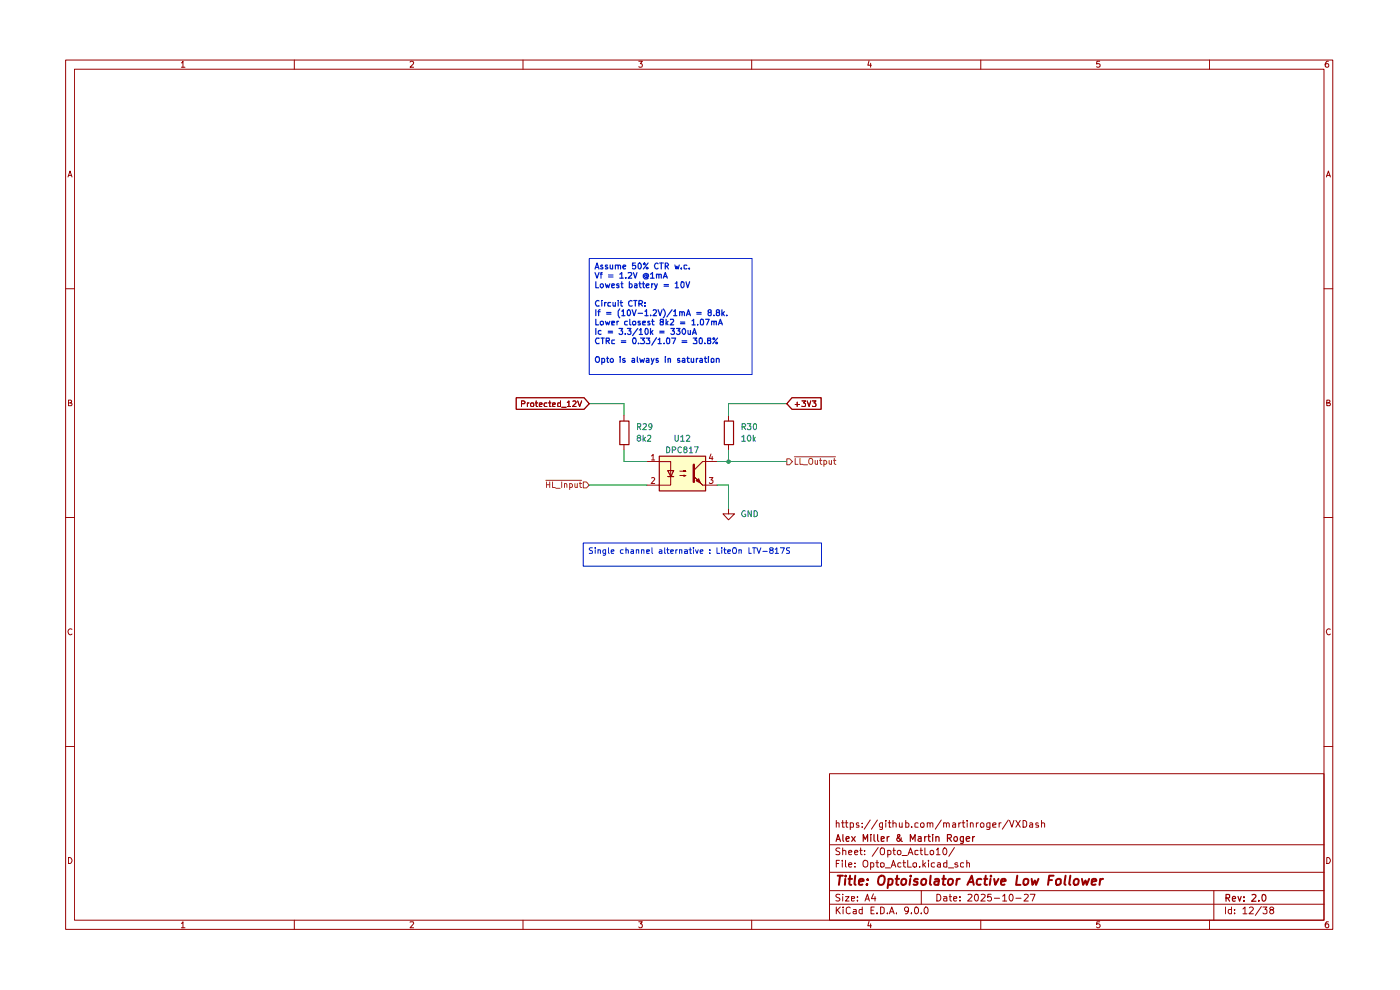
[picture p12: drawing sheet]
<svg xmlns="http://www.w3.org/2000/svg" width="297mm" height="210mm" viewBox="0 0 297 210" stroke-linecap="round" stroke-linejoin="round" font-family="sans-serif">
<g fill="none" stroke="#980000" stroke-width=".21">
<path d="M13.9 12.7h268.8v184.4h-268.8zM15.8 14.7h265.1v180.5h-265.1zM38.5 13.3h.1l.2-.3v1.3M38.5 14.3h.7M62.4 12.7v2M87 13.2l.5-.2 .3 .2-.1 .4-.7 .7h.8M111 12.7v2M135.5 13h.8l-.5 .5 .4 .1v.6h-.7M159.5 12.7v2M184.4 12.9l-.3 .9h.8M184.7 13.4v.9M208.1 12.7v2"/>
<path d="M233.3 13h-.6l-.1 .6h.7v.6h-.7M256.6 12.7v2M281.8 13a.71 .71 0 0 0-.7 .5 .71 .71 0 0 0 .3 .8l.4-.1v-.6l-.4-.1-.3 .3M14.4 37.5l.5-1.2 .4 1.2M14.5 37.2h.7M281.4 37.5l.4-1.2 .4 1.2M281.5 37.2h.6M13.9 61.3h1.9M280.9 61.3h1.8M14.5 85.5h.4l.3-.3-.2-.3h-.5v1.2h.6l.2-.5-.4-.1M281.5 85.5h.4l.2-.3-.1-.3h-.5v1.2h.6l.1-.5-.3-.1M13.9 109.8h1.9"/>
<path d="M280.9 109.8h1.8M15.3 133.5a.59 .59 0 0 0-.9 .5 .59 .59 0 0 0 .8 .6l.1-.1M282.2 133.5a.59 .59 0 0 0-.8 .5 .59 .59 0 0 0 .7 .6l.1-.1M13.9 158.4h1.9M280.9 158.4h1.8M176 164.1h104.9v31.1h-104.9zM176 179.2h104.9M177.4 174.7l.2-.2 .4 .1v.9M177.4 174v1.5M178.2 180l-.6-.1-.3 .2 .1 .4 .8 .4-.1 .3h-.8M178.5 174.5h.6M178.8 174v1.5h.3"/>
<path d="M178.8 179.9v1.4M179.4 174.5h.5M179.5 174v1.3l.1 .2h.3M180.4 174.6l.4-.1 .3 .2v.7l-.7 .1M180.4 174.5v1.5M182.2 174.6l-.4-.1-.2 .2 .2 .3h.4v.5h-.6M182.6 179.9v1.2l.3 .2M182.9 175.4v.1M182.9 174.6v.1M184.6 173.9l-1.3 2M186.1 173.9l-1.2 2M186.3 179.8l-1.3 1.8"/>
<path d="M186.9 180l.4-.1 .3 .1 .1 .8-.1 .3-.3 .2-.5-.2-.1-.7zM187.2 174.5v1.2a.36 .36 0 0 1-.6 .2M187.2 174.6l-.4-.1-.2 .3v.6l.6 .1M187.9 174v.2M187.9 174.5v1M188.4 174.5h.6M188.7 174v1.5h.3M189.4 174.7l.3-.2 .4 .2v.8M189.4 174v1.5M189.6 179.9v1.2l.3 .2M190.8 174.5l.1 1 .5-.1M191.4 174.5v1"/>
<path d="M192.1 174v1.5l.6-.1 .1-.6a.45 .45 0 0 0-.7-.2M193.4 175.4v.1M194.8 174.6l-.5-.1-.2 .2v.7l.7 .1M195.3 174.8a.45 .45 0 0 1 .7-.2v.9l-.6-.1zM195.4 179.9v1.2l.3 .2M196.2 179.9v1.4h.7M196.7 174.7l.2-.2 .4 .2v.8M196.7 174.5v1M197.3 174.7l.2-.2 .4 .1v.9M199.7 173.9l-1.3 2M200.2 180l.2-.1a.75 .75 0 0 1 .5 .7 .75 .75 0 0 1-.5 .7l-.4-.5zM200.2 174.7l.2-.2 .4 .2v.8"/>
<path d="M200.2 174.5v1M200.8 174.7l.2-.2 .4 .2v.8M202.1 174.6l.4-.1 .2 .2v.8h-.6v-.4l.6-.2M202.5 179.8l-1.2 1.8M203.4 174.5v1M203.8 174.5l-.4 .3M204.1 174.5h.6M204.3 174v1.3l.1 .2h.3M205.2 174v.2M205.2 174.5v1M205.9 174.7l.1-.2 .5 .2v.8M205.9 174.5v1"/>
<path d="M207.1 174.5v1M207.6 174.5l-.5 .3M208.2 174.5h.3l.2 .3-.1 .7h-.5l-.1-.3v-.4zM210 174.5v1.2l-.2 .3-.5-.1M210 174.6l-.4-.1-.3 .2v.7l.7 .1M210.6 175l.7-.1v-.3l-.4-.1-.3 .2 .1 .8h.6M212 174.5v1M212.4 174.5l-.4 .3M213.9 173.9l-1.3 2M214.2 174l.5 1.5 .4-1.5M215.5 174l.9 1.5M216.4 174l-.9 1.5"/>
<path d="M217 174h.4l.4 .4v.7l-.3 .4h-.5zM218.5 174.6l.4-.1 .2 .2v.8h-.6l-.1-.4 .7-.2M220.3 174.6h-.6v.4h.6v.2v.3h-.6M220.9 174.7l.3-.2 .4 .2v.8M220.9 174v1.5M14.5 181.9a.65 .65 0 0 1 .8 .6 .65 .65 0 0 1-.8 .7zM38.5 195.9l.3-.4v1.3M38.5 196.8h.7M62.4 195.2v1.9M87 195.6l.7-.1 .1 .3-.8 1h.8M111 195.2v1.9M135.5 195.5h.8l-.5 .5 .5 .2-.1 .5-.5 .1-.2-.2"/>
<path d="M159.5 195.2v1.9M176 191.8h104.9M176 188.9h104.9M176 185h104.9M177.4 192.4v1.4M177.4 183.2h.5M177.6 193l.7 .8M178.1 182.5h-.7v1.4M178.2 189.8h-.8l-.1 .3 .8 .4 .1 .4-.3 .2-.6-.1M178.3 192.4l-.9 .8M178.7 182.5v.2M178.7 183v.9"/>
<path d="M178.8 189.7v.1M178.8 180.5l.4-.1 .2 .1v.8M178.8 190.2v.9M178.9 192.4v.2M178.9 192.9v.9M179.4 190.2h.7l-.7 .9h.7M179.4 182.5v1.3l.1 .1M180 183.4l.7-.1-.2-.3-.5 .2v.6l.3 .1 .3-.1M180 180.8l.7-.1-.2-.3-.5 .1v.6l.3 .2 .3-.1M180.4 192.6l-.4-.2-.5 .3 .1 1 .4 .1 .4-.1M180.6 190.6l.7-.1-.1-.3h-.6v.8h.6M181.1 192.9h.5v.9"/>
<path d="M181.3 180.8l.7-.1-.2-.3h-.3l-.2 .1v.6l.2 .2 .4-.1M181.4 183.8v.1M181.4 183.1v.1M181.6 193.2l-.5 .1-.1 .2 .1 .3h.5M181.9 191v.1M181.9 190.2v.2M182.4 180.4h.5M182.9 192.9h-.5l-.2 .7a.45 .45 0 0 0 .7 .2M182.9 192.4v1.4M183.2 182.7l.5-.2a.75 .75 0 0 1 .4 .8 .75 .75 0 0 1-.7 .6l-.1-.1a.99 .99 0 0 1-.1-1.1zM183.4 181.2v.1M183.4 180.5h.1"/>
<path d="M183.5 191.1l.5-1.4 .4 1.4M183.7 190.7h.7M184.4 195.4l-.3 1h.8M184.7 183.1l.4-.1 .3 .3-.1 .5h-.6M184.7 183v1.4M184.7 196v.8M184.8 193.1h.5M185.3 189.6l-.4 1h.9M185.5 192.4h-.7v1.4h.7M185.6 190.2v.9M185.8 183h.6M186 193.7v.1"/>
<path d="M186 182.5v1.3l.4 .1M186.8 192.4h.4l.4 .3v.8l-.4 .3h-.4zM186.8 183.1h.7v.7h-.7zM187.8 184.1h1.1M188.3 193.7v.1M188.3 180.5l.4-.1 .3 .2-.1 .6h-.6M188.3 180.4v1.4M188.7 193.8l.5-1.4 .5 1.4M188.8 193.4h.7M189.1 183.9l.4-1.4 .5 1.4M189.2 183.5h.7M189.4 180.4h.5"/>
<path d="M190.2 193.7v.1M190.5 180.5h.5v.7h-.5zM191.1 183.1l-.4-.1-.2 .3v.5h.6M191.4 181.5h1.1M191.6 183h.5M191.7 182.5v1.3l.4 .1M192.6 182.5v1.4h.7M192.7 181.3l.5-1.4 .5 1.4M192.7 193l-.2 .3h-.4l-.2-.3v-.3l.2-.3h.4l.2 .3v.8l-.2 .3h-.4M192.8 180.9h.7M193.3 193.7v.1M193.8 183.1h.6v.7h-.6z"/>
<path d="M194.1 192.6l.2-.2a.75 .75 0 0 1 .6 .7 .75 .75 0 0 1-.6 .7l-.2-.1-.1-.4zM194.8 180.5h-.7v.7h.7M195.1 183.8v.1M195.2 180.4h.5M195.4 193.7v.1M195.4 188.9v2.9M195.8 182.5v1.4M196 183.4l.4 .5M196.4 192.4h.1a.8 .8 0 0 1 .4 .8 .8 .8 0 0 1-.5 .6 .89 .89 0 0 1 0-1.4zM196.4 183l-.6 .5M197 182.5v.2M197 183v.9"/>
<path d="M197.4 180.5h.6v.7h-.6zM198.2 183.1l-.3-.1-.3 .3v.5h.6M198.7 180.3l.3-.4v1.4M198.7 181.3h.7M198.7 189.7a.73 .73 0 0 1 .9 .7 .73 .73 0 0 1-.9 .7zM198.9 183.1l.4-.1 .2 .2v.7M199.5 183.3l-.6 .1-.1 .2 .2 .3 .5-.1M200.2 190.2h.6l.1 .9M200.9 190.5l-.7 .1v.4h.7M200.9 183.1h-.7v.7h.7M200.9 182.5v1.4M201.2 184.1h1.1"/>
<path d="M201.4 190.2h.5M201.5 189.7v1.3l.4 .1M202.3 190.6l.7-.1-.1-.3h-.5l-.1 .2v.6l.2 .1 .4-.1M203.2 183.1l-.4-.1-.2 .3v.1l.6 .1v.3l-.2 .1-.4-.1M203.7 191v.1M203.7 190.2v.2M204.4 183.1l-.4-.1-.3 .3 .1 .5h.6M205.1 183.1l.4-.1 .2 .2v.7M205.1 182.5v1.4M205.4 189.8l.5-.1 .3 .4-.9 1h.9M206.9 189.8h.5a1.01 1.01 0 0 1-.2 1.3 .87 .87 0 0 1-.3-1.3zM208.1 195.2v1.9"/>
<path d="M208.1 189.8h.8l.1 .3-.9 1h.9M210.3 189.7h-.7l-.1 .7 .6-.2 .2 .3v.4l-.2 .2-.6-.1M210.9 190.5h1.1M212.7 190.1l.4-.4v1.4M212.7 191.1h.9M214.2 189.8l.2-.1a.76 .76 0 0 1 .5 .7 .76 .76 0 0 1-.5 .7 1.01 1.01 0 0 1-.2-1.3zM215.5 190.5h1.1M217.3 189.8h.8v.3l-.9 1h.9M218.6 189.7h1l-.6 1.4M233.3 195.5h-.6l-.1 .6 .2-.1h.3l.3 .2v.3l-.3 .3h-.3l-.2-.2M256.6 195.2v1.9M257.5 188.9v6.3"/>
<path d="M260 192.4v1.4M261.2 192.9h-.5l-.1 .3v.4l.2 .2h.4M261.2 192.4v1.4M261.9 193.7v.1M261.9 192.9v.2M263.7 192.8l.4-.4v1.4M263.7 193.8h.8M265 192.6l.6-.2 .3 .4-.9 1h.9M267.6 192.3l-1.3 1.9M267.9 192.4h.9l-.5 .5 .5 .2v.6l-.3 .1h-.4l-.2-.1M269.6 193l-.2-.3 .2-.3 .6 .3-.1 .2-.2 .1a.47 .47 0 0 0-.5 .6l.2 .2a.45 .45 0 0 0 .5-.1 .45 .45 0 0 0 0-.5l-.2-.2M281.5 181.9a.65 .65 0 0 1 .7 .6 .65 .65 0 0 1-.7 .7z"/>
<path d="M281.8 195.5h-.4l-.3 .5v.5l.3 .3 .4-.1v-.7h-.4l-.3 .2"/>
</g>
<g fill="none" stroke="#980000" stroke-width=".25">
<path d="M177.4 178.5l.4-1.5 .5 1.5M177.5 178h.6M178.8 177v1.2l.2 .3M179.5 178l.7-.2-.2-.3h-.4l-.1 .7 .2 .3 .4-.1M180.7 177.5l.7 1M181.4 177.5l-.7 1M183.1 178.5v-1.5l.5 1 .5-1v1.5M184.7 177v.1M184.7 177.5v1M185.4 177v1.2l.3 .3M186.2 177v1.2l.2 .3M186.9 178l.7-.2-.1-.3h-.6v.9h.6"/>
<path d="M188.2 177.5v1M188.6 177.5l-.4 .3M191.2 177.7v.3l-.5 .5a.43 .43 0 0 1-.4-.2 .43 .43 0 0 1 0-.5l.6-.5-.1-.3h-.3a.55 .55 0 0 0 .2 .8l.7 .7M193.1 178.5v-1.5l.5 1 .5-1v1.5M194.8 177.5h.6v1M195.4 177.8l-.4 .1-.3 .2 .3 .4 .4-.1M196.2 177.5v1M196.5 177.5h-.2l-.1 .3M196.8 177.5h.6M197 177v1.2l.4 .3M197.9 177v.1M197.9 177.5v1"/>
<path d="M198.5 177.6l.1-.1a.36 .36 0 0 1 .6 .2v.8M198.5 177.5v1M201 177.8l.7-.1 .1-.2v-.4l-.8-.1v1.5M201.3 177.8l.5 .7M204.4 177.5v1.1l-.2 .3h-.4M204.4 177.5h-.4l-.3 .3 .1 .6h.6M205 178l.7-.2-.1-.3h-.4l-.2 .2 .1 .7h.5M206.3 177.5v1M206.8 177.5l-.5 .3M260.1 190.5l.7-.1 .1-.6-.8-.1v1.5M260.4 190.5l.5 .7M261.4 190.7l.7-.1-.1-.4h-.5l-.1 .7 .2 .3 .4-.1"/>
<path d="M262.6 190.2l.4 1 .3-1M263.9 191v.2M263.9 190.2v.2M265.6 189.8l.6-.1 .2 .5-.9 1h.9M267 191v.2M267.8 189.8l.2-.1a.75 .75 0 0 1 .6 .8 .75 .75 0 0 1-.6 .7l-.2-.2-.1-.4z"/>
<circle cx="202.7" cy="178" r=".48"/>
</g>
<g fill="none" stroke="#980000" stroke-width=".42">
<path d="M177.7 185.8h1.1M178.2 185.8l-.2 1.9M179.3 186.4l-.1 1.3M179.4 185.8v.1M180 186.4h.8M180.3 185.8l-.1 1.6 .4 .3M181.4 185.8l-.1 1.6 .2 .3M182.2 187l1-.1-.1-.4a.6 .6 0 0 0-.8 .2v.9h.7M184 187.5l-.1 .2-.1-.1 .2-.1-.1 .2M184.1 186.5v.2M186.5 186a.7 .7 0 0 1 1.1 0 1.36 1.36 0 0 1-.6 1.7l-.5-.1a1.33 1.33 0 0 1 0-1.6zM188.5 186.5a.6 .6 0 0 1 .9 .3l-.3 .8h-.7"/>
<path d="M188.5 186.4l-.2 2M190 186.4h.7M190.3 185.8l-.1 1.6 .4 .3M191.3 186.6l.4-.2 .5 .2-.1 .9-.3 .2-.5-.2zM193.1 186.4l-.2 1.3M193.2 185.8v.1M194.7 186.5l-.5-.1-.3 .4 .2 .2 .5 .1v.5h-.8M195.6 186.6l.3-.2 .4 .1 .2 .3-.1 .6a.55 .55 0 0 1-.5 .3 .55 .55 0 0 1-.5-.3zM197.4 185.8l-.1 1.6 .2 .3M198.4 186.5h.7l-.1 1.2M199.2 186.9h-.7l-.3 .3 .1 .4h.7M199.9 186.4h.8"/>
<path d="M200.2 185.8l-.1 1.8 .4 .1M201.2 186.6l.6-.2 .4 .4-.1 .6-.4 .3-.5-.1-.1-.2zM203 186.4l-.1 1.3M203.6 186.4h-.2l-.5 .4M205.2 187.7l1-1.9 .4 1.9M205.5 187.1h.9M208.2 186.5l-.5-.1-.4 .4v.7l.2 .2 .5-.1M208.8 186.4h.7M209.1 185.8l-.2 1.6 .1 .2 .4 .1M210.1 186.4l-.1 1.3M210.2 185.8v.1M210.9 186.4l.3 1.3 .6-1.3"/>
<path d="M212.3 187l1.1-.1-.1-.4a.6 .6 0 0 0-.9 .2v.9h.7M215.8 185.8l-.2 1.9h.9M217.2 186.6l.3-.2 .5 .1 .2 .3-.1 .6a.65 .65 0 0 1-.9 .2zM218.9 186.4l.1 1.3 .5-.9 .3 .9 .5-1.3M222.5 186.7h.7M223.5 185.8h-.9l-.3 1.9M224 186.8a.63 .63 0 0 1 1-.2v.8a.63 .63 0 0 1-1 .1zM226.1 185.8l-.3 1.6 .3 .3M227.1 185.8l-.3 1.6 .3 .3M227.8 186.8l.5-.4 .4 .1 .1 .3v.6a.55 .55 0 0 1-.5 .3 .55 .55 0 0 1-.6-.3zM229.5 186.4l.3 1.3 .5-.9 .2 .9 .5-1.3M231.6 187l1-.1-.1-.4a.6 .6 0 0 0-.9 .2v.9h.8"/>
<path d="M233.4 186.4l-.1 1.3M234 186.4l-.4 .1-.2 .3"/>
</g>
<path d="M139.8 96.7h9.8v7.4h-9.8z" fill="#fffec7"/>
<g fill="none" stroke="#980000" stroke-width=".21">
<path d="M132.4 88.1v1.2M132.4 94.3v1.2M139.8 97.9h2.5v3.2M144.2 99.9h1.3l-.4 .1v-.2l.4 .1M149.1 97.9l-1.9 1.9M154.6 88.1v1.2M154.6 94.3v1.2M168 84.4h6.2v2.4h-6.2l-1.1-1.2zM168.7 85.8h.9M169.1 85.3v.9M170.1 85h.8l-.4 .5 .4 .2v.4l-.2 .1-.6-.1M171.2 85l.5 1.2 .3-1.2"/>
<path d="M172.3 85h.8l-.4 .5 .4 .2-.1 .5-.7-.1M142.3 101v1.9h-2.5M144.2 100.9h1.3l-.4 .1v-.2l.4 .1M154.6 107.8v1.2h1.2l-1.2 1.3-1.2-1.3h1.2M154.6 107.8h.1"/>
</g>
<path d="M131.5 89.3h1.9v5h-1.9zM139.9 96.8h9.8v7.3h-9.8zM141.6 99.8h1.3l-.6 1.3zM153.7 89.3h1.9v5h-1.9zM141.6 101.1h1.3" fill="none" stroke="#980000" stroke-width=".25"/>
<path d="M147.2 98.6v3.6" fill="none" stroke="#980000" stroke-width=".51"/>
<path d="M147.7 102l.5-.4 .4 .9z" fill="#980000"/>
<path d="M149.1 97.9h.5M147.7 102l.5-.4 .4 .9z" fill="none" stroke="#980000" stroke-width=".21"/>
<path d="M147.2 101l1.9 1.9z" fill="#980000"/>
<g fill="none" stroke="#980000" stroke-width=".21">
<path d="M109.5 84.4h14.4l1.1 1.2-1.1 1.2h-14.4zM110.6 85.6h.6l.2-.1-.1-.4-.7-.1v1.2M111.9 85.5v.7M112.2 85.5h-.2l-.1 .1M112.6 85.6l.1-.1h.5v.7h-.5l-.1-.1zM113.6 85.5h.5M113.7 85v1.1l.1 .1h.3M114.4 85.9l.6-.2-.1-.2h-.4l-.1 .1 .1 .6h.4M116 85.5h-.4l-.2 .1v.5l.2 .1h.4M116.4 85.5h.5M116.6 85v1.2h.3M117.2 85.9l.6-.2-.1-.2h-.4l-.1 .1 .1 .6h.4"/>
<path d="M118.9 85v1.2h-.5l-.1-.7h.6M119.2 86.4h.9M120.3 85.4l.4-.4v1.2M120.3 86.2h.7M121.5 85.1l.5-.1 .2 .4-.8 .8h.8M122.5 85l.5 1.2 .4-1.2M137.3 97.9h2.5M149.6 97.9h2.5M137.3 102.9h2.5M147.2 101l1.9 1.9h3"/>
</g>
<path d="M138.2 96.7l.4-.3v1.2M138.2 97.6h.7M150.8 96.3l-.3 .9h.8M151.1 96.8v.8M138.2 101.4l.4-.1 .3 .3-.8 1h.8M150.5 101.3h.8l-.5 .5 .5 .2v.3l-.3 .3h-.3l-.2-.2" fill="none" stroke="#bd0000" stroke-width=".21"/>
<path d="M123.7 102.2h.7l.6 .7-.6 .6h-.7z" fill="#fff"/>
<g fill="none" stroke="#805e00" stroke-width=".21">
<path d="M115.8 101.9h7.6M115.9 102.2v1.2M115.9 102.8h.7M116.6 102.2v1.2M117.2 102.2v1.2h.6M117.9 103.6h.9M119.2 102.2v1.2M119.8 102.7l.1-.1 .3 .1 .1 .7M119.8 102.6v.8M120.9 102.7l.3-.1 .2 .2v.5h-.5M120.9 102.6v1.2M122 102.6v.6l.1 .2 .4-.1"/>
<path d="M122.5 102.6v.8M122.9 102.6h.5M123.1 102.2v1l.3 .2M123.7 102.2h.7l.6 .7-.6 .6h-.7z"/>
</g>
<path d="M166.9 97.3h.6l.6 .6-.6 .7h-.6z" fill="#fff"/>
<g fill="none" stroke="#805e00" stroke-width=".21">
<path d="M166.9 97.3h.6l.6 .6-.6 .7h-.6zM168.5 96.9h8.7M168.7 97.2v1.3h.6M169.7 97.2v1.3h.6M170.4 98.6h.9M171.7 97.4l.5-.2a.86 .86 0 0 1 0 1.3 .46 .46 0 0 1-.6-.4zM172.9 97.7v.6l.2 .2 .3-.1M173.4 97.7v.8M173.9 97.7h.5M174 97.2v1.1l.4 .2M174.8 97.7h.3l.3 .2-.1 .5h-.5M174.8 97.7v1.2"/>
<path d="M175.9 97.7v.6l.2 .2 .3-.1M176.4 97.7v.8M176.8 97.7h.5M177 97.2v1.1l.3 .2"/>
</g>
<path d="M125 85.6h7.4v2.5M132.4 95.5v2.4h4.9M152.1 97.9h14.8M154.6 95.5v2.4M166.9 85.6h-12.3v2.5M125 102.9h12.3M152.1 102.9h2.5v4.9" fill="none" stroke="#00a200" stroke-width=".21"/>
<g fill="none" stroke="#001dcd" stroke-width=".25">
<path d="M126.2 57.1l.5-1.3 .4 1.3M126.2 57.8l.5 1.2 .4-1.2M126.3 56.7h.6M126.4 59.8v1.2h.6M127.3 58.2h.5M127.8 57.8h-.3v1.2M127.8 56.3l-.2-.1-.2 .3 .5 .4-.1 .2-.4-.1M128.9 56.3h-.5v.3h.4l.1 .3-.1 .2-.4-.1M129.1 58.3h.9M129.1 58.8h.9M129.4 56.2v.7l.2 .2 .4-.2M130 56.2v.9"/>
<path d="M130.6 56.3l.4-.1 .1 .2v.7M130.6 56.2v.9M131.1 56.4l.2-.2 .4 .2v.7M131.5 58.2l.4-.4v1.2M131.5 59h.7M131.9 59.8v1.2h.3M132.2 56.6l.6-.1-.2-.3-.4 .2v.5l.1 .2 .4-.1M132.8 58.9v.1M133.3 57.9l.6-.1 .1 .2-.1 .3-.6 .7h.7M133.5 59.8v1.2M134.4 57.8l.4 1.2 .3-1.2M134.8 55.8h-.6v.6l.6-.1v.7l-.4 .1-.2-.2"/>
<path d="M135.6 55.8a.68 .68 0 0 1 .5 .6 .68 .68 0 0 1-.5 .7l-.2-.3v-.8zM135.7 59.8v1l.4 .2M136.5 56l.2-.2 .2 .2-.1 .1h-.2zM136.5 59.8v1.2h.2M137.2 56.7h.2l.1 .2-.3 .2-.1-.2zM137.2 58.4l-.3-.1-.2 .3 .3 .3 .2-.1M137.2 58.3v.5h.2l.2-.1-.1-.5a.66 .66 0 0 0-1 .1v.5l.3 .4 .7-.2M137.5 55.8l-1 1.3M138 58.2l.4-.4v1.2M138 59h.8M139.3 58.3l.1-.1h.4v.8M139.3 58.2v.8"/>
<path d="M139.6 56l-.2-.2a.65 .65 0 0 0-.6 .6 .65 .65 0 0 0 .6 .7l.2-.2M139.8 58.3l.1-.1h.4v.8M139.9 55.8h.8M140.3 55.8v1.3M140.7 59l.4-1.2 .5 1.2M140.9 58.7h.6M141.1 56.5h.5l.2-.3-.2-.4h-.5v1.3M141.4 56.5l.4 .6M143.2 56.2l.2 .9 .2-.6 .2 .6 .3-.9M144.5 56.9v.2M144.5 59.9l.4-.1 .2 .2v.8l-.2 .2-.4-.1zM145.5 59.8l.4 1.2 .4-1.2"/>
<path d="M145.7 56.3h-.6v.6l.2 .2 .4-.1M146.2 56.9v.2M126.4 67.7v1.2h.6M126.4 65.7v1.3M126.4 69.7v1.2M126.8 66.1h.5M127.1 63.8a.61 .61 0 0 0-.8 .3 .61 .61 0 0 0 .3 .8l.5-.1M127.1 71.8l-.5-.1-.3 .5 .3 .7 .5-.1M127.3 65.7l-.3 .2v1.1M127.3 68.3l.2-.1h.3l.2 .1v.4l-.2 .2h-.3l-.2-.2zM127.4 60.3l.4-.1 .2 .2v.4l-.2 .2-.5-.2zM127.5 70.2l-.3-.1-.3 .3v.3l.3 .2h.3"/>
<path d="M127.5 71.7h.7M127.7 63.7v.1M127.7 76.1l.4-.1 .2 .2v.6h-.6M127.7 64.2v.7M127.7 76v1.3M127.8 71.7v1.2M128.3 64.2v.7M128.4 60.2l.3 .8 .2-.6 .2 .6 .3-.8M128.4 68.2l.3 .7 .2-.6 .2 .6 .3-.7M128.6 64.2h-.3v.2M128.6 72.3h.6v-.6h-.6v1.2M128.7 66.3h.9"/>
<path d="M128.7 66.6h.9M128.7 76h.4M128.9 75.7v1.1l.2 .1M128.9 72.3l.4 .6M129 70.3h1M129 70.6h1M129.4 76.3l.5-.3 .2 .3-.1 .5h-.5zM129.5 64.2h-.5l-.1 .2 .1 .5h.5M129.8 60.6l.6-.2-.2-.2-.4 .1v.7h.5M129.8 68.5l.6-.1-.1-.2h-.5v.7h.5M130 64.2l.1 .7 .5-.1M130.4 72.1l-.6 .1v.6l.6 .1"/>
<path d="M130.6 64.2v.7M130.9 68.2v.7M131.1 63.7v.1M131.1 64.2v.7M131.2 68.2h-.2l-.1 .1M131.3 60.3l-.3-.1-.2 .2 .2 .2h.3v.4h-.5M131.3 69.7h.8l-.4 .5 .4 .1v.5l-.2 .1h-.4l-.2-.1M131.5 65.5l-.4 .5v.9l.4 .5M131.6 75.7v.1M131.6 64.2h.5M131.6 76v.9M131.7 63.7v1.1l.1 .1h.3"/>
<path d="M131.7 60.2h.5M131.8 72.3h1M131.8 72.6h1M131.9 66l.3-.3v1.3M131.9 67h.7M132.6 76.1l-.3-.1-.2 .3 .1 .1h.3l.2 .3-.2 .2-.4-.1M132.7 70.8v.1M133.1 68.2h-.4l-.2 .1v.4l.2 .2h.4M133.1 69.7h.8l-.5 .5 .5 .1v.5l-.3 .1h-.3l-.2-.1M133.3 65.7a.68 .68 0 0 1 .5 .6 .68 .68 0 0 1-.5 .7l-.2-.3v-.8zM133.5 60.3l.4-.1 .2 .2-.1 .6h-.5M133.6 67.7v1l.3 .2"/>
<path d="M134.1 63.8l-.2-.1a.67 .67 0 0 0-.6 .6 .67 .67 0 0 0 .3 .6l.5-.1M134.1 65.7l.4 1.3 .5-1.3M134.1 76.1h.5v.8M134.2 68.3l.2-.1h.4v.7h-.4l-.2-.2zM134.4 71.7l.4 .1a.87 .87 0 0 1 0 1.1l-.4-.1a.94 .94 0 0 1 0-1.1zM134.4 63.7h.7M134.6 60.3h.5v.7M134.6 76.4h-.5l-.1 .2 .2 .3 .4-.1M134.8 63.7v1.2M135.1 60.4l-.5 .2v.4h.5M135.2 75.7v1l.2 .2M135.3 69.7l-1.1 1.5"/>
<path d="M135.4 66.5h.9M135.5 72.8v.1M135.5 64.4h.6l.2-.2-.1-.4-.7-.1v1.2M135.5 60.2h.6M135.6 70l.4-.3v1.2M135.6 70.9h.7M135.7 76l.3 .9 .2-.6 .3 .6 .2-.9M135.8 68.2h-.4v.3h.3l.2 .2-.1 .2h-.4M135.9 71.7h.8l-.4 .4 .4 .3-.1 .4h-.7M135.9 64.4l.4 .5M136.3 68.5l.6-.1v-.2h-.5l-.1 .1 .1 .6h.5M136.3 60.2h.4"/>
<path d="M136.8 64.8v.1M136.8 64.2v.1M136.8 66l.4-.3v1.3M136.8 67h.7M137.1 60.6l.6-.2v-.1l-.5-.1-.1 .2 .1 .6h.5M137.1 69.7l.4 .2v.8l-.3 .2a.75 .75 0 0 1-.1-1.2zM137.1 71.7h.7l-.3 .4 .3 .2v.5h-.7M137.2 76.1h.5v.8M137.7 76.4h-.5l-.1 .2 .1 .3 .5-.1M137.8 68.2h-.3l-.1 .1 .4 .3v.3h-.4M138 66.9v.1M138 69.7v1.2"/>
<path d="M138.2 70.4l.3 .5M138.2 76l.2 .9M138.3 60.2v.8M138.3 68.2h.5M138.4 67.7v1l.1 .2h.3M138.5 70.1l-.5 .5M138.6 60.2l-.3 .1v.1M138.6 65.9l.4-.2 .3 .3-.8 1h.8M138.8 76l-.5 1.2-.1 .1M138.8 60.2l.4 .8M139.3 71.6l-1 1.6M139.4 60.2l-.2 .8-.2 .4h-.2"/>
<path d="M139.6 65.7l.4 1.3 .5-1.3M139.6 72l.3-.3v1.2M139.6 76.1h-.4v.3h.3l.2 .3-.2 .2-.3-.1M139.6 72.9h.7M139.9 70.3h1M139.9 70.6h1M140.3 68.2l-.3-.2 .1-.3h.5l.1 .5h-.4l-.3 .3 .1 .4 .6-.1v-.5l-.2-.1M140.7 65.5a1.26 1.26 0 0 1 0 1.9M140.9 72.8v.1M140.9 60.4h.9M140.9 60.7h.9M141.1 75.7v.1"/>
<path d="M141.1 76v.9M141.3 67.7v1.2M141.4 68.5l.3 .4M141.5 71.8l.4-.1 .2 .2v.7l-.2 .3-.4-.1zM141.7 76.2l.2-.2 .3 .1v.8M141.7 68.2l-.4 .4M141.7 76v.9M142.2 67.8l.6-.1 .1 .4-.8 .8h.8M142.3 69.7h.8l-.4 .5h.3v.7h-.5l-.2-.1M142.5 71.7h.8l-.5 1.2M142.6 65.7l-1.1 1.5M142.9 66l.4-.3v1.3"/>
<path d="M142.9 67h.7M143.3 60.1l.3-.3v1.2M143.3 61h.6M143.5 69.7h.8l-.5 .5h.4v.7h-.5l-.2-.1M144.2 66.3l.2-.2 .3 .2v.7M144.2 76.1h-.4v.3h.3l.2 .3-.2 .2-.3-.1M144.2 66.1v.9M144.4 68.3h.9M144.4 68.7h.9M144.7 66.3l.2-.2 .3 .2v.7M144.7 72.3h1M144.7 72.6h1"/>
<path d="M144.8 76.1h.5v.8M145 69.7a.68 .68 0 0 1 .5 .6 .68 .68 0 0 1-.5 .6 .75 .75 0 0 1 0-1.2zM145.3 76.4h-.5l-.1 .2 .2 .3 .4-.1M145.6 67l.4-1.3 .5 1.3M145.7 66.6h.6M145.7 76h.5M145.9 75.7v1l.3 .2M146 70.1v.7l.1 .1 .4-.1M146.5 70.1v.8M146.6 76v.8h.5M146.8 68.1l.3-.4v1.2M146.8 68.9h.7"/>
<path d="M146.9 70.9l.4-1.2 .4 1.2M147.1 71.7h.7l-.4 .4 .4 .2v.5h-.7M147.1 70.6h.5M147.1 76v.9M147.7 76v.9M147.8 66.3h1M147.8 66.6h1M148 68.8v.1M148.1 76l-.4 .3M148.5 71.7l.4 .1 .1 .7-.2 .4h-.3l-.2-.3v-.7zM148.5 76.1l.3-.1 .2 .2v.7M148.7 67.8h.5l.1 .7-.2 .4h-.3l-.2-.2z"/>
<path d="M149 76.4h-.5l-.1 .2 .2 .3 .4-.1M149.4 76h.5M149.5 72.8v.1M149.6 75.7v1l.3 .2M149.7 67.7h.7l-.5 1.2M150.3 72.2l-.2-.1v-.3l.6-.1v.4l-.6 .2 .1 .6 .5-.1a.36 .36 0 0 0-.2-.6M150.3 75.7v.1M150.3 76v.9M150.4 66.3l-.2-.4 .1-.1 .4-.1 .2 .4-.2 .2h-.4l-.1 .2v.2l.2 .3 .5-.1v-.5l-.2-.1M150.9 76.2l.1-.2 .5 .2v.6h-.6zM151 68.2h.5v.7M151 68.2v.7"/>
<path d="M151.3 71.7h.2l.1 .2-.1 .1-.3-.1zM151.5 66.9v.1M151.5 68.3v-.1h.5v.7M151.8 72.7l.2-.1 .2 .1-.1 .2h-.2zM152 76.2l.2-.2 .4 .2v.7M152 76v.9M152.2 66.3l-.2-.2 .1-.3a.34 .34 0 0 1 .4 0 .34 .34 0 0 1 .1 .4l-.6 .2 .1 .5a.36 .36 0 0 0 .5-.2v-.4h-.2M152.2 71.7l-1 1.2M152.4 68.9l.4-1.2 .4 1.2M152.6 68.6h.6M153.2 65.7v1.3M153.3 66.5l.4 .5"/>
<path d="M153.7 66.1l-.5 .5M154.2 66.9v.1"/>
<circle cx="126.7" cy="76.2" r=".57"/>
</g>
<g fill="none" stroke="#001dcd" stroke-width=".21">
<path d="M125 54.8h34.5v24.7h-34.5zM123.7 115.2h50.6v4.9h-50.6zM125.7 116.2h-.5l-.2 .2 .3 .4 .4 .2v.3l-.7 .1M126.3 116.2v.1M126.3 116.6v.8M126.9 116.7l.4-.1 .1 .8M126.9 116.6v.8M128.5 117.4l-.5-.1-.1-.5 .2-.2h.4v1l-.3 .2-.2-.1M129.1 116.2v1l.1 .2M129.7 117l.6-.1-.1-.3h-.5v.2v.6h.5M132.2 116.6h-.4l-.2 .2 .1 .5 .5 .1M132.8 116.7l.4-.1 .1 .8"/>
<path d="M132.8 116.2v1.2M133.9 116.6h.4l.1 .2v.6h-.5v-.4l.5-.1M135 116.7l.5-.1v.8M135 116.6v.8M136.1 116.7l.5-.1v.8M136.1 116.6v.8M137.2 117l.6-.1-.1-.3h-.5v.8h.5M138.3 116.2v1l.2 .2M139.9 116.6h.4l.1 .2v.6h-.5v-.4l.5-.1M141 116.2v1.2h.2M141.4 116.6h.5M141.6 116.2v1l.1 .2h.2"/>
<path d="M142.3 117l.6-.1-.1-.3h-.4l-.1 .2 .1 .6h.4M143.4 116.6v.8M143.7 116.6l-.3 .2M144.1 116.7l.5-.1v.8M144.1 116.6v.8M145.2 116.6h.5l.1 .2v.6h-.6v-.4l.6-.1M146.2 116.6h.5M146.4 116.2v1.2h.3M147.1 116.2v.1M147.1 116.6v.8M147.5 116.6l.4 .8 .2-.8M148.5 117l.6-.1v-.3h-.5l-.1 .2 .1 .6h.5"/>
<path d="M150.6 117.3v.1M150.6 116.6v.2M152.1 116.2v1.2h.6M153.1 116.2v.1M153.1 116.6v.8M153.5 116.6h.5M153.7 116.2v1l.1 .2h.2M154.4 117l.6-.1-.1-.3h-.4l-.1 .2 .1 .6h.4M155.6 116.2h.5l.1 .2v.6l-.1 .4h-.5l-.1-.2-.1-.6zM156.8 116.7l.5-.1v.8M156.8 116.6v.8M158.9 116.2v1.2h.5"/>
<path d="M159.6 116.2h.8M160 116.2v1.2M160.6 116.2l.4 1.2 .4-1.2M161.8 117h1M163.5 116.7l-.2-.2 .1-.3h.5l.1 .2v.2a.48 .48 0 0 0-.6 .2 .48 .48 0 0 0 0 .6l.6-.1v-.3l-.2-.3M164.5 116.5l.3-.3v1.2M164.5 117.4h.6M165.6 116.2h.8l-.5 1.2M167.5 116.2h-.6a.47 .47 0 0 0 .1 .5 .47 .47 0 0 0 .4 .2v.5h-.6"/>
</g>
<g fill="none" stroke="#980000" stroke-width=".21">
<path d="M109.5 84.4h14.4l1.1 1.2-1.1 1.2h-14.4zM110.6 85.6h.6l.2-.1-.1-.4-.7-.1v1.2M111.9 85.5v.7M112.2 85.5h-.2l-.1 .1M112.6 85.6l.1-.1h.5v.7h-.5l-.1-.1zM113.6 85.5h.5M113.7 85v1.1l.1 .1h.3M114.4 85.9l.6-.2-.1-.2h-.4l-.1 .1 .1 .6h.4M116 85.5h-.4l-.2 .1v.5l.2 .1h.4M116.4 85.5h.5M116.6 85v1.2h.3M117.2 85.9l.6-.2-.1-.2h-.4l-.1 .1 .1 .6h.4"/>
<path d="M118.9 85v1.2h-.5l-.1-.7h.6M119.2 86.4h.9M120.3 85.4l.4-.4v1.2M120.3 86.2h.7M121.5 85.1l.5-.1 .2 .4-.8 .8h.8M122.5 85l.5 1.2 .4-1.2M168 84.4h6.2v2.4h-6.2l-1.1-1.2zM168.7 85.8h.9M169.1 85.3v.9M170.1 85h.8l-.4 .5 .4 .2v.4l-.2 .1-.6-.1M171.2 85l.5 1.2 .3-1.2M172.3 85h.8l-.4 .5 .4 .2-.1 .5-.7-.1"/>
</g>
<circle cx="154.6" cy="97.9" r=".47" fill="#00a200"/>
<g fill="none" stroke="#007170" stroke-width=".21">
<path d="M135.2 90.5h.6l.1-.1v-.4l-.7-.1v1.2M135.4 92.8l-.2-.2 .2-.3h.3l.2 .4-.7 .4v.2l.2 .3h.3l.2-.3v-.2l-.2-.3M135.6 90.5l.3 .6M136.4 90h.7v.4l-.7 .7h.7M136.4 92.3v1.3M136.5 93.1l.4 .5M136.9 92.7l-.5 .6M137.4 92.5l.1-.2h.4l.1 .2v.3l-.7 .8h.7M138.3 90.4a.35 .35 0 0 1-.3 .2 .35 .35 0 0 1-.4-.2v-.3a.35 .35 0 0 1 .4-.2 .35 .35 0 0 1 .3 .2v.4a.58 .58 0 0 1-.6 .6M141.4 94.8a.64 .64 0 0 1 .7 .6 .64 .64 0 0 1-.7 .6zM142.6 95.5h.5l.3-.5-.3-.2h-.5v1.2M143.2 92.3v1l.3 .3 .4-.3v-1"/>
<path d="M144.4 92.7l.4-.4v1.3M144.4 93.6h.8M144.6 94.9l-.3-.1a.65 .65 0 0 0-.5 .6 .65 .65 0 0 0 .5 .6l.3-.1M145.2 95.3l-.1-.1v-.3l.1-.1 .5 .1v.4h-.5l-.1 .2v.4l.1 .1h.5v-.2v-.3l-.2-.2M145.6 92.5l.1-.2h.4l.2 .3-.7 1h.7M146.3 95.1l.3-.3v1.2M146.3 96h.6M147.4 94.8h.7l-.5 1.2M157.3 92.7l.5-.4v1.3M157.3 93.6h.8M157.4 90.5h.5l.3-.2-.1-.3-.7-.1v1.2M157.8 90.5l.4 .6"/>
<path d="M158.5 89.9h.8l-.3 .5 .3 .1v.5l-.2 .1h-.4l-.2-.1M158.7 92.4a.61 .61 0 0 1 .7 .5 .61 .61 0 0 1-.4 .7 .71 .71 0 0 1-.3-1.2zM159.8 92.3v1.3M159.9 90l.3-.1 .3 .2v.8l-.3 .2-.3-.1zM159.9 93.1l.3 .5M160.2 92.7l-.4 .6M158.1 108.4a.59 .59 0 0 0-.8 .6 .59 .59 0 0 0 .9 .5v-.4h-.3M159.4 108.3v1.3l-.7-1.3v1.3M160 108.3a.52 .52 0 0 1 .6 .4v.6l-.6 .3z"/>
</g>
</svg>
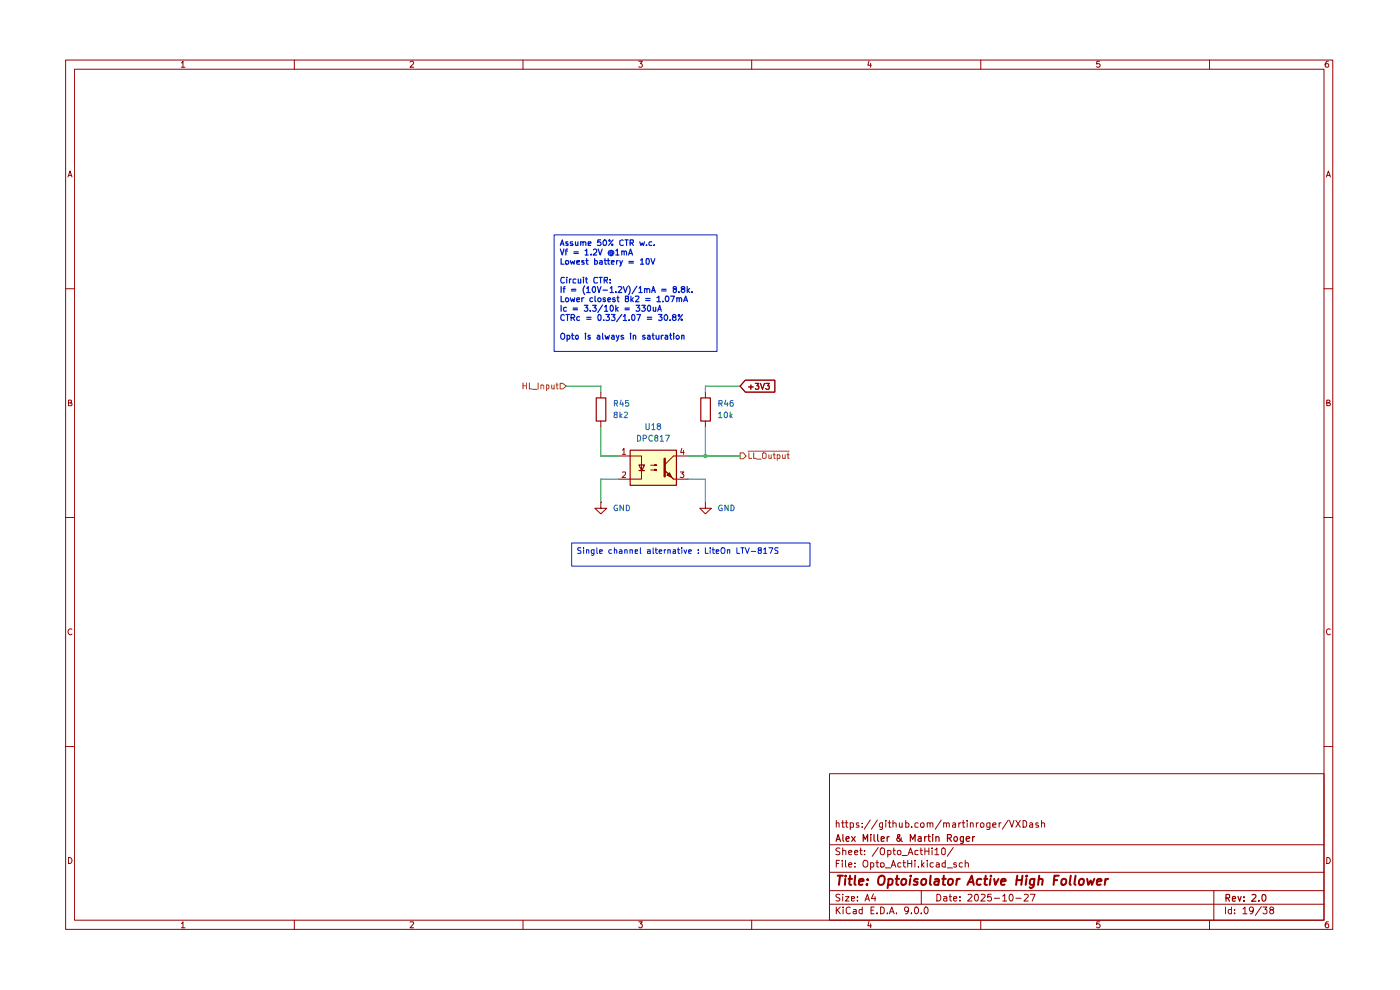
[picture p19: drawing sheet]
<svg xmlns="http://www.w3.org/2000/svg" width="297mm" height="210mm" viewBox="0 0 297 210" stroke-linecap="round" stroke-linejoin="round" font-family="sans-serif">
<g fill="none" stroke="#980000" stroke-width=".21">
<path d="M13.9 12.7h268.8v184.4h-268.8zM15.8 14.7h265.1v180.5h-265.1zM38.5 13.3h.1l.2-.3v1.3M38.5 14.3h.7M62.4 12.7v2M87 13.2l.5-.2 .3 .2-.1 .4-.7 .7h.8M111 12.7v2M135.5 13h.8l-.5 .5 .4 .1v.6h-.7M159.5 12.7v2M184.4 12.9l-.3 .9h.8M184.7 13.4v.9M208.1 12.7v2"/>
<path d="M233.3 13h-.6l-.1 .6h.7v.6h-.7M256.6 12.7v2M281.8 13a.71 .71 0 0 0-.7 .5 .71 .71 0 0 0 .3 .8l.4-.1v-.6l-.4-.1-.3 .3M14.4 37.5l.5-1.2 .4 1.2M14.5 37.2h.7M281.4 37.5l.4-1.2 .4 1.2M281.5 37.2h.6M13.9 61.3h1.9M280.9 61.3h1.8M14.5 85.5h.4l.3-.3-.2-.3h-.5v1.2h.6l.2-.5-.4-.1M281.5 85.5h.4l.2-.3-.1-.3h-.5v1.2h.6l.1-.5-.3-.1M13.9 109.8h1.9"/>
<path d="M280.9 109.8h1.8M15.3 133.5a.59 .59 0 0 0-.9 .5 .59 .59 0 0 0 .8 .6l.1-.1M282.2 133.5a.59 .59 0 0 0-.8 .5 .59 .59 0 0 0 .7 .6l.1-.1M13.9 158.4h1.9M280.9 158.4h1.8M176 164.1h104.9v31.1h-104.9zM176 179.2h104.9M177.4 174.7l.2-.2 .4 .1v.9M177.4 174v1.5M178.2 180l-.6-.1-.3 .2 .1 .4 .8 .4-.1 .3h-.8M178.5 174.5h.6M178.8 174v1.5h.3"/>
<path d="M178.8 179.9v1.4M179.4 174.5h.5M179.5 174v1.3l.1 .2h.3M180.4 174.6l.4-.1 .3 .2v.7l-.7 .1M180.4 174.5v1.5M182.2 174.6l-.4-.1-.2 .2 .2 .3h.4v.5h-.6M182.6 179.9v1.2l.3 .2M182.9 175.4v.1M182.9 174.6v.1M184.6 173.9l-1.3 2M186.1 173.9l-1.2 2M186.3 179.8l-1.3 1.8"/>
<path d="M186.9 180l.4-.1 .3 .1 .1 .8-.1 .3-.3 .2-.5-.2-.1-.7zM187.2 174.5v1.2a.36 .36 0 0 1-.6 .2M187.2 174.6l-.4-.1-.2 .3v.6l.6 .1M187.9 174v.2M187.9 174.5v1M188.4 174.5h.6M188.7 174v1.5h.3M189.4 174.7l.3-.2 .4 .2v.8M189.4 174v1.5M189.6 179.9v1.2l.3 .2M190.8 174.5l.1 1 .5-.1M191.4 174.5v1"/>
<path d="M192.1 174v1.5l.6-.1 .1-.6a.45 .45 0 0 0-.7-.2M193.4 175.4v.1M194.8 174.6l-.5-.1-.2 .2v.7l.7 .1M195.3 174.8a.45 .45 0 0 1 .7-.2v.9l-.6-.1zM195.4 179.9v1.2l.3 .2M196.2 179.9v1.4M196.7 174.7l.2-.2 .4 .2v.8M196.7 174.5v1M197.1 179.9v1.4M197.3 174.7l.2-.2 .4 .1v.9M197.7 179.9v.1M199.7 173.9l-1.3 2"/>
<path d="M200.2 174.7l.2-.2 .4 .2v.8M200.2 174.5v1M200.8 174.7l.2-.2 .4 .2v.8M202.1 174.6l.4-.1 .2 .2v.8h-.6v-.4l.6-.2M202.2 179.8l-1.2 1.8M203.4 174.5v1M203.8 174.5l-.4 .3M204.1 174.5h.6M204.3 174v1.3l.1 .2h.3M205.2 174v.2M205.2 174.5v1M205.9 174.7l.1-.2 .5 .2v.8"/>
<path d="M205.9 174.5v1M207.1 174.5v1M207.6 174.5l-.5 .3M208.2 174.5h.3l.2 .3-.1 .7h-.5l-.1-.3v-.4zM210 174.5v1.2l-.2 .3-.5-.1M210 174.6l-.4-.1-.3 .2v.7l.7 .1M210.6 175l.7-.1v-.3l-.4-.1-.3 .2 .1 .8h.6M212 174.5v1M212.4 174.5l-.4 .3M213.9 173.9l-1.3 2M214.2 174l.5 1.5 .4-1.5M215.5 174l.9 1.5"/>
<path d="M216.4 174l-.9 1.5M217 174h.4l.4 .4v.7l-.3 .4h-.5zM218.5 174.6l.4-.1 .2 .2v.8h-.6l-.1-.4 .7-.2M220.3 174.6h-.6v.4h.6v.2v.3h-.6M220.9 174.7l.3-.2 .4 .2v.8M220.9 174v1.5M14.5 181.9a.65 .65 0 0 1 .8 .6 .65 .65 0 0 1-.8 .7zM38.5 195.9l.3-.4v1.3M38.5 196.8h.7M62.4 195.2v1.9M87 195.6l.7-.1 .1 .3-.8 1h.8M111 195.2v1.9"/>
<path d="M135.5 195.5h.8l-.5 .5 .5 .2-.1 .5-.5 .1-.2-.2M159.5 195.2v1.9M176 191.8h104.9M176 188.9h104.9M176 185h104.9M177.4 192.4v1.4M177.4 183.2h.5M177.6 193l.7 .8M178.1 182.5h-.7v1.4M178.2 189.8h-.8l-.1 .3 .8 .4 .1 .4-.3 .2-.6-.1M178.3 192.4l-.9 .8M178.7 182.5v.2"/>
<path d="M178.7 183v.9M178.8 189.7v.1M178.8 180.5l.4-.1 .2 .1v.8M178.8 190.2v.9M178.9 192.4v.2M178.9 192.9v.9M179.4 190.2h.7l-.7 .9h.7M179.4 182.5v1.3l.1 .1M180 183.4l.7-.1-.2-.3-.5 .2v.6l.3 .1 .3-.1M180 180.8l.7-.1-.2-.3-.5 .1v.6l.3 .2 .3-.1M180.4 192.6l-.4-.2-.5 .3 .1 1 .4 .1 .4-.1M180.6 190.6l.7-.1-.1-.3h-.6v.8h.6"/>
<path d="M181.1 192.9h.5v.9M181.3 180.8l.7-.1-.2-.3h-.3l-.2 .1v.6l.2 .2 .4-.1M181.4 183.8v.1M181.4 183.1v.1M181.6 193.2l-.5 .1-.1 .2 .1 .3h.5M181.9 191v.1M181.9 190.2v.2M182.4 180.4h.5M182.9 192.9h-.5l-.2 .7a.45 .45 0 0 0 .7 .2M182.9 192.4v1.4M183.2 182.7l.5-.2a.75 .75 0 0 1 .4 .8 .75 .75 0 0 1-.7 .6l-.1-.1a.99 .99 0 0 1-.1-1.1zM183.4 181.2v.1"/>
<path d="M183.4 180.5h.1M183.5 191.1l.5-1.4 .4 1.4M183.7 190.7h.7M184.4 195.4l-.3 1h.8M184.7 183.1l.4-.1 .3 .3-.1 .5h-.6M184.7 183v1.4M184.7 196v.8M184.8 193.1h.5M185.3 189.6l-.4 1h.9M185.5 192.4h-.7v1.4h.7M185.6 190.2v.9M185.8 183h.6"/>
<path d="M186 193.7v.1M186 182.5v1.3l.4 .1M186.8 192.4h.4l.4 .3v.8l-.4 .3h-.4zM186.8 183.1h.7v.7h-.7zM187.8 184.1h1.1M188.3 193.7v.1M188.3 180.5l.4-.1 .3 .2-.1 .6h-.6M188.3 180.4v1.4M188.7 193.8l.5-1.4 .5 1.4M188.8 193.4h.7M189.1 183.9l.4-1.4 .5 1.4M189.2 183.5h.7"/>
<path d="M189.4 180.4h.5M190.2 193.7v.1M190.5 180.5h.5v.7h-.5zM191.1 183.1l-.4-.1-.2 .3v.5h.6M191.4 181.5h1.1M191.6 183h.5M191.7 182.5v1.3l.4 .1M192.6 183.2h.8M192.6 182.5v1.4M192.7 181.3l.5-1.4 .5 1.4M192.7 193l-.2 .3h-.4l-.2-.3v-.3l.2-.3h.4l.2 .3v.8l-.2 .3h-.4M192.8 180.9h.7"/>
<path d="M193.3 193.7v.1M193.4 182.5v1.4M194.1 192.6l.2-.2a.75 .75 0 0 1 .6 .7 .75 .75 0 0 1-.6 .7l-.2-.1-.1-.4zM194.1 182.5v.2M194.1 183v.9M194.8 180.5h-.7v.7h.7M194.9 183.8v.1M195.2 180.4h.5M195.4 193.7v.1M195.4 188.9v2.9M195.5 182.5v1.4M195.6 183.4l.4 .5"/>
<path d="M196 183l-.5 .5M196.2 180.5h.9M196.4 192.4h.1a.8 .8 0 0 1 .4 .8 .8 .8 0 0 1-.5 .6 .89 .89 0 0 1 0-1.4zM196.7 182.5v.2M196.7 183v.9M197.7 180.4v.9M198 183.1l-.4-.1-.3 .3 .1 .5h.6M198.3 180.3l.4-.4v1.4M198.3 181.3h.9M198.7 183.1l.3-.1 .3 .2v.7M198.7 189.7a.73 .73 0 0 1 .9 .7 .73 .73 0 0 1-.9 .7zM199.3 183.3l-.6 .1-.1 .2 .1 .3 .6-.1"/>
<path d="M199.8 180.1l.3-.2 .4 .2-.1 1.1h-.5zM200.2 190.2h.6l.1 .9M200.5 183.1l-.3-.1-.3 .3v.5h.6M200.5 182.5v1.4M200.9 190.5l-.7 .1v.4h.7M201 184.1h1.1M201.4 190.2h.5M201.5 189.7v1.3l.4 .1M202.3 190.6l.7-.1-.1-.3h-.5l-.1 .2v.6l.2 .1 .4-.1M202.9 183.1l-.4-.1-.2 .2 .1 .2 .5 .1v.3h-.6M203.7 191v.1M203.7 190.2v.2"/>
<path d="M204.2 183.1l-.5-.1-.2 .3 .1 .5h.6M204.8 183.1l.4-.1 .2 .2v.7M204.8 182.5v1.4M205.4 189.8l.5-.1 .3 .4-.9 1h.9M206.9 189.8h.5a1.01 1.01 0 0 1-.2 1.3 .87 .87 0 0 1-.3-1.3zM208.1 195.2v1.9M208.1 189.8h.8l.1 .3-.9 1h.9M210.3 189.7h-.7l-.1 .7 .6-.2 .2 .3v.4l-.2 .2-.6-.1M210.9 190.5h1.1M212.7 190.1l.4-.4v1.4M212.7 191.1h.9M214.2 189.8l.2-.1a.76 .76 0 0 1 .5 .7 .76 .76 0 0 1-.5 .7 1.01 1.01 0 0 1-.2-1.3z"/>
<path d="M215.5 190.5h1.1M217.3 189.8h.8v.3l-.9 1h.9M218.6 189.7h1l-.6 1.4M233.3 195.5h-.6l-.1 .6 .2-.1h.3l.3 .2v.3l-.3 .3h-.3l-.2-.2M256.6 195.2v1.9M257.5 188.9v6.3M260 192.4v1.4M261.2 192.9h-.5l-.1 .3v.4l.2 .2h.4M261.2 192.4v1.4M261.9 193.7v.1M261.9 192.9v.2M263.7 192.8l.4-.4v1.4"/>
<path d="M263.7 193.8h.8M265.9 193l-.3 .3h-.3l-.3-.3v-.3l.3-.3h.3l.3 .3-.1 .8-.2 .3h-.4M267.6 192.3l-1.3 1.9M267.9 192.4h.9l-.5 .5 .5 .2v.6l-.3 .1h-.4l-.2-.1M269.6 193l-.2-.3 .2-.3 .6 .3-.1 .2-.2 .1a.47 .47 0 0 0-.5 .6l.2 .2a.45 .45 0 0 0 .5-.1 .45 .45 0 0 0 0-.5l-.2-.2M281.5 181.9a.65 .65 0 0 1 .7 .6 .65 .65 0 0 1-.7 .7zM281.8 195.5h-.4l-.3 .5v.5l.3 .3 .4-.1v-.7h-.4l-.3 .2"/>
</g>
<g fill="none" stroke="#980000" stroke-width=".25">
<path d="M177.4 178.5l.4-1.5 .5 1.5M177.5 178h.6M178.8 177v1.2l.2 .3M179.5 178l.7-.2-.2-.3h-.4l-.1 .7 .2 .3 .4-.1M180.7 177.5l.7 1M181.4 177.5l-.7 1M183.1 178.5v-1.5l.5 1 .5-1v1.5M184.7 177v.1M184.7 177.5v1M185.4 177v1.2l.3 .3M186.2 177v1.2l.2 .3M186.9 178l.7-.2-.1-.3h-.6v.9h.6"/>
<path d="M188.2 177.5v1M188.6 177.5l-.4 .3M191.2 177.7v.3l-.5 .5a.43 .43 0 0 1-.4-.2 .43 .43 0 0 1 0-.5l.6-.5-.1-.3h-.3a.55 .55 0 0 0 .2 .8l.7 .7M193.1 178.5v-1.5l.5 1 .5-1v1.5M194.8 177.5h.6v1M195.4 177.8l-.4 .1-.3 .2 .3 .4 .4-.1M196.2 177.5v1M196.5 177.5h-.2l-.1 .3M196.8 177.5h.6M197 177v1.2l.4 .3M197.9 177v.1M197.9 177.5v1"/>
<path d="M198.5 177.6l.1-.1a.36 .36 0 0 1 .6 .2v.8M198.5 177.5v1M201 177.8l.7-.1 .1-.2v-.4l-.8-.1v1.5M201.3 177.8l.5 .7M204.4 177.5v1.1l-.2 .3h-.4M204.4 177.5h-.4l-.3 .3 .1 .6h.6M205 178l.7-.2-.1-.3h-.4l-.2 .2 .1 .7h.5M206.3 177.5v1M206.8 177.5l-.5 .3M260.1 190.5l.7-.1 .1-.6-.8-.1v1.5M260.4 190.5l.5 .7M261.4 190.7l.7-.1-.1-.4h-.5l-.1 .7 .2 .3 .4-.1"/>
<path d="M262.6 190.2l.4 1 .3-1M263.9 191v.2M263.9 190.2v.2M265.6 189.8l.6-.1 .2 .5-.9 1h.9M267 191v.2M267.8 189.8l.2-.1a.75 .75 0 0 1 .6 .8 .75 .75 0 0 1-.6 .7l-.2-.2-.1-.4z"/>
<circle cx="202.7" cy="178" r=".48"/>
</g>
<g fill="none" stroke="#980000" stroke-width=".42">
<path d="M177.7 185.8h1.1M178.2 185.8l-.2 1.9M179.3 186.4l-.1 1.3M179.4 185.8v.1M180 186.4h.8M180.3 185.8l-.1 1.6 .4 .3M181.4 185.8l-.1 1.6 .2 .3M182.2 187l1-.1-.1-.4a.6 .6 0 0 0-.8 .2v.9h.7M184 187.5l-.1 .2-.1-.1 .2-.1-.1 .2M184.1 186.5v.2M186.5 186a.7 .7 0 0 1 1.1 0 1.36 1.36 0 0 1-.6 1.7l-.5-.1a1.33 1.33 0 0 1 0-1.6zM188.5 186.5a.6 .6 0 0 1 .9 .3l-.3 .8h-.7"/>
<path d="M188.5 186.4l-.2 2M190 186.4h.7M190.3 185.8l-.1 1.6 .4 .3M191.3 186.6l.4-.2 .5 .2-.1 .9-.3 .2-.5-.2zM193.1 186.4l-.2 1.3M193.2 185.8v.1M194.7 186.5l-.5-.1-.3 .4 .2 .2 .5 .1v.5h-.8M195.6 186.6l.3-.2 .4 .1 .2 .3-.1 .6a.55 .55 0 0 1-.5 .3 .55 .55 0 0 1-.5-.3zM197.4 185.8l-.1 1.6 .2 .3M198.4 186.5h.7l-.1 1.2M199.2 186.9h-.7l-.3 .3 .1 .4h.7M199.9 186.4h.8"/>
<path d="M200.2 185.8l-.1 1.8 .4 .1M201.2 186.6l.6-.2 .4 .4-.1 .6-.4 .3-.5-.1-.1-.2zM203 186.4l-.1 1.3M203.6 186.4h-.2l-.5 .4M205.2 187.7l1-1.9 .4 1.9M205.5 187.1h.9M208.2 186.5l-.5-.1-.4 .4v.7l.2 .2 .5-.1M208.8 186.4h.7M209.1 185.8l-.2 1.6 .1 .2 .4 .1M210.1 186.4l-.1 1.3M210.2 185.8v.1M210.9 186.4l.3 1.3 .6-1.3"/>
<path d="M212.3 187l1.1-.1-.1-.4a.6 .6 0 0 0-.9 .2v.9h.7M215.6 186.7h1.1M215.8 185.8l-.2 1.9M216.9 185.8l-.2 1.9M217.8 186.4l-.2 1.3M217.8 185.8h-.1h.2h-.1v.1M219.5 186.4l-.3 1.7a.45 .45 0 0 1-.8 .1M219.5 186.5l-.6-.1-.3 .2-.1 .9a.64 .64 0 0 0 .9 .1M220.4 186.6l.1-.1a.48 .48 0 0 1 .7 .2l-.1 1M220.5 185.8l-.3 1.9M223.6 186.7h.7M224.6 185.8h-.9l-.2 1.9"/>
<path d="M225.3 186.6l.2-.2 .6 .1 .1 .3-.1 .6a.65 .65 0 0 1-.9 .2zM227.2 185.8l-.3 1.6 .3 .3M228.2 185.8l-.3 1.6 .3 .3M228.9 186.8a.65 .65 0 0 1 1-.3v.9l-.4 .3-.6-.2zM230.6 186.4l.3 1.3 .5-.9 .2 .9 .6-1.3M232.7 187l1-.1-.1-.4a.6 .6 0 0 0-.9 .2v.9h.8M234.5 186.4l-.1 1.3M235.1 186.4l-.4 .1-.2 .3"/>
</g>
<path d="M133.6 95.5h9.9v7.4h-9.9z" fill="#fffec7"/>
<path d="M157 96h.7l.6 .7-.6 .6h-.7z" fill="#fff"/>
<g fill="none" stroke="#805e00" stroke-width=".21">
<path d="M157 96h.7l.6 .7-.6 .6h-.7zM158.7 95.7h8.7M158.9 96v1.2h.6M159.9 96v1.2h.6M160.6 97.4h.9M161.8 96.2l.2-.2 .5 .2v.9l-.2 .1h-.4l-.1-.1zM163.1 96.5v.7l.5-.1M163.6 96.5v.7M164 96.5h.5M164.2 96v1.1l.3 .1M164.9 97.2h.5v-.7h-.5v1.2M166 96.5l.1 .7 .5-.1"/>
<path d="M166.6 96.5v.7M166.9 96.5h.5M167.2 96v1.2h.2"/>
</g>
<path d="M127.5 106.5v1.3h1.2l-1.2 1.2-1.3-1.2h1.3M127.5 106.5h.1M149.6 106.5v1.3h1.3l-1.3 1.2-1.1-1.2h1.1M149.6 106.5h.1" fill="none" stroke="#980000" stroke-width=".21"/>
<path d="M118.8 81.3h.6l.7 .6-.7 .6h-.6z" fill="#fff"/>
<g fill="none" stroke="#805e00" stroke-width=".21">
<path d="M111 81.2v1.3M111 81.8h.7M111.7 81.2v1.3M112.3 81.2v1.3h.5M113 82.6h.9M114.2 81.2v1.3M114.8 81.7h.4l.2 .1v.7M114.8 81.7v.8M115.9 81.7h.6v.6l-.2 .2-.4-.1M115.9 81.7v1.1M117 81.7v.7l.4 .1 .2-.2M117.6 81.7v.8"/>
<path d="M118 81.7h.4M118.1 81.2v1.1l.3 .2M118.8 81.3h.6l.7 .6-.7 .6h-.6z"/>
</g>
<g fill="none" stroke="#980000" stroke-width=".21">
<path d="M133.6 96.7h2.5v3.2M136.1 99.8v1.8h-2.5M138 98.7h1.3M138 99.7h1.3l-.4 .1v-.3l.4 .2M142.9 96.7l-1.9 1.9M149.6 83.2v1.2M149.6 89.3v1.2M158.1 80.6h6.3v2.6h-6.3l-1.1-1.3zM158.8 82.1h1M159.3 81.7v.9M160.2 81.3h.8l-.4 .5h.3l.1 .2-.1 .5-.5 .1-.2-.2M161.3 81.3l.5 1.3 .4-1.3"/>
<path d="M162.4 81.3h.8l-.3 .5 .3 .1v.5l-.2 .2-.6-.2"/>
</g>
<path d="M133.7 95.5h9.8v7.4h-9.8zM135.5 98.6h1.2l-.6 1.2zM135.5 99.8h1.2M148.7 84.4h2v4.9h-2z" fill="none" stroke="#980000" stroke-width=".25"/>
<path d="M141 97.3v3.7" fill="none" stroke="#980000" stroke-width=".51"/>
<path d="M141.5 100.8l.5-.5 .5 1z" fill="#980000"/>
<path d="M142.9 96.7h.6M141.5 100.8l.5-.5 .5 1z" fill="none" stroke="#980000" stroke-width=".21"/>
<path d="M141 99.8l1.9 1.8z" fill="#980000"/>
<path d="M127.5 83.2v1.2M127.5 89.3v1.2M131.2 96.7h2.4M141 99.8l1.9 1.8h3M143.5 96.7h2.4M158.1 80.6h6.3v2.6h-6.3l-1.1-1.3zM158.8 82.1h1M159.3 81.7v.9M160.2 81.3h.8l-.4 .5h.3l.1 .2-.1 .5-.5 .1-.2-.2M161.3 81.3l.5 1.3 .4-1.3M162.4 81.3h.8l-.3 .5 .3 .1v.5l-.2 .2-.6-.2M131.2 101.6h2.4" fill="none" stroke="#980000" stroke-width=".21"/>
<path d="M132 95.5l.4-.4v1.3M132 96.4h.7M144.6 95.1l-.2 .9h.8M145 95.5v.9M132 100.2l.6-.1 .1 .5-.8 .7h.8M144.3 100.1h.8l-.5 .4 .5 .3-.1 .4h-.7" fill="none" stroke="#bd0000" stroke-width=".21"/>
<path d="M126.5 84.4h2v4.9h-2z" fill="none" stroke="#980000" stroke-width=".25"/>
<path d="M120.1 81.9h7.4v1.3M127.5 90.5v6.2h3.7M145.9 96.7h11.1M149.6 90.5v6.2M157 81.9h-7.4v1.3M131.2 101.6h-3.7v4.9M145.9 101.6h3.7v4.9" fill="none" stroke="#00a200" stroke-width=".21"/>
<g fill="none" stroke="#001dcd" stroke-width=".21">
<path d="M117.6 49.8h34.5v24.7h-34.5zM121.3 115.2h50.5v4.9h-50.5zM123.2 116.2h-.6l-.1 .2 .1 .3 .6 .3v.3l-.7 .1M123.8 116.2v.1M123.8 116.6v.8M124.4 116.7l.4-.1 .1 .8M124.4 116.6v.8M126 117.4h-.5v-.8h.5v1l-.2 .2-.3-.1M126.6 116.2v1l.2 .2M127.2 117l.6-.1-.1-.3h-.5v.8h.5M129.7 116.6h-.4l-.1 .2v.5l.5 .1M130.3 116.7l.5-.1v.8"/>
<path d="M130.3 116.2v1.2M131.4 116.6h.5v.2v.6h-.5v-.4l.5-.1M132.5 116.7l.5-.1v.8M132.5 116.6v.8M133.6 116.7l.5-.1v.8M133.6 116.6v.8M134.7 117l.5-.1v-.3h-.5v.8h.5M135.8 116.2v1.2h.2M137.4 116.6h.5l.1 .2v.6h-.6v-.4l.6-.1M138.6 116.2v1.2h.1M139 116.6h.5M139.1 116.2v1l.1 .2h.3"/>
<path d="M139.8 117l.6-.1-.1-.3h-.4l-.1 .2 .1 .6h.4M140.9 116.6v.8M141.3 116.6h-.3l-.1 .2M141.7 116.7l.5-.1v.8M141.7 116.6v.8M142.8 116.6h.5v.8h-.5v-.4l.5-.1M143.7 116.6h.5M143.9 116.2v1l.1 .2h.2M144.6 116.2v.1M144.6 116.6v.8M145.1 116.6l.3 .8 .3-.8M146.1 117l.6-.1-.1-.3h-.4l-.1 .2 .1 .6h.4"/>
<path d="M148.1 117.3v.1M148.1 116.6v.2M149.6 116.2v1.2h.6M150.7 116.2v.1M150.7 116.6v.8M151.1 116.6h.5M151.3 116.2v1v.2h.3M151.9 117l.6-.1-.1-.3h-.5v.8h.5M153.1 116.2h.5l.1 .2 .1 .6-.2 .4h-.5l-.1-.2-.1-.6zM154.3 116.7l.5-.1v.8M154.3 116.6v.8M156.3 116.2v1.2h.6"/>
<path d="M157.2 116.2h.7M157.5 116.2v1.2M158.1 116.2l.4 1.2 .5-1.2M159.4 117h.9M161.1 116.7l-.3-.2 .1-.3h.5l.1 .4-.4 .1a.42 .42 0 0 0-.2 .7l.6-.1v-.5l-.2-.1M162 116.5l.3-.3v1.2M162 117.4h.7M163.1 116.2h.9l-.6 1.2M165.1 116.2l-.7 .1v.3l.7 .4-.1 .4h-.6"/>
</g>
<g fill="none" stroke="#001dcd" stroke-width=".25">
<path d="M118.9 52.1l.4-1.2 .3 1.2M118.9 52.8l.4 1.3 .3-1.3M119 51.7h.5M119 54.9v1.1h.6M119.7 58.9l-.1-.1a.66 .66 0 0 0-.6 .5 .66 .66 0 0 0 .2 .7l.5-.1M119.9 53.2h.5M120.1 55.3h.4l.1 .2v.4l-.1 .1h-.4zM120.2 58.8v.1M120.2 59.2v.8M120.4 52.8l-.3 .2v1.1M120.5 51.3h-.4v.3l.4 .1v.4h-.4M120.8 59.2v.8"/>
<path d="M121 55.3l.2 .7 .3-.5 .2 .5 .2-.7M121.2 59.2l-.4 .2M121.5 51.3h-.4l-.1 .2 .2 .2h.3v.4h-.5M121.7 53.4h1M121.7 53.8h1M122.1 51.3l.1 .8 .4-.1M122.2 59.3l-.5-.1-.1 .1v.6l.6 .1M122.3 55.6l.6-.1v-.2h-.5l-.1 .2 .1 .5h.5M122.6 51.3v.8M122.7 59.2v.8l.5-.1M123.2 51.4l.5-.1v.8M123.2 51.3v.8"/>
<path d="M123.2 59.2v.8M123.7 51.5l.1-.2h.4l.1 .8M123.8 58.8v.1M123.8 59.2v.8M123.9 55.3h-.5v.3h.4l.1 .3v.1h-.5M124.1 53.2h.2l.2-.4v1.3M124.1 54.1h.7M124.2 59.2h.4M124.3 55.3h.5M124.4 58.8v1.1l.2 .1M124.5 54.9v1v.1h.3M124.8 51.7l.6-.1-.1-.3h-.5v.8h.5"/>
<path d="M125.4 53.9v.2M125.9 53l.2-.2 .4 .1 .1 .5-.8 .7h.8M126.1 54.9v1.1h.5l.1-.1v-.4l-.1-.2h-.5M126.7 58.9l-.6-.1-.1 .3v.7l.1 .2 .6-.1M126.9 52.8l.4 1.3 .5-1.3M127.1 58.8h.7M127.2 55.3h.5l.1 .2v.5h-.6v-.4l.6-.1M127.4 50.9h-.6l-.1 .6 .2-.2h.3l.3 .3v.3l-.2 .2-.6-.1M127.4 58.8v1.2M128.1 51h.3a.67 .67 0 0 1 0 1.1l-.3-.1a.78 .78 0 0 1 0-1zM128.2 59.4h.6l.1-.5-.7-.1v1.2M128.2 55.3h.5"/>
<path d="M128.3 54.9v1l.1 .1h.3M128.4 59.4l.5 .6M128.9 55.3h.5M129 54.9v1l.1 .1h.3M129.1 51l.2-.1 .1 .2-.1 .1zM129.4 59.9v.1M129.4 59.3v.1M129.7 51.9l.2-.2 .1 .2v.2zM129.7 55.6l.6-.1-.1-.2h-.4l-.1 .2 .1 .5h.4M129.9 53.5l-.5-.1v.2v.3l.5-.1M129.9 53.4v.4h.2a.58 .58 0 0 0-.7-.7 .58 .58 0 0 0-.2 1 .61 .61 0 0 0 .8 0M130 50.9l-.9 1.2"/>
<path d="M130.6 53.2l.4-.4v1.3M130.6 54.1h.7M130.8 55.3v.7M131.1 55.3l-.3 .2M131.5 55.3l.2 .7M131.9 53.4l.2-.2 .3 .2v.7M131.9 53.2v.9M132.1 55.3l-.4 1.1-.2 .1M132.2 51l-.3-.1-.4 .2v.7l.2 .3 .5-.1M132.4 53.4l.2-.2 .3 .2v.7M132.6 50.9h.7M132.9 50.9v1.2"/>
<path d="M133.3 54.1l.5-1.3 .4 1.3M133.4 53.8h.6M133.4 55.5h1M133.4 55.8h1M133.7 51.6h.5l.2-.2v-.4l-.7-.1v1.2M134 51.6l.4 .5M135.7 51.3l.3 .8 .2-.5 .3 .5 .2-.8M135.9 55.2l.3-.3v1.1M135.9 56h.7M137.2 52v.1M137.2 54.9h.5v.7l-.1 .4h-.4l-.1-.1zM138.1 54.9l.4 1.1 .4-1.1"/>
<path d="M138.3 51.3h-.5l-.1 .3v.3l.1 .2h.5M138.8 52v.1M119 62.8v1.2h.6M119 70.9l.3-.2 .4 .2 .1 .6-.3 .5-.5-.2zM119 60.8v1.3M119 64.8v1.2M119.5 61.2h.4M119.7 66.9l-.2-.2a.65 .65 0 0 0-.6 .6 .65 .65 0 0 0 .6 .7l.2-.1M119.9 60.8l-.3 .1v1.2M120.1 63.2h.3l.2 .2v.5h-.5zM120.1 66.7h.7M120.1 65.3l-.3-.1-.3 .2 .1 .5h.5"/>
<path d="M120.3 71.2l.3-.1 .3 .3-.1 .5h-.5M120.3 71.1v1.3M120.4 66.7v1.3M121 63.2l.2 .8 .3-.6 .2 .6 .2-.8M121.2 67.4l.6-.1 .1-.3-.2-.3h-.5v1.3M121.2 61.4h1M121.2 61.7h1M121.2 71.1h.5M121.4 70.7v1.1l.3 .2M121.5 67.4l.4 .6M121.6 65.4h.9M121.6 65.7h.9"/>
<path d="M122.2 71.2l.3-.1 .2 .2v.5l-.2 .2-.4-.3zM122.3 63.6l.6-.1v-.3h-.4l-.2 .1v.5l.2 .2 .4-.1M122.9 67.2l-.3-.1-.3 .3 .1 .5h.5M123.4 63.2v.8M123.9 63.2l-.5 .2M123.9 64.8h.8l-.4 .5h.3l.1 .1-.1 .5-.5 .1-.2-.1M124 60.6a1.44 1.44 0 0 0 0 1.9M124.2 70.7v.2M124.2 71.1v.9M124.5 61.1h.1l.2-.3v1.3M124.5 62.1h.7M124.5 67.3h.9"/>
<path d="M124.5 67.7h.9M125.2 65.9v.1M125.2 71.2l-.3-.1-.2 .2 .2 .2 .3 .1v.3h-.5M125.7 63.2h-.5l-.1 .5a.36 .36 0 0 0 .6 .2M125.7 64.8h.8l-.4 .5 .4 .1v.4l-.3 .2h-.3l-.2-.1M125.8 60.9l.3-.1 .2 .2v.8l-.2 .3a.71 .71 0 0 1-.3-1.2zM126.2 62.8v1l.2 .2M126.7 60.8l.4 1.3 .4-1.3M126.7 71.2l.4-.1 .1 .2v.7M126.9 63.2h.3l.3 .2-.1 .5h-.5zM127.1 66.7l.4 .3v.7l-.4 .3a.9 .9 0 0 1 0-1.3zM127.2 71.5h-.4l-.1 .1 .1 .4 .4-.1"/>
<path d="M127.8 70.7v1.2l.2 .1M127.8 64.7l-1 1.6M127.9 61.5h1M128.1 67.9v.1M128.3 65.1l.3-.3v1.2M128.3 66h.6M128.3 71.1l.3 .9 .3-.6 .1 .6 .3-.9M128.4 63.2h-.3l-.2 .1 .1 .3 .4 .1v.2h-.5M128.5 66.7h.8l-.4 .5 .4 .3-.1 .4h-.7M128.9 63.6l.6-.1-.1-.3-.5 .1v.5l.2 .2 .3-.1M129.4 61.1l.4-.3v1.3M129.4 62.1h.7"/>
<path d="M129.5 64.8h.1a.6 .6 0 0 1 .6 .5 .6 .6 0 0 1-.2 .6l-.3 .1-.3-.2zM129.7 66.7h.8l-.5 .5 .5 .3-.1 .4h-.7M129.8 71.2l.3-.1 .2 .2v.7M130.3 71.5h-.4l-.2 .1 .2 .4 .4-.1M130.5 63.2h-.3l-.2 .2v.2h.4l.2 .2-.2 .2-.4-.1M130.6 61.9v.2M130.6 64.8v1.2M130.7 65.5l.4 .5M130.7 71.1l.4 .9M130.9 63.2h.4M131.1 62.8v1l.2 .2M131.1 60.9l.6-.1 .2 .2-.8 1.1h.8"/>
<path d="M131.1 65.2l-.5 .4M131.3 71.1l-.3 1.1-.3 .2M131.9 66.7l-1.1 1.5M132.2 60.8l.5 1.3 .4-1.3M132.2 67.1l.4-.4v1.3M132.2 71.2l-.3-.1-.2 .3 .6 .4-.2 .2-.4-.1M132.2 68h.7M132.6 65.4h.9M132.6 65.7h.9M132.8 63.3l-.1-.4 .6-.1v.4l-.6 .2v.5l.4 .1a.35 .35 0 0 0 .3-.3 .35 .35 0 0 0-.3-.4M133.3 60.6a1.44 1.44 0 0 1 0 1.9M133.4 67.9v.1"/>
<path d="M133.8 70.7v.2M133.8 71.1v.9M133.9 62.8v1.2M134 63.6l.4 .4M134.3 66.7a.71 .71 0 0 1 .4 .6 .71 .71 0 0 1-.3 .7l-.4-.3v-.7zM134.4 71.3l.1-.2 .4 .2v.7M134.4 63.2l-.5 .5M134.4 71.1v.9M134.8 62.9l.6-.1 .1 .2v.3l-.7 .7h.7M135 64.8h.7l-.4 .5 .4 .1v.4l-.2 .2h-.4l-.1-.1M135.1 66.7h.8l-.5 1.3M135.1 60.7l-1 1.6"/>
<path d="M135.5 61.1l.4-.3v1.3M135.5 62.1h.7M136.1 64.8h.8l-.4 .5 .4 .1v.4l-.3 .2h-.3l-.2-.1M136.7 61.3h.5v.8M136.7 61.2v.9M136.8 71.2l-.3-.1-.2 .3 .4 .1 .2 .3-.2 .2-.4-.1M137 63.3h.9M137 63.7h.9M137.2 61.4l.3-.2 .3 .2v.7M137.3 67.3h1M137.3 67.7h1M137.4 71.2l.3-.1 .2 .2v.7"/>
<path d="M137.5 64.8h.2l.3 .2v.8l-.3 .2a.71 .71 0 0 1-.2-1.2zM137.9 71.5h-.4l-.2 .1 .2 .4 .4-.1M138.3 62.1l.3-1.3 .4 1.3M138.3 61.6h.6M138.3 71.1h.5M138.5 70.7v1.1l.3 .2M138.6 65.2v.7l.3 .1 .2-.1M139.1 65.2v.8M139.2 71.1v.7l.2 .2 .4-.2M139.4 63.2l.4-.4v1.2M139.4 64h.7M139.5 66l.4-1.2 .4 1.2"/>
<path d="M139.6 65.6h.6M139.7 66.7h.8l-.5 .5 .5 .3-.1 .4h-.7M139.8 71.1v.9M140.3 71.1v.9M140.4 61.4h.9M140.4 61.7h.9M140.6 63.9v.1M140.7 71.1l-.4 .3M141.1 71.2l.4-.1 .1 .2v.7M141.2 66.7a.68 .68 0 0 1 .5 .6 .68 .68 0 0 1-.5 .7l-.2-.3a.77 .77 0 0 1 .2-1zM141.3 62.8h.2a.62 .62 0 0 1 .4 .6 .62 .62 0 0 1-.4 .6 .84 .84 0 0 1-.2-1.2zM141.6 71.5h-.4l-.2 .1 .2 .4 .4-.1"/>
<path d="M142.1 71.1h.4M142.1 67.9v.1M142.2 62.8h.9l-.5 1.2M142.2 70.7v1.2l.3 .1M142.9 67.3l-.2-.3 .2-.3h.3l.2 .4-.7 .4v.4l.2 .1h.3l.2-.3v-.2l-.2-.2M142.9 70.7v.2M142.9 71.1v.9M143 61.3l-.2-.1v-.3h.6v.4h-.4l-.2 .2v.4l.2 .2 .4-.1 .1-.2v-.3l-.2-.2M143.4 71.4l.4-.3 .3 .3v.3l-.4 .3-.3-.3zM143.6 63.3l.2-.1 .3 .1v.7M143.6 63.2v.8M144 61.9v.2"/>
<path d="M144 66.7l.2 .1v.3h-.2l-.2-.2zM144.1 63.3l.2-.1 .3 .1v.7M144.4 67.8l.2-.2 .2 .2-.2 .2zM144.6 71.3l.2-.2 .3 .1v.8M144.6 71.1v.9M144.8 61.3l-.3-.2 .1-.2h.6l.1 .2-.2 .2h-.3l-.3 .2v.3l.3 .3h.2l.3-.3v-.3l-.3-.2M144.8 66.7l-1 1.3M145 64l.5-1.2 .4 1.2M145.1 63.7h.6M145.8 60.8v1.3M145.9 61.5l.4 .6M146.3 61.2l-.5 .4"/>
<path d="M146.8 61.9v.2"/>
</g>
<circle cx="149.6" cy="96.7" r=".47" fill="#00a200"/>
<g fill="none" stroke="#007170" stroke-width=".21">
<path d="M130.3 85.5h.6v-.5h-.6v1.1M130.5 87.9l-.2-.2v-.2h.6v.3l-.4 .1-.2 .3 .1 .4 .5-.1v-.4l-.1-.2M130.6 85.5l.4 .6M131.5 87.4v1.2M131.6 88.2l.3 .4M131.8 84.9l-.3 .8h.8M131.9 87.8l-.4 .5M132.1 85.4v.7M132.5 87.5l.4-.1 .2 .4-.7 .8h.7M133.3 85h-.6v.5l.2-.1 .4 .1v.6h-.6M135.2 92.3a.64 .64 0 0 1 .7 .7 .64 .64 0 0 1-.7 .6zM136.4 93h.5l.3-.4-.3-.3h-.5v1.3"/>
<path d="M137 89.9v1l.3 .2 .4-.1v-1.1M138.3 90.2l.3-.3v1.2M138.3 91.1h.7M138.4 92.5l-.2-.2a.64 .64 0 0 0-.6 .7 .64 .64 0 0 0 .6 .6l.2-.2M139.1 92.8h-.1a.31 .31 0 0 1 .1-.4 .31 .31 0 0 1 .4 .1v.3h-.4l-.2 .3 .1 .4 .1 .1 .5-.3-.1-.4-.2-.1M139.7 90.4l-.3-.3 .1-.1h.6l.1 .1-.2 .3h-.3l-.3 .2v.3l.3 .2h.2l.3-.2v-.3l-.3-.2M140.1 92.7l.3-.4v1.3M140.1 93.6h.7M141.2 92.3h.8l-.6 1.3M152.4 87.8l.4-.4v1.2M152.4 88.6h.8M152.5 85.5h.6l.1-.5h-.7v1.1"/>
<path d="M152.8 85.5l.4 .6M153.8 87.5l.2-.1 .3 .3v.7l-.2 .2-.3-.1a.78 .78 0 0 1 0-1zM154 84.9l-.3 .8h.8M154.3 85.4v.7M154.9 87.4v1.2M155 88.2l.3 .4M155.3 87.8l-.4 .5M155.5 85h-.4l-.2 .2v.9h.6v-.6l-.4-.1-.2 .2M130.9 107.2a.59 .59 0 0 0-.7 .4 .59 .59 0 0 0 .3 .7l.5-.1v-.4h-.2M132.3 107.1v1.2l-.8-1.2v1.2M132.9 107.1a.66 .66 0 0 1 .6 .5 .66 .66 0 0 1-.2 .7h-.4zM153.2 107.2a.61 .61 0 0 0-.8 .3 .61 .61 0 0 0 .3 .8h.5v-.5h-.3"/>
<path d="M154.5 107.1v1.2l-.7-1.2v1.2M155.1 107.1a.66 .66 0 0 1 .6 .5 .66 .66 0 0 1-.2 .7h-.4z"/>
</g>
</svg>
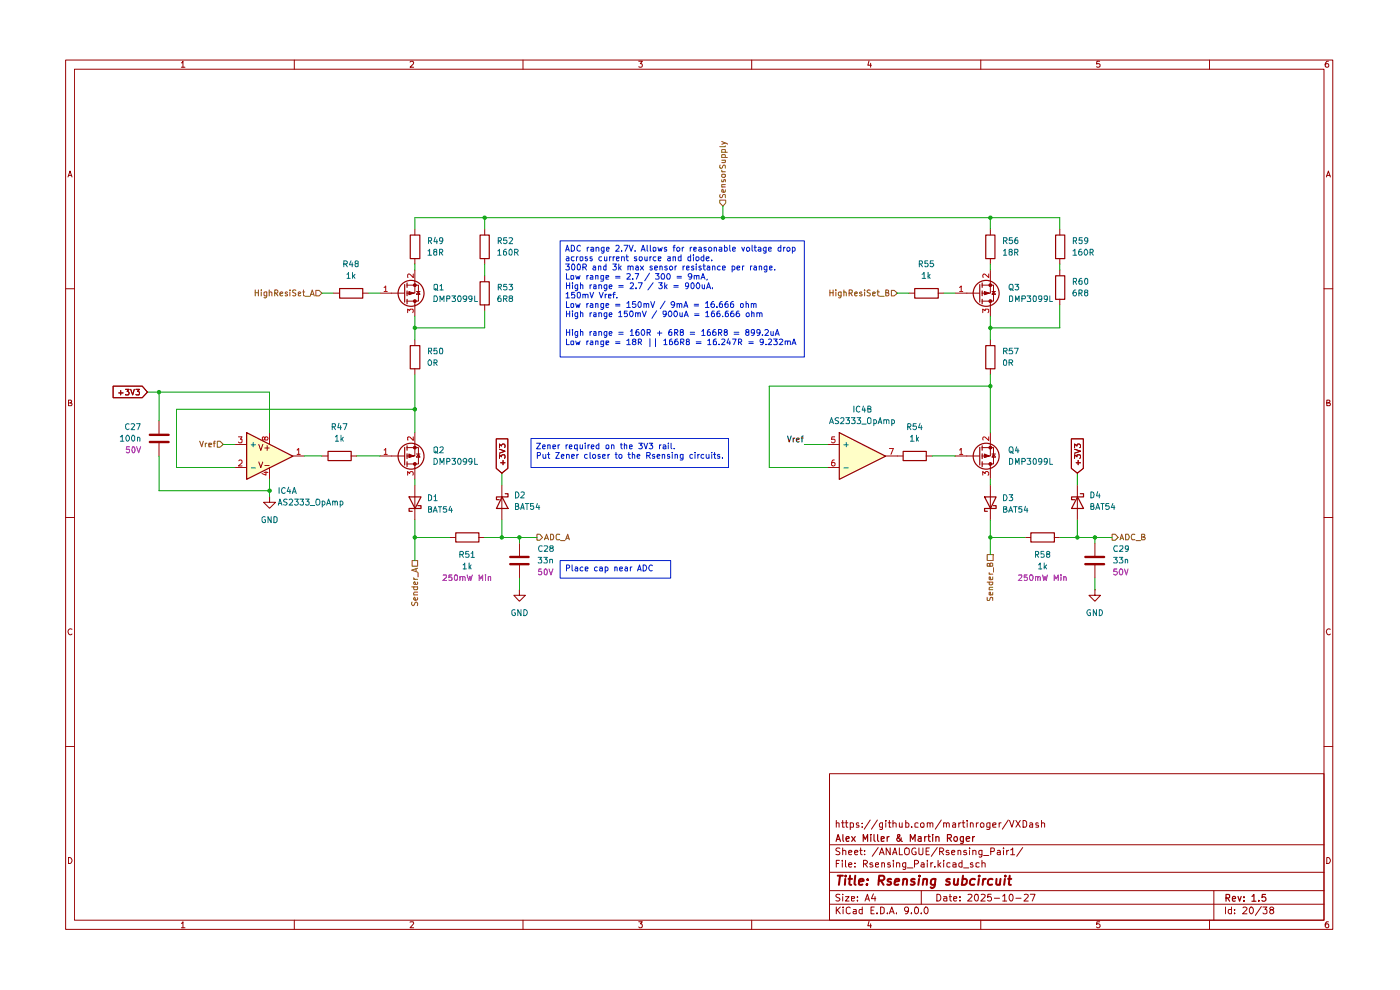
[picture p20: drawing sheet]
<svg xmlns="http://www.w3.org/2000/svg" width="297mm" height="210mm" viewBox="0 0 297 210" stroke-linecap="round" stroke-linejoin="round" font-family="sans-serif">
<g fill="none" stroke="#980000" stroke-width=".21">
<path d="M13.9 12.7h268.8v184.4h-268.8zM15.8 14.7h265.1v180.5h-265.1zM38.5 13.3h.1l.2-.3v1.3M38.5 14.3h.7M62.4 12.7v2M87 13.2l.5-.2 .3 .2-.1 .4-.7 .7h.8M111 12.7v2M135.5 13h.8l-.5 .5 .4 .1v.6h-.7M159.5 12.7v2M184.4 12.9l-.3 .9h.8M184.7 13.4v.9M208.1 12.7v2"/>
<path d="M233.3 13h-.6l-.1 .6h.7v.6h-.7M256.6 12.7v2M281.8 13a.71 .71 0 0 0-.7 .5 .71 .71 0 0 0 .3 .8l.4-.1v-.6l-.4-.1-.3 .3M14.4 37.5l.5-1.2 .4 1.2M14.5 37.2h.7M281.4 37.5l.4-1.2 .4 1.2M281.5 37.2h.6M13.9 61.3h1.9M280.9 61.3h1.8M14.5 85.5h.4l.3-.3-.2-.3h-.5v1.2h.6l.2-.5-.4-.1M281.5 85.5h.4l.2-.3-.1-.3h-.5v1.2h.6l.1-.5-.3-.1M13.9 109.8h1.9"/>
<path d="M280.9 109.8h1.8M15.3 133.5a.59 .59 0 0 0-.9 .5 .59 .59 0 0 0 .8 .6l.1-.1M282.2 133.5a.59 .59 0 0 0-.8 .5 .59 .59 0 0 0 .7 .6l.1-.1M13.9 158.4h1.9M280.9 158.4h1.8M176 164.1h104.9v31.1h-104.9zM176 179.2h104.9M177.4 174.7l.2-.2 .4 .1v.9M177.4 174v1.5M178.2 180l-.6-.1-.3 .2 .1 .4 .8 .4-.1 .3h-.8M178.5 174.5h.6M178.8 174v1.5h.3"/>
<path d="M178.8 179.9v1.4M179.4 174.5h.5M179.5 174v1.3l.1 .2h.3M180.4 174.6l.4-.1 .3 .2v.7l-.7 .1M180.4 174.5v1.5M182.2 174.6l-.4-.1-.2 .2 .2 .3h.4v.5h-.6M182.6 179.9v1.2l.3 .2M182.9 175.4v.1M182.9 174.6v.1M184.6 173.9l-1.3 2M186.1 173.9l-1.2 2M186.3 179.8l-1.3 1.8"/>
<path d="M187.2 174.5v1.2a.36 .36 0 0 1-.6 .2M187.2 174.6l-.4-.1-.2 .3v.6l.6 .1M187.9 174v.2M187.9 174.5v1M188.4 174.5h.6M188.7 174v1.5h.3M188.8 179.9v1.4l-.8-1.4v1.4M189.4 174.7l.3-.2 .4 .2v.8M189.4 174v1.5M190.8 179.9v1.4h.7M190.8 174.5l.1 1 .5-.1M191.4 174.5v1"/>
<path d="M192.1 174v1.5l.6-.1 .1-.6a.45 .45 0 0 0-.7-.2M193.4 175.4v.1M194.3 180a.67 .67 0 0 0-.9 .6 .67 .67 0 0 0 .9 .6v-.5h-.2M194.8 174.6l-.5-.1-.2 .2v.7l.7 .1M194.9 179.9v1.2l.3 .2h.3l.3-.2v-1.2M195.3 174.8a.45 .45 0 0 1 .7-.2v.9l-.6-.1zM196.7 174.7l.2-.2 .4 .2v.8M196.7 174.5v1M197.1 179.9h-.6v1.4h.6M197.3 174.7l.2-.2 .4 .1v.9M198.8 179.8l-1.2 1.8M199.7 173.9l-1.3 2"/>
<path d="M200.2 174.7l.2-.2 .4 .2v.8M200.2 174.5v1M200.8 174.7l.2-.2 .4 .2v.8M202.1 174.6l.4-.1 .2 .2v.8h-.6v-.4l.6-.2M203.4 174.5v1M203.8 174.5l-.4 .3M204.1 174.5h.6M204.3 174v1.3l.1 .2h.3M205.2 174v.2M205.2 174.5v1M205.7 179.9v.1M205.9 174.7l.1-.2 .5 .2v.8"/>
<path d="M205.9 174.5v1M207.1 174.5v1M207.6 174.5l-.5 .3M208.2 174.5h.3l.2 .3-.1 .7h-.5l-.1-.3v-.4zM210 174.5v1.2l-.2 .3-.5-.1M210 174.6l-.4-.1-.3 .2v.7l.7 .1M210.6 175l.7-.1v-.3l-.4-.1-.3 .2 .1 .8h.6M212 174.5v1M212.4 174.5l-.4 .3M212.9 179.9v.1M213.9 173.9l-1.3 2M214.2 174l.5 1.5 .4-1.5"/>
<path d="M215.5 174l.9 1.5M216.4 174l-.9 1.5M217 179.8l-1.3 1.8M217 174h.4l.4 .4v.7l-.3 .4h-.5zM218.5 174.6l.4-.1 .2 .2v.8h-.6l-.1-.4 .7-.2M220.3 174.6h-.6v.4h.6v.2v.3h-.6M220.9 174.7l.3-.2 .4 .2v.8M220.9 174v1.5M14.5 181.9a.65 .65 0 0 1 .8 .6 .65 .65 0 0 1-.8 .7zM38.5 195.9l.3-.4v1.3M38.5 196.8h.7M62.4 195.2v1.9"/>
<path d="M87 195.6l.7-.1 .1 .3-.8 1h.8M111 195.2v1.9M135.5 195.5h.8l-.5 .5 .5 .2-.1 .5-.5 .1-.2-.2M159.5 195.2v1.9M176 191.8h104.9M176 188.9h104.9M176 185h104.9M177.4 192.4v1.4M177.4 183.2h.5M177.6 193l.7 .8M178.1 182.5h-.7v1.4M178.2 189.8h-.8l-.1 .3 .8 .4 .1 .4-.3 .2-.6-.1"/>
<path d="M178.3 192.4l-.9 .8M178.7 182.5v.2M178.7 183v.9M178.8 189.7v.1M178.8 180.5l.4-.1 .2 .1v.8M178.8 190.2v.9M178.9 192.4v.2M178.9 192.9v.9M179.4 190.2h.7l-.7 .9h.7M179.4 182.5v1.3l.1 .1M180 183.4l.7-.1-.2-.3-.5 .2v.6l.3 .1 .3-.1M180 180.8l.7-.1-.2-.3-.5 .1v.6l.3 .2 .3-.1"/>
<path d="M180.4 192.6l-.4-.2-.5 .3 .1 1 .4 .1 .4-.1M180.6 190.6l.7-.1-.1-.3h-.6v.8h.6M181.1 192.9h.5v.9M181.3 180.8l.7-.1-.2-.3h-.3l-.2 .1v.6l.2 .2 .4-.1M181.4 183.8v.1M181.4 183.1v.1M181.6 193.2l-.5 .1-.1 .2 .1 .3h.5M181.9 191v.1M181.9 190.2v.2M182.4 180.4h.5M182.9 192.9h-.5l-.2 .7a.45 .45 0 0 0 .7 .2M182.9 192.4v1.4"/>
<path d="M183.2 183.3l.6-.1 .2-.5-.3-.2h-.5v1.4M183.4 181.2v.1M183.4 180.5h.1M183.5 191.1l.5-1.4 .4 1.4M183.5 183.3l.5 .6M183.7 190.7h.7M184.4 195.4l-.3 1h.8M184.7 196v.8M184.8 193.1h.5M185.1 183.1l-.3-.1-.3 .3 .1 .1 .5 .1 .1 .3-.3 .1-.4-.1M185.3 189.6l-.4 1h.9M185.5 192.4h-.7v1.4h.7"/>
<path d="M185.6 190.2v.9M185.7 183.4l.7-.1v-.2l-.4-.1-.3 .2 .1 .6h.6M186 193.7v.1M186.6 181.3l.5-1.4 .5 1.4M186.7 180.9h.7M186.8 192.4h.4l.4 .3v.8l-.4 .3h-.4zM187.1 183.1l.4-.1 .2 .2v.7M187.1 183v.9M188.3 193.7v.1M188.7 193.8l.5-1.4 .5 1.4M188.8 183.1h-.5v.3l.5 .1 .1 .3-.2 .1-.4-.1M188.8 193.4h.7"/>
<path d="M189.4 181.3l.5-1.4 .4 1.4M189.4 180.9h.8M189.5 182.5v.2M189.5 183v.9M190.2 193.7v.1M190.2 183.1l.4-.1 .3 .2v.7M190.2 183v.9M192 180l.5-.1a.75 .75 0 0 1 .4 .8 .75 .75 0 0 1-.7 .6l-.1-.1a.99 .99 0 0 1-.1-1.2zM192.1 183v1.3l-.2 .1h-.3M192.1 183.1l-.4-.1-.2 .3 .1 .5h.5M192.5 184.1h1.2M192.7 193l-.2 .3h-.4l-.2-.3v-.3l.2-.3h.4l.2 .3v.8l-.2 .3h-.4"/>
<path d="M193.3 193.7v.1M194 183.3l.7-.1 .2-.5-.4-.2h-.5v1.4M194.1 192.6l.2-.2a.75 .75 0 0 1 .6 .7 .75 .75 0 0 1-.6 .7l-.2-.1-.1-.4zM195.4 193.7v.1M195.4 183.1l.5-.1 .1 .2v.7M195.4 188.9v2.9M196 183.3l-.6 .1v.2l.2 .3 .4-.1M196.4 192.4h.1a.8 .8 0 0 1 .4 .8 .8 .8 0 0 1-.5 .6 .89 .89 0 0 1 0-1.4zM196.5 180.5h.5M196.7 182.5v.2M196.7 183v.9M197.5 183v.9"/>
<path d="M197.9 183l-.4 .1v.2M198.3 183.8v.1M198.7 189.7a.73 .73 0 0 1 .9 .7 .73 .73 0 0 1-.9 .7zM199 182.5v1.4M199.2 183.4l.4 .5M199.3 180.6l.7-.1 .2-.4-.3-.2h-.6v1.4M199.6 183l-.6 .5M199.7 180.6l.5 .7M200.2 190.2h.6l.1 .9M200.2 182.5v.2M200.2 183v.9M200.9 190.5l-.7 .1v.4h.7"/>
<path d="M201.3 180.5l-.3-.1-.3 .2 .1 .2 .5 .1 .1 .2-.3 .2-.4-.1M201.4 190.2h.5M201.5 189.7v1.3l.4 .1M201.5 183.1l-.4-.1-.2 .3 .1 .5h.5M201.9 180.8l.7-.1-.2-.3-.5 .1v.6l.2 .2 .4-.1M202.1 183.1l.5-.1 .2 .2v.7M202.3 190.6l.7-.1-.1-.3h-.5l-.1 .2v.6l.2 .1 .4-.1M202.8 183.3l-.7 .1v.4h.7M203.2 180.5l.5-.1 .1 .1v.8M203.2 180.4v.9M203.7 191v.1M203.7 190.2v.2"/>
<path d="M204.1 183.1l-.4-.1-.3 .3 .1 .5h.6M204.1 182.5v1.4M204.4 184.1h1.1M205 180.5l-.3-.1-.3 .2 .1 .2 .5 .1 .1 .2-.3 .2-.4-.1M205.4 189.8l.5-.1 .3 .4-.9 1h.9M205.7 180.4v.9M206.4 183.1l-.4-.1-.1 .3v.1h.4l.2 .4-.2 .1-.4-.1M206.4 180.5l.4-.1 .2 .1v.8M206.4 180.4v.9M206.9 189.8h.5a1.01 1.01 0 0 1-.2 1.3 .87 .87 0 0 1-.3-1.3zM207.7 183.1h-.7v.7h.7M208.1 195.2v1.9"/>
<path d="M208.1 189.8h.8l.1 .3-.9 1h.9M208.3 183.1l.4-.1 .3 .2v.7M208.3 180.4v1.2l-.2 .2-.4-.1M208.3 180.5l-.4-.1-.3 .2 .1 .6h.6M208.3 182.5v1.4M208.7 181.5h1.1M210.2 180.6l.7-.1v-.5l-.2-.1h-.5v1.4M210.3 189.7h-.7l-.1 .7 .6-.2 .2 .3v.4l-.2 .2-.6-.1M210.9 190.5h1.1M211.6 180.5l.4-.1 .2 .1v.8M212.2 180.7l-.6 .1-.1 .2 .2 .3 .5-.1M212.7 190.1l.4-.4v1.4"/>
<path d="M212.7 191.1h.9M212.9 180.4v.9M213.6 180.4v.9M214 180.4l-.4 .2M214.2 189.8l.2-.1a.76 .76 0 0 1 .5 .7 .76 .76 0 0 1-.5 .7 1.01 1.01 0 0 1-.2-1.3zM214.4 180.3l.4-.4v1.4M214.4 181.3h.9M215.5 190.5h1.1M217.3 189.8h.8v.3l-.9 1h.9M218.6 189.7h1l-.6 1.4M233.3 195.5h-.6l-.1 .6 .2-.1h.3l.3 .2v.3l-.3 .3h-.3l-.2-.2M256.6 195.2v1.9"/>
<path d="M257.5 188.9v6.3M260 192.4v1.4M261.2 192.9h-.5l-.1 .3v.4l.2 .2h.4M261.2 192.4v1.4M261.9 193.7v.1M261.9 192.9v.2M263.7 192.6l.2-.2h.3l.3 .4-.9 1h.9M265.1 192.7l.5-.3a.8 .8 0 0 1 .3 .8 .8 .8 0 0 1-.5 .6 .93 .93 0 0 1-.3-1.1zM267.6 192.3l-1.3 1.9M267.9 192.4h.9l-.5 .5 .5 .2v.6l-.3 .1h-.4l-.2-.1M269.6 193l-.2-.3 .2-.3 .6 .3-.1 .2-.2 .1a.47 .47 0 0 0-.5 .6l.2 .2a.45 .45 0 0 0 .5-.1 .45 .45 0 0 0 0-.5l-.2-.2M281.5 181.9a.65 .65 0 0 1 .7 .6 .65 .65 0 0 1-.7 .7z"/>
<path d="M281.8 195.5h-.4l-.3 .5v.5l.3 .3 .4-.1v-.7h-.4l-.3 .2"/>
</g>
<g fill="none" stroke="#980000" stroke-width=".25">
<path d="M177.4 178.5l.4-1.5 .5 1.5M177.5 178h.6M178.8 177v1.2l.2 .3M179.5 178l.7-.2-.2-.3h-.4l-.1 .7 .2 .3 .4-.1M180.7 177.5l.7 1M181.4 177.5l-.7 1M183.1 178.5v-1.5l.5 1 .5-1v1.5M184.7 177v.1M184.7 177.5v1M185.4 177v1.2l.3 .3M186.2 177v1.2l.2 .3M186.9 178l.7-.2-.1-.3h-.6v.9h.6"/>
<path d="M188.2 177.5v1M188.6 177.5l-.4 .3M191.2 177.7v.3l-.5 .5a.43 .43 0 0 1-.4-.2 .43 .43 0 0 1 0-.5l.6-.5-.1-.3h-.3a.55 .55 0 0 0 .2 .8l.7 .7M193.1 178.5v-1.5l.5 1 .5-1v1.5M194.8 177.5h.6v1M195.4 177.8l-.4 .1-.3 .2 .3 .4 .4-.1M196.2 177.5v1M196.5 177.5h-.2l-.1 .3M196.8 177.5h.6M197 177v1.2l.4 .3M197.9 177v.1M197.9 177.5v1"/>
<path d="M198.5 177.6l.1-.1a.36 .36 0 0 1 .6 .2v.8M198.5 177.5v1M201 177.8l.7-.1 .1-.2v-.4l-.8-.1v1.5M201.3 177.8l.5 .7M204.4 177.5v1.1l-.2 .3h-.4M204.4 177.5h-.4l-.3 .3 .1 .6h.6M205 178l.7-.2-.1-.3h-.4l-.2 .2 .1 .7h.5M206.3 177.5v1M206.8 177.5l-.5 .3M260.1 190.5l.7-.1 .1-.6-.8-.1v1.5M260.4 190.5l.5 .7M261.4 190.7l.7-.1-.1-.4h-.5l-.1 .7 .2 .3 .4-.1"/>
<path d="M262.6 190.2l.4 1 .3-1M263.9 191v.2M263.9 190.2v.2M265.6 190.2l.4-.5v1.5M265.6 191.2h.8M267 191v.2M268.5 189.7h-.7l-.1 .7 .2-.2 .5 .1 .2 .6-.4 .3h-.3l-.2-.2"/>
<circle cx="202.7" cy="178" r=".48"/>
</g>
<g fill="none" stroke="#980000" stroke-width=".42">
<path d="M177.7 185.8h1.1M178.2 185.8l-.2 1.9M179.3 186.4l-.1 1.3M179.4 185.8v.1M180 186.4h.8M180.3 185.8l-.1 1.6 .4 .3M181.4 185.8l-.1 1.6 .2 .3M182.2 187l1-.1-.1-.4a.6 .6 0 0 0-.8 .2v.9h.7M184 187.5l-.1 .2-.1-.1 .2-.1-.1 .2M184.1 186.5v.2M186.4 186.8l1-.1 .2-.3-.1-.5-.2-.1h-.8l-.2 1.9M186.9 186.8l.5 .9"/>
<path d="M189.1 186.5a.48 .48 0 0 0-.8 .3l.1 .1 .6 .2 .1 .3a.6 .6 0 0 1-.9 .2M189.8 187l.9-.1v-.4h-.7l-.3 .9 .3 .3 .6-.1M191.6 186.6l.3-.2 .5 .1v1.2M191.7 186.4l-.2 1.3M194.1 186.5a.48 .48 0 0 0-.8 .3l.2 .2 .5 .1 .1 .3a.6 .6 0 0 1-.9 .2M195 186.4l-.2 1.3M195.1 185.8v.1M195.9 186.6l.3-.2 .5 .1-.1 1.2M195.9 186.4l-.2 1.3M198.5 186.4l-.3 1.7-.3 .3-.5-.2M198.5 186.5a.65 .65 0 0 0-1 .3v.7a.64 .64 0 0 0 .9 .1M201.5 186.5a.48 .48 0 0 0-.8 .3l.3 .2 .4 .1 .1 .3a.6 .6 0 0 1-.8 .2"/>
<path d="M202.4 186.4v1.2l.5 .1 .3-.2M203.3 186.4l-.2 1.3M204.2 186.5l.6-.1 .3 .2v.8a.72 .72 0 0 1-1.1 .2M204.3 185.8l-.3 1.9M206.8 186.5a.72 .72 0 0 0-1 .3v.7l.3 .2 .6-.1M207.7 186.4l-.2 1.3M207.8 185.8h-.2h.3h-.1l-.1 .1M208.6 186.4l-.2 1.3M209.1 186.4l-.6 .4M210.6 186.5a.65 .65 0 0 0-1 .3v.7a.64 .64 0 0 0 .9 .1M211.4 186.4v1.2l.4 .1 .4-.2M212.3 186.4l-.2 1.3"/>
<path d="M213.2 186.4l-.2 1.3M213.3 185.8v.1M213.9 186.4h.6M214.2 185.8l-.2 1.8 .5 .1"/>
</g>
<g fill="#fffec7">
<path d="M52.3 91.7l9.8 5-9.8 4.9z"/>
<path d="M178 91.7l9.8 5-9.8 4.9z"/>
</g>
<path d="M87.4 118.9h1.2v1.2h-1.2z" fill="#fff"/>
<g fill="none" stroke="#805e00" stroke-width=".21">
<path d="M87.4 118.9h1.2v1.2h-1.2zM87.3 124.5h1.3M87.4 127.7l-.1 .5 .3 .3 .2-.1 .2-.5 .3-.2 .3 .3-.1 .5M87.8 122.5l.2 .4M87.8 126.2h.8M87.8 122.9h.8M87.8 124.5v.6h.6l.2-.3-.1-.3M88.3 120.6v.6M88.5 126.8l.1 .3-.2 .2h-.5l-.1-.4 .2-.2 .2 .6M88.5 123.5l.1 .3-.2 .2h-.5l-.1-.4 .2-.2 .2 .6M88.6 125.6h-.7l-.1 .3v.3M88.6 120.5l-1.3 .4 1.3 .5"/>
<path d="M88.7 121.4v1"/>
</g>
<path d="M96.7 113h4.9v2h-4.9z" fill="none" stroke="#980000" stroke-width=".25"/>
<path d="M95.4 114h1.2M101.6 114h1.2M110.2 125.1v1.2h1.3l-1.3 1.2-1.2-1.2h1.2M110.2 125.1h.1" fill="none" stroke="#980000" stroke-width=".21"/>
<path d="M46.1 93.6h.6l.7 .7-.7 .6h-.6z" fill="#fff"/>
<path d="M42.4 93.6l.4 1.2 .3-1.2M43.6 94v.8M43.9 94l-.3 .2M44.3 94.4l.6-.1-.1-.3h-.5v.8h.5M45.2 94h.5M45.7 93.6h-.3v1.2M46.1 93.6h.6l.7 .7-.7 .6h-.6z" fill="none" stroke="#805e00" stroke-width=".21"/>
<g fill="none" stroke="#980000" stroke-width=".21">
<path d="M24 81.9h6.2l1.1 1.3-1.1 1.2h-6.2zM25.2 83.3h.9M25.6 82.8v1M26.6 82.6h.8l-.4 .4 .4 .3-.1 .4h-.7M27.7 82.6l.4 1.2 .4-1.2M28.8 82.6h.8l-.4 .4 .4 .3-.1 .5-.7-.1M33.7 89.3v2.7M33.7 94v2.7M83.1 96.7h2.7M86.3 94.9h2.5v3.5h-2.5M57.2 105.4v1.1h1.3l-1.3 1.3-1.3-1.3h1.3M57.2 105.4h.1"/>
<path d="M88 102.9v7.4"/>
</g>
<path d="M31.8 93.8h4M31.8 92.2h4" fill="none" stroke="#980000" stroke-width=".51"/>
<g fill="none" stroke="#980000" stroke-width=".25">
<path d="M85.8 94.9v3.7M86.4 94.6v.9M86.4 96.3v1M86.4 98v1M86.8 105.4h2.5l-1.3 2.5zM88.6 107.3h.7v.6h-2.5v.6h.7"/>
<circle cx="87.2" cy="96.8" r="2.75"/>
</g>
<path d="M86.8 96.3l1 .5-1 .3z" fill="#980000"/>
<path d="M86.7 96.3l1.1 .4-1.1 .4zM88 98.4v.8" fill="none" stroke="#980000" stroke-width=".21"/>
<path d="M87.8 98.2h.4v.4h-.4z" fill="#980000"/>
<path d="M87.8 98.2h.4v.4h-.4z" fill="none" stroke="#980000" stroke-width=".21"/>
<path d="M87.8 94.7h.4v.5h-.4z" fill="#980000"/>
<g fill="none" stroke="#980000" stroke-width=".21">
<path d="M49.8 94.3h2.5M49.8 99.2h2.5M54.9 94.3l.4 1.2 .4-1.2M54.9 98l.4 1.2 .4-1.2M56.2 95h.9M56.2 98.8h.9M56.7 94.5v1M57.2 91.7v2.6M57.2 99.2v2.4M62.1 96.7h2.5M68.3 96.7h1.2M74.5 96.7h1.1"/>
<path d="M80.6 96.7h2.5M87.8 94.7h.4v.5h-.4zM88 91.7v5h-1.7M88 99.2v2.4M88.3 96.3h.8M88.8 96.3l.3 .7h-.8z"/>
</g>
<path d="M50.6 92.7h.7l-.3 .5 .3 .1v.5l-.1 .1h-.4l-.2-.1M50.7 97.7l.1-.1h.4l.1 .1v.5l-.7 .6h.7M56.2 92.9a.35 .35 0 0 1 .5-.2 .35 .35 0 0 1 .1 .6h-.5l-.2-.6h-.4v.6h.3l.2-.2M63 95.5l.4-.4v1.3M63 96.4h.7M81.5 95.5l.3-.4v1.3M81.5 96.4h.7M87.7 92.7v.7l-.9-.7h-.3l.1 .6M56 100.2h.8M56.4 100v.8l-.8-.3M86.5 100.8v-.8l.4 .5 .1-.4h.6v.7" fill="none" stroke="#bd0000" stroke-width=".21"/>
<path d="M52.3 91.8l9.8 5-9.8 4.9zM69.6 95.8h4.9v1.9h-4.9z" fill="none" stroke="#980000" stroke-width=".25"/>
<path d="M53.3 94.4h.9M53.3 99.3h.9M53.7 93.8v1" fill="none" stroke="#007170" stroke-width=".21"/>
<path d="M113.9 113.3h.6l.6 .7-.6 .6h-.6z" fill="#fff"/>
<path d="M113.9 113.3h.6l.6 .7-.6 .6h-.6zM115.5 114.5l.4-1.2 .5 1.2M115.6 114.2h.6M116.8 113.3a.66 .66 0 0 1 .6 .5 .66 .66 0 0 1-.2 .7h-.4zM118.7 113.4l-.6-.1-.1 .3v.7l.1 .2 .6-.1M118.9 114.7h.9M120 114.5l.4-1.2 .4 1.2M120.1 114.2h.6" fill="none" stroke="#805e00" stroke-width=".21"/>
<path d="M108.2 119.7h3.9M108.2 118.1h3.9" fill="none" stroke="#980000" stroke-width=".51"/>
<path d="M110.2 115.2v2.7M110.2 119.8v2.8" fill="none" stroke="#980000" stroke-width=".21"/>
<path d="M152.7 42.5h1.3v.5l-.6 .7-.7-.7z" fill="#fff"/>
<g fill="none" stroke="#805e00" stroke-width=".21">
<path d="M152.8 35v.7h.3l.4-.7 .4 .2v.5M153.1 38.1v.5h.4v-.5h.2h.2v.5M153.1 37h.8v.5l-.2 .1h-.4l-.2-.1zM153.1 36.1l.2 .3M153.1 30l1.1 .4 .1 .2M153.1 39.7h.8M153.1 36.4h.8M153.1 34h.8M153.8 34l.1 .4-.8 .1M153.9 39.2h-.8l.1 .5M153.9 33.4l-.1-.6-.7 .1v.5h1.2M153.9 32.3l-.1-.6-.7 .1v.5h1.2"/>
<path d="M153.9 30.9v.2h-1.2M153.9 30.3l-.8 .3M152.7 42.5h1.3v.5l-.6 .7-.7-.7zM152.8 41.3l-.1 .4 .2 .2h.3l.3-.6h.3l.1 .6M153.9 40.3v.4l-.2 .1-.6-.1v-.4l.3-.1 .1 .6"/>
</g>
<g fill="none" stroke="#980000" stroke-width=".21">
<path d="M105.3 93.1h2.4v6.3l-1.2 1-1.2-1zM106 97.2v-.7l.4 .4 .1-.4h.6v.7M106 95.3l1.1 .4-1.1 .4M106 94.9v-.7l.4 .4 .2-.4 .5 .1v.6M106.2 98.2h.9M106.7 97.7v.9M227.3 93.1h2.5v6.3l-1.2 1-1.3-1zM228 97.2v-.7l.5 .4 .1-.4h.5l.1 .2v.4l-.1 .1M228 95.3l1.2 .4-1.2 .4M228 94.9v-.7l.5 .4 .1-.4h.4l.2 .2v.4l-.1 .1M228.3 98.2h.9M228.7 97.7v.9"/>
<path d="M106.5 102.9v7.4M232.3 115.2v2.7M232.3 119.8v2.8M232.3 125.1v1.2h1.2l-1.2 1.2-1.3-1.2h1.3M232.3 125.1h.1"/>
</g>
<path d="M106.5 105.4l1.3 2.5h-2.5zM107.2 104.7h.6v.7h-2.5v.6h.6" fill="none" stroke="#980000" stroke-width=".25"/>
<path d="M230.2 119.7h4M230.2 118.1h4" fill="none" stroke="#980000" stroke-width=".51"/>
<path d="M209.4 117.6h1.3v1.3h-1.3z" fill="#fff"/>
<path d="M209.4 117.6h1.3v1.3h-1.3zM210 119.7l.2-.3 .4 .1v.6h-1.2v-.5l.4-.1 .2 .2v.4M209.4 126.7v.6h.5a.47 .47 0 0 1 .2-.5 .47 .47 0 0 1 .5 0v.6M209.4 123.5h1.2v.4l-.6 .2-.2-.2v-.4M209.8 121.4v.3l.2 .1M209.8 125.1h.8M209.8 121.8h.8M210.6 125.7v.5h-.8v-.5l.3-.1 .1 .6M210.6 124.6l-.8 .1 .1 .4M210.6 122.4v.5l-.2 .1-.6-.1v-.5h.3l.1 .6M210.8 120.4v1" fill="none" stroke="#805e00" stroke-width=".21"/>
<path d="M218.7 113h5v2h-5z" fill="none" stroke="#980000" stroke-width=".25"/>
<path d="M217.5 114h1.1M223.6 114h1.2" fill="none" stroke="#980000" stroke-width=".21"/>
<path d="M235.9 113.3h.7l.6 .7-.6 .6h-.7z" fill="#fff"/>
<path d="M235.9 113.3h.7l.6 .7-.6 .6h-.7zM237.6 114.5l.4-1.2 .4 1.2M237.7 114.2h.6M238.8 113.3h.5l.2 .3 .1 .4-.3 .5h-.5zM240.7 113.4v-.1a.66 .66 0 0 0-.7 .5 .66 .66 0 0 0 .2 .7l.5-.1M241 114.7h.9M242.2 113.9l.6-.1v-.5h-.6v1.2l.7-.1v-.3l-.3-.2" fill="none" stroke="#805e00" stroke-width=".21"/>
<g fill="none" stroke="#980000" stroke-width=".25">
<path d="M207.9 94.9v3.7M208.4 94.6v.9M208.4 96.3v1M208.4 98v1M228.6 105.4l1.3 2.5h-2.6zM229.2 104.7h.7v.7h-2.6v.6h.7"/>
<circle cx="209.2" cy="96.8" r="2.75"/>
</g>
<path d="M205.1 96.7h2.7M208.3 94.9h2.5v3.5h-2.5M228.6 102.9v7.4" fill="none" stroke="#980000" stroke-width=".21"/>
<path d="M208.9 96.3l1 .5-1 .3z" fill="#980000"/>
<path d="M208.8 96.3l1 .4-1 .4zM210.1 98.4v.8" fill="none" stroke="#980000" stroke-width=".21"/>
<path d="M209.9 98.2h.4v.4h-.4z" fill="#980000"/>
<path d="M209.9 98.2h.4v.4h-.4z" fill="none" stroke="#980000" stroke-width=".21"/>
<path d="M209.9 94.7h.4v.5h-.4z" fill="#980000"/>
<g fill="none" stroke="#980000" stroke-width=".21">
<path d="M192.8 62.2h1.2M199 62.2h1.2M205.1 62.2h2.7M208.3 60.5h2.5v3.4h-2.5M210.1 72.1v1.2M210.1 78.2v1.3M202.6 96.7h2.5M209.9 94.7h.4v.5h-.4zM210.1 91.7v5h-1.8M210.1 99.2v2.4M210.4 96.3h.8M210.8 96.3l.4 .7h-.8z"/>
<path d="M210.1 102.9v7.4"/>
</g>
<path d="M203.6 95.5l.3-.4v1.3M203.6 96.4h.7M209.8 92.7v.7l-1-.7-.3 .2 .1 .4M208.5 100.8v-.8l.5 .5 .2-.5h.3l.3 .3v.3l-.2 .2" fill="none" stroke="#bd0000" stroke-width=".21"/>
<g fill="none" stroke="#980000" stroke-width=".25">
<path d="M194.1 61.2h4.9v2h-4.9zM207.9 60.4v3.7M208.4 60v1M208.4 61.7v1M208.4 63.5v.9M209.1 73.3h2v4.9h-2zM208.9 105.4h2.4l-1.2 2.5zM210.7 107.3h.6v.6h-2.4v.6h.6"/>
<circle cx="209.2" cy="62.2" r="2.75"/>
</g>
<path d="M208.9 61.9l1 .3-1 .4z" fill="#980000"/>
<path d="M208.8 61.8l1 .4-1 .3zM210.1 63.9v.7" fill="none" stroke="#980000" stroke-width=".21"/>
<path d="M209.9 63.7h.4v.4h-.4z" fill="#980000"/>
<path d="M209.9 63.7h.4v.4h-.4z" fill="none" stroke="#980000" stroke-width=".21"/>
<path d="M209.9 60.3h.4v.4h-.4z" fill="#980000"/>
<path d="M210.1 57.3v4.9h-1.8M210.1 48.6v1.2M210.1 54.8v1.2M224.8 48.6v1.2M224.8 54.8v1.2M224.8 57.3v1.2M202.6 62.2h2.5M209.9 60.3h.4v.4h-.4zM210.1 64.6v2.5M210.4 61.8h.8M210.8 61.8l.4 .6h-.8zM224.8 63.5v1.1" fill="none" stroke="#980000" stroke-width=".21"/>
<path d="M209.8 58.1v.8l-1-.8-.3 .3 .1 .5M203.6 61l.3-.3v1.1M203.6 61.8h.7M208.5 66.3v-.7l.5 .3 .1-.3h.5l.2 .1-.2 .6" fill="none" stroke="#bd0000" stroke-width=".21"/>
<path d="M209.1 49.9h2v5h-2zM223.9 49.9h2v5h-2zM223.9 58.5h2v5h-2z" fill="none" stroke="#980000" stroke-width=".25"/>
<path d="M167.1 92.5l.3 1.3 .4-1.3M168.3 92.9v.9M168.6 92.9l-.3 .3M168.9 93.3l.6-.1v-.2l-.3-.1-.3 .2v.5l.3 .2 .3-.1M170 92.9h.4M170.4 92.5l-.3 .1v1.2" fill="none" stroke="#0c0c0c" stroke-width=".21"/>
<path d="M189.1 61.6h.6l.7 .6-.7 .6h-.6z" fill="#fff"/>
<g fill="none" stroke="#805e00" stroke-width=".21">
<path d="M176.1 61.5v1.3M176.1 62.1h.6M176.7 61.5v1.3M177.3 61.5v.1M177.3 61.9v.9M178.4 61.9v1l-.2 .3-.3-.1M178.4 62l-.3-.1-.3 .3 .1 .5h.5M179 62l.4-.1 .1 .2v.7M179 61.5v1.3M180.1 62.2h.5l.2-.2v-.4l-.7-.1v1.3M180.5 62.2l.3 .6M181.3 62.4l.6-.2-.2-.3-.4 .2v.5l.2 .2 .3-.1"/>
<path d="M182.8 62l-.2-.1-.3 .3 .4 .2 .2 .2-.2 .2-.4-.1M183.4 61.5v.1M183.4 61.9v.9M184.6 61.6h-.6a.57 .57 0 0 0 .6 .7v.3l-.2 .2-.5-.1M185.1 62.4l.6-.2-.2-.3-.4 .2v.5l.2 .2 .3-.1M186 61.9h.6M186.2 61.5v1.1l.4 .2M186.6 62.9h1M187.9 62.1l.6-.1v-.4l-.6-.1v1.3h.4l.3-.4-.3-.3M189.1 61.6h.6l.7 .6-.7 .6h-.6z"/>
</g>
<path d="M87 49.9h2.1v5h-2.1zM101.8 49.9h2v5h-2zM101.8 59.8h2v4.9h-2zM87 73.3h2.1v4.9h-2.1zM178 91.8l9.9 5-9.9 4.9zM191.6 95.8h4.9v1.9h-4.9z" fill="none" stroke="#980000" stroke-width=".25"/>
<path d="M88 48.6v1.2M88 54.8v1.2M102.8 48.6v1.2M102.8 54.8v1.2M102.8 58.5v1.2M88 72.1v1.2M88 78.2v1.3M102.8 64.6v1.3M175.6 94.3h2.4M175.6 99.2h2.4M187.8 96.7h3.8M196.5 96.7h1.2" fill="none" stroke="#980000" stroke-width=".21"/>
<path d="M177 97.6a.72 .72 0 0 0-.6 .5 .72 .72 0 0 0 .3 .7h.4a.42 .42 0 0 0-.1-.6 .42 .42 0 0 0-.5 0l-.1 .1M177.1 92.7h-.6l-.1 .6 .6-.1 .2 .1v.4l-.3 .2h-.3l-.2-.1M188.7 95.1h.8l-.5 1.3" fill="none" stroke="#bd0000" stroke-width=".21"/>
<path d="M179 94.4h1M179 99.3h1M179.5 93.8v1" fill="none" stroke="#007170" stroke-width=".21"/>
<path d="M67 61.6h.7l.6 .6-.6 .6h-.7z" fill="#fff"/>
<g fill="none" stroke="#805e00" stroke-width=".21">
<path d="M54.1 61.5v1.3M54.1 62.1h.7M54.8 61.5v1.3M55.4 61.5v.1M55.4 61.9v.9M56.6 61.9v1l-.3 .3-.3-.1M56.6 62h-.6v.6l.2 .2 .4-.1M57.1 62l.4-.1 .2 .2v.7M57.1 61.5v1.3M58.3 62.2l.6-.1v-.5l-.6-.1v1.3M58.5 62.2l.5 .6M59.4 62.4l.6-.2v-.2l-.4-.1-.2 .2v.5l.2 .2 .4-.1"/>
<path d="M61 62l-.3-.1-.2 .2 .2 .3h.3v.3h-.5M61.5 61.5v.1M61.5 61.9v.9M62.8 61.6h-.7v.4l.6 .2 .1 .2-.3 .4-.4-.1M63.3 62.4l.5-.2v-.2h-.5v.7h.5M64.2 61.9h.4M64.4 61.5v1.2l.2 .1M64.8 62.9h.9M65.8 62.8l.4-1.3 .5 1.3M65.9 62.4h.6M67 61.6h.7l.6 .6-.6 .6h-.7z"/>
</g>
<g fill="none" stroke="#980000" stroke-width=".25">
<path d="M72 61.2h5v2h-5zM85.8 60.4v3.7M86.4 60v1M86.4 61.7v1M86.4 63.5v.9"/>
<circle cx="87.2" cy="62.2" r="2.75"/>
</g>
<path d="M70.7 62.2h1.3M76.9 62.2h1.3M83.1 62.2h2.7M86.3 60.5h2.5v3.4h-2.5" fill="none" stroke="#980000" stroke-width=".21"/>
<path d="M86.8 61.9l1 .3-1 .4z" fill="#980000"/>
<path d="M86.7 61.8l1.1 .4-1.1 .3zM88 63.9v.7" fill="none" stroke="#980000" stroke-width=".21"/>
<path d="M87.8 63.7h.4v.4h-.4z" fill="#980000"/>
<path d="M87.8 63.7h.4v.4h-.4z" fill="none" stroke="#980000" stroke-width=".21"/>
<path d="M87.8 60.3h.4v.4h-.4z" fill="#980000"/>
<g fill="none" stroke="#980000" stroke-width=".21">
<path d="M88 57.3v4.9h-1.7M80.6 62.2h2.5M87.8 60.3h.4v.4h-.4zM88 64.6v2.5M88.3 61.8h.8M88.8 61.8l.3 .6h-.8zM24 81.9h6.2l1.1 1.3-1.1 1.2h-6.2zM25.2 83.3h.9M25.6 82.8v1M26.6 82.6h.8l-.4 .4 .4 .3-.1 .4h-.7M27.7 82.6l.4 1.2 .4-1.2M28.8 82.6h.8l-.4 .4 .4 .3-.1 .5-.7-.1"/>
<path d="M105.3 93.1h2.4v6.3l-1.2 1-1.2-1zM106 97.2v-.7l.4 .4 .1-.4h.6v.7M106 95.3l1.1 .4-1.1 .4M106 94.9v-.7l.4 .4 .2-.4 .5 .1v.6M106.2 98.2h.9M106.7 97.7v.9M227.3 93.1h2.5v6.3l-1.2 1-1.3-1zM228 97.2v-.7l.5 .4 .1-.4h.5l.1 .2v.4l-.1 .1M228 95.3l1.2 .4-1.2 .4M228 94.9v-.7l.5 .4 .1-.4h.4l.2 .2v.4l-.1 .1M228.3 98.2h.9M228.7 97.7v.9"/>
</g>
<path d="M87.7 58.1v.8l-.9-.8-.3 .2 .1 .6M81.5 61l.3-.3v1.1M81.5 61.8h.7M86.5 66.3v-.7l.4 .3 .1-.3h.6v.7" fill="none" stroke="#bd0000" stroke-width=".21"/>
<g fill="none" stroke="#00a200" stroke-width=".21">
<path d="M88 48.6v-2.4h136.8v2.4M88 56v1.3M102.8 46.2v2.4M102.8 56v2.5M153.4 43.7v2.5M210.1 46.2v2.4M210.1 56v1.3M224.8 56v1.3M68.3 62.2h2.4M78.2 62.2h2.4M88 67.1v5M88 79.5v12.2"/>
<path d="M102.8 65.9v3.6h-14.8M190.4 62.2h2.4M200.2 62.2h2.4M210.1 67.1v5M210.1 79.5v12.2M224.8 64.6v4.9h-14.7M31.3 83.2h25.9v8.5M33.7 83.2v6.1M33.7 96.7v7.4h23.5M47.4 94.3h2.4M64.6 96.7h3.7M75.6 96.7h5"/>
<path d="M88 86.8h-50.5v12.4h12.3M170.6 94.3h5M197.7 96.7h4.9M210.1 81.9h-46.9v17.3h12.4M57.2 101.6v3.8M88 101.6v1.3M88 110.3v8.6M88 114h7.4M102.8 114h11.1M106.5 100.4v2.5M106.5 110.3v3.7M110.2 114v1.2"/>
<path d="M210.1 114h7.4M210.1 101.6v1.3M210.1 110.3v7.3M224.8 114h11.1M228.6 100.4v2.5M228.6 110.3v3.7M232.3 114v1.2M110.2 122.6v2.5M232.3 122.6v2.5"/>
</g>
<g fill="none" stroke="#001dcd" stroke-width=".21">
<path d="M118.8 51.1h51.8v24.6h-51.8zM120 53.3l.3-1.3 .5 1.3M120 56h.8l-.5 .5 .5 .1v.6h-.8M120.1 53h.6M120.2 54.5h.4l.1 .8M120.2 58v1.2h.6M120.2 60v1.3M120.7 54.7l-.6 .3 .2 .3 .4-.1M120.9 60v1.3M121.1 58.5h.6l-.1 .7-.5-.1zM121.2 52h.3l.4 .4v.6l-.4 .3h-.3zM121.4 60v.1"/>
<path d="M121.5 56a.75 .75 0 0 1 .2 1.3l-.4-.3v-.7zM121.8 54.5h-.5l-.1 .2 .1 .5h.5M122.1 58.5l.3 .7 .2-.6 .2 .6 .3-.7M122.3 54.5v.8M122.6 54.5l-.3 .2M122.7 56a.71 .71 0 0 1 .5 .6 .71 .71 0 0 1-.4 .7l-.3-.3v-.7zM123.1 54.6h.6l-.1 .6-.4 .1-.1-.1zM123.1 52.2v-.1a.61 .61 0 0 0-.7 .3 .61 .61 0 0 0 .1 .7l.3 .2 .3-.1M123.1 60v1.3M123.7 56.7l.6-.1 .1-.3-.2-.3h-.5v1.3M124 56.7l.4 .6M124.5 58.5v.7"/>
<path d="M124.6 54.5h-.4v.3l.4 .1 .1 .2-.2 .2-.3-.1M124.6 52.4v.9M124.8 58.5h-.2l-.1 .1M124.9 52.4l-.3 .3M125.3 58.5h.4l.1 .1v.6h-.5l-.1-.2 .6-.3M125.3 52.5l.4-.1 .2 .2v.7M125.6 54.5h-.4v.3l.4 .1 .1 .2-.2 .2-.3-.1M125.9 56.5l.3-.1 .2 .2v.7M125.9 52.8l-.6 .1v.3h.6M126.4 56.8h-.5l-.1 .1 .1 .4 .5-.1M126.4 58.5h.5v.7M126.4 58.5v.7"/>
<path d="M126.4 52.6l.3-.2 .3 .2v.7M126.4 52.4v.9M127 56.6l.1-.2 .4 .1v.8M127 56.4v.9M127.6 54.5h-.4l-.2 .2v.4l.3 .2 .3-.1M128.1 59.2l-.6-.1v-.6h.6v.9l-.2 .2h-.4M128.1 52.4v1.1l-.2 .2-.3-.1M128.1 52.5l-.3-.1-.3 .3 .1 .5h.5M128.2 54.5v.7l.4 .1 .1-.1M128.6 56.5l-.4-.1-.1 .2v.6h.5M128.6 58.9l.6-.2-.1-.2h-.5v.7h.5M128.6 56v1.3"/>
<path d="M128.6 52.9l.6-.1-.1-.4-.5 .2v.5l.2 .2 .4-.1M128.7 54.5v.8M129.3 54.5v.8M129.7 54.5h-.3l-.1 .2M130 56h.8l-.5 .5 .5 .3-.1 .4h-.7M130.1 54.5v.8M130.4 54.5h-.2l-.1 .2M130.6 58.6h.9M130.6 59h.9M130.7 52.2l.4-.2 .3 .4-.8 .9h.8M130.8 54.9l.6-.2-.1-.2h-.5v.1v.6h.5M131.3 56v1.3"/>
<path d="M131.4 56.8l.4 .5M131.8 56.4l-.5 .5M131.9 53.2v.1M131.9 54.6l.5-.1 .1 .8M131.9 54.5v.8M132.4 52h.8l-.6 1.3M132.8 54.5h.5M133 54.1v1l.3 .2M133 58.1l.5-.1 .2 .3-.7 .9h.7M133.2 56.6l.2-.2 .3 .1v.8M133.2 56.4v.9M133.5 52l.4 1.3 .4-1.3"/>
<path d="M133.7 56.6l.3-.2 .3 .2v.7M134.2 59.1v.1M134.7 53.2v.1M134.7 58h.8l-.5 1.2M134.9 56.5l.3-.1 .2 .2v.7M135.1 54.5h-.4l-.1 .1 .1 .3h.4v.3h-.5M135.4 56.8h-.4l-.2 .1 .2 .4 .4-.1M135.4 60h.9l-.6 1.3M135.7 54.5h.4l.2 .2v.4l-.3 .2-.4-.2zM135.8 56.4l.7 .9M136 53.3l.4-1.3 .5 1.3M136.2 53h.6"/>
<path d="M136.5 56.4l-.7 .9M136.8 54.5l.1 .7 .2 .1 .2-.1M137.3 52v1.1l.2 .2M137.3 54.5v.8M137.8 57.9l-1 1.7M137.9 54.5v.8M138 52v1.2l.1 .1M138.2 54.5h-.2l-.1 .2M138.4 56.5l-.4-.1-.1 .2 .1 .2 .4 .1v.3h-.5M138.6 52.6l.1-.2 .4 .1v.7h-.5zM138.6 60l-1.1 1.5M138.9 56.8h.6l-.2-.4-.4 .1v.7h.5"/>
<path d="M139.1 58h.7l-.4 .5 .4 .2v.3l-.1 .2-.6-.1M139.1 54.5h-.4l-.1 .2v.4l.2 .2 .3-.1M139.6 52.4l.2 .9 .3-.6 .1 .6 .3-.9M139.7 54.9l.5-.2v-.2h-.5v.7h.5M139.7 60h.8l-.4 .5 .4 .2-.1 .5-.5 .1-.2-.2M140 56.6l.2-.2 .3 .2v.7M140 56.4v.9M140.4 58.1l.3-.1a.84 .84 0 0 1 .1 1.2l-.4-.1a.78 .78 0 0 1 0-1zM141 60v1.3M141.4 52.5l-.3-.1-.2 .2 .1 .3 .4 .1v.2h-.5M141.5 56.5l-.2-.1-.3 .3 .4 .1 .2 .3-.2 .2-.4-.1M141.6 58.1l.3-.1a.84 .84 0 0 1 .1 1.2l-.4-.1a.78 .78 0 0 1 0-1z"/>
<path d="M141.7 54.5h.5v.8M142 56.7l.4-.3 .3 .3-.1 .5h-.5zM142.2 54.7l-.6 .3 .2 .3 .4-.1M142.8 54.6l.5-.1v.8M142.8 52.4h.4M142.8 54.5v.8M143.2 52l-.2 .1v1.2M143.2 56.4v.9M143.5 52.7l.5-.3 .2 .3-.1 .5h-.5zM143.5 56.4l-.3 .3M143.6 58.6h1M143.6 59h1"/>
<path d="M144.5 54.5l-.6 .1v.6l.2 .1 .4-.1M144.5 54.1v1.2M144.7 52.4v.9M144.9 56.4v.9M145.1 52.4l-.4 .3M145.2 56.4l-.3 .3M145.7 56.8h.5v-.3h-.5v.7h.5M146.4 52.4v.9M146.5 54.5h-.5l-.1 .2 .1 .5h.5M146.5 54.1v1.2M146.8 52.4l-.4 .3M146.8 58.5l-.3 .3h-.2l-.3-.3 .1-.4 .4-.1 .3 .3-.2 .8-.4 .1"/>
<path d="M147.1 54.1h.1M147.1 54.5v.8M147.2 52.9l.5-.1v-.3h-.5v.7h.5M147.2 56.5l-.4-.1-.1 .2 .1 .2 .4 .1v.3h-.5M147.3 58.5h.4l.1 .7M147.3 58.5v.7M147.7 54.5h.4l.2 .2v.4l-.3 .2-.4-.2zM147.7 56v.2M147.7 56.4v.9M147.8 58.6l.1-.1h.4v.7M148 60a.68 .68 0 0 1 .5 .6 .68 .68 0 0 1-.5 .7 .75 .75 0 0 1 0-1.3zM148.3 52.5l.3-.1 .2 .2v.7"/>
<path d="M148.7 56.5h-.4v.3h.3l.2 .3-.2 .2-.3-.1M148.7 59.2l.4-1.2 .5 1.2M148.8 52.8l-.5 .1-.1 .1 .2 .3 .4-.1M148.9 58.9h.6M149.1 56.4h.5M149.3 54.5h-.4l-.2 .2v.4l.3 .2 .3-.1M149.3 56v1.1l.3 .2M149.3 54.1v1.2M149.8 52.5l-.3-.1-.2 .2 .1 .3 .4 .1v.2h-.5M149.8 54.9l.6-.2v-.2h-.5l-.1 .6a.36 .36 0 0 0 .6 .1M150.1 56.5l.3-.1 .2 .2v.7M150.1 59.2l-.2 .2"/>
<path d="M150.4 52.5l.3-.1 .3 .3-.1 .5h-.5zM150.6 56.8h-.4l-.2 .1 .2 .4 .4-.1M151 55.2v.1M151.2 56.6l.1-.2 .4 .2v.7M151.2 56.4v.9M151.5 52.6l.2-.2 .3 .2v.7M151.5 52.4v.9M152.6 52.5h.5v.8M152.8 56.5l-.4-.1-.2 .3 .1 .5h.5M153.1 52.8l-.5 .1-.1 .1 .2 .3 .4-.1M153.3 56.8h.6l-.2-.4-.4 .1v.7h.5M153.7 52.5h.5l.1 .5a.36 .36 0 0 1-.6 .2"/>
<path d="M153.7 52v1.3M154.8 52v1.1l.2 .2M155.3 56.5l.4-.1 .2 .3-.1 .5h-.5M155.3 56.4v1.3M155.4 52.9l.6-.1v-.3l-.4-.1-.2 .2v.5l.2 .2 .4-.1M156.3 56.8h.6v-.3l-.4-.1-.2 .2v.5l.2 .2 .4-.1M157.3 52.4l.4 .9 .2-.9M157.5 56.4v.9M157.9 56.4l-.4 .3M158.4 52.5l.4-.1 .2 .3v.5h-.6zM159.2 56.4v.9M159.5 52v1.1l.2 .2"/>
<path d="M159.5 56.4l-.3 .3M160 56.5l.3-.1 .2 .2v.7M160 52.4h.5M160.1 52v1.1l.4 .2M160.5 56.8h-.4l-.2 .1 .2 .4 .4-.1M160.9 52.5l.3-.1 .2 .2v.7M161.1 56.6l.1-.2 .4 .2v.7M161.1 56.4v.9M161.4 52.8l-.5 .1-.1 .1 .2 .3 .4-.1M162.5 52.4v1.2h-.5M162.5 52.5l-.3-.1-.3 .3 .1 .5h.5M162.7 56.4v1.1l-.2 .2-.3-.1"/>
<path d="M162.7 56.5l-.4-.1-.2 .3 .1 .5h.5M163 52.9l.6-.1v-.3l-.3-.1-.3 .2 .1 .6h.5M163.3 56.8h.5v-.3h-.5v.7h.5M164.4 57.2v.1M165.6 52.5l-.3-.1-.2 .3v.5h.5M165.6 52v1.3M166.2 52.4v.9M166.6 52.4l-.4 .3M166.9 52.7l.4-.3 .3 .3-.1 .5h-.5zM168.1 52.5l.3-.1 .3 .3-.1 .5h-.5M168.1 52.4v1.3M120.1 62.4l.3-.4v1.2"/>
<path d="M120.1 63.2h.7M120.2 64v1.2h.6M120.2 71.9v1.2h.6M120.2 66v1.2M120.2 69.9v1.3M120.2 60.6h.7M120.2 66.6h.7M120.2 70.5h.7M120.9 66v1.2M120.9 69.9v1.3M121.1 64.5h.6v.6l-.2 .1-.4-.1zM121.1 72.4h.6l-.1 .7-.5-.1z"/>
<path d="M121.4 66v.1M121.4 69.9v.2M121.4 60.4v.9M121.4 66.3v.9M121.4 70.3v.9M121.9 62h-.6v.5a.45 .45 0 0 1 .6 .1 .45 .45 0 0 1 0 .6l-.6-.1M122.1 64.4l.3 .8 .2-.6 .2 .6 .3-.8M122.1 72.3l.3 .8 .2-.5 .2 .5 .3-.8M122.5 62.2l.1-.2 .5 .1v.7l-.1 .4h-.4l-.1-.3zM122.5 60.4v1l-.2 .3-.3-.1M122.5 60.5l-.3-.1-.2 .3v.5h.5M122.5 66.3v1l-.2 .3-.3-.1"/>
<path d="M122.5 66.4l-.3-.1-.2 .3v.5h.5M122.5 70.3v1l-.2 .3-.3-.1M122.5 70.4l-.3-.1-.2 .3v.5h.5M123.1 60.6l.2-.2 .4 .1v.8M123.1 66.5l.2-.2 .4 .1v.8M123.1 70.5l.2-.2 .4 .1v.8M123.1 66v1.2M123.1 69.9v1.3M123.7 62.5l.5-.1v.8M123.7 62.4v.8M124.2 62.6v-.2h.5l.1 .8M124.5 64.4v.8"/>
<path d="M124.5 72.3v.8M124.8 64.4l-.3 .2M124.8 72.3h-.2l-.1 .3M125.2 62l.3 1.2 .4-1.2M125.2 60.4v.9M125.2 66.3v.9M125.2 70.3v.9M125.3 64.5l.3-.1 .2 .2v.6M125.3 72.3h.4l.1 .2v.6h-.5l-.1-.3 .6-.2M125.5 60.4l-.3 .3M125.5 66.3l-.3 .3M125.5 70.3l-.3 .3"/>
<path d="M125.8 64.6l-.6 .3 .1 .3 .5-.1M125.9 60.5h.5v.8M125.9 66.4h.5v.8M125.9 70.4h.5v.8M126.4 64.5h.5v.7M126.4 72.4l.5-.1v.8M126.4 64.4v.8M126.4 72.3v.8M126.4 60.7l-.5 .1v.4h.5M126.4 66.7l-.5 .1v.3h.5M126.4 70.6l-.5 .1v.4h.5M127 60.6l.2-.2 .4 .2v.7"/>
<path d="M127 66.5l.2-.2 .3 .1 .1 .8M127 70.5l.2-.2 .4 .2v.7M127 60.4v.9M127 66.3v.9M127 70.3v.9M127.1 62l.4 1.2 .5-1.2M128.1 64.4v1l-.3 .3-.3-.1M128.1 64.5h-.6v.6l.1 .1 .5-.1M128.1 73.1l-.6-.1v-.7h.6v1.1l-.2 .1h-.4M128.4 62.4v.8M128.6 64.8l.6-.2-.2-.2-.4 .1v.6h.5M128.6 72.8l.6-.2-.1-.3h-.5v.8h.5"/>
<path d="M128.7 60.4v1l-.2 .3-.3-.1M128.7 60.5l-.3-.1-.3 .3 .1 .5h.5M128.7 62.4h-.2l-.1 .2M128.7 66.3v1l-.2 .3-.3-.1M128.7 66.4h-.5l-.1 .5a.36 .36 0 0 0 .6 .2M128.7 70.3v1l-.2 .3-.3-.1M128.7 70.4h-.5l-.1 .5a.36 .36 0 0 0 .6 .2M129.1 62.8l.6-.1-.1-.3h-.4l-.1 .2 .1 .6h.4M129.2 60.8l.6-.1-.1-.3-.5 .2v.5l.2 .2 .3-.1M129.2 66.8l.6-.1-.1-.4-.4 .1-.1 .6 .2 .2 .3-.1M129.2 70.7l.6-.1-.1-.3-.5 .2v.5l.2 .2 .3-.1M130 62.4h.5"/>
<path d="M130.5 62h-.2l-.1 .2v1M130.6 64.6h.9M130.6 64.9h.9M130.6 72.5h.9M130.6 72.8h.9M130.8 63.1v.1M131.3 66.3l.3-.3v1.2M131.3 60.6h.9M131.3 60.9h.9M131.3 67.2h.6M131.3 70.5h.9M131.3 70.9h.9"/>
<path d="M133 64.3l.4-.3v1.2M133 72.3l.4-.4v1.2M133 65.2h.7M133 73.1h.7M133 66h-.5v.6l.4-.2 .2 .3-.1 .4h-.5M133.7 60.1l.4-.1 .3 .3-.8 1h.8M133.7 66l.4 .1a.66 .66 0 0 1-.2 1.1 .84 .84 0 0 1-.2-1.2zM133.7 70.3l.4-.4v1.3M133.7 71.2h.7M134.4 72.4l-.3-.2 .1-.2h.6v.3l-.4 .1-.3 .3 .2 .4h.4l.2-.2v-.2l-.2-.3M134.8 64h-.6l-.1 .6 .6-.1 .2 .1v.4l-.2 .2h-.4l-.2-.1M134.8 66.5l.2-.2 .2 .1 .1 .8"/>
<path d="M134.8 66.3v.9M134.9 61.1v.2M135.3 66.6l.2-.3 .3 .1v.8M135.4 72.6l.6-.1v-.5l-.6-.1v1.2M135.5 64h.3l.2 .2v.8l-.2 .2a.71 .71 0 0 1-.3-1.2zM135.5 69.9l-.4 .1-.2 .2v.9h.6v-.6l-.4-.1-.2 .2M135.7 72.6l.4 .5M136.3 66l.4 1.2 .4-1.2M136.4 69.9a.68 .68 0 0 1 .4 .6 .68 .68 0 0 1-.4 .7l-.3-.3a.77 .77 0 0 1 .3-1zM136.6 64.5l.3-.1 .2 .2v.6M136.6 64.4v.8M137.1 64.6l.2-.2 .3 .1v.7"/>
<path d="M137.3 70.6l.7-.1v-.4l-.2-.2h-.5v1.3M137.6 70.6l.4 .6M137.9 71.8v1.7M138 64l.5 1.2 .4-1.2M139.1 71.8v1.7M139.3 65.9l-1 1.6M139.5 70.6h.9M139.9 70.2v1M140.8 72.3l.4-.4v1.2M140.8 73.1h.7M141.1 63.9l-1 1.6M141.2 60.7l.3 .6"/>
<path d="M141.3 66.5v.2l-.5 .1-.1-.2v-.5l.6-.1v.2l-.1 .9-.4 .1M141.5 60.4l-.5 .5M141.9 66.2l.1-.2 .4 .1a.66 .66 0 0 1-.3 1.1l-.1-.1a.67 .67 0 0 1-.1-.9zM142.4 69.9a.72 .72 0 0 0-.5 .5 .72 .72 0 0 0 .2 .8l.4-.1v-.6l-.4-.1-.2 .2M142.5 71.9l-.5 .3v.8l.5 .1 .2-.2v-.3l-.3-.3h-.2l-.2 .3M143 60.6h.9M143 60.9h.9M143.1 64.5l-.2 .2-.5-.1v-.4l.2-.2h.3a.72 .72 0 0 1 .2 .7 .72 .72 0 0 1-.6 .5M143.1 66l.4 .1a.66 .66 0 0 1-.2 1.1 .84 .84 0 0 1-.2-1.2zM143.1 70.6l.6-.1v-.5l-.6-.1v1.3M143.4 70.6l.4 .6M143.6 64.5l.4-.1 .1 .2v.6"/>
<path d="M143.6 64.4v.8M143.7 71.9l-.4 .1a.94 .94 0 0 0 0 1.1h.4l.2-.2v-.3l-.3-.3h-.2l-.3 .3M144.1 64.6l.2-.2 .3 .1v.7M144.2 66.3v.7l.2 .2 .3-.1M144.4 72.6h.5l.2-.2v-.4l-.7-.1v1.2M144.5 70.5l-.2-.4 .2-.2 .4 .1v.4l-.6 .2v.5l.2 .1h.2l.3-.3-.1-.4h-.2M144.6 72.6l.5 .5M144.7 66.3v.9M145.1 65.2l.4-1.2 .4 1.2M145.2 67.2l.4-1.2 .4 1.2M145.2 64.9h.6M145.2 66.8h.6"/>
<path d="M145.8 72.4l-.2-.2a.35 .35 0 0 1 .3-.3 .35 .35 0 0 1 .4 .3l-.1 .1a.51 .51 0 0 0-.5 .3 .51 .51 0 0 0 0 .5h.5l.1-.4-.3-.3M146.1 60.6l-.1 .1h-.6l.1-.6 .3-.1 .2 .1a.85 .85 0 0 1-.3 1.2h-.2M146.4 70.5h1M146.4 70.9h1M146.6 60.2l.2-.2a.68 .68 0 0 1 .5 .6 .68 .68 0 0 1-.5 .7l-.2-.3zM147.3 64.6h.9M147.3 64.9h.9M147.4 66.6h.9M147.4 66.9h.9M147.7 72.5h1M147.7 72.8h1M148.9 70.3l.3-.4v1.3"/>
<path d="M148.9 71.2h.7M149 60.4v.7l.1 .2 .4-.2M149.5 60.4v.9M149.6 64.3l.5-.3v1.2M149.6 65.2h.8M149.7 66.3l.4-.3v1.2M149.7 67.2h.7M149.9 61.3l.4-1.3 .4 1.3M150.1 60.9h.5M150.2 72.3l.3-.4v1.2M150.2 73.1h.6M150.6 69.9l-.4 .1-.1 .2v.9a.42 .42 0 0 0 .5-.1 .42 .42 0 0 0 .1-.5l-.5-.1-.1 .2"/>
<path d="M151.2 61.1v.2M151.4 64l-.4 .1-.2 .9 .3 .2h.2l.3-.2v-.4l-.2-.1h-.4l-.2 .1M151.5 66l-.4 .1-.2 .8a.42 .42 0 0 0 .7 .2l-.1-.6-.3-.1-.3 .3M151.8 69.9a.72 .72 0 0 0-.6 .5 .72 .72 0 0 0 .2 .8l.4-.1a.42 .42 0 0 0 0-.6 .42 .42 0 0 0-.5 0l-.1 .1M151.9 71.9l-.6 .3v.8l.6 .1v-.7l-.3-.1-.3 .3M152.1 65.1v.1M152.4 70.6l.7-.1v-.4l-.7-.2v1.3M152.5 73v.1M152.7 66h-.3l-.3 .2 .1 .9a.36 .36 0 0 0 .6-.2l-.1-.4-.2-.1-.4 .3M152.7 70.6l.4 .6M153.1 72l.4-.1 .3 .4-.8 .8h.8M153.2 64h-.3a.93 .93 0 0 0-.2 1.1l.4 .1 .2-.1v-.5l-.6-.1-.1 .1"/>
<path d="M153.3 67.1v.1M153.9 70.5l-.2-.1a.31 .31 0 0 1 .1-.4 .31 .31 0 0 1 .4 .1v.3l-.5 .1-.1 .4a.35 .35 0 0 0 .4 .3 .35 .35 0 0 0 .3-.3l-.1-.4h-.2M154.4 64h-.3a.93 .93 0 0 0-.2 1.1l.3 .1 .3-.1v-.5l-.6-.1-.1 .1M154.5 66h-.5l-.1 .2v.9h.6v-.6l-.5-.1-.1 .3M154.6 71.8l-.4 1h.8M154.8 72.3v.8M155.4 71.9h.8l-.5 1.2M155.6 64h-.3l-.3 .3v.8l.2 .1 .4-.1v-.6h-.5l-.1 .1M155.6 66a.55 .55 0 0 0-.6 .5l.1 .6 .4 .1 .2-.3v-.2l-.2-.3h-.3l-.2 .3M155.7 70.5h1.1M155.7 70.9h1.1M156.7 72.6l.6-.1v-.5l-.6-.1v1.2"/>
<path d="M156.8 66l-.5 .1-.1 .8 .2 .3 .4-.1 .1-.4-.2-.3h-.3l-.2 .3M156.9 72.6l.4 .5M157.1 64.5h.6v.6l-.2 .1-.4-.1zM158.3 64.5l.3-.1 .2 .2v.6M158.3 66.6l.2-.3 .4 .1v.7h-.5zM158.3 64v1.2M158.4 70.5l-.1-.1a.34 .34 0 0 1 .1-.5 .34 .34 0 0 1 .5 .2l-.1 .3-.5 .1-.1 .4a.42 .42 0 0 0 .7 .2v-.5l-.3-.1M158.9 72.5h.9M158.9 72.8h.9M159.4 64.5l.3-.1 .2 .2v.6M159.4 64.4v.8M159.5 66.5l.1-.2 .4 .1v.8"/>
<path d="M159.5 66v1.2M159.9 64.6l.2-.2 .3 .1v.7M160.1 70.5l-.1 .1h-.5l-.1-.5 .4-.2 .3 .2-.2 1-.4 .1M160.6 66.5l.1-.2 .4 .1 .1 .8M160.6 66.3v.9M161.2 66.6l.1-.3 .3 .1 .1 .8M161.2 70.5v.1h-.6v-.5l.4-.2 .2 .2-.1 1-.5 .1M161.8 71.1v.1M161.9 72.4l-.1 .2a.36 .36 0 0 1-.6-.2v-.2a.42 .42 0 0 1 .7-.2v.8l-.2 .3h-.4M162.3 70.1l.5-.2 .2 .2-.1 .4-.6 .7h.7M162.5 73v.1M163 72l.4-.1 .3 .4-.8 .8h.8"/>
<path d="M163.5 70.3v.7l.2 .2 .3-.1M164 70.3v.9M164.1 71.9h.8l-.4 .4 .4 .3-.1 .5-.7-.1M164.5 71.2l.4-1.3 .4 1.3M164.5 70.8h.6M165.3 72l.5-.1 .3 .3-.8 .9h.8M166.6 72.4l.5-.1v.8M166.6 72.3v.8M167.1 72.5l.1-.2h.4l.1 .8M168 73.1l.4-1.2 .5 1.2M168.2 72.8h.6M112.6 93h42v6.2h-42z"/>
<path d="M113.8 94h.9l-.9 1.2h.9M114 96.6h.6v-.6h-.6v1.2M115.1 94.8l.6-.1-.2-.3h-.3l-.1 .6 .2 .2 .3-.1M115.2 96.4l.1 .7 .3 .1 .2-.1M115.8 96.4v.8M116.1 96.4h.5M116.2 94.5l.2-.1h.3v.8M116.2 94.4v.8M116.4 96v1.1l.2 .1M117.3 94.8l.6-.2a.36 .36 0 0 0-.6-.2v.7h.5M117.9 96h.8l-.8 1.2h.8M118.4 94.4v.8"/>
<path d="M118.7 94.4l-.3 .2M119.1 96.8l.6-.2-.2-.2-.4 .2v.4l.1 .2 .4-.1M120.1 94.4v.8M120.2 96.5l.3-.1 .3 .2v.6M120.2 96.4v.8M120.4 94.4l-.3 .2M120.8 94.8l.6-.1-.2-.3h-.3l-.1 .6 .1 .2 .4-.1M121.3 96.8l.6-.2-.2-.2-.4 .1v.6h.5M122.4 96.4v.8M122.5 94.4h-.5l-.1 .1v.6h.6M122.5 94.4v1.2M122.7 96.4l-.3 .2"/>
<path d="M123.1 94.4v.7h.5M123.6 94.4v.8M124.2 94v.1M124.2 94.4v.8M124.6 96.5l-.4-.1-.2 .2v.4l.2 .2 .4-.1M124.8 94.4v.8M125.1 94.4l-.3 .2M125.2 96v1.1l.1 .1M125.4 94.8l.6-.1-.1-.3h-.4l-.1 .6 .2 .2 .3-.1M125.8 96.5h.5v.6l-.4 .1-.2-.2zM127 94.4h-.3l-.3 .2 .1 .5h.5M127 94v1.2"/>
<path d="M127.3 96.5h-.4v.2l.4 .1v.3h-.4M127.8 96.8l.6-.2v-.1h-.5l-.1 .5a.36 .36 0 0 0 .6 .1M128.6 94.5l.4-.1 .2 .1v.6h-.6zM129 96.4v.8M129.3 96.4l-.3 .1v.1M129.7 94.5l.2-.1h.3l.1 .8M129.7 94.4v.8M130.5 96.4h.4M130.7 96v1.1l.2 .1M131.4 96.5h.5v.6l-.4 .1-.2-.2zM131.6 94.4h.4M131.8 94v1l.2 .2"/>
<path d="M132.5 94.5l.1-.1h.4v.8M132.5 94v1.2M133.2 96.4h.5M133.4 96v1l.3 .2M133.6 94.8l.5-.1-.1-.3h-.4v.7h.5M134.1 96.5l.4-.1 .2 .2v.6M134.1 96v1.2M135.2 96.8l.6-.2-.2-.2-.4 .2v.4l.1 .2 .4-.1M135.5 94h.8l-.5 .4 .5 .3-.1 .4h-.7M136.6 94l.4 1.2 .4-1.2M137.2 96.6h.5l.3-.2-.1-.4h-.7v1.2M137.5 96.6l.5 .6"/>
<path d="M137.7 94h.8l-.5 .4 .4 .1v.6h-.7M138.9 96.5l-.3-.1-.2 .2 .2 .2h.3v.3h-.5M139.4 96.8l.6-.2-.2-.2-.4 .2v.4l.2 .2 .3-.1M139.9 94.4v.8M140.2 94.4l-.3 .2M140.5 96.5h.5v.7M140.5 96.4v.8M140.7 94.4a.36 .36 0 0 1 .6 .2v.6M141.3 94.7l-.6 .1v.3h.6M141.8 94v.1M141.8 94.4v.8M142 96.5h-.4v.2l.4 .1 .1 .2-.2 .2-.3-.1"/>
<path d="M142.4 94v1l.1 .2M142.6 96h.1M142.6 96.4v.8M143 95.1v.1M143.2 96.5h.5v.7M143.2 96.4v.8M144.9 96.4v1l-.2 .2h-.4M144.9 96.5h-.6v.6l.2 .1 .4-.1M146.9 96.5a.36 .36 0 0 0-.6 .1l.1 .5h.5M147.4 96h.1M147.4 96.4v.8M148 96.4v.8"/>
<path d="M148.4 96.4l-.4 .2M149.3 96.5l-.3-.1-.3 .2v.4l.3 .2 .3-.1M149.8 96.4l.1 .7 .3 .1 .2-.1M150.4 96.4v.8M151 96h.1M151 96.4v.8M151.3 96.4h.5M151.6 96v1.1l.2 .1M152.7 96.5l-.3-.1-.2 .2 .2 .2h.3v.3h-.5M153.3 97.1v.1M118.8 118.9h23.5v3.7h-23.5zM121.4 119.8v1.1l.1 .2"/>
<path d="M136.4 119.8a.65 .65 0 0 1 .8 .7 .65 .65 0 0 1-.8 .6zM120.2 120.5l.6-.1v-.5l-.6-.1v1.3M122 120.3h.4l.1 .1v.7M122.5 120.6h-.4l-.1 .2 .1 .3 .4-.1M123.7 120.3h-.4l-.2 .2v.5h.6M124.2 120.7l.6-.1-.2-.3h-.4v.7h.5M126.7 120.3h-.3l-.3 .2 .1 .5h.5M127.2 120.3h.4l.2 .1v.7M127.8 120.6l-.6 .1v.3h.6M128.4 120.3h.3l.3 .2-.1 .5h-.5M128.4 120.3v1.2M130.4 120.4l.2-.1 .3 .1v.7"/>
<path d="M130.4 120.3v.8M131.4 120.7l.6-.1v-.3h-.4l-.2 .1v.5l.2 .2 .4-.1M132.6 120.3h.4l.1 .1v.7M133.1 120.6h-.4l-.2 .2 .2 .3 .4-.1M133.7 120.3v.8M134.1 120.3l-.4 .2M135.2 121.1l.5-1.3 .3 1.3M135.3 120.8h.6M138.4 120l-.3-.2a.61 .61 0 0 0-.5 .8 .61 .61 0 0 0 .8 .4"/>
</g>
<g fill="#00a200">
<circle cx="57.2" cy="104.1" r=".47"/>
<circle cx="88" cy="114" r=".47"/>
<circle cx="33.7" cy="83.2" r=".47"/>
<circle cx="110.2" cy="114" r=".47"/>
<circle cx="102.8" cy="46.2" r=".47"/>
<circle cx="153.4" cy="46.2" r=".47"/>
<circle cx="106.5" cy="114" r=".47"/>
<circle cx="228.6" cy="114" r=".47"/>
<circle cx="210.1" cy="114" r=".47"/>
<circle cx="232.3" cy="114" r=".47"/>
<circle cx="210.1" cy="81.9" r=".47"/>
<circle cx="210.1" cy="46.2" r=".47"/>
<circle cx="210.1" cy="69.5" r=".47"/>
<circle cx="88" cy="69.5" r=".47"/>
<circle cx="88" cy="86.8" r=".47"/>
</g>
<g fill="none" stroke="#970091" stroke-width=".21">
<path d="M27.5 94.8h-.6l-.1 .6 .6-.1 .1 .6-.3 .1-.4-.1M28.2 94.8a.68 .68 0 0 1 .5 .6 .68 .68 0 0 1-.5 .6l-.2-.5 .1-.6zM29 94.8l.4 1.2 .4-1.2M94 122h.6l.1 .5-.8 .6h.8M95.9 122h-.6l-.1 .5 .2-.1h.3l.2 .1v.6h-.7M96.5 122h.4a.86 .86 0 0 1-.1 1.1h-.3zM97.6 122.5l.1-.2 .4 .1 .1 .7M97.6 122.3v.8M98.2 122.5l.1-.2 .3 .1 .1 .7M99.1 122l.3 1.1 .3-.8 .2 .8 .3-1.1M101.6 123.1v-1.1l.4 .8 .4-.8v1.1M103 122h.1"/>
<path d="M103 122.3v.8M103.6 122.5l.2-.2 .3 .1v.7M103.6 122.3v.8M114.8 120.7h-.5v.6l.5-.1v.7l-.4 .1-.1-.2M115.5 120.8l.4-.1a.78 .78 0 0 1-.2 1.3l-.3-.3zM116.5 120.7l.4 1.3 .4-1.3M216.1 122h.6l.1 .3-.8 .8h.8M217.9 122h-.6v.5l.4-.1 .3 .2-.1 .5h-.6M218.6 122h.4a.66 .66 0 0 1-.3 1.1 .84 .84 0 0 1-.1-1.1zM219.7 122.5l.1-.2 .3 .1 .1 .7M219.7 122.3v.8M220.2 122.5l.1-.2 .4 .1v.7"/>
<path d="M221.2 122l.2 1.1 .3-.8 .2 .8 .3-1.1M223.6 123.1v-1.1l.5 .8 .4-.8v1.1M225.1 122h.1M225.1 122.3v.8M225.7 122.5l.1-.2 .3 .1 .1 .7M225.7 122.3v.8M236.9 120.7h-.6v.6l.5-.1 .2 .2v.3l-.2 .3h-.4l-.1-.2M237.6 120.8a.61 .61 0 0 1 .7 .4 .61 .61 0 0 1-.3 .7 .6 .6 0 0 1-.6-.4 .6 .6 0 0 1 .2-.7zM238.5 120.7l.5 1.3 .3-1.3"/>
</g>
<g fill="none" stroke="#007170" stroke-width=".21">
<path d="M72.9 56l.7-.1 .1-.3-.3-.3h-.5v1.3M73.3 56l.4 .6M73.6 58.2l.4-.4v1.2M73.6 59h.7M74.5 55.3l-.4 .9h.8M74.7 55.7v.9M74.8 57.8v1.2M75 58.5l.3 .5M75.3 58.2l-.5 .5M75.6 55.9l-.2-.1a.34 .34 0 0 1 .1-.4 .34 .34 0 0 1 .5 .1l-.1 .3-.5 .1-.1 .2v.2l.3 .3 .4-.2v-.4l-.3-.1M90.8 53.2h.2l.1-.3v1.2M90.8 54.1h.8"/>
<path d="M90.9 51.1l.6-.1 .1-.5-.7-.1v1.3M91.1 51.1l.5 .6M92.2 53.4l-.2-.2 .1-.2 .4-.1 .2 .4-.5 .1-.2 .2v.3l.2 .2 .5-.1v-.5l-.2-.1M92.3 50.3l-.2 1h.7M92.7 50.8v.9M93.3 53.5h.5v-.5l-.5-.1v1.2M93.5 53.5l.4 .6M93.9 50.9l-.2 .3-.4-.1v-.6h.5l.1 .6a.58 .58 0 0 1-.6 .6M105.6 53.2l.4-.3v1.2M105.6 54.1h.7M105.7 51.1l.6-.1v-.5l-.6-.1v1.3M106 51.1l.4 .6"/>
<path d="M107.4 52.9h-.3l-.3 .3 .1 .9a.43 .43 0 0 0 .5-.2 .43 .43 0 0 0 0-.5h-.5l-.1 .2M107.5 50.4h-.6l-.1 .6 .6-.1 .2 .2v.3l-.3 .3-.5-.2M108 53.1l.2-.2a.68 .68 0 0 1 .5 .6 .68 .68 0 0 1-.5 .6l-.2-.2zM108 50.5l.5-.1 .2 .3-.7 1h.7M109.2 53.5h.5l.2-.4-.2-.2h-.5v1.2M109.5 53.5l.4 .6M195 56l.6-.1v-.5l-.6-.1v1.3M195.3 56l.4 .6M195.6 58.2l.4-.4v1.2M195.6 59h.8M196.8 55.3h-.6v.6h.6v.6l-.4 .1-.2-.2M196.9 57.8v1.2"/>
<path d="M197 58.5l.3 .5M197.3 58.2l-.4 .5M198 55.3h-.6l-.1 .6h.7l.1 .4-.3 .3-.5-.2M212.9 53.2l.3-.3v1.2M212.9 51.1h.5l.3-.3-.1-.3-.7-.1v1.3M212.9 54.1h.7M213.2 51.1l.5 .6M214.2 53.4l-.1-.1 .1-.4 .5 .1v.4h-.5l-.1 .1v.5l.1 .1h.3l.3-.2v-.3l-.3-.2M214.8 50.4h-.6l-.1 .6 .6-.1 .1 .2v.3l-.2 .3h-.4l-.1-.2M215.3 53.5h.5l.1-.1v-.4l-.1-.1h-.5v1.2M215.6 53.5l.3 .6M215.9 50.4l-.5 .1a.92 .92 0 0 0 .1 1.2l.4-.2v-.5l-.5-.1-.1 .2"/>
<path d="M227.6 53.2l.4-.3v1.2M227.6 54.1h.8M227.7 51.1h.5l.2-.2v-.4l-.7-.1v1.3M227.7 59.7h.5l.2-.1v-.5l-.7-.1v1.3M228 51.1l.4 .6M228 59.7l.4 .6M229.4 52.9l-.4 .1-.2 .9 .3 .2h.2l.3-.2-.2-.5h-.4l-.2 .2M229.5 59l-.4 .1-.2 1 .2 .2 .5-.2-.1-.5h-.5l-.1 .1M229.6 50.4h-.6l-.1 .6 .6-.1 .1 .6-.2 .2h-.3l-.2-.2M230.2 53l.1-.1a.68 .68 0 0 1 .5 .6 .68 .68 0 0 1-.5 .6 .81 .81 0 0 1-.1-1.1zM230.2 59.1l.3-.1 .3 .3v.8l-.3 .2-.3-.2zM230.8 50.9l-.1 .2a.36 .36 0 0 1-.6-.2v-.2a.42 .42 0 0 1 .7-.2v.8l-.4 .4h-.2"/>
<path d="M231.3 53.5h.6v-.5l-.6-.1v1.2M231.5 53.5l.4 .6M90.9 74.5h.6l.1-.5-.7-.1v1.2M91 76.4h.3a.67 .67 0 0 1 0 1.1l-.3-.1a.78 .78 0 0 1 0-1zM91.1 74.5l.5 .6M92.1 76.9h.6v-.5l-.6-.1v1.2M92.1 62.8h.5l.1 .2 .1 .5-.2 .5h-.5zM92.1 60.5l.1-.2h.5l.1 .2v.8l-.2 .2-.5-.2zM92.3 61.3l.6 .3M92.3 76.9l.4 .6M92.7 73.9h-.6v.6l.4-.2 .2 .2v.6l-.6-.1M93.3 74l.1-.1 .4 .1 .1 .6-.1 .5h-.4l-.1-.2z"/>
<path d="M93.3 64v-1.2l.5 .8 .4-.8v1.2M93.3 60.7l.4-.4v1.2M93.3 61.5h.7M94.8 63.4h.6v-.6h-.6v1.2M95.9 62.8h.7l-.4 .4 .4 .3v.4h-.7M97.2 62.8l.5 .1a.87 .87 0 0 1 0 1.1l-.5-.1a.94 .94 0 0 1 0-1.1zM99 63.3l-.2 .2h-.3l-.2-.2v-.4l.1-.1h.4a.91 .91 0 0 1 0 1.2h-.4M100.1 63.3l-.2 .2h-.2l-.3-.2v-.4l.2-.1 .5 .1v.8l-.2 .3h-.3M100.7 62.8v1.2h.6M105.7 60.9l.6-.1v-.5h-.6v1.2M106 60.9l.4 .6M106.2 62.8l-.4 .1-.2 .8 .1 .3 .6-.1-.1-.6-.3-.1-.3 .3"/>
<path d="M106.8 63.4h.6l.2-.5-.2-.1h-.6v1.2M107.1 63.4l.5 .6M107.5 60.3h-.6l-.1 .5a.45 .45 0 0 1 .6 0 .45 .45 0 0 1 .1 .6h-.7M108 60.3h.7l-.4 .4 .4 .3v.4h-.7M108.2 63.3l-.2-.3 .2-.2h.4l.1 .1v.3a.48 .48 0 0 0-.6 .2 .48 .48 0 0 0 .1 .6l.5-.1v-.4l-.2-.2M212.9 74.5h.6l.2-.5-.2-.1h-.6v1.2M213 76.4l.3-.1a.86 .86 0 0 1 .1 1.2h-.3l-.2-.2zM213.2 74.5l.5 .6M214.1 76.9h.6l.1-.2v-.3l-.7-.1v1.2M214.2 62.8h.5l.1 .2v.7l-.1 .3h-.5zM214.2 60.3h.6a.86 .86 0 0 1-.1 1.2 .46 .46 0 0 1-.6-.4zM214.3 61.3h.3l.4 .3"/>
<path d="M214.4 76.9l.4 .6M214.8 73.9h-.6l-.1 .6 .1-.2h.4l.2 .2v.4l-.1 .2-.6-.1M215.2 73.9h.8l-.5 1.2M215.3 60.3h.8l-.4 .4 .3 .1v.6h-.7M215.4 64v-1.2l.4 .8 .4-.8v1.2M216.8 63.4h.6l.1-.5-.1-.1h-.6v1.2M217.9 62.8h.7l-.3 .4 .3 .2v.5h-.7M219.2 62.9l.5-.1 .1 .1v.8l-.1 .3-.5-.1zM221 63.3l-.2 .2h-.4l-.1-.6 .6-.1 .1 .1-.2 1-.4 .1M222.2 63.3l-.1 .2h-.4l-.2-.1v-.5l.6-.1 .1 .1-.2 1-.4 .1M222.7 62.8v1.2h.6M228.2 61.5a.55 .55 0 0 0-.6 .5v.5l.3 .3h.2l.3-.3v-.3l-.2-.2h-.4l-.2 .2"/>
<path d="M228.9 62.2h.5l.2-.2v-.4l-.7-.1v1.3M229.1 62.2l.5 .6M230.3 62h-.1l-.1-.2a.42 .42 0 0 1 .7-.2l-.1 .4h-.4l-.2 .3v.2l.2 .3 .5-.2v-.4l-.3-.2M25.5 92.7l.4-.4v1.3M25.5 93.6h.8M26.9 92.4l.1-.1a.68 .68 0 0 1 .5 .7 .68 .68 0 0 1-.5 .6 .81 .81 0 0 1-.1-1.2zM27.4 90l-.3-.1a.6 .6 0 0 0-.5 .6 .6 .6 0 0 0 .7 .6l.1-.1M27.8 90l.5-.1 .3 .2-.8 1h.8M28.1 92.4l.2-.1 .3 .3v.7l-.3 .3a.71 .71 0 0 1-.2-1.2zM29 89.9h.8l-.6 1.2M29.2 92.8l.3-.1 .2 .2v.7M29.2 92.7v.9"/>
<path d="M70.5 90.5h.5l.2-.1v-.4l-.7-.1v1.2M70.8 90.5l.4 .6M71.2 92.7l.3-.4v1.3M71.2 93.6h.6M71.9 89.8l-.2 .9h.7M72.3 90.3v.8M72.3 92.3v1.3M72.5 93.1l.4 .5M72.8 89.9h.8l-.5 1.2M72.9 92.7l-.6 .6M92.1 97.2a.65 .65 0 0 1 .7 .7 .65 .65 0 0 1-.7 .6zM92.1 94.9l.2-.1 .5 .1v1l-.2 .1-.5-.1z"/>
<path d="M92.3 95.7l.6 .4M93.3 98.5v-1.3l.5 1 .4-1v1.3M93.3 94.9l.2-.1h.3l.2 .1v.4l-.7 .7h.7M94.8 97.9l.6-.1v-.5l-.6-.1v1.3M95.9 97.2h.7l-.4 .5 .4 .1v.6h-.7M97.2 97.3a.6 .6 0 0 1 .7 .5 .6 .6 0 0 1-.5 .7l-.3-.5zM99 97.8l-.2 .2h-.4l-.1-.2v-.3l.2-.3h.3a.92 .92 0 0 1 0 1.2l-.4 .1M100.1 97.8l-.1 .2h-.4l-.2-.2v-.3l.3-.3 .4 .2v.8l-.2 .2-.3 .1M100.7 97.2v1.3h.6M176 89.9l.4-1.3 .4 1.3M176.1 89.5h.6M177.9 88.7l-.5-.1-.2 .3 .1 .3 .5 .2v.4h-.6"/>
<path d="M178.3 88.8l.2-.2h.4l.1 .2v.4l-.7 .7h.7M179.4 88.6h.8l-.4 .5 .4 .1v.6h-.8M180.6 88.6h.8l-.4 .5 .4 .1v.6h-.8M181.1 86.1v1.3M181.8 88.6h.8l-.4 .5 .4 .3-.1 .4h-.7M182.4 86.3l-.2-.2a.65 .65 0 0 0-.6 .7 .65 .65 0 0 0 .6 .6l.2-.1M182.8 90h1M183.2 86.1l-.3 .9h.8M183.4 86.6v.8M184 88.9l.3-.3h.2l.3 .3v.8l-.3 .2-.5-.2zM184.1 86.7h.5l.2-.3-.3-.3h-.4v1.3h.5l.2-.1v-.4l-.3-.2M185.4 89.1l.3-.1 .3 .3-.1 .5h-.5"/>
<path d="M185.4 89v1.3M186.3 89.9l.4-1.3 .4 1.3M186.4 89.5h.6M187.5 89.2l.2-.2 .4 .2v.7M187.5 89v.9M188.1 89.2l.2-.2 .3 .2v.7M189.2 89.1l.3-.1 .3 .3-.1 .5h-.5M189.2 89v1.3M192.6 90.5h.6v-.5l-.6-.1v1.2M192.8 90.5l.4 .6M193.2 92.7h.1l.2-.4v1.3M193.2 93.6h.7"/>
<path d="M194.3 89.9h-.5l-.1 .6 .6-.1 .1 .1v.4l-.2 .2-.5-.1M194.4 92.3v1.3M194.5 93.1l.4 .5M194.9 92.7l-.5 .6M195.2 89.8l-.3 .9h.7M195.4 90.3v.8M214.2 97.2a.52 .52 0 0 1 .6 .4v.6a.52 .52 0 0 1-.6 .3zM214.2 94.9l.5-.1a.86 .86 0 0 1 0 1.2 .46 .46 0 0 1-.6-.4zM214.3 95.7l.7 .4M215.4 98.5v-1.3l.4 1 .4-1v1.3M215.7 94.8l-.3 .8h.8M215.9 95.2v.8"/>
<path d="M216.8 97.9l.7-.1v-.3l-.2-.3h-.5v1.3M217.9 97.2h.7l-.3 .5 .3 .1v.6h-.7M219.4 97.2l.4 .3v.7l-.4 .3a.9 .9 0 0 1 0-1.3zM221 97.8l-.1 .2h-.5l-.1-.6 .5-.2 .2 .3-.2 .9-.4 .1M222.2 97.8l-.1 .2h-.5l-.1-.6 .4-.2 .3 .3-.2 .9-.4 .1M222.7 97.2v1.3h.6M56.3 109.7a.45 .45 0 0 0-.7 .1l.1 .8a.37 .37 0 0 0 .3 .3 .37 .37 0 0 0 .3-.2v-.4h-.2M57.5 109.6v1.3l-.7-1.3v1.3M58.1 109.6h.4l.3 .2v.7l-.3 .4h-.4zM59 107.1l.4-1.2 .4 1.2M59.1 106.8h.6M59.2 103.4v1.3"/>
<path d="M60.5 103.6l-.3-.2a.65 .65 0 0 0-.5 .6 .65 .65 0 0 0 .5 .7l.3-.2M60.9 106l-.5-.1-.2 .2 .1 .4 .6 .3-.2 .3h-.5M61.3 103.3l-.4 1h.8M61.3 106l.2-.1h.3l.3 .2-.1 .4-.7 .6h.8M61.5 103.8v.9M62 104.7l.4-1.3 .5 1.3M62.1 104.3h.6M62.5 105.9h.8l-.4 .5 .3 .1 .1 .4-.3 .2h-.3l-.2-.1M63.6 105.9h.8l-.4 .5 .4 .1v.5l-.2 .1h-.4l-.2-.1M64.8 105.9h.8l-.5 .5 .5 .1v.5l-.3 .1h-.3l-.2-.1M65.8 107.2h1M67.3 105.9a.46 .46 0 0 1 .6 .4v.4a.46 .46 0 0 1-.6 .4 .86 .86 0 0 1 0-1.2z"/>
<path d="M68.4 106.4l.3-.1 .3 .2v.4l-.3 .2h-.3M68.4 106.3v1.3M69.3 107.1l.4-1.2 .4 1.2M69.4 106.8h.6M70.6 106.5l.1-.2 .4 .2v.6M70.6 106.3v.8M71.1 106.5l.1-.2 .4 .2v.6M72.2 106.4l.3-.1 .3 .2v.4l-.3 .2h-.3M72.2 106.3v1.3M90.9 108h.5l.2-.4-.2-.1h-.5v1.2l.7-.1v-.4l-.3-.2M90.9 104.9l.6 .2 .1 .2v.6l-.5 .3h-.2zM91.9 108.7l.4-1.2 .4 1.2"/>
<path d="M92.1 105.4l.3-.5v1.3M92.1 108.3h.6M92.1 106.2h.6M93 107.5h.7M93.3 107.5v1.2M94.7 107.5h-.6l-.1 .5h.7v.6h-.7M95.5 107.4l-.3 .8h.8M95.8 107.8v.9M97.6 117.6h.7v-.4l-.2-.2h-.5v1.2M97.9 117.6l.4 .6M98.3 119.8l.3-.4v1.3M99.4 117h-.6v.6h.6v.5h-.6"/>
<path d="M99.5 119.4v1.3M99.9 117.4l.4-.4v1.2M99.9 119.8l-.4 .5M99.9 118.2h.7M109.3 107.4l.6-.1v-.4l-.6-.1v1.3h.5l.3-.5-.3-.2M109.3 104.3a.65 .65 0 0 1 .8 .7 .65 .65 0 0 1-.8 .6zM110.4 108.1l.5-1.3 .3 1.3M110.5 104.4h.7v.5l-.8 .7h.8M110.5 107.7h.6M111.5 106.8h.7M111.8 106.8v1.3M113.2 106.8h-.6v.6l.6-.1a.45 .45 0 0 1-.1 .6 .45 .45 0 0 1-.5 .1v-.1"/>
<path d="M114 106.8l-.3 .8h.8M114.2 118.2h.7l-.4 .5 .4 .2-.1 .5-.6-.1M114.3 107.2v.9M115 115.9l-.1-.1a.66 .66 0 0 0-.6 .4 .66 .66 0 0 0 .2 .8l.5-.1M115.4 118.2h.7l-.4 .5 .4 .2-.1 .5-.6-.1M115.4 115.9l.6-.1 .2 .2-.8 1h.8M116.6 118.7h.5l.1 .7M116.6 118.7v.7M116.9 116.3l-.3-.3 .2-.2h.4l.2 .2-.1 .2a.48 .48 0 0 0-.5 .2 .48 .48 0 0 0 0 .6h.4l.2-.2v-.3l-.3-.2M212.9 108h.6v-.5h-.6v1.2h.5l.3-.5-.4-.2M212.9 104.9a.65 .65 0 0 1 .8 .7 .65 .65 0 0 1-.8 .6zM214 108.7l.4-1.2 .4 1.2"/>
<path d="M214.1 104.9h.7l-.4 .5 .4 .1v.6h-.7M214.1 108.3h.6M215 107.5h.8M215.4 107.5v1.2M216.8 107.5h-.6l-.1 .5h.7v.6h-.7M217.5 107.4l-.2 .8h.8M217.9 107.8v.9M219.7 117.6h.6v-.5l-.6-.1v1.2M219.9 117.6l.4 .6M220.3 119.8l.4-.4v1.3M221.4 117h-.6v.6l.5-.1 .2 .2-.1 .4h-.6M221.5 119.4v1.3"/>
<path d="M222 119.8l-.5 .5M222.2 117.6l-.2-.5 .2-.1h.4v.5l-.6 .1v.5l.2 .1h.3l.2-.2-.1-.4h-.1M231.4 107.4l.6-.1v-.3l-.1-.2h-.5v1.3l.6-.1 .1-.4-.2-.2M231.4 104.3a.64 .64 0 0 1 .7 .7 .64 .64 0 0 1-.7 .6zM232.4 108.1l.5-1.3 .4 1.3M232.6 107.7h.6M232.9 104.3l-.3 .9h.8M233.2 104.8v.8M233.5 106.8h.7M233.9 106.8v1.3M235.2 106.8h-.6v.6l.6-.1 .1 .5-.2 .3h-.4l-.1-.2M236.1 106.8l-.4 .8h.8"/>
<path d="M236.3 118.2h.7l-.4 .5 .4 .2v.3l-.2 .2-.5-.1M236.3 107.2v.9M237 115.9l-.5-.1-.2 .5 .2 .7 .5-.1M237.4 118.2h.8l-.4 .5 .4 .2v.3l-.2 .2-.6-.1M237.5 115.9l.6-.1 .1 .5-.8 .7h.8M238.7 118.7h.4l.1 .7M238.7 118.7v.7M239.4 116.3l-.1 .2a.43 .43 0 0 1-.5-.2 .43 .43 0 0 1 0-.5h.5l.1 .2-.2 .9-.4 .1M98.3 120.7h.6M99.6 120.2l.3 .5M109.3 129.4a.46 .46 0 0 0-.7 .2v.7l.1 .2 .4 .1 .2-.2v-.4h-.2M110.5 129.3v1.3l-.7-1.3v1.3"/>
<path d="M111.1 129.3a.65 .65 0 0 1 .8 .7 .65 .65 0 0 1-.8 .6zM220.3 120.7h.7M221.7 120.2l.3 .5M231.3 129.4a.58 .58 0 0 0-.7 .6 .58 .58 0 0 0 .7 .5v-.5h-.2M232.6 129.3v1.3l-.7-1.3v1.3M233.2 129.3a.64 .64 0 0 1 .7 .7 .64 .64 0 0 1-.7 .6z"/>
</g>
</svg>
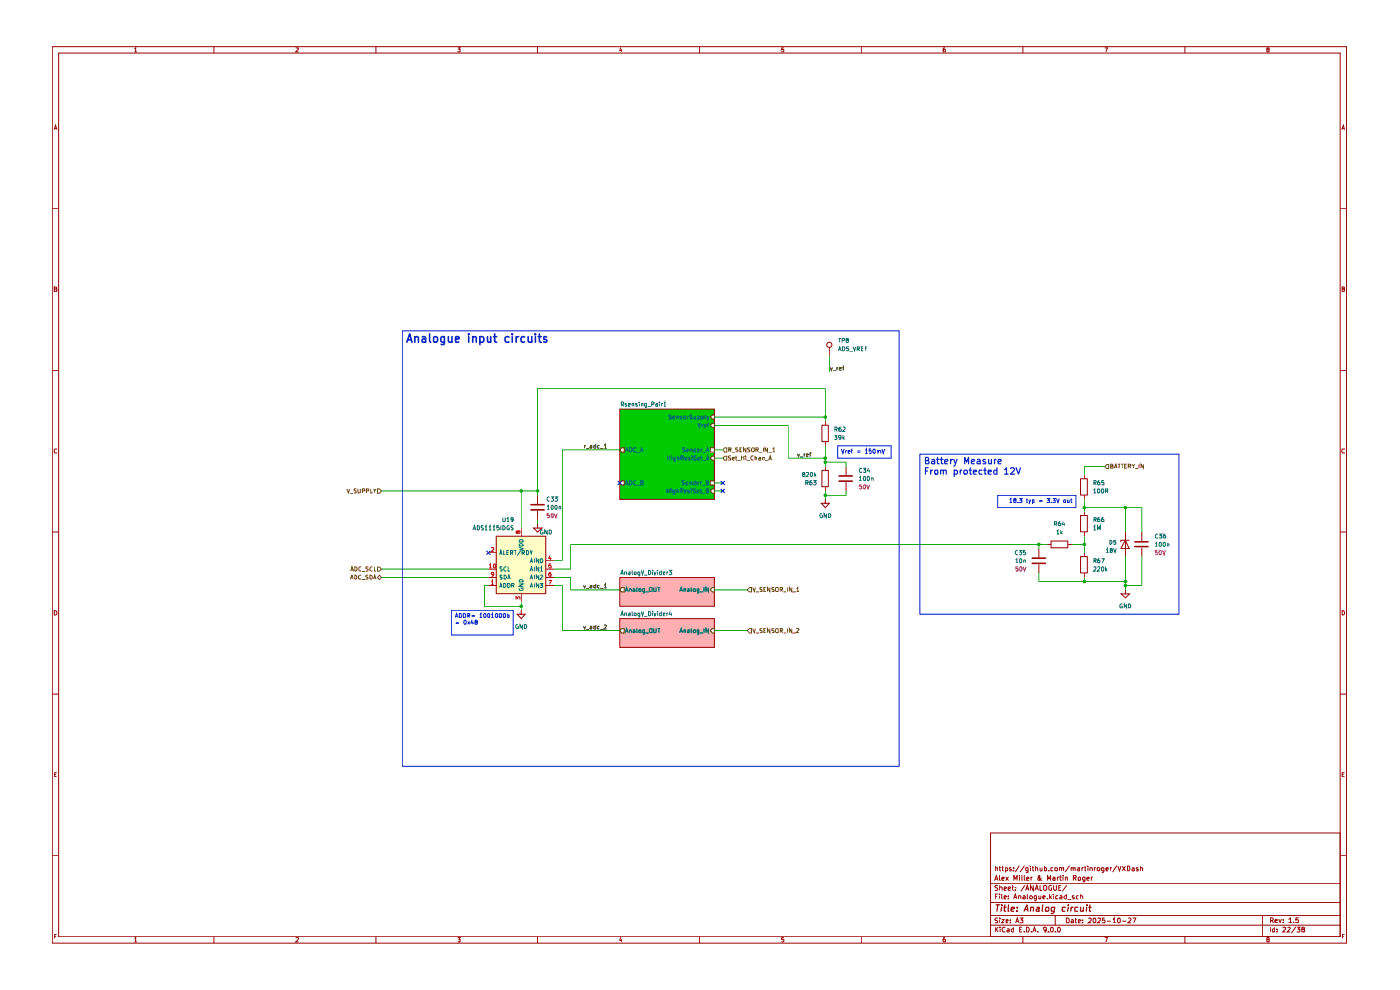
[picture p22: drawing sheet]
<svg xmlns="http://www.w3.org/2000/svg" width="297mm" height="210mm" viewBox="0 0 297 210" stroke-linecap="round" stroke-linejoin="round" font-family="sans-serif">
<g fill="none" stroke="#980000" stroke-width=".21">
<path d="M11.1 9.9h274.6v190.2h-274.6zM12.4 11.3h271.9v187.4h-271.9zM28.5 10.4l.3-.2v.8M28.5 11h.5M45.4 9.9v1.4M62.8 10.2h.4l.1 .2-.6 .6h.6M79.8 9.9v1.4M97.1 10.2h.5l-.2 .3 .2 .1v.3h-.5M114 9.9v1.4M131.7 10.1l-.2 .6h.5M131.9 10.4v.6M148.4 9.9v1.4"/>
<path d="M166.3 10.2h-.4l-.1 .4 .4-.1 .1 .4h-.5M182.7 9.9v1.4M200.5 10.2h-.3l-.1 .6v.2l.5-.1-.1-.4h-.4v.2M217 9.9v1.4M234.4 10.2h.5l-.3 .8M251.4 9.9v1.4M268.9 10.5l-.2-.2 .1-.1h.3l.1 .2-.5 .3 .1 .3 .4-.1v-.3l-.1-.1M11.5 27.5l.3-.9 .3 .9M11.6 27.3h.4M284.6 27.5l.4-.9 .2 .9M284.7 27.3h.5M11.1 44.3h1.3"/>
<path d="M284.3 44.3h1.4M11.1 78.6h1.3M11.5 61.3h.4l.1-.3-.5-.1v.9h.5l.1-.3-.3-.2M284.3 78.6h1.4M284.7 61.3h.5v-.3l-.1-.1h-.4v.9h.5v-.4l-.1-.1M12.1 95.3l-.4-.1-.2 .2v.5l.2 .2 .4-.1M285.2 95.3l-.4-.1-.2 .4 .2 .5 .4-.1M11.1 112.9h1.3M284.3 112.9h1.4M11.5 129.5a.48 .48 0 0 1 .6 .5 .48 .48 0 0 1-.6 .5zM284.7 129.5l.5 .3v.4l-.3 .3h-.2zM11.1 147.2h1.3"/>
<path d="M284.3 147.2h1.4M11.6 164.3h.3M12 163.9h-.4v.9h.4M210.1 176.7h74.2v22h-74.2zM284.7 164.3h.4M285.2 163.9h-.5v.9h.5M11.1 181.5h1.3M11.6 198.6h.3M12 198.2h-.4v.8M28.5 199.1l.3-.2v.9M28.5 199.8h.5M45.4 198.7v1.4"/>
<path d="M62.8 199l.4-.1 .1 .2-.6 .7h.6M79.8 198.7v1.4M97.1 198.9h.5l-.2 .3 .2 .1v.4h-.5M114 198.7v1.4M131.7 198.8l-.2 .7h.5M131.9 199.2v.6M148.4 198.7v1.4M166.3 198.9h-.4l-.1 .4h.5v.4h-.5M182.7 198.7v1.4M200.5 198.9h-.3a.72 .72 0 0 0 0 .9l.4-.1v-.4l-.4-.1-.1 .2M210.1 196.3h74.2M210.1 194.2h74.2"/>
<path d="M210.1 191.4h74.2M210.1 187.4h74.2M211 186.7l.4-1 .3 1M211.1 186.5h.5M211.2 184.1h.4v.6M211.2 183.7v1M211.2 196.7v1M211.2 190.2h.3M211.3 197.1l.4 .6M211.7 194.8l-.4-.1-.2 .3 .1 .2 .5 .2v.3h-.6M211.7 189.6h-.5v1.1M211.7 187.9h-.5a.44 .44 0 0 0 0 .4 .44 .44 0 0 0 .5 .2l-.2 .4-.4-.1"/>
<path d="M211.7 196.7l-.5 .6M211.9 184.1h.4M212 189.6v.1M212 190v.7M212 185.7v.9l.2 .1M212.1 194.7v.1M212.1 188.3l.2-.2 .3 .2v.6M212.1 183.7v1h.2M212.1 187.8v1.1M212.1 195.1v.6M212.2 196.7v.1M212.2 197v.7"/>
<path d="M212.5 195.1h.5l-.5 .6h.5M212.5 189.6v1l.2 .1M212.5 184.1h.4M212.6 186.4l.5-.1-.2-.3-.3 .1v.6h.4M212.7 183.7v1h.2M213 190.3l.5-.1-.1-.2-.4 .1v.6h.4M213 188.5l.5-.1-.1-.3-.4 .1v.6h.4M213.3 196.8a.51 .51 0 0 0-.7 .2 .51 .51 0 0 0 .2 .7l.5-.1M213.3 184.7h.2l.3-.1v-.4l-.2-.1h-.3v1M213.4 186l.5 .7M213.4 195.4l.5-.1-.1-.2-.4 .1v.5h.5M213.7 197.1h.4v.6h-.4l-.1-.3 .5-.1"/>
<path d="M213.9 188.5l.5-.1v-.2l-.4-.1-.1 .2v.4l.1 .2 .4-.1M213.9 186l-.5 .7M213.9 190.6v.1M213.9 190.1v.1M214.4 195.7h.1M214.4 195.2h.1M214.5 184.1h-.3l-.1 .1 .4 .2v.3h-.4M214.7 188.1h.3M214.8 187.8v.9l.2 .2M215 196.7v1h-.3l-.2-.2v-.3l.3-.2 .2 .1M215 190.7l.4-1.1 .3 1.1M215 184.7h.1"/>
<path d="M215 184.1v.1M215.1 186.7v-1l.3 .8 .4-.8v1M215.1 190.4h.5M215.4 188.7v.2M215.4 188.2v.1M215.5 195.7l.3-1 .3 1M215.6 195.5h.5M216.1 190.2l.3-.2 .2 .2v.5M216.1 190v.7M216.2 183.6l-.8 1.4M216.3 185.7v.1M216.3 186v.7"/>
<path d="M216.3 197.2h.4M216.4 194.7h.6l-.3 .5h.3v.5h-.6M216.8 185.7l.1 1M216.8 196.7h-.5v1h.5M217 190.1l.3-.1 .2 .2v.5h-.5v-.4l.5-.1M217 198.7v1.4M217.2 197.6v.1M217.3 185.7v.9l.2 .1M217.3 183.6l-.9 1.4M217.4 187.8l-.8 1.3M217.6 188.9l.3-1.1 .4 1.1M217.7 188.5h.5"/>
<path d="M217.8 196.7a.59 .59 0 0 1 .5 .3 .59 .59 0 0 1-.1 .7h-.4zM217.8 186.4l.5-.1-.2-.3-.3 .1v.6h.4M217.9 189.6v1l.2 .1M218.1 184.7h-.3l-.2-.1 .1-.5h.4v.9h-.4M218.5 190.1l.3-.1 .2 .2-.1 .5h-.4zM218.6 183.7v.1M218.6 184.1v.6M218.7 186v.7M218.8 197.6v.1M218.9 184.1h.5M219 186l-.3 .2M219.1 197.7l.4-1 .3 1"/>
<path d="M219.1 183.7v1h.3M219.2 187.8v1.1l-.6-1.1v1.1M219.2 197.4h.5M219.5 188.9l.5-1.1 .3 1.1M219.7 184.1h.3l.1 .6M219.7 188.5h.4M219.7 183.7v1M219.9 190v.8l-.2 .3-.2-.1M219.9 190.1l-.4-.1-.1 .2 .1 .5h.4M220.1 197.6v.1M220.4 190v.7l.4-.1M220.6 187.8v1.1h.5"/>
<path d="M220.6 184.1v.6h.5M220.8 190v.7M220.8 186.2l-.2 .5-.4-.1v-.3l.4-.3-.1-.3-.2 .3 .4 .6 .3 .1M221.1 184.1v.6M221.2 190.3l.5-.1-.1-.2-.4 .2v.4l.5 .1M221.4 188l.4-.2 .3 .3v.4l-.3 .4-.4-.2zM221.6 184.1h.4v.6h-.4M221.6 183.7v1M222 197.1l-.2 .3-.4-.2v-.4l.4-.1a.83 .83 0 0 1 0 1h-.3M222.2 190.6v.1M222.2 186.7v-1l.3 .8 .4-.8v1M222.4 197.6v.1"/>
<path d="M222.5 184.7h.1M222.7 189.6v1.1M222.8 190.3l.3 .4M222.9 196.8l.3-.1 .2 .1v.7l-.1 .2-.4-.1zM223.1 187.9l-.3-.1-.3 .2v.6l.3 .3 .3-.1v-.4h-.2M223.1 190l-.4 .4M223.4 186.1h.4v.6h-.4l-.1-.2 .5-.2M223.4 184.1h-.5v.6h.5M223.5 189.6v.1M223.5 187.8v.8l.3 .3 .3-.2v-.9M223.5 190v.7M223.9 197.6v.1"/>
<path d="M223.9 184.1h.3l.2 .1-.1 .5h-.3l-.2-.1zM223.9 194.2v2.1M224.3 186v.7M224.4 196.8l.2-.1a.52 .52 0 0 1 .4 .6 .52 .52 0 0 1-.6 .4zM224.4 190.1l-.3-.1-.2 .2 .1 .5h.4M224.6 186l-.3 .2M224.6 188.3h.4M224.8 184.1h.3l.1 .6M224.8 184.1v.6M224.8 186h.4M224.9 190.1h.4v.6h-.4v-.4l.4-.1M224.9 185.7v.9l.3 .1"/>
<path d="M225.1 187.8h-.5v1.1h.5M225.2 184.2l.1-.1h.3v.6M225.5 185.7v.1M225.5 186v.7M226 186.1h.4v.6M226 186v.7M226.2 194.7l.6 .3v.6l-.2 .1h-.4zM226.2 189.6v1.1h-.3l-.2-.5 .3-.2 .2 .1M226.3 187.8l-.9 1.3M226.5 190.8h.7M226.9 183.6l-.9 1.4M227.2 195.2l.4-.1 .1 .1v.5h-.5v-.3l.5-.1"/>
<path d="M227.2 184.1h.4l.1 .6M227.2 184.1v.6M227.7 184.2v-.1h.4v.6M227.7 186.2h.5l.1-.4-.6-.1v1M227.8 190.1l-.2-.1-.1 .3h.2l.2 .3-.4 .1M228 186.2l.3 .5M228.1 195.1h.3M228.2 194.7v1h.2M228.6 184.1h.4v.6M228.7 186.2l.2-.2 .3 .1v.5l-.4 .1zM228.8 195.4l.5-.1-.2-.2-.3 .1v.5h.4M228.8 190.1l-.3-.1-.2 .2v.4l.5 .1"/>
<path d="M229 184.3h-.3l-.2 .2 .2 .2h.3M229.3 190.2l.1-.2 .3 .2v.5M229.3 189.6v1.1M229.5 184.1v.6M229.7 195.7h.1M229.7 195.2h.1M229.9 184.1h-.3l-.1 .1M230 184.1h.4M230.2 186v.9l-.1 .2h-.4M230.2 186.1l-.4-.1-.1 .2v.5h.5M230.2 183.7v1h.2M230.6 186.4l.5-.1-.2-.3-.3 .2v.4l.1 .1h.3"/>
<path d="M230.8 183.7v.1M230.8 184.1v.6M230.9 194.8h.6v.4l-.6 .5h.6M231.2 184.1h.4l.1 .6M231.2 184.1v.6M231.5 186v.7M231.8 186l-.3 .2M232 194.8l.2-.1a.53 .53 0 0 1 .3 .6 .53 .53 0 0 1-.4 .4l-.2-.1zM232.2 184.1v.6M232.5 184.1h-.3v.1M232.8 194.8h.6v.4l-.6 .5h.6M232.8 184.1h.4l.1 .1v.5h-.3l-.3-.1z"/>
<path d="M234.2 184.7h-.3l-.2-.1 .1-.5h.4v.8l-.2 .2-.2-.1M234.4 198.9h.5l-.3 .9M234.4 194.7h-.5l-.1 .5h.5l.1 .1v.4h-.6M234.6 184.4l.5-.1-.1-.2h-.3l-.1 .1v.4l.2 .1h.2M234.9 195.4h.7M235.5 184.1v.6M235.9 184.1h-.3l-.1 .1M236.1 195.1l.3-.4v1M236.1 195.7h.6M236.9 183.6l-.9 1.4M237.1 194.8l.3-.1 .3 .3v.6l-.2 .1h-.4zM237.1 183.7l.4 1 .3-1"/>
<path d="M238.1 195.4h.8M238.1 183.7l.7 1M238.8 183.7l-.7 1M239.2 183.7h.3l.2 .3v.5l-.4 .2h-.1zM239.3 194.8a.33 .33 0 0 1 .5 0 .33 .33 0 0 1 .1 .4l-.6 .5h.6M240.2 184.1h.3l.1 .6M240.3 194.7h.7l-.5 1M240.6 184.3h-.3l-.2 .2 .2 .2h.3M241.5 184.1h-.4l-.1 .1 .5 .2v.3h-.5M242 184.1h.3l.1 .6M242 183.7v1M251.4 198.7v1.4"/>
<path d="M267.8 194.2v4.5M268.9 199.3l-.2-.2 .1-.2h.3l.1 .3-.4 .1-.1 .2 .2 .3 .3-.1v-.3l-.1-.1M269.5 196.7v1M269.5 195.3l.5-.1v-.4l-.5-.1v1M269.8 195.3l.3 .4M270.4 196.7v1h-.4l-.1-.5 .3-.2 .2 .1M270.5 195.4l.5-.1v-.2l-.4-.1-.1 .2v.5h.5M270.9 197.6v.1M270.9 197.1v.1M271.3 195l.3 .7 .2-.7M272.1 196.8h.6v.3l-.6 .6h.6M272.2 195.6v.1"/>
<path d="M272.2 195.1v.1M273.1 196.8l.4-.1 .2 .2-.7 .8h.7M273.4 195l.4-.3v1M273.4 195.7h.6M274.4 195.6v.1M274.9 196.6l-.9 1.3M275.2 196.7h.6l-.4 .4 .4 .1v.4h-.6M275.5 194.7h-.6v.5l.5-.1 .1 .5h-.6M276.3 197.1l-.1-.1v-.2l.3-.1 .3 .1-.1 .3-.5 .1 .1 .5h.4l.1-.3-.3-.3M284.3 181.5h1.4M284.8 198.6h.3M285.2 198.2h-.4v.8"/>
</g>
<g fill="none" stroke="#980000" stroke-width=".25">
<path d="M211.3 191.9h.8M211.7 191.9l-.2 1.4M212.5 191.9v.2M212.5 192.4l-.2 .9M212.9 192.4h.5M213.2 191.9l-.2 1.2 .1 .2h.3M213.9 191.9v1.4h.1M214.5 192.9l.7-.2-.1-.3h-.5l-.1 .7v.2h.5M215.7 193.2v.1M215.8 192.4v.2M217.2 193.3l.6-1.4 .3 1.4M217.4 192.9h.6"/>
<path d="M218.7 192.5l.5-.1v.9M218.7 192.4l-.1 .9M220 192.4h.5l-.1 .9M220.5 192.7l-.5 .1-.2 .2 .1 .3h.6M221.2 191.9l-.1 1.2 .1 .2M222 192.4l.5 .1v.5l-.2 .3h-.5l-.1-.3zM223.7 192.4h-.5l-.2 .3v.5l.6 .1M223.8 192.4l-.2 1.1-.3 .3-.3-.1M226.1 192.4l-.7 .1v.8h.5M226.6 191.9v.2M226.6 192.4l-.1 .9M227.2 192.4v.9"/>
<path d="M227.7 192.4h-.3l-.2 .3M228.7 192.4h-.5l-.2 .3v.5l.6 .1M229.3 192.4v.9l.5-.1M229.9 192.4l-.1 .9M230.5 192.4v.9M230.6 191.9l-.1 .2M231 192.4h.5M231.2 191.9l-.1 1.4h.3"/>
</g>
<path d="M131.9 95h.5v.9h-.5l-.4-.5z" fill="#fff"/>
<path d="M131.5 95.4l.4-.4h.5v.9h-.5z" fill="none" stroke="#805e00" stroke-width=".21"/>
<path d="M132.7 95.8l.2-.8 .4 .8M132.8 95.6h.4M133.5 95h.4l.1 .2v.5l-.1 .1h-.4zM134.9 95.1l-.4-.1-.1 .2v.5l.1 .1h.4M135 95.9h.7M135.8 95.8l.3-.8 .3 .8M135.9 95.6h.4" fill="none" stroke="#007170" stroke-width=".21"/>
<path d="M131.9 102h.5v.9h-.5l-.4-.5z" fill="#fff"/>
<path d="M131.5 102.4l.4-.4h.5v.9h-.5z" fill="none" stroke="#805e00" stroke-width=".21"/>
<path d="M132.7 102.9l.2-1 .4 1M132.8 102.6h.4M133.5 101.9h.3l.2 .3v.4l-.2 .3h-.3zM134.9 102l-.3-.1-.2 .3v.4l.2 .3 .3-.1M135 102.9h.7M136 102.4h.3l.1-.4-.4-.1v1h.3l.2-.4-.3-.1" fill="none" stroke="#007170" stroke-width=".21"/>
<path d="M151.1 96.8h.4v.8h-.4l-.4-.4z" fill="#fff"/>
<path d="M150.7 97.2l.4-.4h.4v.8h-.4z" fill="none" stroke="#805e00" stroke-width=".21"/>
<g fill="none" stroke="#007170" stroke-width=".21">
<path d="M141.6 96.7v.9M141.6 97.1h.5M142.1 96.7v.9M142.5 96.7v.1M142.5 97v.6M143.3 97.5l-.3 .1-.2-.2 .1-.4h.4v.8l-.4 .1M143.7 97.1l.3-.1v.6M143.7 96.7v.9M144.4 97.2l.5-.1v-.3l-.5-.1v.9M144.7 97.2l.2 .4M145.3 97.3l.4-.1v-.2l-.4 .1v.3l.2 .2 .2-.1M146.4 97h-.4v.3l.4 .1-.1 .2-.3-.1"/>
<path d="M146.8 96.7v.1M146.8 97v.6M147.7 96.8l-.4-.1-.2 .2 .1 .2 .5 .2v.2h-.6M148 97.3l.4-.1-.1-.2-.3 .1 .1 .5 .2-.1M148.7 97h.3M148.8 96.7v.7l.2 .2M149.1 97.7h.7M149.9 97.6l.2-.9 .3 .9M149.9 97.4h.4"/>
</g>
<path d="M150.7 104.1l.4-.4h.4v.9h-.4z" fill="#fff"/>
<path d="M151.1 103.7h.4v.9h-.4l-.4-.5z" fill="none" stroke="#805e00" stroke-width=".21"/>
<g fill="none" stroke="#007170" stroke-width=".21">
<path d="M141.5 103.7v.9M141.5 104.1h.4M141.9 103.7v.9M142.3 103.7v.1M142.3 104v.6M143.2 104v.7l-.2 .2-.3-.1M143.2 104h-.5v.5l.5 .1M143.6 104h.2l.1 .1v.5M143.6 103.7v.9M144.4 104.1h.4v-.4h-.4v.9M144.5 104.1l.4 .5M145.2 104.3l.4-.1-.1-.2h-.3v.6h.3"/>
<path d="M146.2 104h-.2l-.1 .1 .4 .4-.4 .1M146.6 103.7v.1M146.6 104v.6M147.6 103.7l-.5 .1v.2l.5 .3-.1 .3h-.4M147.9 104.3l.3-.1v-.2h-.3v.6h.3M148.5 104h.3M148.7 103.7v.9h.1M148.9 104.6h.7M149.9 104.1l.4-.1-.1-.3h-.3v.9l.4-.1v-.3l-.2-.1"/>
</g>
<path d="M151.1 89.8h.4v.9h-.4l-.4-.5z" fill="#fff"/>
<path d="M151.1 89.8h.4v.9h-.4l-.4-.5z" fill="none" stroke="#805e00" stroke-width=".21"/>
<path d="M148.1 89.7l.2 .9 .3-.9M148.9 90.1v.5M149.2 90.1l-.3 .1M149.4 90.3l.5-.1-.1-.1h-.4v.5h.4M150.1 90.1h.3M150.4 89.7l-.2 .1v.8" fill="none" stroke="#007170" stroke-width=".21"/>
<path d="M151.1 88h.4v.9h-.4l-.4-.4z" fill="#fff"/>
<path d="M151.1 88h.4v.9h-.4l-.4-.4z" fill="none" stroke="#805e00" stroke-width=".21"/>
<g fill="none" stroke="#007170" stroke-width=".21">
<path d="M142.4 88l-.5 .1 .1 .3 .4 .2v.2h-.5M142.7 88.6l.5-.1v-.2l-.5 .1v.3l.2 .2 .3-.1M143.6 88.4h.3v.5M143.6 88.3v.6M144.6 88.3h-.2l-.1 .2 .4 .2-.2 .2-.2-.1M145 88.4l.4-.1 .1 .5h-.5zM145.9 88.3v.6M146 88.3h-.1v.2M146.8 88l-.5 .1 .1 .3 .4 .2v.2h-.5M147.2 88.3v.5h.4M147.6 88.3v.6M148 88.8l.2 .1 .2-.2-.1-.4h-.3v.8"/>
<path d="M148.8 88.8h.4l-.1-.5h-.3v.8M149.6 88l.1 .9M149.9 88.3l.3 .6M150.4 88.3l-.2 .6-.3 .2"/>
</g>
<path d="M150.7 95h.8v.9h-.8z" fill="#fff"/>
<path d="M150.7 95h.8v.9h-.8z" fill="none" stroke="#805e00" stroke-width=".21"/>
<path d="M145.3 95h-.4l-.1 .2 .1 .2 .4 .1v.3h-.5M145.6 95.6l.4-.1-.1-.3-.3 .2v.4h.4M146.4 95.3l.2-.1 .2 .2v.4M146.4 95.2v.6M147.6 95v.8h-.4l-.1-.4 .2-.2 .3 .1M148 95.6l.3-.1-.1-.3-.2 .1v.5h.3M148.8 95.2v.6M149 95.2l-.2 .2M149.1 95.9h.7M149.9 95.8l.2-.8 .3 .8M149.9 95.6h.4" fill="none" stroke="#007170" stroke-width=".21"/>
<path d="M150.7 102h.8v.9h-.8z" fill="#fff"/>
<path d="M150.7 102h.8v.9h-.8z" fill="none" stroke="#805e00" stroke-width=".21"/>
<path d="M145.2 102h-.5v.3l.5 .3-.2 .3-.3-.1M145.5 102.5l.4-.1v-.1h-.4v.5h.4M146.3 102.4l.3-.1v.6M146.3 102.3v.6M147.5 102.3l-.4 .1v.4h.4M147.5 101.9v1M147.8 102.5l.4-.1v-.1l-.4 .1v.3l.2 .2 .2-.1M148.6 102.3v.6M148.8 102.3l-.2 .1M148.9 102.9h.7M149.9 102.4h.3l.1-.3-.2-.2h-.2v1h.3l.1-.5h-.2" fill="none" stroke="#007170" stroke-width=".21"/>
<path d="M131.5 86.8h20v19.1h-20z" fill="#00cb00"/>
<path d="M131.9 124.6h.5v1h-.5l-.4-.5z" fill="#fff"/>
<path d="M131.9 124.6h.5v1h-.5l-.4-.5z" fill="none" stroke="#805e00" stroke-width=".21"/>
<g fill="none" stroke="#007170" stroke-width=".21">
<path d="M132.7 125.5l.2-.9 .4 .9M132.8 125.2h.4M133.5 125l.3-.1 .1 .1v.5M133.5 124.9v.6M134.4 125l.1-.1 .2 .1v.5h-.3v-.4h.3M135.1 124.6l.1 .9M135.5 125h.5l-.1 .5-.4-.1zM136.7 124.9v.7l-.1 .2-.2-.1M136.7 125l-.2-.1-.2 .1 .1 .5h.3M136.9 125.6h.7M137.8 124.7h.5v.8l-.5-.1zM138.7 124.6l.1 .9 .4-.1v-.8"/>
<path d="M139.5 124.6h.5M139.8 124.6v.9"/>
</g>
<path d="M151.1 124.6h.4v1h-.4l-.4-.5z" fill="#fff"/>
<path d="M151.1 124.6h.4v1h-.4l-.4-.5z" fill="none" stroke="#805e00" stroke-width=".21"/>
<path d="M144.2 125.5l.3-.9 .3 .9M144.3 125.2h.4M145.1 125h.4v.5M145.1 124.9v.6M145.9 125h.3v.5h-.3l.1-.4h.2M146.6 124.6v.8l.2 .1M147.1 125l.3-.1 .2 .1-.1 .5h-.4zM148.2 124.9v.8h-.3M148.2 125h-.3v.4l.3 .1M148.5 125.6h.7M149.3 124.6v.9M150.3 124.6v.9l-.5-.9v.9" fill="none" stroke="#007170" stroke-width=".21"/>
<path d="M131.5 122.5h20v6.1h-20z" fill="#ffafb1"/>
<path d="M131.9 133.3h.5v1h-.5l-.4-.5z" fill="#fff"/>
<path d="M131.9 133.3h.5v1h-.5l-.4-.5z" fill="none" stroke="#805e00" stroke-width=".21"/>
<g fill="none" stroke="#007170" stroke-width=".21">
<path d="M132.7 134.2l.2-.9 .4 .9M132.8 133.9h.4M133.5 133.7l.3-.1 .1 .2v.4M133.5 133.6v.6M134.4 133.7l.1-.1 .2 .2v.4h-.3v-.3h.3M135.1 133.3l.1 .9M135.5 133.7h.5l-.1 .5-.4-.1zM136.7 133.6v.8l-.1 .1-.2-.1M136.7 133.7l-.2-.1-.2 .2 .1 .4h.3M136.9 134.3h.7M137.8 133.4h.5v.8l-.5-.1zM138.7 133.3l.1 .9 .4-.1v-.8"/>
<path d="M139.5 133.3h.5M139.8 133.3v.9"/>
</g>
<path d="M150.7 133.8l.4-.5h.4v1h-.4z" fill="#fff"/>
<path d="M151.1 133.3h.4v1h-.4l-.4-.5z" fill="none" stroke="#805e00" stroke-width=".21"/>
<path d="M144.2 134.2l.3-.9 .3 .9M144.3 133.9h.4M145.1 133.7h.4v.5M145.1 133.6v.6M145.9 133.7h.3v.5h-.3l.1-.3h.2M146.6 133.3v.8l.2 .1M147.1 133.8l.3-.2 .2 .2-.1 .4h-.4zM148.2 133.6v.8h-.3M148.2 133.7h-.3v.4l.3 .1M148.5 134.3h.7M149.3 133.3v.9M150.3 133.3v.9l-.5-.9v.9" fill="none" stroke="#007170" stroke-width=".21"/>
<path d="M131.5 131.2h20v6.1h-20z" fill="#ffafb1"/>
<path d="M105.3 113.8h10.5v12.2h-10.5z" fill="#fffec7"/>
<path d="M131.9 95h.5v.9h-.5l-.4-.5z" fill="#fff"/>
<path d="M131.5 95.4l.4-.4h.5v.9h-.5z" fill="none" stroke="#805e00" stroke-width=".21"/>
<path d="M132.7 95.8l.2-.8 .4 .8M132.8 95.6h.4M133.5 95h.4l.1 .2v.5l-.1 .1h-.4zM134.9 95.1l-.4-.1-.1 .2v.5l.1 .1h.4M135 95.9h.7M135.8 95.8l.3-.8 .3 .8M135.9 95.6h.4" fill="none" stroke="#007170" stroke-width=".21"/>
<path d="M131.9 102h.5v.9h-.5l-.4-.5z" fill="#fff"/>
<path d="M131.5 102.4l.4-.4h.5v.9h-.5z" fill="none" stroke="#805e00" stroke-width=".21"/>
<path d="M132.7 102.9l.2-1 .4 1M132.8 102.6h.4M133.5 101.9h.3l.2 .3v.4l-.2 .3h-.3zM134.9 102l-.3-.1-.2 .3v.4l.2 .3 .3-.1M135 102.9h.7M136 102.4h.3l.1-.4-.4-.1v1h.3l.2-.4-.3-.1" fill="none" stroke="#007170" stroke-width=".21"/>
<path d="M151.1 96.8h.4v.8h-.4l-.4-.4z" fill="#fff"/>
<path d="M150.7 97.2l.4-.4h.4v.8h-.4z" fill="none" stroke="#805e00" stroke-width=".21"/>
<g fill="none" stroke="#007170" stroke-width=".21">
<path d="M141.6 96.7v.9M141.6 97.1h.5M142.1 96.7v.9M142.5 96.7v.1M142.5 97v.6M143.3 97.5l-.3 .1-.2-.2 .1-.4h.4v.8l-.4 .1M143.7 97.1l.3-.1v.6M143.7 96.7v.9M144.4 97.2l.5-.1v-.3l-.5-.1v.9M144.7 97.2l.2 .4M145.3 97.3l.4-.1v-.2l-.4 .1v.3l.2 .2 .2-.1M146.4 97h-.4v.3l.4 .1-.1 .2-.3-.1"/>
<path d="M146.8 96.7v.1M146.8 97v.6M147.7 96.8l-.4-.1-.2 .2 .1 .2 .5 .2v.2h-.6M148 97.3l.4-.1-.1-.2-.3 .1 .1 .5 .2-.1M148.7 97h.3M148.8 96.7v.7l.2 .2M149.1 97.7h.7M149.9 97.6l.2-.9 .3 .9M149.9 97.4h.4"/>
</g>
<path d="M150.7 104.1l.4-.4h.4v.9h-.4z" fill="#fff"/>
<path d="M151.1 103.7h.4v.9h-.4l-.4-.5z" fill="none" stroke="#805e00" stroke-width=".21"/>
<g fill="none" stroke="#007170" stroke-width=".21">
<path d="M141.5 103.7v.9M141.5 104.1h.4M141.9 103.7v.9M142.3 103.7v.1M142.3 104v.6M143.2 104v.7l-.2 .2-.3-.1M143.2 104h-.5v.5l.5 .1M143.6 104h.2l.1 .1v.5M143.6 103.7v.9M144.4 104.1h.4v-.4h-.4v.9M144.5 104.1l.4 .5M145.2 104.3l.4-.1-.1-.2h-.3v.6h.3"/>
<path d="M146.2 104h-.2l-.1 .1 .4 .4-.4 .1M146.6 103.7v.1M146.6 104v.6M147.6 103.7l-.5 .1v.2l.5 .3-.1 .3h-.4M147.9 104.3l.3-.1v-.2h-.3v.6h.3M148.5 104h.3M148.7 103.7v.9h.1M148.9 104.6h.7M149.9 104.1l.4-.1-.1-.3h-.3v.9l.4-.1v-.3l-.2-.1"/>
</g>
<path d="M151.1 89.8h.4v.9h-.4l-.4-.5z" fill="#fff"/>
<path d="M151.1 89.8h.4v.9h-.4l-.4-.5z" fill="none" stroke="#805e00" stroke-width=".21"/>
<path d="M148.1 89.7l.2 .9 .3-.9M148.9 90.1v.5M149.2 90.1l-.3 .1M149.4 90.3l.5-.1-.1-.1h-.4v.5h.4M150.1 90.1h.3M150.4 89.7l-.2 .1v.8" fill="none" stroke="#007170" stroke-width=".21"/>
<path d="M151.1 88h.4v.9h-.4l-.4-.4z" fill="#fff"/>
<path d="M151.1 88h.4v.9h-.4l-.4-.4z" fill="none" stroke="#805e00" stroke-width=".21"/>
<g fill="none" stroke="#007170" stroke-width=".21">
<path d="M142.4 88l-.5 .1 .1 .3 .4 .2v.2h-.5M142.7 88.6l.5-.1v-.2l-.5 .1v.3l.2 .2 .3-.1M143.6 88.4h.3v.5M143.6 88.3v.6M144.6 88.3h-.2l-.1 .2 .4 .2-.2 .2-.2-.1M145 88.4l.4-.1 .1 .5h-.5zM145.9 88.3v.6M146 88.3h-.1v.2M146.8 88l-.5 .1 .1 .3 .4 .2v.2h-.5M147.2 88.3v.5h.4M147.6 88.3v.6M148 88.8l.2 .1 .2-.2-.1-.4h-.3v.8"/>
<path d="M148.8 88.8h.4l-.1-.5h-.3v.8M149.6 88l.1 .9M149.9 88.3l.3 .6M150.4 88.3l-.2 .6-.3 .2"/>
</g>
<path d="M150.7 95h.8v.9h-.8z" fill="#fff"/>
<path d="M150.7 95h.8v.9h-.8z" fill="none" stroke="#805e00" stroke-width=".21"/>
<path d="M145.3 95h-.4l-.1 .2 .1 .2 .4 .1v.3h-.5M145.6 95.6l.4-.1-.1-.3-.3 .2v.4h.4M146.4 95.3l.2-.1 .2 .2v.4M146.4 95.2v.6M147.6 95v.8h-.4l-.1-.4 .2-.2 .3 .1M148 95.6l.3-.1-.1-.3-.2 .1v.5h.3M148.8 95.2v.6M149 95.2l-.2 .2M149.1 95.9h.7M149.9 95.8l.2-.8 .3 .8M149.9 95.6h.4" fill="none" stroke="#007170" stroke-width=".21"/>
<path d="M150.7 102h.8v.9h-.8z" fill="#fff"/>
<path d="M150.7 102h.8v.9h-.8z" fill="none" stroke="#805e00" stroke-width=".21"/>
<path d="M145.2 102h-.5v.3l.5 .3-.2 .3-.3-.1M145.5 102.5l.4-.1v-.1h-.4v.5h.4M146.3 102.4l.3-.1v.6M146.3 102.3v.6M147.5 102.3l-.4 .1v.4h.4M147.5 101.9v1M147.8 102.5l.4-.1v-.1l-.4 .1v.3l.2 .2 .2-.1M148.6 102.3v.6M148.8 102.3l-.2 .1M148.9 102.9h.7M149.9 102.4h.3l.1-.3-.2-.2h-.2v1h.3l.1-.5h-.2" fill="none" stroke="#007170" stroke-width=".21"/>
<path d="M131.5 86.8h20v19.1h-20z" fill="none" stroke="#980000" stroke-width=".21"/>
<path d="M131.9 124.6h.5v1h-.5l-.4-.5z" fill="#fff"/>
<path d="M131.9 124.6h.5v1h-.5l-.4-.5z" fill="none" stroke="#805e00" stroke-width=".21"/>
<g fill="none" stroke="#007170" stroke-width=".21">
<path d="M132.7 125.5l.2-.9 .4 .9M132.8 125.2h.4M133.5 125l.3-.1 .1 .1v.5M133.5 124.9v.6M134.4 125l.1-.1 .2 .1v.5h-.3v-.4h.3M135.1 124.6l.1 .9M135.5 125h.5l-.1 .5-.4-.1zM136.7 124.9v.7l-.1 .2-.2-.1M136.7 125l-.2-.1-.2 .1 .1 .5h.3M136.9 125.6h.7M137.8 124.7h.5v.8l-.5-.1zM138.7 124.6l.1 .9 .4-.1v-.8"/>
<path d="M139.5 124.6h.5M139.8 124.6v.9"/>
</g>
<path d="M151.1 124.6h.4v1h-.4l-.4-.5z" fill="#fff"/>
<path d="M151.1 124.6h.4v1h-.4l-.4-.5z" fill="none" stroke="#805e00" stroke-width=".21"/>
<path d="M144.2 125.5l.3-.9 .3 .9M144.3 125.2h.4M145.1 125h.4v.5M145.1 124.9v.6M145.9 125h.3v.5h-.3l.1-.4h.2M146.6 124.6v.8l.2 .1M147.1 125l.3-.1 .2 .1-.1 .5h-.4zM148.2 124.9v.8h-.3M148.2 125h-.3v.4l.3 .1M148.5 125.6h.7M149.3 124.6v.9M150.3 124.6v.9l-.5-.9v.9" fill="none" stroke="#007170" stroke-width=".21"/>
<path d="M131.5 122.5h20v6.1h-20z" fill="none" stroke="#980000" stroke-width=".21"/>
<path d="M131.9 133.3h.5v1h-.5l-.4-.5z" fill="#fff"/>
<path d="M131.9 133.3h.5v1h-.5l-.4-.5z" fill="none" stroke="#805e00" stroke-width=".21"/>
<g fill="none" stroke="#007170" stroke-width=".21">
<path d="M132.7 134.2l.2-.9 .4 .9M132.8 133.9h.4M133.5 133.7l.3-.1 .1 .2v.4M133.5 133.6v.6M134.4 133.7l.1-.1 .2 .2v.4h-.3v-.3h.3M135.1 133.3l.1 .9M135.5 133.7h.5l-.1 .5-.4-.1zM136.7 133.6v.8l-.1 .1-.2-.1M136.7 133.7l-.2-.1-.2 .2 .1 .4h.3M136.9 134.3h.7M137.8 133.4h.5v.8l-.5-.1zM138.7 133.3l.1 .9 .4-.1v-.8"/>
<path d="M139.5 133.3h.5M139.8 133.3v.9"/>
</g>
<path d="M150.7 133.8l.4-.5h.4v1h-.4z" fill="#fff"/>
<path d="M151.1 133.3h.4v1h-.4l-.4-.5z" fill="none" stroke="#805e00" stroke-width=".21"/>
<path d="M144.2 134.2l.3-.9 .3 .9M144.3 133.9h.4M145.1 133.7h.4v.5M145.1 133.6v.6M145.9 133.7h.3v.5h-.3l.1-.3h.2M146.6 133.3v.8l.2 .1M147.1 133.8l.3-.2 .2 .2-.1 .4h-.4zM148.2 133.6v.8h-.3M148.2 133.7h-.3v.4l.3 .1M148.5 134.3h.7M149.3 133.3v.9M150.3 133.3v.9l-.5-.9v.9" fill="none" stroke="#007170" stroke-width=".21"/>
<path d="M174.4 90.2h1.3v3.5h-1.3zM175.1 89.3v.9M175.1 93.7v.9M179.5 99v1.8M179.5 102.3v1.8M242.2 112.9v1.9M242.2 116.2v1.9M131.5 131.2h20v6.1h-20zM238.8 125.1v.9h-1l1 .8 .8-.8h-.8M238.8 125.1h.1" fill="none" stroke="#980000" stroke-width=".21"/>
<path d="M178 102.1h2.8M178 101h2.8M240.7 115.9h2.8M240.7 114.9h2.8" fill="none" stroke="#980000" stroke-width=".34"/>
<g fill="none" stroke="#0c0c0c" stroke-width=".21">
<path d="M169.2 96.3l.2 .6 .2-.6M169.8 96.9h.5M170.6 96.3v.6M170.9 96.3l-.3 .1M171.1 96.5l.4-.1-.1-.1h-.3v.5h.3M171.8 96.3h.3M172.1 96l-.2 .1v.8M123.8 124.2l.2 .5 .2-.5M124.4 124.8h.6M125.2 124.2h.4v.5h-.4l-.1-.2 .2-.1h.3M126.4 123.9v.8h-.3l-.1-.5h.4M127.2 124.2l-.5 .1 .1 .4h.4"/>
<path d="M127.3 124.8h.7M128.2 124.1l.2-.2v.8M128.2 124.7h.5"/>
</g>
<path d="M159 124.6h.4v1h-.4l-.5-.5z" fill="#fff"/>
<g fill="none" stroke="#805e00" stroke-width=".21">
<path d="M159 124.6h.4v1h-.4l-.5-.5zM159.7 124.6l.3 .9 .3-.9M160.4 125.6h.6M161.7 124.6l-.5 .1v.3l.5 .2-.1 .3h-.4M162 125h.3M162.5 124.6h-.5v.9h.5M163.3 124.6v.9l-.5-.9v.9M164.2 124.6l-.5 .1v.3l.5 .2v.3h-.5M164.6 124.7h.5l-.1 .8-.4-.1zM165.5 125h.4v-.4h-.4v.9M165.7 125l.3 .5M166.2 125.6h.6"/>
<path d="M167 124.6v.9M168 124.6v.9l-.5-.9v.9M168.1 125.6h.7M169 124.9l.2-.3v.9M169 125.5h.5"/>
</g>
<path d="M124 94.5v.6M124.3 94.5l-.3 .2M124.4 95.2h.6M125.2 94.6h.4v.5h-.4l-.1-.2 .2-.2h.3M126.4 94.2v.9h-.3l-.1-.5h.4M127.2 94.6l-.3-.1-.2 .2 .1 .4h.4M127.3 95.2h.7M128.2 94.5l.2-.3v.9M128.2 95.1h.5" fill="none" stroke="#0c0c0c" stroke-width=".21"/>
<path d="M153.7 96.8h.5v.8h-.5l-.4-.4z" fill="#fff"/>
<g fill="none" stroke="#805e00" stroke-width=".21">
<path d="M153.7 96.8h.5v.8h-.5l-.4-.4zM155 96.8l-.3-.1-.2 .2 .1 .2 .4 .2v.2h-.5M155.4 97.3l.4-.1v-.2l-.4 .1v.3l.1 .2 .3-.1M156 97h.4M156.1 96.7v.7l.3 .2M156.5 97.7h.6M157.3 96.7v.9M157.3 97.1h.5M157.8 96.7v.9M158.2 96.7v.1M158.2 97v.6M158.4 97.7h.7"/>
<path d="M159.8 96.8a.42 .42 0 0 0-.5 .3 .42 .42 0 0 0 .5 .4M160.2 97.1l.3-.1v.6M160.2 96.7v.9M160.9 97l.5 .1v.5M161.4 97.2l-.5 .1 .1 .3 .4-.1M161.8 97.1l.3-.1v.6M161.8 97v.6M162.3 97.7h.7M163.1 97.6l.3-.9 .3 .9M163.1 97.4h.5"/>
</g>
<path d="M153.3 95.4l.4-.4h.5v.9h-.5z" fill="#fff"/>
<g fill="none" stroke="#805e00" stroke-width=".21">
<path d="M153.7 95h.5v.9h-.5l-.4-.5zM154.6 95.4h.4v-.4h-.4v.8M154.8 95.4l.3 .4M155.3 95.9h.6M156.5 95h-.4l-.1 .2 .2 .2 .3 .1v.3h-.5M157 95.4h.2M157.4 95h-.4v.8h.4M158.2 95v.8l-.5-.8v.8M159.1 95h-.4l-.1 .2 .1 .2 .4 .1v.3h-.5M159.5 95.1h.5l-.1 .7h-.4zM160.4 95.4h.4l.1-.3-.5-.1v.8M160.6 95.4l.3 .4"/>
<path d="M161 95.9h.7M162 95v.8M162.8 95v.8l-.5-.8v.8M163.1 95.9h.6M163.9 95.2l.3-.2v.8M163.9 95.8h.4"/>
</g>
<path d="M174.4 99.8h1.3v3.4h-1.3zM175.1 99v.8M175.1 105.9v.9h.8l-.8 .9-.9-.9h.9M175.1 105.9h.1M175.1 103.3v.8" fill="none" stroke="#980000" stroke-width=".21"/>
<path d="M176.2 78l.2 .6 .2-.6M176.7 78.6h.7M177.5 78v.6M177.8 78l-.3 .1M178 78.2l.5-.1v-.1l-.5 .1v.3l.2 .2 .3-.1M178.7 78h.4M179.1 77.6l-.2 .1v.9" fill="none" stroke="#0c0c0c" stroke-width=".21"/>
<path d="M80.1 120.3h.4l.4 .4-.4 .5h-.4z" fill="#fff"/>
<path d="M74.4 121.2l.3-1 .3 1M74.5 120.9h.4M75.3 120.2a.47 .47 0 0 1 .5 .5 .47 .47 0 0 1-.5 .5zM76.6 120.3l-.2-.1-.3 .3v.4l.3 .3 .2-.1M76.8 121.2h.7M78.1 120.3h-.5v.3l.5 .3-.1 .3-.4-.1M79 120.3l-.3-.1-.2 .3v.4l.2 .3 .3-.1M79.4 120.2v1h.4M80.1 120.3h.4l.4 .4-.4 .5h-.4z" fill="none" stroke="#805e00" stroke-width=".21"/>
<path d="M80.1 103.7h.4l.4 .4-.4 .5h-.4z" fill="#fff"/>
<path d="M73.6 103.7l.3 .9 .3-.9M74.2 104.6h.7M75.6 103.7h-.4l-.1 .2 .5 .4-.1 .3h-.4M75.9 103.7l.1 .9 .4-.1v-.8M76.9 104.1h.4l.1-.3-.5-.1v.9M77.7 104.1h.4l.1-.3-.5-.1v.9M78.6 103.7v.9h.5M79.2 103.7l.3 .4 .3-.4M79.5 104.1v.5M80.1 103.7h.4l.4 .4-.4 .5h-.4z" fill="none" stroke="#805e00" stroke-width=".21"/>
<path d="M80.5 122l.4 .5-.4 .4-.4-.4z" fill="#fff"/>
<path d="M74.3 122.8l.4-.8 .2 .8M74.4 122.6h.4M75.3 122l.4 .2v.5l-.2 .1h-.2zM76.6 122.1a.44 .44 0 0 0-.6 .2 .44 .44 0 0 0 .2 .5h.4M76.8 122.9h.7M78.1 122.1l-.4-.1-.2 .2 .2 .2 .4 .1-.1 .3h-.5M78.5 122a.47 .47 0 0 1 .5 .3 .47 .47 0 0 1-.2 .5h-.3zM79.2 122.8l.3-.8 .3 .8M79.3 122.6h.4M80.5 122l.4 .5-.4 .4-.4-.4z" fill="none" stroke="#805e00" stroke-width=".21"/>
<path d="M123.8 132.8l.2 .6 .2-.6M124.4 133.5h.6M125.2 132.9h.4v.5h-.4l-.1-.1 .2-.2h.3M126.4 132.6v.8h-.3l-.1-.5h.4M127.2 132.9l-.3-.1-.2 .2 .1 .4h.4M127.3 133.5h.7M128.2 132.7l.3-.1 .2 .2-.6 .6h.6" fill="none" stroke="#0c0c0c" stroke-width=".21"/>
<path d="M158.5 133.8l.5-.5h.4v1h-.4z" fill="#fff"/>
<g fill="none" stroke="#805e00" stroke-width=".21">
<path d="M158.5 133.8l.5-.5h.4v1h-.4zM159.7 133.3l.3 .9 .3-.9M160.4 134.3h.6M161.7 133.3l-.5 .1v.3l.5 .2-.1 .3h-.4M162 133.8h.3M162.5 133.3h-.5v.9h.5M163.3 133.3v.9l-.5-.9v.9M164.2 133.3l-.5 .1v.3l.5 .2v.3h-.5M164.6 133.4h.5l-.1 .8-.4-.1zM165.5 133.8h.4v-.5h-.4v.9M165.7 133.8l.3 .4M166.2 134.3h.6"/>
<path d="M167 133.3v.9M168 133.3v.9l-.5-.9v.9M168.1 134.3h.7M169 133.4l.4-.1 .1 .3-.6 .6h.6"/>
</g>
<g fill="none" stroke="#980000" stroke-width=".21">
<path d="M175.9 73.7v1.7M103.6 117.3h1.7M105.3 113.7h10.5v12.2h-10.5zM110.6 112v1.8M114 111.2v.8h1l-1 .9-.8-.9h.8M114 111.2h.1M114 105.1v1.8M114 108.4v1.8M115.8 119h1.8M103.6 120.7h1.7M103.6 122.5h1.7M103.6 124.2h1.7"/>
<path d="M110.6 129.4v.9h.8l-.8 .9-.9-.9h.9M110.6 129.4h.1M110.6 126v1.7M115.8 120.7h1.8M115.8 122.5h1.8M115.8 124.2h1.8"/>
<circle cx="175.9" cy="73.1" r=".55"/>
</g>
<g fill="none" stroke="#bd0000" stroke-width=".21">
<path d="M103.8 119.9l.2-.3v.9M104.2 116.2h.5v.3l-.5 .5h.5M104.7 119.7l.1-.1a.43 .43 0 0 1 .4 .5 .43 .43 0 0 1-.4 .4l-.2-.4zM109.9 112.8l.1-.2 .3 .1-.1 .4h-.2l-.3-.5-.2 .2 .1 .3h.2l.1-.2M116.7 117.9l-.3 .5h.6M116.8 118.2v.6M116.9 119.6h-.4l-.1 .5 .4-.1 .1 .4h-.5M103.8 120.5h.5M104.2 123.4l.3-.3v.8M104.2 123.9h.5M104.7 121.7l-.3 .2-.2-.2 .1-.3 .4 .1-.1 .7-.3 .1M109.5 127.2v-.6l.3 .3 .2-.3 .3 .1-.1 .5"/>
<path d="M116.4 123.1h.6l-.4 .8M116.8 121.4h-.2l-.2 .7 .2 .2 .3-.1v-.5h-.3l-.2 .1"/>
</g>
<g fill="none" stroke="#007170" stroke-width=".21">
<path d="M106 117.7l.3-1 .2 1M106.1 117.4h.3M106.8 116.7v1h.5M107.5 117.2h.4M107.9 116.7h-.4v1h.4M108.3 117.3l.5-.1v-.4l-.5-.1v1M108.5 117.3l.3 .4M109 116.7h.6M109.3 116.7v1M110.1 116.1l.9 .3-.9 .3M110.1 115.5a.48 .48 0 0 1 .6-.2 .48 .48 0 0 1 .3 .5h-.9zM110.1 114.6l.2-.1h.4l.3 .2v.3h-.9z"/>
<path d="M110.5 116.7l-.8 1.2M110.7 117.3l.5-.1v-.4l-.5-.1v1M111 117.3l.2 .4M111.7 116.7a.47 .47 0 0 1 .5 .5 .47 .47 0 0 1-.5 .5zM112.4 119.4l.4-.9 .2 .9M112.4 116.7l.3 .6 .2-.6M112.5 119.1h.4M112.7 117.3v.4M113.4 118.5v.9M114.3 118.5v.9l-.5-.9v.9M114.7 118.5a.42 .42 0 0 1 .4 .5 .42 .42 0 0 1-.4 .4zM106 124.6l.3-.8 .2 .8"/>
<path d="M106.1 124.4h.3M106.5 120.3h-.4v.3l.4 .2v.3h-.4M106.5 122.1h-.4l.1 .3 .3 .1-.1 .3h-.3M106.8 123.8h.4a.47 .47 0 0 1 .1 .5 .47 .47 0 0 1-.5 .3zM106.9 122a.47 .47 0 0 1 .5 .3 .47 .47 0 0 1-.1 .5h-.4zM107.4 120.3a.42 .42 0 0 0-.6 .4 .42 .42 0 0 0 .6 .4M107.7 122.8l.2-.8 .4 .8M107.7 123.8h.3l.2 .1v.5l-.3 .2h-.2zM107.8 120.2v1h.4M107.8 122.6h.4M108.5 124.2h.5v-.3l-.5-.1v.8M108.8 124.2l.2 .4"/>
<path d="M110.1 124.8v.3a.44 .44 0 0 0 .6 .1 .44 .44 0 0 0 .2-.5h-.3v.2M110.1 123.9h.9l-.9 .5h.9M110.1 123.1a.48 .48 0 0 1 .6-.1 .48 .48 0 0 1 .3 .4h-.9zM112.4 121.2l.4-1 .2 1M112.4 122.8l.4-.8 .2 .8M112.4 124.6l.4-.8 .2 .8M112.5 120.9h.4M112.5 122.6h.4M112.5 124.4h.4M113.4 120.2v1M113.4 122v.8M113.4 123.8v.8"/>
<path d="M114.3 120.2v1l-.5-1v1M114.3 122v.8l-.5-.8v.8M114.3 123.8v.8l-.5-.8v.8M114.5 123.8h.6l-.3 .3h.3v.4l-.1 .1-.5-.1M114.6 120.5l.3-.3v1M114.6 122.1l.4-.1 .1 .3-.6 .5h.6M114.6 121.2h.5"/>
</g>
<path d="M112.6 107.1h2.8M112.6 108.2h2.8" fill="none" stroke="#980000" stroke-width=".34"/>
<path d="M234.8 98.5h.4v.9h-.4l-.4-.4z" fill="#fff"/>
<g fill="none" stroke="#805e00" stroke-width=".21">
<path d="M234.8 98.5h.4v.9h-.4l-.4-.4zM235.6 98.9h.4l.1-.2-.1-.2h-.4v.8h.4l.1-.3-.1-.1M236.4 99.3l.3-.8 .3 .8M236.5 99.1h.4M237.1 98.5h.6M237.4 98.5v.8M237.8 98.5h.5M238.1 98.5v.8M238.6 98.9h.3M239 98.5h-.4v.8h.4M239.3 98.9h.5l.1-.4h-.6v.8M239.6 98.9l.3 .4"/>
<path d="M240.1 98.5l.3 .4 .3-.4M240.4 98.9v.4M240.8 99.4h.7M241.6 98.5v.8M242.6 98.5v.8l-.5-.8v.8"/>
</g>
<g fill="none" stroke="#980000" stroke-width=".21">
<path d="M220.4 116.4v1.9M220.4 119.7v1.9M222.2 115.5h.8M223 114.8h3.5v1.4h-3.5zM226.6 115.5h.8M229.2 101.6h1.5v3.4h-1.5zM229.2 118.1h1.5v3.4h-1.5zM229.2 109.3h1.5v3.5h-1.5zM230 100.7v.9M230 105.1v.8M230 108.5v.9M230 112.9v.9"/>
<path d="M230 117.3v.8M238.7 114.6l.9 1.8h-1.8zM238.8 112.9v5.2M239.6 114.6h-1.8v.3M230 121.6v.9"/>
</g>
<path d="M219 119.5h2.8M219 118.4h2.8" fill="none" stroke="#980000" stroke-width=".34"/>
<g fill="none" stroke="#00a200" stroke-width=".21">
<path d="M175.9 75.4v3.5M131.5 95.4h-12.2v23.6h-1.7M151.5 90.2h15.7v7h7.9M151.5 97.2h1.8M151.5 95.4h1.8M151.5 88.5h23.6M175.1 98h4.4v1M175.1 89.3v-6.9h-61.1v22.7M175.1 94.6v4.4M234.4 99h-4.4v1.7M80.9 104.1h33.1M110.6 104.1v7.9"/>
<path d="M114 110.2v1M151.5 102.4h1.8M151.5 104.1h1.8M175.1 104.1v1.8M179.5 104.1v1h-4.4M220.4 115.5v.9M222.2 115.5h-101.1v5.2h-3.5M227.4 115.5h2.6M230 107.7h12.2v5.2M230 105.9v2.6M230 113.8v3.5M238.8 107.7v5.2"/>
<path d="M238.8 118.1v7M242.2 118.1v6.1h-3.4M80.9 122.5h22.7M80.9 120.7h22.7M103.6 124.2h-.8v4.4h7.8M110.6 127.7v1.7M117.6 124.2h1.7v9.6h12.2M117.6 122.5h3.5v2.6h10.4M151.5 133.8h7M151.5 125.1h7M220.4 121.6v1.8h18.4M230 122.5v.9"/>
</g>
<g fill="none" stroke="#001dcd" stroke-width=".25">
<path d="M196.3 97.7l.6-.1v-.5l-.6-.1v1.4h.6l.2-.4-.3-.3M196.3 99.9h.5M196.9 99.2h-.6v1.4M197.4 99.7v.9M197.7 97.5l.3-.1 .3 .3v.7h-.6l-.1-.4 .2-.1 .5-.1M197.9 99.7h-.3l-.2 .3M198.4 99.7h.5v.9h-.5zM198.7 97.4h.5M198.9 97v1.2l.1 .2h.2M199.5 97.4h.6M199.6 99.8l.5-.1v.9M199.6 99.7v.9"/>
<path d="M199.7 97v1.2l.1 .2h.3M200.1 99.9l.1-.2h.5v.9M200.4 98l.7-.2-.2-.4-.4 .1-.1 .7 .1 .2h.5M201.7 97.4v1M202.1 97.4l-.3 .1-.1 .3M202.3 97.4l.4 1M203 97.4l-.4 1.3-.3 .2M203.7 99.7v.9M204 99.7h-.2l-.1 .3M204.5 99.8h.6l.1 .5-.1 .3-.6-.1zM204.6 98.4v-1.4l.5 1 .4-1v1.4M205.6 99.7h.5"/>
<path d="M205.8 99.2v1.4h.3M206.1 98l.7-.2-.2-.4-.4 .1-.1 .7 .1 .2h.5M207.3 97.5l.5-.1 .1 .3v.7h-.6v-.4l.6-.2M208.4 99.7h-.6l-.1 .3 .1 .6h.6M208.7 99.7h.5M209 99.2v1.4h.2M209 97.5l-.3-.1-.2 .3 .2 .3 .4 .1-.1 .3h-.5M209.7 97.4l.1 1 .5-.1M210.3 97.4v1M211 97.4v1M211.3 97.4l-.2 .1-.1 .3M211.5 99.2v1.4h-.5l-.2-.3 .1-.5 .6-.1"/>
<path d="M211.7 98l.7-.2-.1-.3-.4-.1-.2 .3 .1 .7h.5M213.1 99.6l.4-.4v1.4M214.4 99.4l.6-.2 .2 .3-.1 .3-.7 .8h.8M215.6 99.2l.5 1.4 .4-1.4M202.4 100.6l.6-.1 .1-.5-.2-.3h-.5v1.4M206.5 100.2l.7-.2-.1-.3h-.5l-.1 .2 .1 .7h.5M209.6 100.2l.7-.2-.1-.3h-.5l-.1 .2 .1 .7h.5M213.1 100.6h.8"/>
</g>
<g fill="none" stroke="#001dcd" stroke-width=".21">
<path d="M85.3 70.2h105.4v92.4h-105.4zM177.7 94.6h11.4v2.6h-11.4zM178.5 95.2l.3 1 .3-1M179.4 95.6v.6M179.7 95.6l-.3 .2M179.9 95.8h.4l-.1-.2h-.3v.5h.3M180.5 95.6h.3M180.8 95.2l-.1 .1v.9M181.9 95.7h.6M181.9 95.9h.6M183.6 95.5l.2-.3v1M183.6 96.2h.5"/>
<path d="M184.8 95.2h-.4v.5h.4l-.1 .5-.3-.1M185.2 95.3l.3-.1 .2 .2v.6l-.2 .2a.53 .53 0 0 1-.3-.9zM186.1 95.7l.3-.1v.6M186.1 95.6v.6M186.4 95.7h.5v.5M187.1 95.2l.3 1 .3-1M195.2 96.3h54.9v34h-54.9zM211.7 105.1h16.6v2.6h-16.6zM214.2 106l.3-.3v.9M214.2 106.6h.5M215.2 106.1l-.2-.2 .1-.2h.4v.4l-.5 .2 .1 .3h.4l.1-.2-.2-.3M215.9 106.5v.1"/>
<path d="M216.2 105.7h.6l-.3 .4h.2l.1 .2-.1 .3-.5-.1M217.7 106h.3M217.8 105.7v.9h.2M218.3 106l.1 .6M218.7 106l-.4 .9M219 106.1h.4v.5h-.4M219 106v.9M220.5 106.2h.6M220.5 106.4h.6M222.1 105.7h.6l-.4 .4h.3v.5l-.5-.1M223 106.5v.1M223.3 105.7h.6l-.3 .4 .3 .1v.3h-.6"/>
<path d="M224.1 105.7l.3 .9 .3-.9M225.6 106.2l.2-.2 .3 .1v.4l-.4 .1zM226.5 106v.6l.3-.1M226.8 106v.6M227.2 106h.3M227.2 105.7v.8l.3 .1M95.8 129.4h13.1v5.3h-13.1zM96.6 131l.3-.9 .3 .9M96.7 130.8h.4M96.7 132h.7M96.7 132.2h.7M97.4 130.1a.49 .49 0 0 1 .5 .3 .49 .49 0 0 1-.1 .6h-.4z"/>
<path d="M98.3 130.1h.2l.3 .3v.4l-.2 .2h-.3zM98.5 131.7l.3-.1v.7a.39 .39 0 0 1-.4-.2 .39 .39 0 0 1 .1-.4zM99.2 130.6h.4v-.4l-.4-.1v.9M99.2 131.8l.4 .6M99.4 130.6l.2 .4M99.6 131.8l-.4 .6M100.1 130.8h.6M100.1 130.6h.6M100.2 131.5l-.3 .7h.6M100.3 131.8v.6M100.9 131.9l-.2-.2 .1-.1 .5 .1-.1 .2-.5 .2 .1 .3 .5-.1v-.3l-.2-.1M101.8 130.4l.2-.3v.9"/>
<path d="M101.8 131h.5M102.8 130.1a.43 .43 0 0 1 .3 .5 .43 .43 0 0 1-.4 .4l-.1-.7zM103.6 130.1l.3 .2-.1 .7h-.3v-.2v-.5zM104.2 130.4l.3-.3v.9M104.2 131h.5M105.2 130.2l.2-.1 .2 .2-.1 .7h-.3l-.1-.3zM106.1 130.1a.43 .43 0 0 1 .3 .5 .43 .43 0 0 1-.4 .4l-.1-.7zM106.9 130.1a.43 .43 0 0 1 .4 .5 .43 .43 0 0 1-.5 .4v-.7zM107.6 130.1v.9h.3v-.5h-.3"/>
</g>
<g fill="none" stroke="#001dcd" stroke-width=".34">
<path d="M86.3 72.6l.6-1.8 .5 1.8M86.5 72.1h.7M88 71.6l.3-.2 .4 .1 .1 1.1M88 71.4v1.2M89.6 71.5h.6l.1 1.1M90.3 71.8l-.6 .1-.2 .3 .2 .4 .6-.1M91.1 70.8v1.5l.3 .3M92 71.6l.2-.2 .5 .2 .1 .7-.1 .2-.5 .1-.2-.2zM94.3 71.4v1.5l-.3 .2-.4-.1M94.3 71.5l-.5-.1-.3 .3v.6l.2 .2h.6M95.1 71.4l.1 1.1 .4 .1 .3-.2M95.9 71.4v1.2"/>
<path d="M96.6 72l.8-.2-.1-.3h-.7v1h.7M99.4 70.8v.2M99.4 71.4v1.2M100.3 71.6l.2-.2 .5 .1v1.1M100.3 71.4v1.2M101.8 71.5l.5-.1 .4 .3v.6l-.2 .2h-.7M101.8 71.4v1.7M103.4 71.4v.9a.37 .37 0 0 0 .3 .3 .37 .37 0 0 0 .4-.2M104.1 71.4v1.2M104.7 71.4h.7M104.9 70.8v1.5l.5 .3M108 71.5l-.5-.1-.4 .3v.6l.2 .2h.7"/>
<path d="M108.7 70.8v.2M108.7 71.4v1.2M109.5 71.4v1.2M110 71.4l-.3 .1-.2 .2M111.3 71.5l-.5-.1-.3 .3 .1 .7 .2 .2 .5-.1M112.1 71.4v1.1l.5 .1 .2-.2M112.8 71.4v1.2M113.6 70.8v.2M113.6 71.4v1.2M114.2 71.4h.6M114.4 70.8v1.5l.4 .3M115.9 71.5h-.5v.4l.5 .2 .1 .2-.2 .3-.4-.1"/>
</g>
<g fill="none" stroke="#007170" stroke-width=".21">
<path d="M131.8 85.8h.4l.1-.4-.1-.1h-.4v.9M132 85.8l.3 .4M132.9 85.6h-.2l-.1 .2 .4 .2-.2 .2-.2-.1M133.3 85.8h.5l-.1-.2h-.4v.5h.4M134.1 85.7l.3-.1v.6M134.1 85.6v.6M135.2 85.6h-.3v.2h.2l.1 .3h-.3M135.6 85.3h.1M135.6 85.6v.6M136.1 85.7l.3-.1v.6M136.1 85.6v.6M137.2 86.1l-.3 .1-.2-.2 .1-.4h.4v.8h-.4"/>
<path d="M137.4 86.3h.7M138.3 85.8l.5-.1v-.4h-.5v.9M139.1 85.6l.4 .1v.5M139.5 85.8h-.4l.1 .4 .3-.1M139.9 85.3h.1M139.9 85.6v.6M140.4 85.6v.6M140.6 85.6l-.2 .2M140.9 85.5l.1-.2v.9M140.9 86.2h.4M131.7 121.9l.3-.9 .2 .9M131.7 130.6l.3-.9 .2 .9"/>
<path d="M131.7 121.7h.5M131.7 130.4h.5M132.5 121.4h.4v.5M132.5 130.1h.4v.5M132.5 121.3v.6M132.5 130v.6M133.3 121.3h.4v.6M133.3 130h.4v.6M133.7 121.5l-.4 .2 .1 .2 .3-.1M133.7 130.2l-.4 .2 .1 .2h.3M134.1 121v.7l.2 .2M134.1 129.7v.8l.2 .1"/>
<path d="M134.5 121.4h.5v.4h-.5zM134.5 130.1h.5v.5h-.5zM135.7 121.8l-.2 .1-.2-.2 .1-.4h.3v.8l-.3 .1M135.7 130.6h-.2l-.2-.1 .1-.5h.3v.8l-.3 .1M136.1 121l.2 .9 .3-.9M136.1 129.7l.2 .9 .3-.9M136.6 122h.7M136.6 130.7h.7M137.6 121a.47 .47 0 0 1 .5 .4 .47 .47 0 0 1-.5 .5zM137.6 129.7a.47 .47 0 0 1 .5 .5 .47 .47 0 0 1-.5 .4zM138.4 121v.1M138.4 129.7v.1"/>
<path d="M138.4 121.3v.6M138.4 130v.6M138.8 121.3l.1 .6 .3-.6M138.8 130l.1 .6 .3-.6M139.5 121v.1M139.5 129.7v.1M139.5 121.3v.6M139.5 130v.6M140.3 121.3h-.4v.2l.1 .4 .3-.1M140.3 130h-.4v.2l.1 .4h.3M140.3 121v.9M140.3 129.7v.9"/>
<path d="M140.7 121.6l.3-.1v-.2h-.3v.5h.3M140.7 130.3l.3-.1v-.2h-.3v.6h.3M141.5 121.3v.6M141.5 130v.6M141.7 121.3l-.2 .2M141.7 130l-.2 .2M141.9 121h.6l-.4 .3 .4 .2v.2l-.2 .2-.4-.1M142.1 129.7l-.1 .6h.5M142.4 130v.6"/>
</g>
<path d="M131.9 95h.5v.9h-.5l-.4-.5z" fill="#fff"/>
<path d="M131.5 95.4l.4-.4h.5v.9h-.5z" fill="none" stroke="#805e00" stroke-width=".21"/>
<path d="M132.7 95.8l.2-.8 .4 .8M132.8 95.6h.4M133.5 95h.4l.1 .2v.5l-.1 .1h-.4zM134.9 95.1l-.4-.1-.1 .2v.5l.1 .1h.4M135 95.9h.7M135.8 95.8l.3-.8 .3 .8M135.9 95.6h.4" fill="none" stroke="#007170" stroke-width=".21"/>
<path d="M131.9 102h.5v.9h-.5l-.4-.5z" fill="#fff"/>
<path d="M131.5 102.4l.4-.4h.5v.9h-.5z" fill="none" stroke="#805e00" stroke-width=".21"/>
<path d="M132.7 102.9l.2-1 .4 1M132.8 102.6h.4M133.5 101.9h.3l.2 .3v.4l-.2 .3h-.3zM134.9 102l-.3-.1-.2 .3v.4l.2 .3 .3-.1M135 102.9h.7M136 102.4h.3l.1-.4-.4-.1v1h.3l.2-.4-.3-.1" fill="none" stroke="#007170" stroke-width=".21"/>
<path d="M151.1 96.8h.4v.8h-.4l-.4-.4z" fill="#fff"/>
<path d="M150.7 97.2l.4-.4h.4v.8h-.4z" fill="none" stroke="#805e00" stroke-width=".21"/>
<g fill="none" stroke="#007170" stroke-width=".21">
<path d="M141.6 96.7v.9M141.6 97.1h.5M142.1 96.7v.9M142.5 96.7v.1M142.5 97v.6M143.3 97.5l-.3 .1-.2-.2 .1-.4h.4v.8l-.4 .1M143.7 97.1l.3-.1v.6M143.7 96.7v.9M144.4 97.2l.5-.1v-.3l-.5-.1v.9M144.7 97.2l.2 .4M145.3 97.3l.4-.1v-.2l-.4 .1v.3l.2 .2 .2-.1M146.4 97h-.4v.3l.4 .1-.1 .2-.3-.1"/>
<path d="M146.8 96.7v.1M146.8 97v.6M147.7 96.8l-.4-.1-.2 .2 .1 .2 .5 .2v.2h-.6M148 97.3l.4-.1-.1-.2-.3 .1 .1 .5 .2-.1M148.7 97h.3M148.8 96.7v.7l.2 .2M149.1 97.7h.7M149.9 97.6l.2-.9 .3 .9M149.9 97.4h.4"/>
</g>
<path d="M150.7 104.1l.4-.4h.4v.9h-.4z" fill="#fff"/>
<path d="M151.1 103.7h.4v.9h-.4l-.4-.5z" fill="none" stroke="#805e00" stroke-width=".21"/>
<g fill="none" stroke="#007170" stroke-width=".21">
<path d="M141.5 103.7v.9M141.5 104.1h.4M141.9 103.7v.9M142.3 103.7v.1M142.3 104v.6M143.2 104v.7l-.2 .2-.3-.1M143.2 104h-.5v.5l.5 .1M143.6 104h.2l.1 .1v.5M143.6 103.7v.9M144.4 104.1h.4v-.4h-.4v.9M144.5 104.1l.4 .5M145.2 104.3l.4-.1-.1-.2h-.3v.6h.3"/>
<path d="M146.2 104h-.2l-.1 .1 .4 .4-.4 .1M146.6 103.7v.1M146.6 104v.6M147.6 103.7l-.5 .1v.2l.5 .3-.1 .3h-.4M147.9 104.3l.3-.1v-.2h-.3v.6h.3M148.5 104h.3M148.7 103.7v.9h.1M148.9 104.6h.7M149.9 104.1l.4-.1-.1-.3h-.3v.9l.4-.1v-.3l-.2-.1"/>
</g>
<path d="M151.1 89.8h.4v.9h-.4l-.4-.5z" fill="#fff"/>
<path d="M151.1 89.8h.4v.9h-.4l-.4-.5z" fill="none" stroke="#805e00" stroke-width=".21"/>
<path d="M148.1 89.7l.2 .9 .3-.9M148.9 90.1v.5M149.2 90.1l-.3 .1M149.4 90.3l.5-.1-.1-.1h-.4v.5h.4M150.1 90.1h.3M150.4 89.7l-.2 .1v.8" fill="none" stroke="#007170" stroke-width=".21"/>
<path d="M151.1 88h.4v.9h-.4l-.4-.4z" fill="#fff"/>
<path d="M151.1 88h.4v.9h-.4l-.4-.4z" fill="none" stroke="#805e00" stroke-width=".21"/>
<g fill="none" stroke="#007170" stroke-width=".21">
<path d="M142.4 88l-.5 .1 .1 .3 .4 .2v.2h-.5M142.7 88.6l.5-.1v-.2l-.5 .1v.3l.2 .2 .3-.1M143.6 88.4h.3v.5M143.6 88.3v.6M144.6 88.3h-.2l-.1 .2 .4 .2-.2 .2-.2-.1M145 88.4l.4-.1 .1 .5h-.5zM145.9 88.3v.6M146 88.3h-.1v.2M146.8 88l-.5 .1 .1 .3 .4 .2v.2h-.5M147.2 88.3v.5h.4M147.6 88.3v.6M148 88.8l.2 .1 .2-.2-.1-.4h-.3v.8"/>
<path d="M148.8 88.8h.4l-.1-.5h-.3v.8M149.6 88l.1 .9M149.9 88.3l.3 .6M150.4 88.3l-.2 .6-.3 .2"/>
</g>
<path d="M150.7 95h.8v.9h-.8z" fill="#fff"/>
<path d="M150.7 95h.8v.9h-.8z" fill="none" stroke="#805e00" stroke-width=".21"/>
<path d="M145.3 95h-.4l-.1 .2 .1 .2 .4 .1v.3h-.5M145.6 95.6l.4-.1-.1-.3-.3 .2v.4h.4M146.4 95.3l.2-.1 .2 .2v.4M146.4 95.2v.6M147.6 95v.8h-.4l-.1-.4 .2-.2 .3 .1M148 95.6l.3-.1-.1-.3-.2 .1v.5h.3M148.8 95.2v.6M149 95.2l-.2 .2M149.1 95.9h.7M149.9 95.8l.2-.8 .3 .8M149.9 95.6h.4" fill="none" stroke="#007170" stroke-width=".21"/>
<path d="M150.7 102h.8v.9h-.8z" fill="#fff"/>
<path d="M150.7 102h.8v.9h-.8z" fill="none" stroke="#805e00" stroke-width=".21"/>
<path d="M145.2 102h-.5v.3l.5 .3-.2 .3-.3-.1M145.5 102.5l.4-.1v-.1h-.4v.5h.4M146.3 102.4l.3-.1v.6M146.3 102.3v.6M147.5 102.3l-.4 .1v.4h.4M147.5 101.9v1M147.8 102.5l.4-.1v-.1l-.4 .1v.3l.2 .2 .2-.1M148.6 102.3v.6M148.8 102.3l-.2 .1M148.9 102.9h.7M149.9 102.4h.3l.1-.3-.2-.2h-.2v1h.3l.1-.5h-.2" fill="none" stroke="#007170" stroke-width=".21"/>
<path d="M131.9 124.6h.5v1h-.5l-.4-.5z" fill="#fff"/>
<path d="M131.9 124.6h.5v1h-.5l-.4-.5z" fill="none" stroke="#805e00" stroke-width=".21"/>
<g fill="none" stroke="#007170" stroke-width=".21">
<path d="M132.7 125.5l.2-.9 .4 .9M132.8 125.2h.4M133.5 125l.3-.1 .1 .1v.5M133.5 124.9v.6M134.4 125l.1-.1 .2 .1v.5h-.3v-.4h.3M135.1 124.6l.1 .9M135.5 125h.5l-.1 .5-.4-.1zM136.7 124.9v.7l-.1 .2-.2-.1M136.7 125l-.2-.1-.2 .1 .1 .5h.3M136.9 125.6h.7M137.8 124.7h.5v.8l-.5-.1zM138.7 124.6l.1 .9 .4-.1v-.8"/>
<path d="M139.5 124.6h.5M139.8 124.6v.9"/>
</g>
<path d="M151.1 124.6h.4v1h-.4l-.4-.5z" fill="#fff"/>
<path d="M151.1 124.6h.4v1h-.4l-.4-.5z" fill="none" stroke="#805e00" stroke-width=".21"/>
<path d="M144.2 125.5l.3-.9 .3 .9M144.3 125.2h.4M145.1 125h.4v.5M145.1 124.9v.6M145.9 125h.3v.5h-.3l.1-.4h.2M146.6 124.6v.8l.2 .1M147.1 125l.3-.1 .2 .1-.1 .5h-.4zM148.2 124.9v.8h-.3M148.2 125h-.3v.4l.3 .1M148.5 125.6h.7M149.3 124.6v.9M150.3 124.6v.9l-.5-.9v.9" fill="none" stroke="#007170" stroke-width=".21"/>
<path d="M131.9 133.3h.5v1h-.5l-.4-.5z" fill="#fff"/>
<path d="M131.9 133.3h.5v1h-.5l-.4-.5z" fill="none" stroke="#805e00" stroke-width=".21"/>
<g fill="none" stroke="#007170" stroke-width=".21">
<path d="M132.7 134.2l.2-.9 .4 .9M132.8 133.9h.4M133.5 133.7l.3-.1 .1 .2v.4M133.5 133.6v.6M134.4 133.7l.1-.1 .2 .2v.4h-.3v-.3h.3M135.1 133.3l.1 .9M135.5 133.7h.5l-.1 .5-.4-.1zM136.7 133.6v.8l-.1 .1-.2-.1M136.7 133.7l-.2-.1-.2 .2 .1 .4h.3M136.9 134.3h.7M137.8 133.4h.5v.8l-.5-.1zM138.7 133.3l.1 .9 .4-.1v-.8"/>
<path d="M139.5 133.3h.5M139.8 133.3v.9"/>
</g>
<path d="M150.7 133.8l.4-.5h.4v1h-.4z" fill="#fff"/>
<path d="M151.1 133.3h.4v1h-.4l-.4-.5z" fill="none" stroke="#805e00" stroke-width=".21"/>
<path d="M144.2 134.2l.3-.9 .3 .9M144.3 133.9h.4M145.1 133.7h.4v.5M145.1 133.6v.6M145.9 133.7h.3v.5h-.3l.1-.3h.2M146.6 133.3v.8l.2 .1M147.1 133.8l.3-.2 .2 .2-.1 .4h-.4zM148.2 133.6v.8h-.3M148.2 133.7h-.3v.4l.3 .1M148.5 134.3h.7M149.3 133.3v.9M150.3 133.3v.9l-.5-.9v.9" fill="none" stroke="#007170" stroke-width=".21"/>
<path d="M103.2 116.8l.8 .9M104 116.8l-.8 .9M131.1 102l.8 .9M131.9 102l-.8 .9M152.9 102l.8 .9M152.9 103.7l.8 .9M153.7 102l-.8 .9M153.7 103.7l-.8 .9" fill="none" stroke="#001192" stroke-width=".21"/>
<g fill="#00a200">
<circle cx="230" cy="107.7" r=".38"/>
<circle cx="175.1" cy="105.1" r=".38"/>
<circle cx="220.4" cy="115.5" r=".38"/>
<circle cx="175.1" cy="98" r=".38"/>
<circle cx="175.1" cy="88.5" r=".38"/>
<circle cx="175.1" cy="97.2" r=".38"/>
<circle cx="114" cy="104.1" r=".38"/>
<circle cx="110.6" cy="104.1" r=".38"/>
<circle cx="110.6" cy="128.6" r=".38"/>
<circle cx="238.8" cy="107.7" r=".38"/>
<circle cx="238.8" cy="123.4" r=".38"/>
<circle cx="230" cy="115.5" r=".38"/>
<circle cx="238.8" cy="124.2" r=".38"/>
<circle cx="230" cy="123.4" r=".38"/>
</g>
<path d="M116.5 109h-.4v.4l.4-.1 .1 .3-.2 .2-.3-.1M117 109h.3v.7l-.1 .1-.3-.2zM117.6 109l.3 .8 .3-.8M182.8 102.9h-.4l-.1 .3h.5v.4h-.5M183.2 102.9h.1a.46 .46 0 0 1 .4 .3 .46 .46 0 0 1-.2 .5l-.3-.1-.1-.2zM183.9 102.9l.2 .8 .4-.8M245.5 116.7h-.4v.5h.4l-.1 .5-.3-.1M246 116.8l.2-.1 .2 .2v.6l-.2 .2a.53 .53 0 0 1-.2-.9zM246.6 116.7l.4 1 .2-1M216 120.2h-.4l-.1 .4h.5v.5h-.5M216.5 120.2a.48 .48 0 0 1 .3 .5 .48 .48 0 0 1-.3 .5l-.2-.2v-.6zM217.1 120.2l.2 1 .4-1" fill="none" stroke="#970091" stroke-width=".21"/>
<g fill="none" stroke="#007170" stroke-width=".21">
<path d="M177.9 74.4l.2-.8 .4 .8M177.9 71.8h.5M178 74.2h.4M178.1 71.8v.8M178.6 72.2h.5v-.3l-.5-.1v.8M178.7 73.6h.4l.1 .1v.5l-.2 .2h-.3zM179.7 72.1l-.2-.2 .4-.1v.3l-.4 .1 .1 .4h.3l.1-.1-.2-.4M180.1 73.6l-.5 .1v.2l.4 .1 .1 .2-.2 .2-.3-.1M180.2 74.5h.7M181 73.6l.3 .8 .2-.8M181.9 74h.3l.2-.2-.1-.2h-.4v.8M182 74l.4 .4"/>
<path d="M182.7 73.9h.3M183.1 73.6h-.4v.8h.4M183.6 73.9h.2M183.9 73.6h-.3v.8M177 92.4h.5l-.2 .3 .2 .1v.3h-.5M177.1 91.1h.4l.1-.2-.1-.3h-.4v.9M177.3 91.1l.3 .4M178.4 92.7l-.1 .2h-.3v-.5l.4 .1v.5l-.4 .2M178.4 90.6l-.4 .1v.7l.3 .1 .2-.2-.2-.4-.3 .2M178.8 90.7l.3-.1 .2 .2-.6 .7h.6M178.8 92.4v.8M178.9 92.9l.2 .3"/>
<path d="M179.1 92.6l-.3 .4M182.9 99.4a.42 .42 0 0 0-.6 .4 .42 .42 0 0 0 .6 .4M183.1 99.3h.5l-.2 .3 .2 .1v.5h-.5M184.2 99.3l-.2 .6h.6M184.4 99.6v.6M100.3 112.4l.4-.9 .2 .9M100.4 112.2h.4M101.3 111.5a.47 .47 0 0 1 .5 .5 .47 .47 0 0 1-.5 .4zM102.5 111.6h-.4v.2l.4 .3v.2h-.4M102.9 111.8l.2-.3v.9M102.9 112.4h.5M103.7 111.8l.3-.3v.9"/>
<path d="M103.7 112.4h.5M104.6 111.8l.2-.3v.9M104.6 112.4h.5M105.8 111.5h-.4v.4l.3-.1 .2 .5-.2 .1-.3-.1M106.3 111.5v.9M106.7 111.5a.47 .47 0 0 1 .5 .5 .47 .47 0 0 1-.5 .4zM106.7 109.8l.1 .9h.3l.1-.2v-.7M107.5 110.1l.3-.3v.9M107.5 110.7h.5M108 111.6l-.2-.1-.3 .3v.4l.3 .2 .2-.1v-.3h-.1M108.9 111.6l-.4-.1-.1 .2 .5 .6-.2 .1-.3-.1M108.9 110.1l-.1 .2h-.3v-.5h.3l.1 .2-.2 .7h-.2"/>
<path d="M115.1 112.4h-.3l-.2 .4 .2 .5 .4-.1v-.3h-.1M116.1 112.4v.9l-.5-.9v.9M116.1 107.4l.2-.2v.8M116.1 108h.5M116.5 112.4l.4 .1 .1 .4-.2 .4h-.3zM116.6 105.5l-.3-.1-.2 .3v.4l.2 .2h.3M116.9 105.4h.5l-.2 .3 .2 .2v.3l-.1 .1h-.4M117.1 107.2l.2 .1v.7h-.3l-.1-.1v-.5zM117.7 105.4h.6l-.4 .3 .4 .2v.3l-.2 .1h-.4M117.8 107.3l.2-.1 .2 .2-.1 .5a.39 .39 0 0 1-.4-.2 .39 .39 0 0 1 .1-.4zM118.6 107.5h.4v.5M118.6 107.4v.6"/>
<path d="M170.4 100.6l-.1-.3 .4-.1v.4l-.4 .1v.3l.1 .1 .4-.2-.2-.3M170.9 102.4h.5v-.4l-.5-.1v1M171.1 100.3l.3-.1 .1 .4-.5 .5h.5M171.2 102.4l.2 .5M172 100.3l.3-.1 .1 .2v.5l-.2 .2a.48 .48 0 0 1-.2-.8zM172.2 101.9l-.3 .1-.1 .8 .3 .1 .2-.2-.2-.4-.3 .1M172.5 101.9h.6l-.3 .4 .3 .1v.3l-.1 .2-.5-.1M172.8 100.2v.9M172.9 100.7l.2 .4M173.1 100.5l-.3 .3M174.4 109h-.3a.44 .44 0 0 0-.1 .5 .44 .44 0 0 0 .5 .2v-.3h-.2M175.3 109v.8l-.5-.8v.8"/>
<path d="M175.8 109h.3a.48 .48 0 0 1 .1 .5 .48 .48 0 0 1-.4 .3zM182.3 101.3l.2-.2v.8M182.3 101.9h.5M183.3 101.1h.3v.8a.47 .47 0 0 1-.5-.3 .47 .47 0 0 1 .2-.5zM184.1 101.1a.42 .42 0 0 1 .4 .4 .42 .42 0 0 1-.4 .4zM184.8 101.4l.3-.1 .1 .2v.4M184.8 101.3v.6M215.5 118.8l.2-.3v.9M215.5 119.4h.5M215.9 116.8l-.3-.1-.2 .3v.4l.2 .3 .3-.1M216.2 116.7h.5l-.3 .4 .3 .2v.2l-.1 .2-.4-.1M216.3 118.6l.4-.1v.2v.7l-.4-.1z"/>
<path d="M217.2 118.9h.3v.5M217.2 118.8v.6M217.5 116.7h-.4v.5l.3-.1 .2 .4-.2 .2-.3-.1M223.7 111.2l.5-.1v-.4h-.5v.8M223.9 111.2l.3 .3M224.2 112.7l.2-.3v.9M224.2 113.3h.5M225 110.7h-.3l-.2 .7 .5 .1v-.4l-.3-.1-.2 .2M225 112.4v.9M225.1 112.9l.3 .4M225.4 112.7l-.4 .3M225.5 110.7l-.1 .5h.5"/>
<path d="M225.8 111v.5M232 104l.2-.3v.9M232 111.8l.2-.3v.9M232 112.4h.5M232 104.6h.5M232.1 102.4h.3l.2-.3-.2-.2h-.3v1M232.1 119h.4v-.5h-.4v.9M232.1 110.2h.4v-.4h-.4v.9M232.2 102.4l.4 .5M232.2 119l.4 .4M232.2 110.2l.4 .5M232.8 112.4v-.9l.4 .7 .2-.7v.9"/>
<path d="M232.9 103.7a.42 .42 0 0 1 .4 .4 .42 .42 0 0 1-.4 .5zM233.3 101.9l-.3 .1-.2 .7 .2 .2 .3-.1v-.4l-.3-.1-.2 .1M233.3 118.5h-.3l-.2 .7 .1 .2 .4-.1v-.4h-.4l-.1 .1M233.3 109.8h-.3l-.2 .7 .1 .2 .4-.1v-.5h-.4l-.1 .2M233.7 118.5h.6l-.5 .9M233.8 103.7a.42 .42 0 0 1 .4 .4 .42 .42 0 0 1-.4 .5zM234.1 109.8h-.3l-.1 .7 .1 .2 .4-.1-.1-.5h-.3l-.1 .2M234.2 101.9h-.4l-.1 .5h.5v.4h-.5M234.5 104.1h.4v-.4h-.4v.9M234.7 116.6l.2-.3v.9M234.7 117.2h.5M234.8 104.1l.2 .5"/>
<path d="M235.5 114.6l.4 .2v.4l-.3 .3h-.1zM235.6 116.7l-.1-.3h.5v.3h-.5v.5l.5-.1v-.3l-.2-.1M236.2 116.3l.4 .9 .2-.9M236.7 114.6h-.4l-.1 .4h.5v.4h-.5M245.1 115.3l.3-.2v.8M245.1 115.9h.4M245.6 113.4l-.2-.1-.3 .2v.5l.2 .1 .3-.1M245.9 113.3h.6l-.4 .3h.3v.5l-.5-.1M246 115.1h.3l.1 .1v.5l-.2 .2a.48 .48 0 0 1-.2-.8zM246.8 115.1h.3l.1 .1v.5l-.1 .2a.48 .48 0 0 1-.3-.8zM247.2 113.3l-.4 .2v.5l.4 .1v-.5h-.3l-.1 .2M247.6 115.4l.2-.1 .2 .2v.4"/>
<path d="M247.6 115.3v.6M109.9 132.5h-.3a.44 .44 0 0 0-.2 .6 .44 .44 0 0 0 .6 .2v-.4h-.2M110.8 132.5v.8l-.5-.8v.8M111.2 132.5h.4a.48 .48 0 0 1 .1 .5 .48 .48 0 0 1-.5 .3zM232 120.3h.5v.3l-.5 .6h.5M232.8 120.3l.4-.1 .1 .3-.6 .7h.6M233.8 120.2a.48 .48 0 0 1 .4 .5 .48 .48 0 0 1-.4 .5l-.1-.2v-.6zM234.5 120.2v1M234.6 120.8l.3 .4M234.9 120.6l-.4 .3M238.1 128.2l-.3-.1-.2 .2v.5l.1 .1h.4v-.3h-.2M239 128.1v.8l-.5-.8v.8"/>
<path d="M239.4 128.1l.5 .2v.5l-.2 .1h-.3z"/>
</g>
</svg>
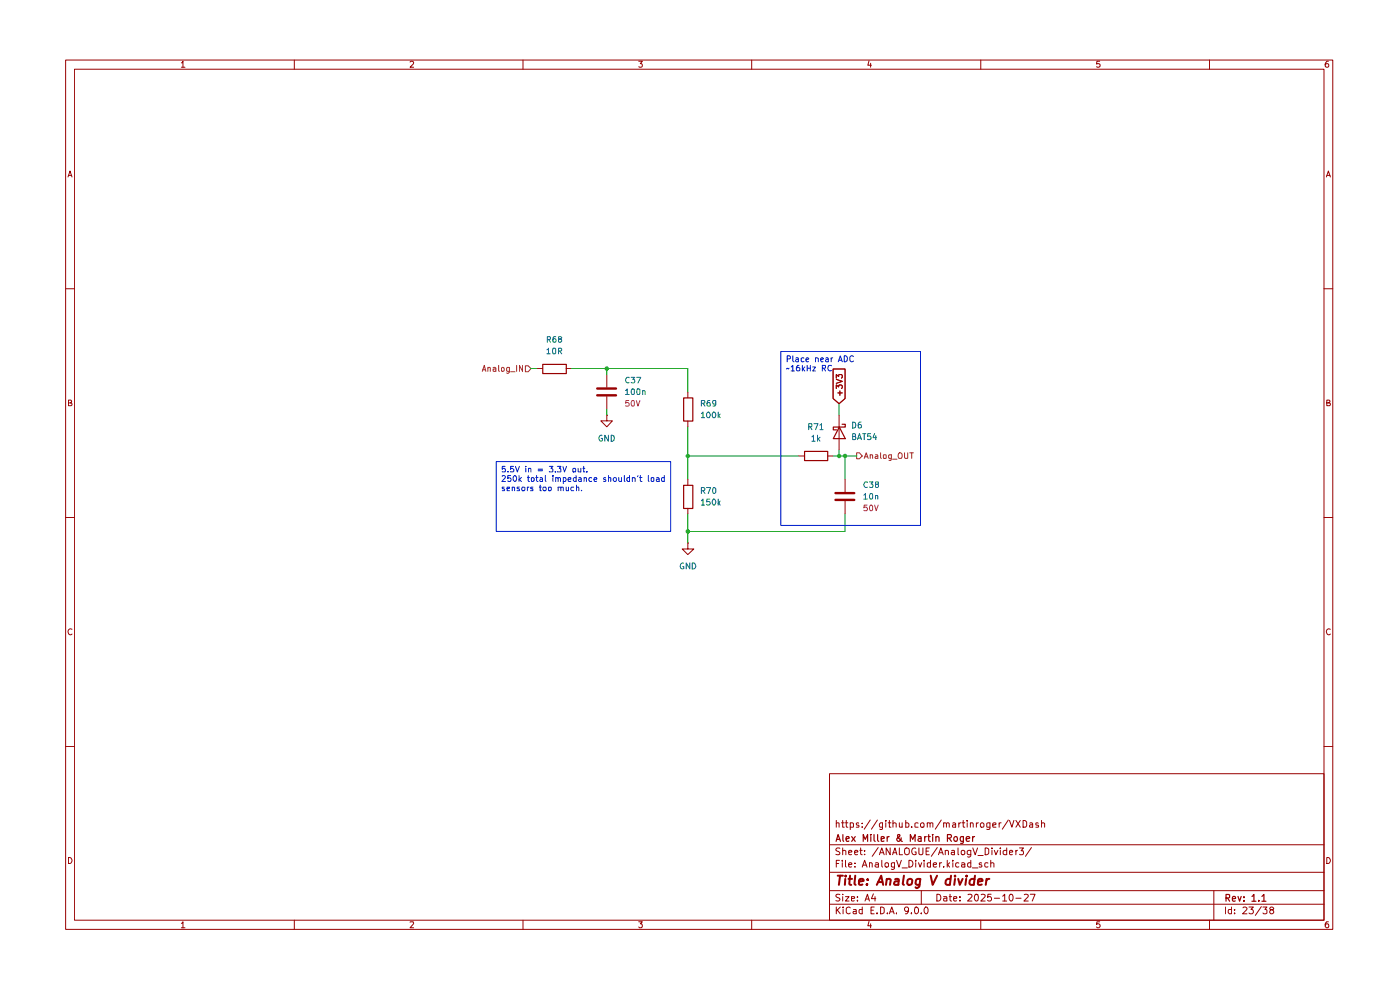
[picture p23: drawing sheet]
<svg xmlns="http://www.w3.org/2000/svg" width="297mm" height="210mm" viewBox="0 0 297 210" stroke-linecap="round" stroke-linejoin="round" font-family="sans-serif">
<g fill="none" stroke="#980000" stroke-width=".21">
<path d="M13.9 12.7h268.8v184.4h-268.8zM15.8 14.7h265.1v180.5h-265.1zM38.5 13.3h.1l.2-.3v1.3M38.5 14.3h.7M62.4 12.7v2M87 13.2l.5-.2 .3 .2-.1 .4-.7 .7h.8M111 12.7v2M135.5 13h.8l-.5 .5 .4 .1v.6h-.7M159.5 12.7v2M184.4 12.9l-.3 .9h.8M184.7 13.4v.9M208.1 12.7v2"/>
<path d="M233.3 13h-.6l-.1 .6h.7v.6h-.7M256.6 12.7v2M281.8 13a.71 .71 0 0 0-.7 .5 .71 .71 0 0 0 .3 .8l.4-.1v-.6l-.4-.1-.3 .3M14.4 37.5l.5-1.2 .4 1.2M14.5 37.2h.7M281.4 37.5l.4-1.2 .4 1.2M281.5 37.2h.6M13.9 61.3h1.9M176.7 78.3h2.6v6.2l-1.3 1.1-1.3-1.1zM280.9 61.3h1.8M14.5 85.5h.4l.3-.3-.2-.3h-.5v1.2h.6l.2-.5-.4-.1M145.9 83.2v1.2"/>
<path d="M145.9 89.3v1.2M169.4 96.7h1.2M175.6 96.7h1.1M177.4 82.4v-.7l.5 .4v-.4h.7l.1 .5-.2 .2M177.4 80.5l1.3 .4-1.3 .4M177.4 80.2v-.7l.5 .4 .1-.4h.5l.2 .1v.4l-.2 .2M177.8 83.3h.9M178 88.1v7.4M178.2 82.9v1M281.5 85.5h.4l.2-.3-.1-.3h-.5v1.2h.6l.1-.5-.3-.1M13.9 109.8h1.9M145.9 115.2v1.3h1.3l-1.3 1.1-1.2-1.1h1.2"/>
<path d="M145.9 115.2h.1M145.9 101.6v1.3M145.9 107.8v1.2M280.9 109.8h1.8M15.3 133.5a.59 .59 0 0 0-.9 .5 .59 .59 0 0 0 .8 .6l.1-.1M282.2 133.5a.59 .59 0 0 0-.8 .5 .59 .59 0 0 0 .7 .6l.1-.1M13.9 158.4h1.9M280.9 158.4h1.8M176 164.1h104.9v31.1h-104.9zM176 179.2h104.9M177.4 174.7l.2-.2 .4 .1v.9M177.4 174v1.5"/>
<path d="M178.2 180l-.6-.1-.3 .2 .1 .4 .8 .4-.1 .3h-.8M178.5 174.5h.6M178.8 174v1.5h.3M178.8 179.9v1.4M179.4 174.5h.5M179.5 174v1.3l.1 .2h.3M180.4 174.6l.4-.1 .3 .2v.7l-.7 .1M180.4 174.5v1.5M182.2 174.6l-.4-.1-.2 .2 .2 .3h.4v.5h-.6M182.6 179.9v1.2l.3 .2M182.9 175.4v.1M182.9 174.6v.1"/>
<path d="M184.6 173.9l-1.3 2M186.1 173.9l-1.2 2M186.3 179.8l-1.3 1.8M187.2 174.5v1.2a.36 .36 0 0 1-.6 .2M187.2 174.6l-.4-.1-.2 .3v.6l.6 .1M187.9 174v.2M187.9 174.5v1M188.4 174.5h.6M188.7 174v1.5h.3M188.8 179.9v1.4l-.8-1.4v1.4M189.4 174.7l.3-.2 .4 .2v.8M189.4 174v1.5"/>
<path d="M190.8 179.9v1.4h.7M190.8 174.5l.1 1 .5-.1M191.4 174.5v1M192.1 174v1.5l.6-.1 .1-.6a.45 .45 0 0 0-.7-.2M193.4 175.4v.1M194.3 180a.67 .67 0 0 0-.9 .6 .67 .67 0 0 0 .9 .6v-.5h-.2M194.8 174.6l-.5-.1-.2 .2v.7l.7 .1M194.9 179.9v1.2l.3 .2h.3l.3-.2v-1.2M195.3 174.8a.45 .45 0 0 1 .7-.2v.9l-.6-.1zM196.7 174.7l.2-.2 .4 .2v.8M196.7 174.5v1M197.1 179.9h-.6v1.4h.6"/>
<path d="M197.3 174.7l.2-.2 .4 .1v.9M198.8 179.8l-1.2 1.8M199.7 173.9l-1.3 2M200.2 174.7l.2-.2 .4 .2v.8M200.2 174.5v1M200.8 174.7l.2-.2 .4 .2v.8M202.1 174.6l.4-.1 .2 .2v.8h-.6v-.4l.6-.2M203.2 179.9v1.3l.2 .1M203.4 174.5v1M203.8 174.5l-.4 .3M204.1 174.5h.6M204.3 174v1.3l.1 .2h.3"/>
<path d="M205.2 174v.2M205.2 174.5v1M205.9 174.7l.1-.2 .5 .2v.8M205.9 174.5v1M206.4 179.9l.5 1.4 .5-1.4M207.1 174.5v1M207.6 174.5l-.5 .3M208.2 174.5h.3l.2 .3-.1 .7h-.5l-.1-.3v-.4zM209 179.9h.3l.5 .3v.8l-.5 .3h-.3zM210 174.5v1.2l-.2 .3-.5-.1M210 174.6l-.4-.1-.3 .2v.7l.7 .1M210.4 179.9v.1"/>
<path d="M210.6 175l.7-.1v-.3l-.4-.1-.3 .2 .1 .8h.6M212 174.5v1M212.2 179.9v.1M212.4 174.5l-.4 .3M213.6 179.9v1.4M213.9 173.9l-1.3 2M214.2 174l.5 1.5 .4-1.5M215.5 174l.9 1.5M216.3 179.9h.8l-.5 .6h.4v.7h-.7M216.4 174l-.9 1.5M217 174h.4l.4 .4v.7l-.3 .4h-.5zM218.5 174.6l.4-.1 .2 .2v.8h-.6l-.1-.4 .7-.2"/>
<path d="M218.8 179.8l-1.3 1.8M220.3 174.6h-.6v.4h.6v.2v.3h-.6M220.9 174.7l.3-.2 .4 .2v.8M220.9 174v1.5M14.5 181.9a.65 .65 0 0 1 .8 .6 .65 .65 0 0 1-.8 .7zM38.5 195.9l.3-.4v1.3M38.5 196.8h.7M62.4 195.2v1.9M87 195.6l.7-.1 .1 .3-.8 1h.8M111 195.2v1.9M135.5 195.5h.8l-.5 .5 .5 .2-.1 .5-.5 .1-.2-.2M159.5 195.2v1.9"/>
<path d="M176 191.8h104.9M176 188.9h104.9M176 185h104.9M177.4 192.4v1.4M177.4 183.2h.5M177.6 193l.7 .8M178.1 182.5h-.7v1.4M178.2 189.8h-.8l-.1 .3 .8 .4 .1 .4-.3 .2-.6-.1M178.3 192.4l-.9 .8M178.7 182.5v.2M178.7 183v.9M178.8 189.7v.1"/>
<path d="M178.8 180.5l.4-.1 .2 .1v.8M178.8 190.2v.9M178.9 192.4v.2M178.9 192.9v.9M179.4 190.2h.7l-.7 .9h.7M179.4 182.5v1.3l.1 .1M180 183.4l.7-.1-.2-.3-.5 .2v.6l.3 .1 .3-.1M180 180.8l.7-.1-.2-.3-.5 .1v.6l.3 .2 .3-.1M180.4 192.6l-.4-.2-.5 .3 .1 1 .4 .1 .4-.1M180.6 190.6l.7-.1-.1-.3h-.6v.8h.6M181.1 192.9h.5v.9M181.3 180.8l.7-.1-.2-.3h-.3l-.2 .1v.6l.2 .2 .4-.1"/>
<path d="M181.4 183.8v.1M181.4 183.1v.1M181.6 193.2l-.5 .1-.1 .2 .1 .3h.5M181.9 191v.1M181.9 190.2v.2M182.4 180.4h.5M182.9 192.9h-.5l-.2 .7a.45 .45 0 0 0 .7 .2M182.9 183.9l.5-1.4 .5 1.4M182.9 192.4v1.4M183.1 183.5h.7M183.4 181.2v.1M183.4 180.5h.1"/>
<path d="M183.5 191.1l.5-1.4 .4 1.4M183.7 190.7h.7M184.4 195.4l-.3 1h.8M184.4 183.1l.5-.1 .1 .2v.7M184.4 183v.9M184.7 196v.8M184.8 193.1h.5M185.3 189.6l-.4 1h.9M185.5 192.4h-.7v1.4h.7M185.6 190.2v.9M185.7 183.1l.4-.1 .3 .2v.7M186 193.7v.1"/>
<path d="M186.4 183.3l-.7 .1-.1 .2 .3 .3 .5-.1M186.6 181.3l.5-1.4 .5 1.4M186.7 180.9h.7M186.8 192.4h.4l.4 .3v.8l-.4 .3h-.4zM187.1 182.5v1.3l.1 .1M187.8 183.1h.6v.7h-.6zM188.3 193.7v.1M188.7 193.8l.5-1.4 .5 1.4M188.8 193.4h.7M189.4 181.3l.5-1.4 .4 1.4M189.4 180.9h.8M189.8 183v1.2a.45 .45 0 0 1-.7 .2"/>
<path d="M189.8 183.1h-.7v.7h.7M190.2 193.7v.1M190.2 182.5l.5 1.4 .5-1.4M191.4 184.1h1.1M192 180l.5-.1a.75 .75 0 0 1 .4 .8 .75 .75 0 0 1-.7 .6l-.1-.1a.99 .99 0 0 1-.1-1.2zM192.7 193l-.2 .3h-.4l-.2-.3v-.3l.2-.3h.4l.2 .3v.8l-.2 .3h-.4M192.8 182.5a.73 .73 0 0 1 .9 .7 .73 .73 0 0 1-.9 .7zM193.3 193.7v.1M194.1 192.6l.2-.2a.75 .75 0 0 1 .6 .7 .75 .75 0 0 1-.6 .7l-.2-.1-.1-.4zM194.3 182.5v.2M194.3 183v.9M194.9 183l.3 .9 .3-.9"/>
<path d="M195.4 193.7v.1M195.4 188.9v2.9M196 182.5v.2M196 183v.9M196.4 192.4h.1a.8 .8 0 0 1 .4 .8 .8 .8 0 0 1-.5 .6 .89 .89 0 0 1 0-1.4zM196.5 180.5h.5M197.4 183.1h-.7v.7h.7M197.4 182.5v1.4M198 183.4l.7-.1v-.2l-.5-.1-.2 .2 .1 .6h.6M198.7 189.7a.73 .73 0 0 1 .9 .7 .73 .73 0 0 1-.9 .7zM199.1 181.3l.5-1.4 .5 1.4M199.3 180.9h.6"/>
<path d="M199.3 183v.9M199.8 183l-.5 .3M200.2 190.2h.6l.1 .9M200.2 183.8v.1M200.5 180.5l.5-.1 .2 .1v.8M200.5 180.4v.9M200.9 190.5l-.7 .1v.4h.7M201 182.5v1.4M201 183.4l.5 .5M201.4 190.2h.5M201.5 183l-.5 .5M201.5 189.7v1.3l.4 .1"/>
<path d="M201.9 180.5h.6v.8M202.1 182.5v.2M202.1 183v.9M202.3 190.6l.7-.1-.1-.3h-.5l-.1 .2v.6l.2 .1 .4-.1M202.5 180.7l-.6 .1-.1 .2 .3 .3 .4-.1M203.4 183.1l-.4-.1-.3 .3 .1 .5h.6M203.7 191v.1M203.7 190.2v.2M204 183.1l.4-.1 .3 .2v.7M204 180.5h.6v.7h-.6zM204.7 183.3l-.7 .1v.4h.7M205.4 189.8l.5-.1 .3 .4-.9 1h.9"/>
<path d="M205.9 183.1l-.4-.1-.2 .3 .1 .5h.5M205.9 180.4v1.2a.45 .45 0 0 1-.6 .1M205.9 180.5l-.4-.1-.3 .2 .1 .6h.6M205.9 182.5v1.4M206.3 184.1h1.2M206.9 189.8h.5a1.01 1.01 0 0 1-.2 1.3 .87 .87 0 0 1-.3-1.3zM207.5 181.5h1.1M208.1 195.2v1.9M208.1 189.8h.8l.1 .3-.9 1h.9M208.2 183.1l-.3-.1-.2 .3 .1 .1h.3l.2 .4-.2 .1-.4-.1M209.6 183.1l-.4-.1-.3 .3 .1 .5h.6M210.2 183.1l.4-.1 .3 .2v.7"/>
<path d="M210.2 182.5v1.4M210.3 189.7h-.7l-.1 .7 .6-.2 .2 .3v.4l-.2 .2-.6-.1M210.4 180.4v.9M210.9 180.4l.4 .9 .4-.9M210.9 190.5h1.1M212.2 180.4v.9M212.7 190.1l.4-.4v1.4M212.7 191.1h.9M213.6 180.5l-.5-.1-.3 .2 .1 .6h.7M214.2 180.8l.6-.1-.1-.3h-.4l-.1 .1v.6l.1 .2 .5-.1M214.2 189.8l.2-.1a.76 .76 0 0 1 .5 .7 .76 .76 0 0 1-.5 .7 1.01 1.01 0 0 1-.2-1.3zM215.5 190.5h1.1"/>
<path d="M215.5 180.4v.9M215.9 180.4l-.4 .1v.1M217.3 189.8h.8v.3l-.9 1h.9M218.6 189.7h1l-.6 1.4M233.3 195.5h-.6l-.1 .6 .2-.1h.3l.3 .2v.3l-.3 .3h-.3l-.2-.2M256.6 195.2v1.9M257.5 188.9v6.3M260 192.4v1.4M261.2 192.9h-.5l-.1 .3v.4l.2 .2h.4M261.2 192.4v1.4M261.9 193.7v.1M261.9 192.9v.2"/>
<path d="M263.7 192.6l.2-.2h.3l.3 .4-.9 1h.9M265 192.4h.9l-.5 .5 .4 .2 .1 .5-.3 .2-.6-.1M267.6 192.3l-1.3 1.9M267.9 192.4h.9l-.5 .5 .5 .2v.6l-.3 .1h-.4l-.2-.1M269.6 193l-.2-.3 .2-.3 .6 .3-.1 .2-.2 .1a.47 .47 0 0 0-.5 .6l.2 .2a.45 .45 0 0 0 .5-.1 .45 .45 0 0 0 0-.5l-.2-.2M281.5 181.9a.65 .65 0 0 1 .7 .6 .65 .65 0 0 1-.7 .7zM281.8 195.5h-.4l-.3 .5v.5l.3 .3 .4-.1v-.7h-.4l-.3 .2"/>
</g>
<g fill="none" stroke="#980000" stroke-width=".25">
<path d="M145 84.4h2v4.9h-2zM170.7 95.8h4.9v1.9h-4.9zM178 90.6l1.3 2.4h-2.5zM178.6 90h.7v.6h-2.5v.6h.7M145 102.9h2v5h-2zM177.4 178.5l.4-1.5 .5 1.5M177.5 178h.6M178.8 177v1.2l.2 .3M179.5 178l.7-.2-.2-.3h-.4l-.1 .7 .2 .3 .4-.1M180.7 177.5l.7 1M181.4 177.5l-.7 1M183.1 178.5v-1.5l.5 1 .5-1v1.5"/>
<path d="M184.7 177v.1M184.7 177.5v1M185.4 177v1.2l.3 .3M186.2 177v1.2l.2 .3M186.9 178l.7-.2-.1-.3h-.6v.9h.6M188.2 177.5v1M188.6 177.5l-.4 .3M191.2 177.7v.3l-.5 .5a.43 .43 0 0 1-.4-.2 .43 .43 0 0 1 0-.5l.6-.5-.1-.3h-.3a.55 .55 0 0 0 .2 .8l.7 .7M193.1 178.5v-1.5l.5 1 .5-1v1.5M194.8 177.5h.6v1M195.4 177.8l-.4 .1-.3 .2 .3 .4 .4-.1M196.2 177.5v1"/>
<path d="M196.5 177.5h-.2l-.1 .3M196.8 177.5h.6M197 177v1.2l.4 .3M197.9 177v.1M197.9 177.5v1M198.5 177.6l.1-.1a.36 .36 0 0 1 .6 .2v.8M198.5 177.5v1M201 177.8l.7-.1 .1-.2v-.4l-.8-.1v1.5M201.3 177.8l.5 .7M204.4 177.5v1.1l-.2 .3h-.4M204.4 177.5h-.4l-.3 .3 .1 .6h.6M205 178l.7-.2-.1-.3h-.4l-.2 .2 .1 .7h.5"/>
<path d="M206.3 177.5v1M206.8 177.5l-.5 .3M260.1 190.5l.7-.1 .1-.6-.8-.1v1.5M260.4 190.5l.5 .7M261.4 190.7l.7-.1-.1-.4h-.5l-.1 .7 .2 .3 .4-.1M262.6 190.2l.4 1 .3-1M263.9 191v.2M263.9 190.2v.2M265.6 190.2l.4-.5v1.5M265.6 191.2h.8M267 191v.2M267.7 190.2l.4-.5v1.5"/>
<path d="M267.7 191.2h.9"/>
<circle cx="202.7" cy="178" r=".48"/>
</g>
<g fill="none" stroke="#980000" stroke-width=".42">
<path d="M177.7 185.8h1.1M178.2 185.8l-.2 1.9M179.3 186.4l-.1 1.3M179.4 185.8v.1M180 186.4h.8M180.3 185.8l-.1 1.6 .4 .3M181.4 185.8l-.1 1.6 .2 .3M182.2 187l1-.1-.1-.4a.6 .6 0 0 0-.8 .2v.9h.7M184 187.5l-.1 .2-.1-.1 .2-.1-.1 .2M184.1 186.5v.2M186 187.7l.9-1.9 .5 1.9M186.3 187.1h.9"/>
<path d="M188.1 186.6l.3-.2 .5 .1-.1 1.2M188.1 186.4l-.1 1.3M189.9 186.5h.8l-.1 1.2M190.7 186.9l-.9 .1-.2 .4 .3 .3 .7-.1M191.8 185.8l-.3 1.6 .3 .3M192.6 186.6l.3-.2 .5 .1 .1 .3v.6a.55 .55 0 0 1-.6 .3 .55 .55 0 0 1-.5-.3zM195.2 186.4l-.2 1.7a.45 .45 0 0 1-.8 .1M195.2 186.5l-.5-.1-.4 .4v.7l.3 .2 .5-.1M197.4 185.8l.5 1.9 .9-1.9M201.6 186.5a.65 .65 0 0 0-.9 .3l-.1 .6 .1 .2h.8M201.8 185.8l-.3 1.9M202.6 185.8v.1"/>
<path d="M202.6 186.4l-.2 1.3M203.3 186.4l.3 1.3 .6-1.3M205 186.4l-.2 1.3M205.1 185.8v.1M206.8 186.5a.72 .72 0 0 0-1.1 .3l-.1 .6 .2 .2h.8M206.8 185.8l-.2 1.9M207.5 187l.9-.1v-.4a.6 .6 0 0 0-.9 .2v.9h.8M209.3 186.4l-.2 1.3M209.9 186.4l-.4 .1-.2 .3"/>
</g>
<path d="M181.7 96h.6l.6 .7-.6 .6h-.6z" fill="#fff"/>
<g fill="none" stroke="#805e00" stroke-width=".21">
<path d="M181.7 96h.6l.6 .7-.6 .6h-.6zM183.3 97.2l.5-1.2 .4 1.2M183.4 96.9h.6M184.6 96.6l.4-.1 .1 .7M184.6 96.5v.7M185.7 96.5h.4l.1 .1v.6h-.5l-.1-.2 .6-.3M186.8 96v1.1l.2 .1M187.4 96.6h.6l-.1 .6-.5-.1zM189.1 97.2h-.5v-.7h.5l-.1 1.2h-.4M189.4 97.4h.9M190.7 96.1h.5a.87 .87 0 0 1 0 1.1h-.5a.87 .87 0 0 1 0-1.1zM191.9 96v1.1l.2 .1 .5-.1v-1.1"/>
<path d="M193 96h.8M193.4 96v1.2"/>
</g>
<path d="M126.7 83.9h4M126.7 82.4h4M177.2 106h4M177.2 104.6h4" fill="none" stroke="#980000" stroke-width=".51"/>
<path d="M128.7 79.5v2.7M128.7 88.1v1.2h1.2l-1.2 1.2-1.2-1.2h1.2M128.7 88.1h.1M128.7 84.1v2.7M179.3 101.6v2.7M179.3 106.3v2.7" fill="none" stroke="#980000" stroke-width=".21"/>
<path d="M111.5 77.6h.6l.5 .6-.5 .7h-.6z" fill="#fff"/>
<g fill="none" stroke="#805e00" stroke-width=".21">
<path d="M102.3 78.8l.4-1.3 .4 1.3M102.4 78.4h.6M103.5 78.1l.2-.2 .3 .1v.8M103.5 77.9v.9M104.6 78l.4-.1 .2 .2v.7M105.2 78.3l-.6 .1v.3h.6M105.8 77.5v1.2l.2 .1M106.4 78.1l.1-.2 .4 .1v.7h-.5zM108.1 77.9v1l-.3 .3-.3-.1M108.1 78l-.5-.1-.1 .2v.6h.6M108.3 78.9h1M109.6 77.5v1.3"/>
<path d="M110.9 77.5v1.3l-.7-1.3v1.3M111.5 77.6h.6l.5 .6-.5 .7h-.6z"/>
</g>
<path d="M115.1 77.3h5v1.9h-5z" fill="none" stroke="#980000" stroke-width=".25"/>
<path d="M113.9 78.2h1.2M120.1 78.2h1.2M176.7 78.3h2.6v6.2l-1.3 1.1-1.3-1.1zM177.4 82.4v-.7l.5 .4v-.4h.7l.1 .5-.2 .2M177.4 80.5l1.3 .4-1.3 .4M177.4 80.2v-.7l.5 .4 .1-.4h.5l.2 .1v.4l-.2 .2M177.8 83.3h.9M178.2 82.9v1" fill="none" stroke="#980000" stroke-width=".21"/>
<path d="M112.6 78.2h1.3M121.3 78.2h24.6v5M128.7 78.2v1.3M128.7 86.8v1.3M145.9 96.7h23.5M145.9 90.5v11.1M176.7 96.7h5M178 85.6v2.5M178 95.5v1.2M179.3 96.7v4.9M145.9 109v6.2M179.3 109v3.7h-33.4" fill="none" stroke="#00a200" stroke-width=".21"/>
<g fill="none" stroke="#001dcd" stroke-width=".21">
<path d="M165.6 74.5h29.7v37h-29.7zM167 76.2l.6-.1 .1-.5-.7-.1v1.2M167.4 78.1l-.1 .2-.3-.2-.2 .2M167.8 77.8l.4-.3v1.2M167.8 78.7h.7M168.2 75.5v1.1l.2 .1M168.9 76h.5v.7M169.4 76.2l-.6 .2 .1 .3h.5M169.5 77.5a.55 .55 0 0 0-.6 .5l.1 .6 .5 .1 .2-.3v-.2l-.2-.3h-.3l-.3 .3M170.2 77.5v1.2M170.3 78.3l.4 .4M170.6 76h-.6v.6l.1 .1h.5"/>
<path d="M170.7 77.8l-.5 .6M171 76.3l.6-.1-.2-.3-.4 .2v.5l.1 .1h.4M171.2 77.5v1.2M171.2 78.1h.7M171.9 77.5v1.2M172.4 77.8h.6l-.6 .9h.6M173 76l.3-.1 .3 .2v.6M173 75.9v.8M174.1 76.3l.6-.1-.2-.3-.4 .2v.5l.2 .1h.3M174.5 78.1h.5l.1-.5-.6-.1v1.2M174.7 78.1l.4 .6M175.2 76h.5v.7"/>
<path d="M175.7 76.2l-.6 .2 .2 .3h.4M176.3 75.9v.8M176.4 77.6l-.5-.1a.61 .61 0 0 0-.3 .8 .61 .61 0 0 0 .8 .3M176.7 75.9l-.4 .3M177.8 76.7l.5-1.2 .4 1.2M178 76.4h.6M179.1 75.5a.64 .64 0 0 1 .7 .6 .64 .64 0 0 1-.7 .6zM181.1 75.6l-.5-.1-.3 .3 .1 .8 .2 .1 .5-.1M105.3 97.9h37v14.8h-37zM107.1 98.9h-.6v.6l.2-.1h.4v.7l-.6-.1M108.9 98.9h-.6v.6l.4-.1 .3 .2v.3l-.2 .2-.5-.1M109.3 98.9l.5 1.2 .4-1.2"/>
<path d="M111.5 98.9v.1M111.5 99.4v.7M112.1 99.4h.5v.7M112.1 99.4v.7M114.2 99.5h.9M114.2 99.9h.9M116.5 98.9h.8l-.4 .5 .4 .2v.3l-.2 .2-.6-.1M118.2 98.9h.8l-.3 .5 .3 .1v.5h-.8M119.4 98.9l.4 1.2 .4-1.2M121.5 99.4h.5v.7l-.5-.1zM122.6 99.4l.1 .7 .5-.1M123.2 99.4v.7"/>
<path d="M123.7 99.4h.4M123.8 98.9v1.2h.3M106.5 101l.5-.1 .2 .3-.7 .9h.7M107 103.3h-.5v.4h.4l.2 .1-.1 .3h-.5M107.6 103.7l.5-.1v-.3h-.5v.8h.5M107.7 100v.1M108.3 100.9h-.6v.6l.6-.1a.45 .45 0 0 1 0 .6 .45 .45 0 0 1-.6 .1v-.1M108.7 103.4l.4-.1 .1 .8M108.7 103.3v.8M109.2 100.9a.68 .68 0 0 1 .4 .6 .68 .68 0 0 1-.4 .6 .75 .75 0 0 1 0-1.2zM110.1 100.9v1.2M110.2 103.3h-.4l-.1 .2 .1 .2 .4 .1v.3h-.5"/>
<path d="M110.2 101.6l.4 .5M110.6 101.3l-.5 .5M110.8 103.3h.4l.2 .2-.2 .6h-.4zM111.9 101.3h.4M111.9 103.3v.8M112.1 100.9v1.1l.2 .1M112.2 103.3h-.2l-.1 .2M112.7 101.4h.5v.7h-.3l-.2-.1zM113.1 103.3h-.5v.2v.2l.5 .1v.3h-.5M113.7 101.3h.5M113.8 100.9v1.1l.4 .1M114.4 103.3h.4"/>
<path d="M114.6 101.4l.3-.1 .2 .2v.6M114.6 102.9v1.2h.2M115.1 101.6h-.4l-.2 .2 .2 .3h.4M115.2 103.5l.2-.2h.4v.8h-.4zM115.7 100.9v1.1l.2 .1M116.4 103.4l.5-.1v.8l-.5-.1zM117.3 100.9v.1M117.3 101.3v.8M117.8 100v.1M117.9 101.4l.3-.1 .2 .2v.6M117.9 101.3v.8M118.4 101.5l.2-.2 .3 .2v.6"/>
<path d="M118.4 103.4l.5-.1 .1 .8M118.4 103.3v.8M119 103.5v-.2h.4l.1 .8M119.5 101.4l.3-.1 .3 .3-.1 .5h-.5M119.5 101.3v1.3M120.1 103.3l.1 .8 .4-.1M120.5 101.7l.6-.1v-.2l-.3-.1-.3 .2v.5l.3 .1h.3M120.6 103.3v.8M121.7 103.3h-.4l-.2 .2 .2 .6h.4M122.2 101.4a.36 .36 0 0 0-.6 .2l.1 .5h.5M122.2 100.9v1.2M122.3 103.4l.4-.1 .1 .8"/>
<path d="M122.3 102.9v1.2M122.8 101.4l.3-.1 .2 .2v.6M123.3 101.6h-.4l-.2 .2 .2 .3h.4M123.4 104v.1M123.9 101.4h.5v.7M123.9 101.3v.8M124.5 100v.1M125.5 101.4l-.3-.1-.3 .3v.3l.3 .2h.3M126 101.7l.6-.1-.2-.3-.4 .2v.5l.2 .1h.3M128.5 101.4h-.4v.2l.3 .1 .2 .3-.2 .1h-.3M129.1 101.4h.5v.7M129.1 100.9v1.2"/>
<path d="M130.2 101.4h.5v.7h-.4l-.2-.2zM131.3 101.3v.7l.1 .1 .5-.1M131.9 101.3v.8M132.5 100.9v1.2h.1M133.6 101.4l-.4-.1-.2 .3v.3l.2 .2h.4M133.6 100.9v1.2M134.1 101.4l.4-.1 .2 .2v.6M134.1 101.3v.8M135.3 100.9l-.1 .2M135.7 101.3h.5M135.8 100.9v1.1l.4 .1M137.5 100.9v1.1l.2 .1"/>
<path d="M138.1 101.4h.6v.6l-.1 .1-.5-.1zM139.3 101.4l.4-.1 .1 .2v.6M139.8 101.6h-.4l-.2 .2 .2 .3h.4M140.9 101.4l-.3-.1-.3 .3 .1 .5h.5M140.9 100.9v1.2"/>
</g>
<g fill="#00a200">
<circle cx="179.3" cy="96.7" r=".47"/>
<circle cx="145.9" cy="112.7" r=".47"/>
<circle cx="145.9" cy="96.7" r=".47"/>
<circle cx="178" cy="96.7" r=".47"/>
<circle cx="128.7" cy="78.2" r=".47"/>
</g>
<path d="M133.4 85h-.6l-.1 .5 .2-.1h.3l.3 .2v.4l-.2 .1h-.6M134.1 85h.3l.2 .2v.8l-.2 .1h-.3a.87 .87 0 0 1 0-1.1zM135 85l.3 1.1 .5-1.1M183.9 107.1h-.6v.6l.1-.1h.4l.2 .2v.4l-.2 .1-.5-.1M184.6 107.2l.3-.1 .2 .3v.8l-.2 .1-.3-.1a.78 .78 0 0 1 0-1zM185.5 107.1l.4 1.2 .4-1.2" fill="none" stroke="#970091" stroke-width=".21"/>
<g fill="none" stroke="#007170" stroke-width=".21">
<path d="M116 74.2l.4-.3v1.2M116 75.1h.7M116.1 72h.6v-.6h-.6v1.2M116.4 72l.4 .6M117.3 74l.4-.1 .2 .1v.9l-.2 .2-.4-.1zM117.9 71.4h-.4l-.2 .3v.8h.6v-.6l-.4-.1-.2 .3M118.5 74.5h.5l.2-.5-.2-.1h-.5v1.2M118.7 71.9l-.2-.4 .5-.1 .2 .3-.3 .2-.4 .1v.5l.2 .1 .4-.1 .1-.2-.3-.4M118.7 74.5l.5 .6M127.7 92.4l-.1-.1a.64 .64 0 0 0-.6 .6 .64 .64 0 0 0 .5 .7l.3-.2v-.4h-.3M129.1 92.3v1.3l-.8-1.3v1.3M129.7 92.3a.64 .64 0 0 1 .7 .7 .64 .64 0 0 1-.7 .6z"/>
<path d="M132.7 82.8l.3-.3v1.2M132.7 83.7h.8M133.5 80.1l-.5-.1a.61 .61 0 0 0-.3 .8 .61 .61 0 0 0 .8 .3M133.9 80h.8l-.5 .5 .4 .1v.5h-.7M134.1 82.5h.3l.2 .2-.1 .9h-.4a.94 .94 0 0 1 0-1.1zM135.1 80h.8l-.6 1.2M135.2 82.6l.4-.1 .2 .2v.7l-.2 .3-.4-.1zM136.4 83l.1-.2 .3 .1 .1 .8M136.4 82.8v.9M148.8 87.8l.3-.4v1.2M148.8 85.5h.6l.2-.1-.1-.4h-.7v1.1M148.8 88.6h.7"/>
<path d="M149.1 85.5l.5 .6M150.1 87.5l.2-.1a.84 .84 0 0 1 .2 1.2h-.3a.78 .78 0 0 1-.1-1.1zM150.6 85h-.4a.94 .94 0 0 0 0 1.1h.5v-.6l-.5-.1-.2 .2M151.3 87.5l.2-.1a.84 .84 0 0 1 .2 1.2l-.4-.1a.78 .78 0 0 1 0-1zM151.8 85.5l-.1 .2-.4-.1v-.6h.5v.9l-.1 .2h-.4M152.4 87.4v1.2M152.4 88.2l.4 .4M152.8 87.8l-.4 .5M171.6 90.5h.5l.1-.1v-.4l-.6-.1v1.2M171.9 90.5l.3 .6M172.2 92.7l.4-.4v1.3M172.2 93.6h.7"/>
<path d="M172.7 89.9h.8l-.5 1.2M173.4 92.3v1.3M173.6 93.1l.3 .5M173.9 90.2l.4-.3v1.2M173.9 92.7l-.5 .6M173.9 91.1h.7M180.9 92.6h.5l.1-.4-.2-.2h-.4v1.3l.6-.1 .1-.4-.3-.2M180.9 89.5a.64 .64 0 0 1 .7 .7 .64 .64 0 0 1-.7 .6zM181.9 93.3l.4-1.3 .4 1.3M182.1 92.9h.6M182.7 89.5l-.5 .1-.1 .3v.8h.6v-.6l-.5-.1-.1 .3M183 92h.7"/>
<path d="M183.3 92v1.3M184.7 92h-.6l-.1 .6h.7v.6h-.7M185.5 92l-.3 .8h.8M185.8 92.4v.9M145 119.5a.61 .61 0 0 0-.7 .3 .61 .61 0 0 0 .1 .7l.3 .2 .4-.1v-.4h-.3M146.3 119.4v1.3l-.7-1.3v1.3M146.8 119.4a.65 .65 0 0 1 .8 .7 .65 .65 0 0 1-.8 .6zM148.8 106.2l.3-.3v1.2M148.8 104.1h.5l.3-.4-.3-.3h-.5v1.3M148.8 107.1h.7M149.1 104.1l.5 .6M149.9 103.4h.8l-.5 1.3"/>
<path d="M150.6 105.9h-.6l-.1 .6h.7l.1 .4-.3 .2-.5-.1M151.3 106a.61 .61 0 0 1 .6 .4 .61 .61 0 0 1-.4 .7 .71 .71 0 0 1-.2-1.1zM151.4 103.4l.4 .3v.7l-.2 .3a.75 .75 0 0 1-.2-1.3zM152.4 105.9v1.2M152.4 106.6l.4 .5M152.8 106.3l-.4 .5M183.3 105l.3-.3v1.2M183.3 105.9h.7M184 102.3l-.5-.1a.61 .61 0 0 0-.2 .8 .61 .61 0 0 0 .7 .3M184.4 102.2h.8l-.4 .5h.3v.6h-.7M184.6 104.7h.3l.2 .2v.8l-.2 .2-.3-.1a.87 .87 0 0 1 0-1.1zM185.7 105.2l.4-.1 .1 .8"/>
<path d="M185.7 105.1v.8M185.9 102.7l-.2-.4 .6-.1v.5l-.6 .1v.5l.4 .1a.35 .35 0 0 0 .3-.3 .35 .35 0 0 0-.3-.4"/>
</g>
</svg>
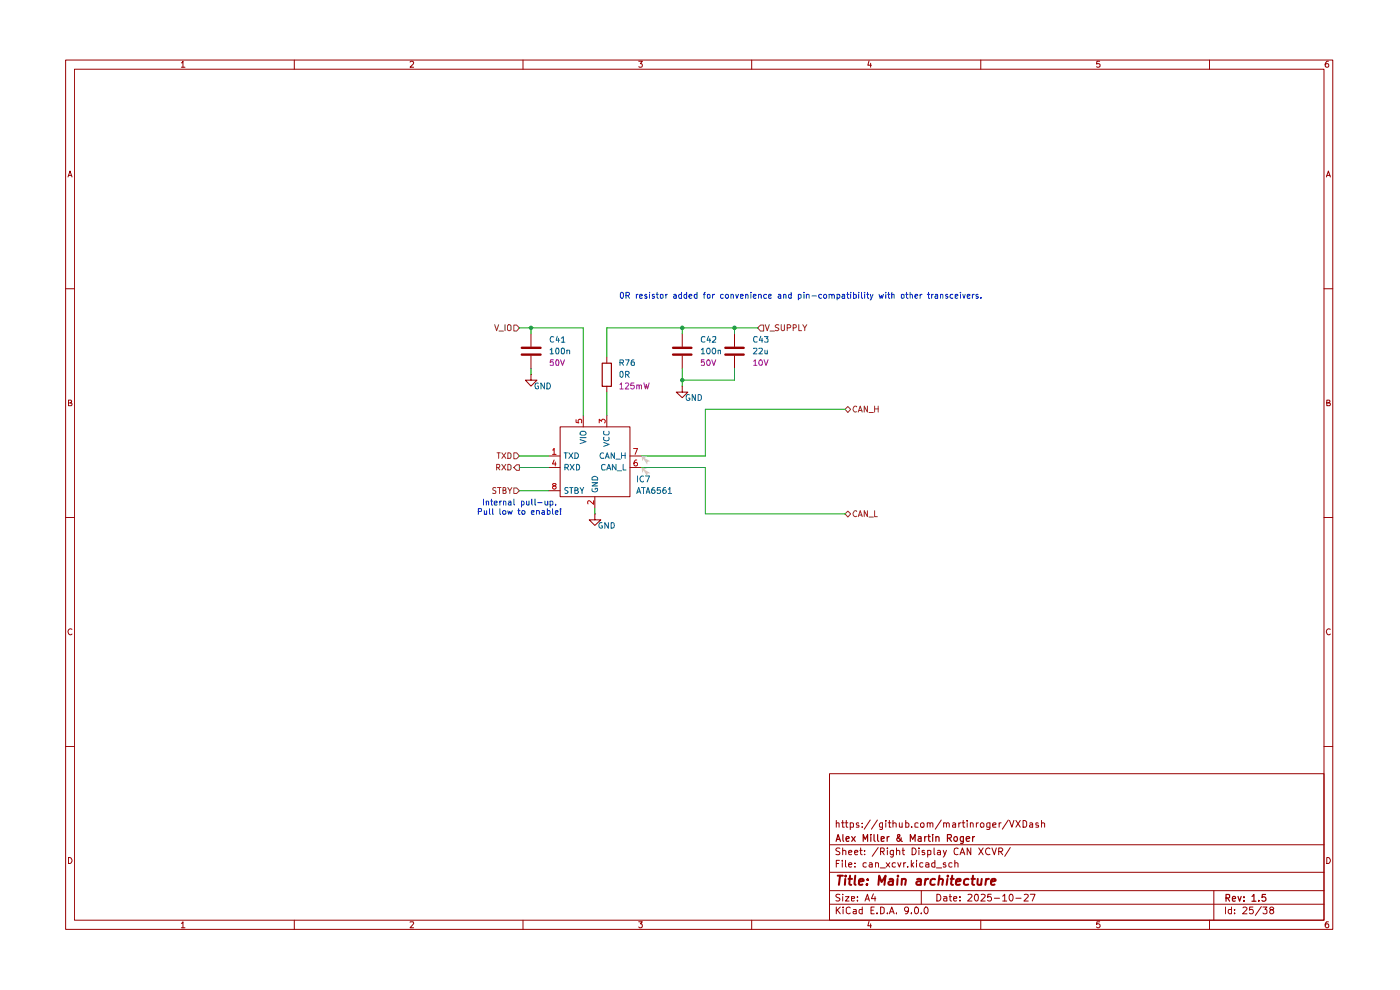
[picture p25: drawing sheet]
<svg xmlns="http://www.w3.org/2000/svg" width="297mm" height="210mm" viewBox="0 0 297 210" stroke-linecap="round" stroke-linejoin="round" font-family="sans-serif">
<g fill="none" stroke="#980000" stroke-width=".21">
<path d="M13.9 12.7h268.8v184.4h-268.8zM15.8 14.7h265.1v180.5h-265.1zM38.5 13.3h.1l.2-.3v1.3M38.5 14.3h.7M62.4 12.7v2M87 13.2l.5-.2 .3 .2-.1 .4-.7 .7h.8M111 12.7v2M135.5 13h.8l-.5 .5 .4 .1v.6h-.7M159.5 12.7v2M184.4 12.9l-.3 .9h.8M184.7 13.4v.9M208.1 12.7v2"/>
<path d="M233.3 13h-.6l-.1 .6h.7v.6h-.7M256.6 12.7v2M281.8 13a.71 .71 0 0 0-.7 .5 .71 .71 0 0 0 .3 .8l.4-.1v-.6l-.4-.1-.3 .3M14.4 37.5l.5-1.2 .4 1.2M14.5 37.2h.7M281.4 37.5l.4-1.2 .4 1.2M281.5 37.2h.6M13.9 61.3h1.9M280.9 61.3h1.8M14.5 85.5h.4l.3-.3-.2-.3h-.5v1.2h.6l.2-.5-.4-.1M281.5 85.5h.4l.2-.3-.1-.3h-.5v1.2h.6l.1-.5-.3-.1M13.9 109.8h1.9"/>
<path d="M280.9 109.8h1.8M15.3 133.5a.59 .59 0 0 0-.9 .5 .59 .59 0 0 0 .8 .6l.1-.1M282.2 133.5a.59 .59 0 0 0-.8 .5 .59 .59 0 0 0 .7 .6l.1-.1M13.9 158.4h1.9M280.9 158.4h1.8M176 164.1h104.9v31.1h-104.9zM176 179.2h104.9M177.4 174.7l.2-.2 .4 .1v.9M177.4 174v1.5M178.2 180l-.6-.1-.3 .2 .1 .4 .8 .4-.1 .3h-.8M178.5 174.5h.6M178.8 174v1.5h.3"/>
<path d="M178.8 179.9v1.4M179.4 174.5h.5M179.5 174v1.3l.1 .2h.3M180.4 174.6l.4-.1 .3 .2v.7l-.7 .1M180.4 174.5v1.5M182.2 174.6l-.4-.1-.2 .2 .2 .3h.4v.5h-.6M182.6 179.9v1.2l.3 .2M182.9 175.4v.1M182.9 174.6v.1M184.6 173.9l-1.3 2M186.1 173.9l-1.2 2M186.3 179.8l-1.3 1.8"/>
<path d="M187.2 174.5v1.2a.36 .36 0 0 1-.6 .2M187.2 174.6l-.4-.1-.2 .3v.6l.6 .1M187.9 174v.2M187.9 174.5v1M188.3 179.9v.1M188.4 174.5h.6M188.7 174v1.5h.3M189.4 174.7l.3-.2 .4 .2v.8M189.4 174v1.5M190.2 179.9v1.4M190.8 174.5l.1 1 .5-.1M191.4 174.5v1"/>
<path d="M191.6 179.9v1.2l.3 .2M192.1 174v1.5l.6-.1 .1-.6a.45 .45 0 0 0-.7-.2M193.4 175.4v.1M193.5 179.9a.73 .73 0 0 1 .9 .7 .73 .73 0 0 1-.9 .7zM194.8 174.6l-.5-.1-.2 .2v.7l.7 .1M194.9 179.9v.1M195.3 174.8a.45 .45 0 0 1 .7-.2v.9l-.6-.1zM196.7 174.7l.2-.2 .4 .2v.8M196.7 174.5v1M197.3 174.7l.2-.2 .4 .1v.9M198.2 179.9v1.2l.1 .2M199.7 173.9l-1.3 2"/>
<path d="M200.2 174.7l.2-.2 .4 .2v.8M200.2 174.5v1M200.8 174.7l.2-.2 .4 .2v.8M202.1 174.6l.4-.1 .2 .2v.8h-.6v-.4l.6-.2M203.4 174.5v1M203.8 174.5l-.4 .3M204.1 174.5h.6M204.3 174v1.3l.1 .2h.3M205.2 174v.2M205.2 174.5v1M205.9 174.7l.1-.2 .5 .2v.8M205.9 174.5v1"/>
<path d="M205.9 179.9v1.4l-.7-1.4v1.4M207.1 174.5v1M207.6 174.5l-.5 .3M207.6 179.9l1 1.4M208.2 174.5h.3l.2 .3-.1 .7h-.5l-.1-.3v-.4zM208.6 179.9l-1 1.4M210 174.5v1.2l-.2 .3-.5-.1M210 174.6l-.4-.1-.3 .2v.7l.7 .1M210.4 179.9l.5 1.4 .5-1.4M210.6 175l.7-.1v-.3l-.4-.1-.3 .2 .1 .8h.6M212 174.5v1M212.4 174.5l-.4 .3"/>
<path d="M213.9 173.9l-1.3 2M214.2 174l.5 1.5 .4-1.5M214.3 179.8l-1.2 1.8M215.5 174l.9 1.5M216.4 174l-.9 1.5M217 174h.4l.4 .4v.7l-.3 .4h-.5zM218.5 174.6l.4-.1 .2 .2v.8h-.6l-.1-.4 .7-.2M220.3 174.6h-.6v.4h.6v.2v.3h-.6M220.9 174.7l.3-.2 .4 .2v.8M220.9 174v1.5M14.5 181.9a.65 .65 0 0 1 .8 .6 .65 .65 0 0 1-.8 .7zM38.5 195.9l.3-.4v1.3"/>
<path d="M38.5 196.8h.7M62.4 195.2v1.9M87 195.6l.7-.1 .1 .3-.8 1h.8M111 195.2v1.9M135.5 195.5h.8l-.5 .5 .5 .2-.1 .5-.5 .1-.2-.2M159.5 195.2v1.9M176 191.8h104.9M176 188.9h104.9M176 185h104.9M177.4 192.4v1.4M177.4 183.2h.5M177.6 193l.7 .8"/>
<path d="M178.1 182.5h-.7v1.4M178.2 189.8h-.8l-.1 .3 .8 .4 .1 .4-.3 .2-.6-.1M178.3 192.4l-.9 .8M178.7 182.5v.2M178.7 183v.9M178.8 189.7v.1M178.8 180.5l.4-.1 .2 .1v.8M178.8 190.2v.9M178.9 192.4v.2M178.9 192.9v.9M179.4 190.2h.7l-.7 .9h.7M179.4 182.5v1.3l.1 .1"/>
<path d="M180 183.4l.7-.1-.2-.3-.5 .2v.6l.3 .1 .3-.1M180 180.8l.7-.1-.2-.3-.5 .1v.6l.3 .2 .3-.1M180.4 192.6l-.4-.2-.5 .3 .1 1 .4 .1 .4-.1M180.6 190.6l.7-.1-.1-.3h-.6v.8h.6M181.1 192.9h.5v.9M181.3 180.8l.7-.1-.2-.3h-.3l-.2 .1v.6l.2 .2 .4-.1M181.4 183.8v.1M181.4 183.1v.1M181.6 193.2l-.5 .1-.1 .2 .1 .3h.5M181.9 191v.1M181.9 190.2v.2M182.4 180.4h.5"/>
<path d="M182.9 192.9h-.5l-.2 .7a.45 .45 0 0 0 .7 .2M182.9 192.4v1.4M183.4 181.2v.1M183.4 180.5h.1M183.5 191.1l.5-1.4 .4 1.4M183.7 190.7h.7M183.8 183.1l-.5-.1-.2 .3 .1 .5h.6M184.4 195.4l-.3 1h.8M184.4 183.1l.5-.1 .1 .2v.7M184.7 196v.8M184.8 193.1h.5M185 183.3l-.6 .1v.2l.1 .3 .5-.1"/>
<path d="M185.3 189.6l-.4 1h.9M185.5 192.4h-.7v1.4h.7M185.6 190.2v.9M185.7 183.1l.4-.1 .3 .2v.7M185.7 183v.9M186 193.7v.1M186.7 184.1h1.1M186.8 192.4h.4l.4 .3v.8l-.4 .3h-.4zM186.8 180.6l.7-.1 .1-.5-.3-.1h-.5v1.4M187.2 180.6l.4 .7M188 183l.8 .9M188.3 193.7v.1"/>
<path d="M188.3 180.4v.9M188.7 193.8l.5-1.4 .5 1.4M188.8 183l-.8 .9M188.8 193.4h.7M189.5 180.4v1.2l-.2 .2-.4-.1M189.5 180.5l-.4-.1-.3 .2 .1 .6h.6M189.9 183.1l-.4-.1-.2 .3 .1 .5h.5M190.2 193.7v.1M190.2 180.5l.4-.1 .3 .1v.8M190.5 183l.3 .9 .3-.9M191.4 180.4h.5M191.7 183v.9"/>
<path d="M192.1 183l-.4 .1v.2M192.6 183.8v.1M192.7 193l-.2 .3h-.4l-.2-.3v-.3l.2-.3h.4l.2 .3v.8l-.2 .3h-.4M193.3 193.7v.1M193.3 182.5v1.4M193.4 183.4l.4 .5M193.8 183l-.5 .5M194.1 192.6l.2-.2a.75 .75 0 0 1 .6 .7 .75 .75 0 0 1-.6 .7l-.2-.1-.1-.4zM194.4 182.5v.2M194.4 183v.9M194.9 180.4v.9M195.4 193.7v.1"/>
<path d="M195.4 188.9v2.9M195.8 183.1l-.4-.1-.3 .3 .1 .5h.6M196.1 180.5h-.5v.3l.5 .1 .1 .2-.2 .2-.4-.1M196.4 192.4h.1a.8 .8 0 0 1 .4 .8 .8 .8 0 0 1-.5 .6 .89 .89 0 0 1 0-1.4zM196.4 183.1l.4-.1 .3 .2v.7M196.8 180.5h.7v.7h-.7M196.8 180.4v1.4M197.1 183.3l-.7 .1v.4h.7M198.3 183.1l-.4-.1-.3 .3 .1 .5h.6M198.3 182.5v1.4M198.7 184.1h1.1M198.7 189.7a.73 .73 0 0 1 .9 .7 .73 .73 0 0 1-.9 .7z"/>
<path d="M198.9 180.5l.4-.1 .2 .1v.8M199.5 180.7l-.6 .1-.1 .2 .2 .3 .5-.1M200.1 180.4l.3 .9M200.2 190.2h.6l.1 .9M200.6 183.1l-.3-.1-.2 .3 .1 .1h.3l.2 .4-.2 .1-.4-.1M200.8 180.4l-.7 1.4M200.9 190.5l-.7 .1v.4h.7M201.4 190.2h.5M201.5 189.7v1.3l.4 .1M202 183.1l-.5-.1-.2 .3 .1 .5h.6M202.3 190.6l.7-.1-.1-.3h-.5l-.1 .2v.6l.2 .1 .4-.1M202.6 183.1l.4-.1 .2 .2v.7"/>
<path d="M202.6 182.5v1.4M203.2 180a.55 .55 0 0 0-.7 0 .55 .55 0 0 0-.1 .7l.1 .4 .4 .2 .3-.1M203.7 191v.1M203.7 190.2v.2M203.7 181.3l.5-1.4 .5 1.4M203.8 180.9h.7M205.4 189.8l.5-.1 .3 .4-.9 1h.9M206.9 189.8h.5a1.01 1.01 0 0 1-.2 1.3 .87 .87 0 0 1-.3-1.3zM208.1 195.2v1.9M208.1 189.8h.8l.1 .3-.9 1h.9M210 180a.65 .65 0 0 0-.9 .6 .65 .65 0 0 0 .8 .6h.1M210.3 189.7h-.7l-.1 .7 .6-.2 .2 .3v.4l-.2 .2-.6-.1"/>
<path d="M210.9 190.5h1.1M211.9 180.6h.6l.2-.2v-.3l-.2-.2h-.6v1.4M212.2 180.6l.5 .7M212.7 190.1l.4-.4v1.4M212.7 191.1h.9M214.2 189.8l.2-.1a.76 .76 0 0 1 .5 .7 .76 .76 0 0 1-.5 .7 1.01 1.01 0 0 1-.2-1.3zM215.5 190.5h1.1M217.3 189.8h.8v.3l-.9 1h.9M218.6 189.7h1l-.6 1.4M233.3 195.5h-.6l-.1 .6 .2-.1h.3l.3 .2v.3l-.3 .3h-.3l-.2-.2M256.6 195.2v1.9M257.5 188.9v6.3"/>
<path d="M260 192.4v1.4M261.2 192.9h-.5l-.1 .3v.4l.2 .2h.4M261.2 192.4v1.4M261.9 193.7v.1M261.9 192.9v.2M263.7 192.6l.2-.2h.3l.3 .4-.9 1h.9M265.8 192.4h-.7l-.1 .7 .6-.2 .3 .3v.4l-.3 .2-.6-.1M267.6 192.3l-1.3 1.9M267.9 192.4h.9l-.5 .5 .5 .2v.6l-.3 .1h-.4l-.2-.1M269.6 193l-.2-.3 .2-.3 .6 .3-.1 .2-.2 .1a.47 .47 0 0 0-.5 .6l.2 .2a.45 .45 0 0 0 .5-.1 .45 .45 0 0 0 0-.5l-.2-.2M281.5 181.9a.65 .65 0 0 1 .7 .6 .65 .65 0 0 1-.7 .7zM281.8 195.5h-.4l-.3 .5v.5l.3 .3 .4-.1v-.7h-.4l-.3 .2"/>
</g>
<g fill="none" stroke="#980000" stroke-width=".25">
<path d="M177.4 178.5l.4-1.5 .5 1.5M177.5 178h.6M178.8 177v1.2l.2 .3M179.5 178l.7-.2-.2-.3h-.4l-.1 .7 .2 .3 .4-.1M180.7 177.5l.7 1M181.4 177.5l-.7 1M183.1 178.5v-1.5l.5 1 .5-1v1.5M184.7 177v.1M184.7 177.5v1M185.4 177v1.2l.3 .3M186.2 177v1.2l.2 .3M186.9 178l.7-.2-.1-.3h-.6v.9h.6"/>
<path d="M188.2 177.5v1M188.6 177.5l-.4 .3M191.2 177.7v.3l-.5 .5a.43 .43 0 0 1-.4-.2 .43 .43 0 0 1 0-.5l.6-.5-.1-.3h-.3a.55 .55 0 0 0 .2 .8l.7 .7M193.1 178.5v-1.5l.5 1 .5-1v1.5M194.8 177.5h.6v1M195.4 177.8l-.4 .1-.3 .2 .3 .4 .4-.1M196.2 177.5v1M196.5 177.5h-.2l-.1 .3M196.8 177.5h.6M197 177v1.2l.4 .3M197.9 177v.1M197.9 177.5v1"/>
<path d="M198.5 177.6l.1-.1a.36 .36 0 0 1 .6 .2v.8M198.5 177.5v1M201 177.8l.7-.1 .1-.2v-.4l-.8-.1v1.5M201.3 177.8l.5 .7M204.4 177.5v1.1l-.2 .3h-.4M204.4 177.5h-.4l-.3 .3 .1 .6h.6M205 178l.7-.2-.1-.3h-.4l-.2 .2 .1 .7h.5M206.3 177.5v1M206.8 177.5l-.5 .3M260.1 190.5l.7-.1 .1-.6-.8-.1v1.5M260.4 190.5l.5 .7M261.4 190.7l.7-.1-.1-.4h-.5l-.1 .7 .2 .3 .4-.1"/>
<path d="M262.6 190.2l.4 1 .3-1M263.9 191v.2M263.9 190.2v.2M265.6 190.2l.4-.5v1.5M265.6 191.2h.8M267 191v.2M268.5 189.7h-.7l-.1 .7 .2-.2 .5 .1 .2 .6-.4 .3h-.3l-.2-.2"/>
<circle cx="202.7" cy="178" r=".48"/>
</g>
<g fill="none" stroke="#980000" stroke-width=".42">
<path d="M177.7 185.8h1.1M178.2 185.8l-.2 1.9M179.3 186.4l-.1 1.3M179.4 185.8v.1M180 186.4h.8M180.3 185.8l-.1 1.6 .4 .3M181.4 185.8l-.1 1.6 .2 .3M182.2 187l1-.1-.1-.4a.6 .6 0 0 0-.8 .2v.9h.7M184 187.5l-.1 .2-.1-.1 .2-.1-.1 .2M184.1 186.5v.2M186.3 187.7l.2-1.9 .5 1.3 .9-1.3-.3 1.9M188.7 186.5h.7v1.2"/>
<path d="M189.5 186.9h-.7l-.3 .3v.2l.2 .3 .7-.1M190.4 186.4l-.1 1.3M190.5 185.8v.1M191.3 186.6l.1-.1a.48 .48 0 0 1 .8 .2l-.2 1M191.3 186.4v1.3M194.6 186.5h.7v1.2M195.4 186.9h-.7l-.3 .3v.2l.2 .3 .7-.1M196.3 186.4l-.1 1.3M196.9 186.4l-.4 .1-.2 .3M198.4 186.5a.65 .65 0 0 0-1 .3v.7a.64 .64 0 0 0 .9 .1M199.2 186.6l.1-.1a.48 .48 0 0 1 .8 .2l-.2 1M199.3 185.8l-.3 1.9"/>
<path d="M201 186.4l-.2 1.3M201.1 185.8v.1M201.7 186.4h.6M202 185.8l-.2 1.6 .4 .3M202.9 187l.9-.1v-.4l-.6-.1-.3 .3v.9h.7M205.5 186.5a.65 .65 0 0 0-1 .3v.7a.64 .64 0 0 0 .9 .1M206.1 186.4h.7M206.4 185.8l-.2 1.6 .5 .3M207.4 186.4v1.2l.5 .1 .3-.2M208.3 186.4l-.2 1.3M209.2 186.4l-.2 1.3M209.8 186.4l-.4 .1-.2 .3"/>
<path d="M210.2 187l1-.1v-.4a.6 .6 0 0 0-.9 .2v.9h.7"/>
</g>
<path d="M109 96h.6l.6 .7-.6 .6h-.6z" fill="#fff"/>
<path d="M105.4 96h.7M105.8 96v1.2M106.5 96l.8 1.2M107.3 96l-.8 1.2M107.7 96h.4l.3 .3v.7l-.2 .2h-.5zM109 96h.6l.6 .7-.6 .6h-.6z" fill="none" stroke="#805e00" stroke-width=".21"/>
<path d="M109.6 98.6h.6v1.2h-.6l-.6-.6z" fill="#fff"/>
<path d="M105.4 99.2l.6-.1v-.5l-.6-.1v1.2M105.6 99.2l.4 .5M106.5 98.5l.8 1.2M107.3 98.5l-.8 1.2M107.7 98.5h.4l.3 .3v.6l-.2 .3h-.5zM109.6 98.6h.6v1.2h-.6l-.6-.6z" fill="none" stroke="#805e00" stroke-width=".21"/>
<path d="M109 103.5h.6l.6 .6-.6 .6h-.6z" fill="#fff"/>
<path d="M105.2 103.5l-.4-.1-.3 .3 .1 .2 .6 .3v.3l-.2 .2-.5-.1M105.5 103.4h.8M106 103.4v1.3M106.7 104l.6-.1v-.3l-.2-.2h-.4v1.3l.6-.1 .1-.3-.3-.3M107.7 103.4l.5 .7 .4-.7M108.2 104.1v.6M109 103.5h.6l.6 .6-.6 .6h-.6z" fill="none" stroke="#805e00" stroke-width=".21"/>
<path d="M109 69h.6l.6 .5-.6 .7h-.6z" fill="#fff"/>
<path d="M104.9 68.9l.5 1.2 .4-1.2M105.9 70.2h.9M107.1 68.9v1.2M107.9 68.9h.3l.2 .2v.9l-.2 .1-.6-.1v-.9zM109 69h.6l.6 .5-.6 .7h-.6z" fill="none" stroke="#805e00" stroke-width=".21"/>
<path d="M110.7 73.8h4M110.7 75.2h4" fill="none" stroke="#980000" stroke-width=".51"/>
<g fill="none" stroke="#980000" stroke-width=".21">
<path d="M112.6 79.5v1.1h1.3l-1.3 1.3-1.1-1.3h1.1M112.6 79.5h.1M112.6 70.8v2.7M112.6 75.5v2.7M128.7 75.7v1.3M116.4 96.7h2.4M116.4 99.2h2.4M118.8 90.5h14.8v14.9h-14.8zM123.7 88.1v2.4M128.7 81.9v1.3M128.7 88.1v2.4M133.6 96.7h2.5"/>
<path d="M133.6 99.2h2.5M116.4 104.1h2.4M126.2 109v1.3h1.3l-1.3 1.2-1.2-1.2h1.2M126.2 109h.1M126.2 105.4v2.4"/>
</g>
<path d="M127.8 77h1.9v5h-1.9z" fill="none" stroke="#980000" stroke-width=".25"/>
<path d="M117.2 95.5h.2l.2-.4v1.3M117.2 96.4h.8M117.6 97.6l-.4 .8h.8M117.8 98v.8M122.2 89v.6l.6 .1-.2-.5 .3-.3h.3l.2 .2-.1 .6M127.1 89.7v-.8l.5 .5 .2-.5h.3l.3 .3v.3l-.2 .2M134.4 95.1h.8l-.5 1.3M135.1 97.6a.72 .72 0 0 0-.6 .5 .72 .72 0 0 0 .2 .7h.5a.42 .42 0 0 0-.1-.6 .42 .42 0 0 0-.5 0l-.1 .1M117.5 103.1l-.3-.4 .2-.1h.4l.2 .2-.8 .5 .3 .5h.2l.3-.3-.3-.4M125.9 106.2v.8l-.9-.8-.3 .3 .1 .4" fill="none" stroke="#bd0000" stroke-width=".21"/>
<g fill="none" stroke="#007170" stroke-width=".21">
<path d="M119.7 96h.6M119.8 99.2h.5l.3-.3-.1-.3-.7-.1v1.2M120 96v1.2M120.2 99.2l.4 .5M120.7 96l.8 1.2M120.9 98.5l.9 1.2M121.5 96l-.8 1.2M121.8 98.5l-.9 1.2M122 96a.66 .66 0 0 1 .7 .4 .66 .66 0 0 1-.2 .8h-.5zM122.3 98.5a.66 .66 0 0 1 .7 .4 .66 .66 0 0 1-.3 .8h-.4zM123.1 93.3l1.2 .4-1.2 .4M123.1 92.8h1.2"/>
<path d="M123.2 91.6a.79 .79 0 0 1 1.1 .2v.3a.86 .86 0 0 1-1.2 0zM128.1 93.8l1.1 .5-1.1 .4M128.1 96.1a.61 .61 0 0 0-.8 .3 .61 .61 0 0 0 .2 .8l.6-.1M128.1 92.7v.6a.61 .61 0 0 0 .7 .2 .61 .61 0 0 0 .4-.8M128.1 91.5v.6l.2 .1h.7a.52 .52 0 0 0 .2-.7M128.4 97.2l.4-1.2 .4 1.2M128.4 98.6h-.1a.46 .46 0 0 0-.7 .2v.6l.2 .3 .6-.1M128.6 96.9h.6M128.7 99.7l.5-1.2 .4 1.2M128.8 99.4h.6M130.3 96v1.2l-.6-1.2v1.2M130.7 98.5v1.2l-.8-1.2v1.2"/>
<path d="M130.7 97.4h.9M130.9 99.9h1M131.9 96v1.2M131.9 96.6h.7M132.2 98.5v1.2h.6M132.6 96v1.2M120.5 103.5l-.5-.1-.2 .2v.3l.7 .4-.2 .4-.5-.1M120.9 103.4h.6M121.2 103.4v1.3M122 104h.4l.2-.3-.2-.3h-.4v1.3h.5l.2-.4-.3-.3M123.1 103.4l.4 .7 .3-.7M123.5 104.1v.6"/>
<path d="M125.6 103.7v.4a.61 .61 0 0 0 .8 .3 .61 .61 0 0 0 .3-.8h-.4v.2M125.6 102.4h1.2l-1.2 .7h1.2M125.6 101.3a.66 .66 0 0 1 .8-.2 .66 .66 0 0 1 .4 .7h-1.2z"/>
</g>
<path d="M161.3 69h.7v1.2h-.7l-.6-.7z" fill="#fff"/>
<path d="M161.3 69h.7v1.2h-.7l-.6-.7zM162.3 68.9l.5 1.2 .4-1.2M163.4 70.2h.9M165.2 69l-.5-.1-.2 .2 .1 .4 .5 .1v.5h-.6M165.7 68.9v1a.42 .42 0 0 0 .7 .2v-1.2M167 69.5h.7l.1-.4-.3-.2h-.5v1.2M168.3 69.5h.6v-.5l-.6-.1v1.2M169.5 68.9v1.2h.5M170.3 68.9l.4 .6 .4-.6M170.7 69.5v.6" fill="none" stroke="#805e00" stroke-width=".21"/>
<path d="M144.7 70.8v2.7M144.7 75.5v2.7M155.8 70.8v2.7M155.8 75.5v2.7M144.7 81.9v1.3h1.2l-1.2 1.2-1.2-1.2h1.2M144.7 81.9h.1" fill="none" stroke="#980000" stroke-width=".21"/>
<path d="M142.8 73.8h3.9M142.8 75.2h3.9M153.9 73.8h3.9M153.9 75.2h3.9" fill="none" stroke="#980000" stroke-width=".51"/>
<path d="M179.3 86.8l.6-.6 .6 .6-.6 .7z" fill="#fff"/>
<path d="M179.3 86.8l.6-.6 .6 .6-.6 .7zM181.7 86.3l-.2-.2a.61 .61 0 0 0-.5 .8 .61 .61 0 0 0 .7 .4M182.1 87.4l.4-1.3 .4 1.3M182.2 87.1h.6M184 86.1v1.3l-.7-1.3v1.3M184.4 87.5h.9M185.5 86.1v1.3M185.5 86.7h.8M186.3 86.1v1.3" fill="none" stroke="#805e00" stroke-width=".21"/>
<path d="M179.3 109l.6-.6 .6 .6-.6 .7z" fill="#fff"/>
<path d="M179.3 109l.6-.6 .6 .6-.6 .7zM181.7 108.5v-.1a.58 .58 0 0 0-.7 .6 .58 .58 0 0 0 .7 .5M182.1 109.6l.4-1.3 .4 1.3M182.2 109.3h.6M184 108.3v1.3l-.7-1.3v1.3M184.4 109.7h.9M185.5 108.3v1.3h.6" fill="none" stroke="#805e00" stroke-width=".21"/>
<g fill="none" stroke="#00a200" stroke-width=".21">
<path d="M110.2 69.5h13.5v18.6M112.6 69.5v1.3M112.6 78.2v1.3M144.7 69.5v1.3M144.7 78.2v3.7M155.8 78.2v2.4h-11.1M155.8 69.5v1.3M160.7 69.5h-32v6.2M110.2 96.7h6.2M110.2 99.2h6.2M128.7 83.2v4.9M136.1 99.2h13.5v9.8h29.7"/>
<path d="M179.3 86.8h-29.7v9.9h-13.5M110.2 104.1h6.2M126.2 107.8v1.2"/>
</g>
<g fill="none" stroke="#001dcd" stroke-width=".21">
<path d="M131.7 62.1l.3-.1a.78 .78 0 0 1-.1 1.3l-.3-.3zM132.8 62.7h.5l.3-.3-.1-.3-.7-.1v1.3M133.1 62.7l.5 .6M135 62.4v.9M135.3 62.4l-.3 .3M135.7 62.9l.6-.2v-.2l-.5-.1-.1 .2 .1 .6h.5M137.2 62.5l-.3-.1-.1 .2 .1 .3h.3v.3h-.4M137.8 62v.1M137.8 62.4v.9M138.8 62.5h-.4v.3l.4 .1 .1 .1-.2 .3-.3-.1M139.2 62.4h.5M139.4 62v1l.3 .3"/>
<path d="M140.1 62.5h.6v.6l-.2 .2-.4-.2zM141.3 62.4v.9M141.6 62.4l-.3 .1v.2M143 62.5l.3-.1 .2 .2v.7M143.5 62.7l-.6 .2 .1 .4 .5-.1M144.6 62.5l-.4-.1-.2 .3 .1 .5h.5M144.6 62v1.3M145.7 62.5l-.4-.1-.2 .3v.3l.2 .3 .4-.1M145.7 62v1.3M146.2 62.9l.6-.2v-.2h-.5l-.1 .5a.36 .36 0 0 0 .6 .2M147.9 62.5a.36 .36 0 0 0-.6 .2l.1 .5h.5M147.9 62v1.3"/>
<path d="M149.2 62.4h.4M149.6 62l-.2 .2v1.1M150.1 62.5h.5v.7l-.4 .1-.1-.2zM151.2 62.4v.9M151.6 62.4l-.4 .3M153.5 62.5h-.6v.6l.2 .2 .4-.1M154 62.5h.5v.7l-.4 .1-.2-.3zM155.1 62.5h.5v.8M155.1 62.4v.9M156.1 62.4l.2 .9 .4-.9M157.1 62.9l.6-.2-.2-.3-.4 .1v.7h.5M158.2 62.5l.3-.1 .2 .2v.7"/>
<path d="M158.2 62.4v.9M159.3 62v.1M159.3 62.4v.9M159.8 62.9l.6-.2v-.2l-.4-.1-.2 .2 .1 .6h.5M160.9 62.5l.4-.1 .2 .2v.7M160.9 62.4v.9M162.6 62.5l-.3-.1-.3 .3 .1 .5h.5M163 62.9l.6-.2v-.2h-.5l-.1 .5a.36 .36 0 0 0 .6 .2M165.1 62.5l.4-.1 .1 .2v.7M165.6 62.7l-.5 .2 .1 .4 .4-.1M166.2 62.5l.4-.1 .1 .2v.7M166.2 62.4v.9"/>
<path d="M167.8 62.5l-.3-.1-.2 .3v.3l.2 .3 .3-.1M167.8 62v1.3M169.4 62.5h.6v.6l-.3 .2-.3-.1M169.4 62.4v1.2M170.6 62v.1M170.6 62.4v.9M171.1 62.5l.4-.1 .2 .2v.7M171.1 62.4v.9M172.2 62.8h1M174.3 62.5a.36 .36 0 0 0-.6 .2l.1 .5h.5M174.8 62.5h.5v.7l-.3 .1-.3-.3zM175.9 62.5l.3-.1 .3 .2v.7"/>
<path d="M175.9 62.4v.9M176.5 62.6l.2-.2 .3 .2v.7M177.6 62.5l.3-.1 .3 .3v.3l-.3 .3-.3-.1M177.6 62.4v1.2M178.7 62.5l.3-.1 .2 .2v.7M179.2 62.7l-.6 .2 .2 .4 .4-.1M179.6 62.4h.5M179.8 62v1l.3 .3M180.5 62v.1M180.5 62.4v.9M181.1 62.5h.5v.6l-.2 .2-.3-.1M181.1 62v1.3"/>
<path d="M182.2 62v.1M182.2 62.4v.9M182.7 62v1l.3 .3M183.4 62v.1M183.4 62.4v.9M183.8 62.4h.5M184 62v1l.3 .3M184.6 62.4l.3 .9M185.2 62.4l-.4 1.1-.2 .1M186.5 62.4l.2 .9 .3-.6 .2 .6 .2-.9M187.9 62v.1M187.9 62.4v.9"/>
<path d="M188.3 62.4h.5M188.5 62v1.2l.3 .1M189.2 62.5h.5v.8M189.2 62v1.3M191.2 62.5h.6l-.1 .7-.3 .1-.2-.2zM192.1 62.4h.6M192.3 62v1l.4 .3M193.1 62.5l.3-.1 .2 .2v.7M193.1 62v1.3M194.1 62.9l.6-.2-.2-.3-.4 .2v.4l.2 .3 .3-.1M195.2 62.4v.9M195.6 62.4l-.4 .3"/>
<path d="M196.7 62.4h.5M197 62v1.2l.2 .1M197.6 62.4v.9M198 62.4l-.4 .3M198.4 62.5l.3-.1 .2 .2v.7M198.9 62.7l-.6 .2 .2 .4 .4-.1M199.5 62.5h.5v.8M199.5 62.4v.9M201 62.5h-.4v.3l.4 .1 .1 .1-.1 .3-.4-.1M202.1 62.5l-.3-.1-.3 .3v.3l.3 .3 .3-.1M202.6 62.9l.6-.2-.1-.3-.5 .1v.7h.6M203.7 62v.1"/>
<path d="M203.7 62.4v.9M204.3 62.4l.2 .9 .3-.9M205.2 62.9l.6-.2v-.2l-.4-.1-.2 .2 .2 .7 .4-.1M206.3 62.4v.9M206.7 62.4l-.4 .3M207.5 62.5h-.5v.3l.5 .1 .1 .1-.2 .3-.4-.1M208.1 63.1v.2M101.5 108.5h.6v-.5l-.6-.1v1.2M102.6 105.9v1.2M102.7 108.3v.8l.5-.1M103.2 106.5l.1-.2 .4 .2v.6M103.2 106.3v.8"/>
<path d="M103.2 108.3v.8M103.8 107.9v1l.2 .2M104.1 106.3h.4M104.3 105.9v1.2h.2M104.5 107.9v1.2h.2M104.9 106.7l.5-.1v-.2l-.4-.1-.1 .2v.5l.1 .1h.4M106 107.9v1l.2 .2M106 106.3v.8M106.4 106.3l-.4 .2M106.6 108.5l.2-.2h.3l.2 .2v.4l-.2 .2h-.3l-.2-.2zM106.8 106.5l.2-.2 .3 .2v.6M106.8 106.3v.8"/>
<path d="M107.7 108.3l.2 .8 .3-.6 .2 .6 .3-.8M107.9 106.4l.3-.1 .2 .2v.6M108.4 106.6h-.4l-.2 .2 .2 .3h.4M109 105.9v1.1l.2 .1M109.8 108.3h.6M110 107.9v1l.1 .2h.3M110.6 106.4l.4-.1 .2 .2v.4l-.2 .2h-.4M110.6 106.3v1.3M110.8 108.3h.4l.2 .2v.4l-.2 .2h-.4zM111.7 106.3v.7l.2 .1 .3-.1M112.2 106.3v.8M112.7 108.7l.6-.1v-.3h-.5l-.1 .2 .1 .6h.5"/>
<path d="M112.8 105.9v1.1l.2 .1M113.5 105.9v1.2h.2M113.8 108.4l.5-.1 .1 .8M113.8 108.3v.8M114.1 106.6h.9M115 108.3h.4l.1 .2v.6h-.5v-.4l.5-.1M115.6 106.3v.7l.2 .1 .4-.1M116.1 107.9v1.2h.4l.2-.2v-.4l-.2-.2h-.4M116.2 106.3v.8M116.7 106.4l.4-.1 .2 .2v.5l-.2 .1h-.4M116.7 106.3v1.3M117.2 107.9v1l.2 .2"/>
<path d="M117.8 108.7l.6-.1-.1-.3h-.4l-.1 .2 .1 .6h.4M117.9 107v.1M118.9 109v.1M118.9 107.9v.8"/>
</g>
<g fill="#00a200">
<circle cx="112.6" cy="69.5" r=".47"/>
<circle cx="144.7" cy="69.5" r=".47"/>
<circle cx="144.7" cy="80.6" r=".47"/>
<circle cx="155.8" cy="69.5" r=".47"/>
</g>
<g fill="none" stroke="#970091" stroke-width=".21">
<path d="M117.4 76.3h-.6l-.1 .6 .2-.2h.3l.2 .2v.5h-.7M118 76.4l.3-.1a.86 .86 0 0 1 .1 1.2l-.4-.1zM118.9 76.3l.4 1.2 .5-1.2M149.4 76.3h-.6v.6l.2-.2 .4 .1v.7l-.6-.1M150.1 76.4l.2-.1a.84 .84 0 0 1 .2 1.2h-.3a.78 .78 0 0 1-.1-1.1zM151 76.3l.4 1.2 .4-1.2M159.9 76.7l.3-.4v1.2M159.9 77.5h.7M161.2 76.4l.2-.1a.84 .84 0 0 1 .2 1.2h-.4a.78 .78 0 0 1 0-1.1zM162.1 76.3l.4 1.2 .4-1.2M131.5 81.6l.4-.4v1.3M131.5 82.5h.7"/>
<path d="M132.7 81.3l.4-.1 .3 .4-.8 .9h.8M134.5 81.2h-.6l-.1 .6 .6-.1 .2 .2v.3l-.3 .3-.5-.2M135.1 81.7h.5v.8M135.1 81.7v.8M135.6 81.8l.2-.1h.3v.8M136.6 81.2l.3 1.3 .2-.9 .3 .9 .3-1.3"/>
</g>
<g fill="none" stroke="#007170" stroke-width=".21">
<path d="M116.7 74.2l.3-.3v1.2M116.7 75.1h.7M117.5 71.5l-.5-.1a.61 .61 0 0 0-.3 .8 .61 .61 0 0 0 .8 .3M118 74h.5l.1 .6-.2 .5-.4-.1zM118.2 71.3l-.2 .9h.7M118.5 71.7v.9M119.1 74l.1-.1 .5 .1 .1 .6-.2 .5h-.4l-.1-.2zM119.1 71.7l.4-.3v1.2M119.1 72.6h.7M120.3 74.4l.5-.1 .1 .8M120.3 74.3v.8M131.5 76.9h.6l.2-.2-.1-.3-.7-.1v1.2"/>
<path d="M131.6 78.9l.3-.1a.78 .78 0 0 1-.1 1.2l-.3-.2zM131.9 76.9l.4 .6M132.7 79.5h.5l.3-.3-.1-.3-.7-.1v1.2M132.7 76.3h.8l-.5 1.2M133 79.5l.5 .5M134.5 76.3l-.4 .1a.94 .94 0 0 0 0 1.1l.5-.1v-.5l-.5-.2-.2 .3M148.8 74.2l.3-.3v1.2M148.8 75.1h.7M149.6 71.5l-.6-.1-.2 .3v.6a.52 .52 0 0 0 .8 .2M150 74l.2-.1h.3l.2 .4-.2 .8h-.3a.82 .82 0 0 1-.2-1.1zM150.3 71.3l-.3 .9h.7M150.6 71.7v.9"/>
<path d="M151.2 71.5l.6-.1v.5l-.7 .7h.7M151.3 73.9h.4l.1 .1v.6l-.1 .5h-.4l-.1-.2-.1-.6zM152.4 74.4l.4-.1 .1 .8M152.4 74.3v.8M159.9 74l.6-.1 .1 .3-.8 .9h.8M160.6 71.5l-.5-.1-.2 .3v.6a.52 .52 0 0 0 .7 .2M161 74l.6-.1 .2 .1-.1 .4-.7 .7h.8M161.4 71.3l-.3 .9h.7M161.7 71.7v.9M162.2 71.4h.7l-.3 .4 .3 .2v.5h-.7M162.3 74.3v.8l.5-.1M162.8 74.3v.8"/>
<path d="M114.2 81.3l-.1-.1a.64 .64 0 0 0-.6 .6 .64 .64 0 0 0 .5 .7l.3-.2v-.4h-.3M115.5 81.2v1.3l-.7-1.3v1.3M116 81.2a.65 .65 0 0 1 .8 .7 .65 .65 0 0 1-.8 .6zM146.3 83.8l-.4-.1-.3 .3v.6l.1 .3 .4 .1 .2-.2v-.4h-.2M147.5 83.7v1.3l-.7-1.3v1.3M148.1 83.7l.5 .1 .2 .2v.6l-.3 .4h-.4zM127.7 110.9h-.4a.61 .61 0 0 0-.3 .8 .61 .61 0 0 0 .8 .3v-.5h-.3M129.1 110.9v1.2l-.8-1.2v1.2M129.7 110.9h.4a.66 .66 0 0 1 .2 .7 .66 .66 0 0 1-.6 .5zM135.1 104.7l.4-1.3 .4 1.3M135.2 104.3h.6M135.2 101v1.2"/>
<path d="M136.1 103.4h.8M136.5 101h-.1a.64 .64 0 0 0-.6 .6 .64 .64 0 0 0 .6 .6l.1-.1M136.5 103.4v1.3M136.9 101h.9l-.5 1.2M137.1 104.7l.4-1.3 .4 1.3M137.2 104.3h.6M138.8 103.4l-.3 .1-.2 .3-.1 .6 .3 .3h.2l.3-.3-.2-.5h-.4l-.2 .3M140.1 103.4h-.6l-.1 .6 .6-.1 .2 .5-.3 .3h-.3l-.2-.2M141.2 103.4l-.4 .2-.2 .8 .2 .3h.3l.2-.3-.1-.5h-.4l-.2 .3M141.8 103.8l.3-.4v1.3M141.8 104.7h.6"/>
</g>
<g fill="#c9c9c9">
<path d="M136.1 99.2l1.2 .2-.6 .2 1.3 .8-.6 .1-.1 .5-.8-1.2-.2 .6z"/>
<path d="M136.1 96.7l1.2 .1-.6 .3 1.3 .7-.6 .2-.1 .6-.8-1.3-.2 .5z"/>
</g>
</svg>
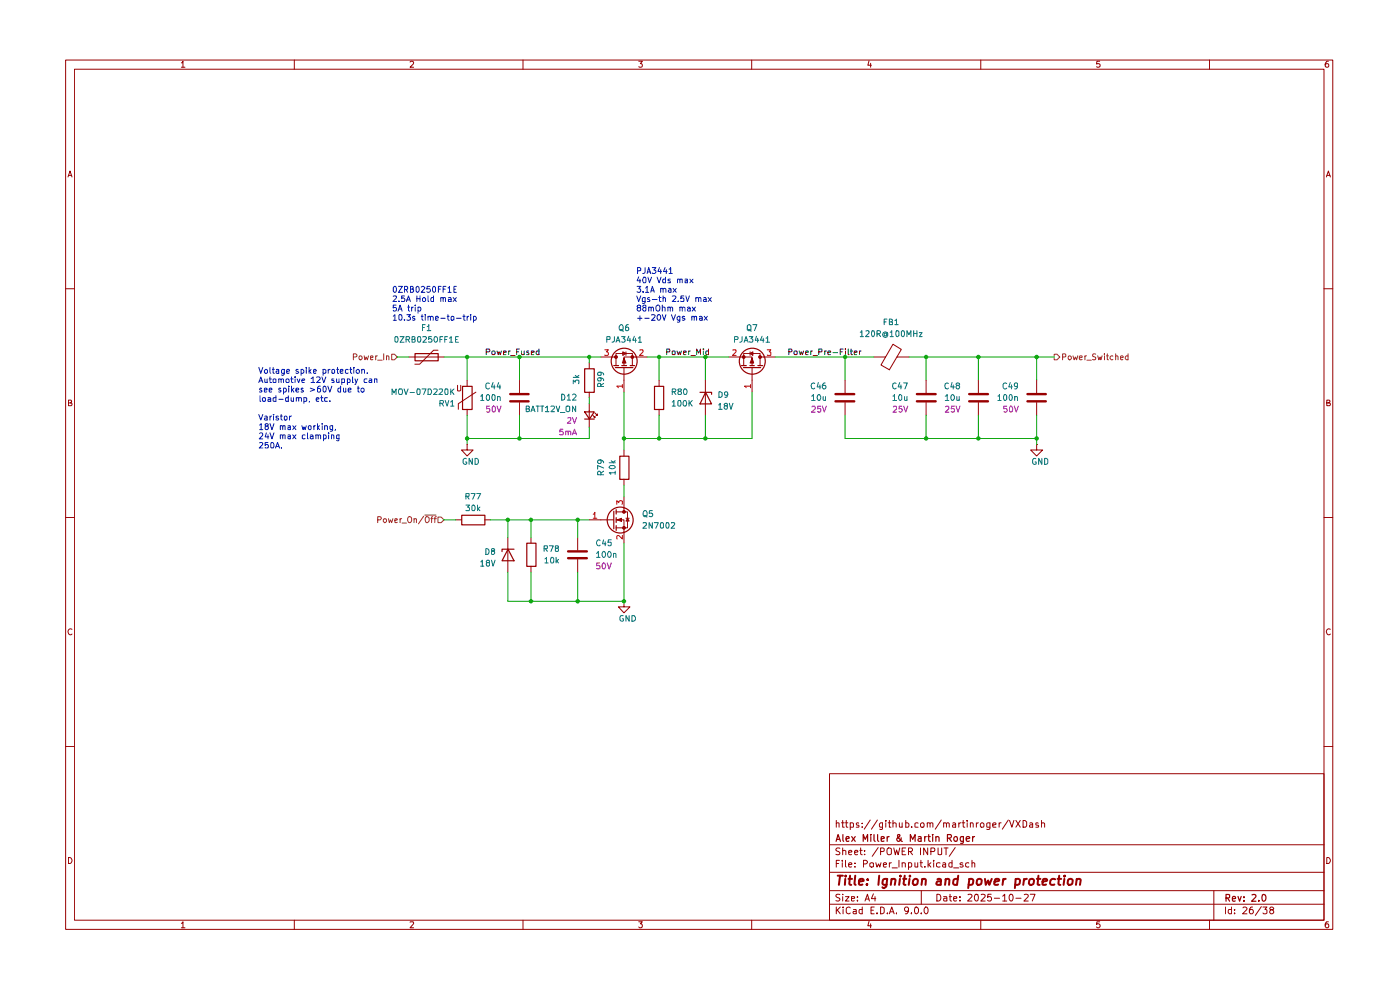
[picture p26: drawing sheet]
<svg xmlns="http://www.w3.org/2000/svg" width="297mm" height="210mm" viewBox="0 0 297 210" stroke-linecap="round" stroke-linejoin="round" font-family="sans-serif">
<g fill="none" stroke="#980000" stroke-width=".21">
<path d="M13.9 12.7h268.8v184.4h-268.8zM15.8 14.7h265.1v180.5h-265.1zM38.5 13.3h.1l.2-.3v1.3M38.5 14.3h.7M62.4 12.7v2M87 13.2l.5-.2 .3 .2-.1 .4-.7 .7h.8M111 12.7v2M135.5 13h.8l-.5 .5 .4 .1v.6h-.7M159.5 12.7v2M184.4 12.9l-.3 .9h.8M184.7 13.4v.9M208.1 12.7v2"/>
<path d="M233.3 13h-.6l-.1 .6h.7v.6h-.7M256.6 12.7v2M281.8 13a.71 .71 0 0 0-.7 .5 .71 .71 0 0 0 .3 .8l.4-.1v-.6l-.4-.1-.3 .3M14.4 37.5l.5-1.2 .4 1.2M14.5 37.2h.7M281.4 37.5l.4-1.2 .4 1.2M281.5 37.2h.6M13.9 61.3h1.9M280.9 61.3h1.8M14.5 85.5h.4l.3-.3-.2-.3h-.5v1.2h.6l.2-.5-.4-.1M281.5 85.5h.4l.2-.3-.1-.3h-.5v1.2h.6l.1-.5-.3-.1M13.9 109.8h1.9"/>
<path d="M280.9 109.8h1.8M15.3 133.5a.59 .59 0 0 0-.9 .5 .59 .59 0 0 0 .8 .6l.1-.1M282.2 133.5a.59 .59 0 0 0-.8 .5 .59 .59 0 0 0 .7 .6l.1-.1M13.9 158.4h1.9M280.9 158.4h1.8M176 164.1h104.9v31.1h-104.9zM176 179.2h104.9M177.4 174.7l.2-.2 .4 .1v.9M177.4 174v1.5M178.2 180l-.6-.1-.3 .2 .1 .4 .8 .4-.1 .3h-.8M178.5 174.5h.6M178.8 174v1.5h.3"/>
<path d="M178.8 179.9v1.4M179.4 174.5h.5M179.5 174v1.3l.1 .2h.3M180.4 174.6l.4-.1 .3 .2v.7l-.7 .1M180.4 174.5v1.5M182.2 174.6l-.4-.1-.2 .2 .2 .3h.4v.5h-.6M182.6 179.9v1.2l.3 .2M182.9 175.4v.1M182.9 174.6v.1M184.6 173.9l-1.3 2M186.1 173.9l-1.2 2M186.3 179.8l-1.3 1.8"/>
<path d="M187.2 174.5v1.2a.36 .36 0 0 1-.6 .2M187.2 174.6l-.4-.1-.2 .3v.6l.6 .1M187.9 174v.2M187.9 174.5v1M188.4 174.5h.6M188.7 174v1.5h.3M189.4 174.7l.3-.2 .4 .2v.8M189.4 174v1.5M189.6 179.9l.3 1.4 .3-1 .3 1 .4-1.4M190.8 174.5l.1 1 .5-.1M191.4 174.5v1M192.1 179.9h-.7v1.4h.7"/>
<path d="M192.1 174v1.5l.6-.1 .1-.6a.45 .45 0 0 0-.7-.2M193.4 175.4v.1M194.8 174.6l-.5-.1-.2 .2v.7l.7 .1M195.3 174.8a.45 .45 0 0 1 .7-.2v.9l-.6-.1zM195.3 179.9v1.4M196.7 174.7l.2-.2 .4 .2v.8M196.7 174.5v1M196.8 179.9v1.4l-.8-1.4v1.4M197.3 174.7l.2-.2 .4 .1v.9M199 179.9v1.3l.3 .1 .5-.1v-1.3M199.7 173.9l-1.3 2M200.2 174.7l.2-.2 .4 .2v.8"/>
<path d="M200.2 174.5v1M200.3 179.9h.8M200.7 179.9v1.4M200.8 174.7l.2-.2 .4 .2v.8M202.1 174.6l.4-.1 .2 .2v.8h-.6v-.4l.6-.2M202.6 179.8l-1.2 1.8M203.4 174.5v1M203.8 174.5l-.4 .3M204.1 174.5h.6M204.3 174v1.3l.1 .2h.3M205.2 174v.2M205.2 174.5v1"/>
<path d="M205.9 174.7l.1-.2 .5 .2v.8M205.9 174.5v1M207.1 174.5v1M207.6 174.5l-.5 .3M208.2 174.5h.3l.2 .3-.1 .7h-.5l-.1-.3v-.4zM210 174.5v1.2l-.2 .3-.5-.1M210 174.6l-.4-.1-.3 .2v.7l.7 .1M210.6 175l.7-.1v-.3l-.4-.1-.3 .2 .1 .8h.6M212 174.5v1M212.4 174.5l-.4 .3M213.9 173.9l-1.3 2M214.2 174l.5 1.5 .4-1.5"/>
<path d="M215.5 174l.9 1.5M216.4 174l-.9 1.5M217 174h.4l.4 .4v.7l-.3 .4h-.5zM218.5 174.6l.4-.1 .2 .2v.8h-.6l-.1-.4 .7-.2M220.3 174.6h-.6v.4h.6v.2v.3h-.6M220.9 174.7l.3-.2 .4 .2v.8M220.9 174v1.5M14.5 181.9a.65 .65 0 0 1 .8 .6 .65 .65 0 0 1-.8 .7zM38.5 195.9l.3-.4v1.3M38.5 196.8h.7M62.4 195.2v1.9M87 195.6l.7-.1 .1 .3-.8 1h.8"/>
<path d="M111 195.2v1.9M135.5 195.5h.8l-.5 .5 .5 .2-.1 .5-.5 .1-.2-.2M159.5 195.2v1.9M176 191.8h104.9M176 188.9h104.9M176 185h104.9M177.4 192.4v1.4M177.4 183.2h.5M177.6 193l.7 .8M178.1 182.5h-.7v1.4M178.2 189.8h-.8l-.1 .3 .8 .4 .1 .4-.3 .2-.6-.1M178.3 192.4l-.9 .8"/>
<path d="M178.7 182.5v.2M178.7 183v.9M178.8 189.7v.1M178.8 180.5l.4-.1 .2 .1v.8M178.8 190.2v.9M178.9 192.4v.2M178.9 192.9v.9M179.4 190.2h.7l-.7 .9h.7M179.4 182.5v1.3l.1 .1M180 183.4l.7-.1-.2-.3-.5 .2v.6l.3 .1 .3-.1M180 180.8l.7-.1-.2-.3-.5 .1v.6l.3 .2 .3-.1M180.4 192.6l-.4-.2-.5 .3 .1 1 .4 .1 .4-.1"/>
<path d="M180.6 190.6l.7-.1-.1-.3h-.6v.8h.6M181.1 192.9h.5v.9M181.3 180.8l.7-.1-.2-.3h-.3l-.2 .1v.6l.2 .2 .4-.1M181.4 183.8v.1M181.4 183.1v.1M181.6 193.2l-.5 .1-.1 .2 .1 .3h.5M181.9 191v.1M181.9 190.2v.2M182.4 180.4h.5M182.9 192.9h-.5l-.2 .7a.45 .45 0 0 0 .7 .2M182.9 192.4v1.4M183.2 183.3l.6-.1 .2-.5-.3-.2h-.5v1.4"/>
<path d="M183.4 181.2v.1M183.4 180.5h.1M183.5 191.1l.5-1.4 .4 1.4M183.7 190.7h.7M184.4 195.4l-.3 1h.8M184.6 183.1h.7v.7h-.7zM184.7 196v.8M184.8 193.1h.5M185.3 189.6l-.4 1h.9M185.5 192.4h-.7v1.4h.7M185.6 190.2v.9M185.8 183l.2 .9 .4-.6 .2 .6 .3-.9"/>
<path d="M186 193.7v.1M186.8 192.4h.4l.4 .3v.8l-.4 .3h-.4zM186.8 180.6l.7-.1 .1-.5-.3-.1h-.5v1.4M187.4 183.4l.7-.1-.2-.3h-.3l-.2 .2v.6l.2 .1 .4-.1M188.3 193.7v.1M188.3 180l.2-.1 .6 .1v1.1l-.3 .2-.5-.2zM188.7 193.8l.5-1.4 .5 1.4M188.7 183v.9M188.8 193.4h.7M189.1 183l-.4 .3M189.3 184.1h1.1M190.2 193.7v.1"/>
<path d="M190.7 182.5v1.4M191.4 183.1l.4-.1 .3 .2v.7M191.4 183v.9M191.4 180.5h.5M192.7 193l-.2 .3h-.4l-.2-.3v-.3l.2-.3h.4l.2 .3v.8l-.2 .3h-.4M192.7 183.1l.5-.1 .2 .3-.1 .5h-.6M192.7 180.6h.6l.3-.2v-.3l-.3-.2h-.6v1.4M192.7 183v1.4M193.1 180.6l.5 .7M193.3 193.7v.1M194.1 192.6l.2-.2a.75 .75 0 0 1 .6 .7 .75 .75 0 0 1-.6 .7l-.2-.1-.1-.4zM194.1 183v.8h.6"/>
<path d="M194.7 183v.9M195.2 183h.5M195.4 182.5v1.3l.3 .1M195.4 193.7v.1M195.4 188.9v2.9M196.2 183.8v.1M196.4 192.4h.1a.8 .8 0 0 1 .4 .8 .8 .8 0 0 1-.5 .6 .89 .89 0 0 1 0-1.4zM196.9 182.5v1.4M197.1 183.4l.4 .5M197.5 180.6l.7-.1v-.5l-.7-.1v1.4M197.5 183l-.6 .5M198.1 182.5v.2"/>
<path d="M198.1 183v.9M198.7 189.7a.73 .73 0 0 1 .9 .7 .73 .73 0 0 1-.9 .7zM199.4 183.1l-.4-.1-.3 .3v.5h.7M200 183.1l.4-.1 .2 .2v.7M200.2 190.2h.6l.1 .9M200.6 183.3l-.6 .1-.1 .2 .3 .3 .4-.1M200.9 190.5l-.7 .1v.4h.7M201.4 190.2h.5M201.5 189.7v1.3l.4 .1M202 183.1l-.5-.1-.2 .3 .1 .5h.6M202 182.5v1.4M202.3 190.6l.7-.1-.1-.3h-.5l-.1 .2v.6l.2 .1 .4-.1"/>
<path d="M202.3 184.1h1.1M203.7 191v.1M203.7 190.2v.2M204.3 183.1l-.4-.1-.2 .3v.1l.6 .1v.3l-.2 .1-.4-.1M205.4 189.8l.5-.1 .3 .4-.9 1h.9M205.5 183.1l-.3-.1-.4 .3 .1 .5h.6M206.2 183.1l.4-.1 .2 .2v.7M206.2 182.5v1.4M206.9 189.8h.5a1.01 1.01 0 0 1-.2 1.3 .87 .87 0 0 1-.3-1.3zM208.1 195.2v1.9M208.1 189.8h.8l.1 .3-.9 1h.9M210.3 189.7h-.7l-.1 .7 .6-.2 .2 .3v.4l-.2 .2-.6-.1"/>
<path d="M210.9 190.5h1.1M212.7 190.1l.4-.4v1.4M212.7 191.1h.9M214.2 189.8l.2-.1a.76 .76 0 0 1 .5 .7 .76 .76 0 0 1-.5 .7 1.01 1.01 0 0 1-.2-1.3zM215.5 190.5h1.1M217.3 189.8h.8v.3l-.9 1h.9M218.6 189.7h1l-.6 1.4M233.3 195.5h-.6l-.1 .6 .2-.1h.3l.3 .2v.3l-.3 .3h-.3l-.2-.2M256.6 195.2v1.9M257.5 188.9v6.3M260 192.4v1.4M261.2 192.9h-.5l-.1 .3v.4l.2 .2h.4"/>
<path d="M261.2 192.4v1.4M261.9 193.7v.1M261.9 192.9v.2M263.7 192.6l.2-.2h.3l.3 .4-.9 1h.9M265.7 192.4l-.4 .1-.2 .2-.1 .9 .3 .2h.3l.3-.2v-.4l-.3-.3h-.3l-.3 .3M267.6 192.3l-1.3 1.9M267.9 192.4h.9l-.5 .5 .5 .2v.6l-.3 .1h-.4l-.2-.1M269.6 193l-.2-.3 .2-.3 .6 .3-.1 .2-.2 .1a.47 .47 0 0 0-.5 .6l.2 .2a.45 .45 0 0 0 .5-.1 .45 .45 0 0 0 0-.5l-.2-.2M281.5 181.9a.65 .65 0 0 1 .7 .6 .65 .65 0 0 1-.7 .7zM281.8 195.5h-.4l-.3 .5v.5l.3 .3 .4-.1v-.7h-.4l-.3 .2"/>
</g>
<g fill="none" stroke="#980000" stroke-width=".25">
<path d="M177.4 178.5l.4-1.5 .5 1.5M177.5 178h.6M178.8 177v1.2l.2 .3M179.5 178l.7-.2-.2-.3h-.4l-.1 .7 .2 .3 .4-.1M180.7 177.5l.7 1M181.4 177.5l-.7 1M183.1 178.5v-1.5l.5 1 .5-1v1.5M184.7 177v.1M184.7 177.5v1M185.4 177v1.2l.3 .3M186.2 177v1.2l.2 .3M186.9 178l.7-.2-.1-.3h-.6v.9h.6"/>
<path d="M188.2 177.5v1M188.6 177.5l-.4 .3M191.2 177.7v.3l-.5 .5a.43 .43 0 0 1-.4-.2 .43 .43 0 0 1 0-.5l.6-.5-.1-.3h-.3a.55 .55 0 0 0 .2 .8l.7 .7M193.1 178.5v-1.5l.5 1 .5-1v1.5M194.8 177.5h.6v1M195.4 177.8l-.4 .1-.3 .2 .3 .4 .4-.1M196.2 177.5v1M196.5 177.5h-.2l-.1 .3M196.8 177.5h.6M197 177v1.2l.4 .3M197.9 177v.1M197.9 177.5v1"/>
<path d="M198.5 177.6l.1-.1a.36 .36 0 0 1 .6 .2v.8M198.5 177.5v1M201 177.8l.7-.1 .1-.2v-.4l-.8-.1v1.5M201.3 177.8l.5 .7M204.4 177.5v1.1l-.2 .3h-.4M204.4 177.5h-.4l-.3 .3 .1 .6h.6M205 178l.7-.2-.1-.3h-.4l-.2 .2 .1 .7h.5M206.3 177.5v1M206.8 177.5l-.5 .3M260.1 190.5l.7-.1 .1-.6-.8-.1v1.5M260.4 190.5l.5 .7M261.4 190.7l.7-.1-.1-.4h-.5l-.1 .7 .2 .3 .4-.1"/>
<path d="M262.6 190.2l.4 1 .3-1M263.9 191v.2M263.9 190.2v.2M265.6 189.8l.6-.1 .2 .5-.9 1h.9M267 191v.2M267.8 189.8l.2-.1a.75 .75 0 0 1 .6 .8 .75 .75 0 0 1-.6 .7l-.2-.2-.1-.4z"/>
<circle cx="202.7" cy="178" r=".48"/>
</g>
<g fill="none" stroke="#980000" stroke-width=".42">
<path d="M177.7 185.8h1.1M178.2 185.8l-.2 1.9M179.3 186.4l-.1 1.3M179.4 185.8v.1M180 186.4h.8M180.3 185.8l-.1 1.6 .4 .3M181.4 185.8l-.1 1.6 .2 .3M182.2 187l1-.1-.1-.4a.6 .6 0 0 0-.8 .2v.9h.7M184 187.5l-.1 .2-.1-.1 .2-.1-.1 .2M184.1 186.5v.2M186.5 185.8l-.2 1.9M188.2 186.4l-.2 1.7a.45 .45 0 0 1-.8 .1"/>
<path d="M188.2 186.5l-.5-.1-.3 .2-.1 .9a.64 .64 0 0 0 .8 .1M189.1 186.6l.3-.2 .5 .1-.1 1.2M189.1 186.4l-.1 1.3M190.9 186.4l-.2 1.3M191 185.8v.1M191.6 186.4h.7M191.9 185.8l-.2 1.6 .4 .3M192.9 186.4l-.1 1.3M193 185.8v.1M193.7 186.8l.4-.4 .5 .2v.8l-.1 .2-.5 .1-.3-.2zM195.6 186.6l.3-.2 .4 .1v1.2M195.7 186.4l-.2 1.3"/>
<path d="M198.9 186.5h.7v1.2M199.6 186.9l-.8 .1-.2 .4 .3 .3 .7-.1M200.6 186.6l.3-.2 .4 .1v1.2M200.7 186.4l-.2 1.3M203.2 186.5l-.5-.1-.4 .4v.7l.2 .2 .5-.1M203.3 185.8l-.3 1.9M205.6 186.5a.6 .6 0 0 1 .9 .3l-.3 .8h-.7M205.6 186.4l-.2 2M207.3 186.6l.4-.2 .5 .2-.1 .9-.3 .2-.5-.2zM209 186.4l.1 1.3 .5-.9 .3 .9 .5-1.3M211 187l.9-.1v-.4h-.7l-.3 .9 .3 .3 .5-.1M212.8 186.4l-.1 1.3"/>
<path d="M213.4 186.4l-.6 .4M215.5 186.5a.6 .6 0 0 1 .9 .3l-.1 .6a.65 .65 0 0 1-.9 .2M215.5 186.4l-.2 2M217.2 186.4l-.1 1.3M217.8 186.4l-.4 .1-.2 .3M218.4 186.6l.4-.2 .5 .2-.1 .9-.3 .2-.6-.2zM220 186.4h.7M220.3 185.8l-.2 1.8 .5 .1M221.1 187l1-.1v-.4l-.6-.1-.3 .3-.1 .9h.8M223.9 186.5a.72 .72 0 0 0-1.1 .3v.7l.3 .2 .6-.1M224.4 186.4h.7M224.7 185.8l-.2 1.6 .5 .3"/>
<path d="M225.8 186.4l-.2 1.3M225.9 185.8h-.2h.3h-.1l-.1 .1M226.6 186.6l.4-.2 .5 .2-.1 .9-.3 .2-.5-.2zM228.4 186.6l.1-.1a.48 .48 0 0 1 .8 .2l-.2 1M228.4 186.4l-.1 1.3"/>
</g>
<path d="M83.1 75.1h.6l.6 .6-.6 .6h-.6z" fill="#fff"/>
<path d="M75 75.7l.6-.1 .1-.3-.2-.2h-.5v1.2M76.2 75.6l.4-.1 .2 .2v.4l-.2 .2-.4-.2zM77.3 75.5l.1 .8 .3-.6 .2 .6 .3-.8M78.6 75.9l.5-.1v-.2h-.5v.6h.5M79.7 75.5v.8M80 75.5l-.3 .2M80.1 76.4h1M81.4 75.1v1.2M82 75.6l.2-.1 .3 .1v.7M82 75.5v.8M83.1 75.1h.6l.6 .6-.6 .6h-.6z" fill="none" stroke="#805e00" stroke-width=".21"/>
<path d="M92.9 109.7h.7l.6 .6-.6 .6h-.7z" fill="#fff"/>
<g fill="none" stroke="#805e00" stroke-width=".21">
<path d="M80.1 110.3h.5l.3-.3-.1-.3-.7-.1v1.3M81.4 110.1l.3-.1 .3 .3v.3l-.3 .3-.4-.3zM82.4 110l.2 .9 .2-.6 .3 .6 .2-.9M83.8 110.4l.5-.1v-.2h-.5v.7h.5M84.9 110v.9M85.2 110l-.3 .1v.2M85.3 110.9h.9M86.6 109.8l.2-.2 .4 .1a.8 .8 0 0 1-.2 1.2h-.2a.79 .79 0 0 1-.2-1.1zM87.8 110.1h.5v.8M87.8 110v.9M89.9 109.5l-1.1 1.6M90.1 109.3h2.4"/>
<path d="M90.3 109.8l.2-.2 .5 .2a.79 .79 0 0 1-.3 1.1h-.2a.9 .9 0 0 1-.2-1.1zM91.4 110h.4M91.8 109.6l-.2 .1v1.2M92.1 110h.5M92.6 109.6l-.4 .2v1.1M92.9 109.7h.7l.6 .6-.6 .6h-.7z"/>
</g>
<g fill="none" stroke="#980000" stroke-width=".25">
<path d="M88 75h5v1.5h-5zM124 78.2h2.1v5h-2.1zM130.2 77.5h1M130.6 78h3.7M131.9 77.5h1M133.7 77.5h.9M98.1 82h2.1v4.9h-2.1zM124 87.4h2.1l-1.1 1.5zM124 88.9h2.1M138.8 82h2v4.9h-2zM98 109.3h4.9v2h-4.9z"/>
<circle cx="132.4" cy="76.6" r="2.75"/>
</g>
<g fill="none" stroke="#980000" stroke-width=".21">
<path d="M86.7 75.7h7.5M92.9 74.3h-.9l-3 3h-1M125 77v1.2M130.7 77.5v-2.5h3.4v2.5M132.4 77.9v2.7M97.1 81.7v1.2h.5l.1-.1v-1.1M99.1 94.3v1.2h1.3l-1.3 1.2-1.2-1.2h1.2M99.1 94.3h.1M99.1 80.6v1.3M99.1 86.8v1.3M101 83.2l-3.8 2.4v1.2M110.2 80.6v2.7"/>
<path d="M110.2 85.4v2.7M125 83.2v1.2M125 85.6v4.9M125.8 88.1l.4 .5v-.3v.3h-.2M126.2 87.6l.5 .5v-.3v.3h-.3M139.8 80.6v1.3M139.8 86.8v1.3M96.6 110.3h1.3M102.8 110.3h1.2"/>
</g>
<g fill="none" stroke="#0c0c0c" stroke-width=".21">
<path d="M103.2 74.6h.6l.1-.1-.1-.4-.6-.1v1.2M104.3 74.6l.2-.1h.4l.1 .1v.5l-.1 .1h-.4l-.2-.1zM105.4 74.5l.3 .7 .2-.6 .2 .6 .3-.7M106.8 74.8l.6-.1-.1-.2h-.5v.7h.5M107.9 74.5v.7M108.2 74.5h-.2l-.1 .1M108.3 75.4h1M109.6 74.6h.4M110.2 74h-.6v1.2M110.6 74.5l.1 .7 .5-.1M111.2 74.5v.7M112.1 74.5h-.3l-.1 .1 .4 .3v.3h-.4"/>
<path d="M112.7 74.8l.6-.1-.1-.2h-.5v.7h.5M114.3 74v1.2h-.4l-.2-.1v-.5l.2-.1h.4M141.4 74.6h.6v-.6h-.6v1.2M142.6 74.5h.6l-.1 .7-.5-.1zM143.6 74.5l.3 .7 .2-.6 .2 .6 .3-.7M145 74.8l.6-.1-.1-.2h-.4l-.1 .1 .1 .6h.4M146.1 74.5v.7M146.4 74.5l-.3 .1M146.6 75.4h.9M147.8 75.2v-1.2l.4 .9 .4-.9v1.2M149.2 74v.1M149.2 74.5v.7"/>
<path d="M150.3 74v1.2h-.4l-.2-.1v-.5l.2-.1h.4"/>
</g>
<path d="M108.2 85.1h3.9M108.2 83.6h3.9" fill="none" stroke="#980000" stroke-width=".51"/>
<path d="M132.4 76l.4 1h-.7z" fill="#980000"/>
<path d="M129.9 75.7h.8M132.4 76l.4 1h-.8z" fill="none" stroke="#980000" stroke-width=".21"/>
<path d="M130.5 75.5h.4v.5h-.4z" fill="#980000"/>
<path d="M130.5 75.5h.4v.5h-.4z" fill="none" stroke="#980000" stroke-width=".21"/>
<path d="M133.9 75.5h.5v.5h-.5z" fill="#980000"/>
<path d="M127.5 75.7h2.4M132.1 74.6l.7 .4-.7 .4zM132.8 74.6v.8M133.9 75.5h.5v.5h-.5zM137.3 75.7h-4.9v1.8M157.8 77.5v-2.5h3.4v2.5M159.5 77.9v2.7M132.4 80.6v2.6M149.6 80.6v7.5" fill="none" stroke="#980000" stroke-width=".21"/>
<path d="M128.3 74.2h.8l-.5 .4 .5 .3v.3l-.2 .2-.6-.1M135.8 74.3l.6-.1v.3l-.7 .9h.7M132 81.9h-1.2l.4 .3M132 81.6v.6" fill="none" stroke="#bd0000" stroke-width=".21"/>
<g fill="none" stroke="#980000" stroke-width=".25">
<path d="M157.3 77.5h1M157.7 78h3.7M159.1 77.5h.9M160.8 77.5h1M148.5 83.2h2.5v.4M149.7 83.2l1.3 2.5h-2.5z"/>
<circle cx="159.6" cy="76.6" r="2.75"/>
</g>
<path d="M159.6 76l.3 1h-.7z" fill="#980000"/>
<path d="M159.5 76l.4 1h-.8zM161.2 75.7h.8" fill="none" stroke="#980000" stroke-width=".21"/>
<path d="M161 75.5h.4v.5h-.4z" fill="#980000"/>
<path d="M161 75.5h.4v.5h-.4z" fill="none" stroke="#980000" stroke-width=".21"/>
<path d="M157.6 75.5h.4v.5h-.4z" fill="#980000"/>
<path d="M154.6 75.7h4.9v1.8M157.6 75.5h.4v.5h-.4zM159.1 75l.6-.4v.8zM159.1 74.6v.8M162 75.7h2.5M159.5 80.6v2.6M179.3 80.6v2.7M179.3 85.4v2.7M207.6 80.6v2.7M207.6 85.4v2.7" fill="none" stroke="#980000" stroke-width=".21"/>
<path d="M155.5 74.3l.6-.1 .1 .3-.8 .9h.8M162.8 74.2h.7l-.3 .4 .3 .2v.5h-.7M159.2 81.9h-1.3l.4 .3M159.2 81.6v.6" fill="none" stroke="#bd0000" stroke-width=".21"/>
<path d="M177.2 85.1h4M177.2 83.6h4M205.6 85.1h4M205.6 83.6h4" fill="none" stroke="#980000" stroke-width=".51"/>
<g fill="none" stroke="#0c0c0c" stroke-width=".21">
<path d="M167.3 74.6h.5l.2-.1-.1-.4-.6-.1v1.2M168.4 74.6l.2-.1h.4v.7h-.4l-.2-.1zM169.5 74.5l.3 .7 .2-.6 .2 .6 .3-.7M170.9 74.8l.6-.1-.1-.2h-.4l-.1 .1 .1 .6h.4M172 74.5v.7M172.3 74.5h-.2l-.1 .1M172.5 75.4h.9M173.7 74.6h.6l.1-.5-.7-.1v1.2M175 74.5v.7M175.3 74.5h-.3v.1M175.6 74.8l.6-.1-.1-.2h-.4l-.1 .1 .1 .6h.4M176.7 74.8h1"/>
<path d="M178.3 74.6h.4M178.9 74h-.6v1.2M179.4 74v.1M179.4 74.5v.7M180 74v1.2h.1M180.4 74.5h.5M180.5 74v1.1l.1 .1h.3M181.2 74.8l.6-.1-.1-.2h-.4l-.1 .1 .1 .6h.4M182.3 74.5v.7M182.7 74.5h-.3l-.1 .1"/>
</g>
<path d="M223.6 75.1h.6l.6 .6-.6 .6h-.6z" fill="#fff"/>
<g fill="none" stroke="#805e00" stroke-width=".21">
<path d="M223.6 75.1h.6l.6 .6-.6 .6h-.6zM225.4 75.7l.7-.1v-.4l-.2-.1h-.5v1.2M226.7 75.6l.3-.1 .3 .2v.4l-.3 .2-.4-.2zM227.6 75.5l.3 .8 .2-.6 .3 .6 .2-.8M229 75.9l.6-.1v-.2l-.5-.1-.1 .1v.6l.1 .1 .5-.1M230.2 75.5v.8M230.5 75.5l-.3 .2M230.6 76.4h.9M232.4 75.1h-.4l-.2 .2 .1 .3 .5 .2v.4l-.1 .1-.5-.1M232.9 75.5l.2 .8 .3-.6 .1 .6 .3-.8M234.3 75.1v.1M234.3 75.5v.8"/>
<path d="M234.7 75.5h.5M234.9 75.1v1.1l.3 .1M236.1 75.6l-.4-.1-.2 .2v.4l.2 .2 .4-.1M236.7 75.6l.1-.1 .4 .1v.7M236.7 75.1v1.2M237.7 75.9l.6-.1-.2-.3-.4 .1v.6l.2 .1 .3-.1M239.3 75.6l-.3-.1-.3 .2v.4l.3 .2 .3-.1M239.3 75.1v1.2"/>
</g>
<path d="M194.5 85.1h4M194.5 83.6h4M218 85.1h3.9M218 83.6h3.9" fill="none" stroke="#980000" stroke-width=".51"/>
<g fill="none" stroke="#980000" stroke-width=".21">
<path d="M185.4 75.7h2.4M187.8 75.7h.1M189.4 73l1.8 1.1-2.5 4.3-1.8-1zM190.3 75.7h2.5M132.4 95.5v1.2M196.5 80.6v2.7M196.5 85.4v2.7M219.9 94.3v1.2h1.3l-1.3 1.2-1.3-1.2h1.3M219.9 94.3h.1M219.9 80.6v2.7M219.9 85.4v2.7M107.7 114v7.4"/>
<path d="M112.6 114v1.2M127.5 110.3h2.7M130.7 108.6h2.4v3.4h-2.4M132.4 101.6v1.3M112.6 120.1v1.3"/>
</g>
<path d="M131.5 96.8h1.9v4.9h-1.9zM107.8 116.5l1.2 2.5h-2.5zM109 116.5h-2.5v.5M111.8 115.2h1.9v4.9h-1.9zM130.2 108.5v3.7M130.7 108.1v.9M130.7 109.8v1M130.7 111.5v1" fill="none" stroke="#980000" stroke-width=".25"/>
<path d="M130.9 110.3l1-.4v.7z" fill="#980000"/>
<path d="M130.9 110.3l1-.4v.7zM132.4 107.8v.8" fill="none" stroke="#980000" stroke-width=".21"/>
<circle cx="131.6" cy="110.3" r="2.75" fill="none" stroke="#980000" stroke-width=".25"/>
<path d="M132.2 108.4h.4v.4h-.4z" fill="#980000"/>
<path d="M132.2 108.4h.4v.4h-.4z" fill="none" stroke="#980000" stroke-width=".21"/>
<path d="M132.2 111.7h.4v.5h-.4z" fill="#980000"/>
<path d="M122.5 114v2.7M122.5 118.7v2.7M125 110.3h2.5M130.7 110.3h1.7v4.9M132.2 111.7h.4v.5h-.4zM132.4 105.4v2.4M132.8 109.9h.7M133.1 109.9l.4 .6h-.7zM132.4 127.5v1.2h1.2l-1.2 1.3-1.2-1.3h1.2M132.4 127.5h.1" fill="none" stroke="#980000" stroke-width=".21"/>
<path d="M125.9 109.1l.3-.4v1.2M125.9 109.9h.7M130.8 107v-.8l.5 .4 .2-.4 .5 .1-.1 .7M132 113.6v.7l-.8-.7-.4 .1 .1 .6" fill="none" stroke="#bd0000" stroke-width=".21"/>
<path d="M120.5 118.4h4M120.5 117h4" fill="none" stroke="#980000" stroke-width=".51"/>
<g fill="none" stroke="#00a200" stroke-width=".21">
<path d="M84.3 75.7h2.4M94.2 75.7h33.3M99.1 75.7v4.9M110.2 75.7v4.9M125 75.7v1.3M137.3 75.7h17.3M139.8 75.7v4.9M149.6 75.7v4.9M164.5 75.7h20.9M179.3 75.7v4.9M192.8 75.7h30.8M196.5 75.7v4.9"/>
<path d="M207.6 75.7v4.9M219.9 75.7v4.9M99.1 88.1v6.2M110.2 88.1v4.9M125 90.5v2.5h-25.9M125 84.4v1.2M132.4 83.2v12.3M139.8 88.1v4.9M149.6 88.1v4.9M159.5 83.2v9.8h-27.1M179.3 88.1v4.9h40.6M196.5 88.1v4.9"/>
<path d="M207.6 88.1v4.9M219.9 88.1v6.2M94.2 110.3h2.4M104 110.3h21M107.7 110.3v3.7M112.6 110.3v3.7M122.5 110.3v3.7M132.4 115.2v12.3h-24.7v-6.1M132.4 102.9v2.5M112.6 121.4v6.1M122.5 121.4v6.1"/>
</g>
<g fill="none" stroke="#001dcd" stroke-width=".21">
<path d="M135.2 57.4h.7v-.5l-.1-.1h-.6v1.2M135.5 58.7l-.3 .9h.7M135.8 59.2v.8M136.5 58.8h.4l.1 .2v.8l-.1 .2-.4-.1a.87 .87 0 0 1 0-1.1zM136.9 56.8v.9l-.2 .2-.3 .1M137.3 58l.3-1.2 .4 1.2M137.4 57.7h.6M137.5 58.8l.3 1.2 .4-1.2M138.4 56.8h.7l-.4 .5 .4 .1v.4l-.2 .2h-.3l-.2-.1M139.4 58.8l.4 1.2 .4-1.2M139.9 56.8l-.3 .8h.7M140.2 57.2v.8"/>
<path d="M141.1 56.8l-.3 .8h.7M141.2 58.8v1.2h-.5v-.8h.5M141.3 57.2v.8M141.9 57.1l.4-.3v1.2M141.9 58h.7M142.2 59.2h-.4l-.1 .2 .1 .2h.4v.4h-.5M143.7 59.3l.4-.1 .1 .8M143.7 59.2v.8M144.2 59.4l.1-.2h.4v.8M145.3 59.2h.5v.8h-.5v-.4l.5-.1M146.3 59.2l.7 .8M147 59.2l-.7 .8"/>
<path d="M54.9 77.9l.4 1.3 .4-1.3M56.1 78.6l.2-.2h.4v.7h-.5zM57.3 77.9v1.1l.1 .2M57.3 80v1l.1 .1h.2M57.8 78.4h.4M57.9 77.9v1.2l.3 .1M58.6 78.4h.5v.8M59.1 78.7h-.4l-.2 .2 .2 .3 .4-.1M60.3 78.4v1l-.2 .2-.4-.1M60.3 78.4h-.4l-.2 .1v.6h.6M60.8 78.8l.6-.1-.1-.3h-.5v.7h.5M61.8 80v1l.1 .1h.3"/>
<path d="M62.6 80h.1M63.3 78.4h-.4l-.1 .2 .6 .4-.3 .2-.3-.1M63.9 78.4h.3l.3 .2-.1 .5h-.5M63.9 78.4v1.2M65 77.9v.2M65 78.4v.8M65.6 77.9v1.3M65.7 78.7l.3 .5M66 78.4l-.4 .5M66.5 78.8l.6-.1-.2-.3-.4 .1v.5l.2 .2 .3-.1M68.3 80l.4 1.1 .4-1.1M68.5 78.4h.4l.2 .1v.6h-.6"/>
<path d="M68.5 78.4v1.2M69.6 78.4v.8M70.1 78.4l-.5 .2M70.4 78.5l.2-.1 .4 .1v.6h-.6zM71.4 78.4h.4M71.6 77.9v1.2l.2 .1M72.2 78.8l.6-.1v-.3h-.5l-.1 .1v.5l.1 .2 .5-.1M73.9 78.4h-.4l-.2 .1v.6h.6M74.2 78.4h.4M74.4 77.9v1.1l.2 .2M74.8 80v1.1h.2M75.1 77.9v.2"/>
<path d="M75.1 78.4v.8M75.6 78.6l.2-.2h.4v.7h-.6zM76.7 78.5l.2-.1 .4 .1v.7M76.7 78.4v.8M77.9 79.1v.1M83.4 62.9l.6-.1 .1 .3-.8 .9h.8M83.4 67.1l.4-.3v1.1M83.4 67.9h.7M83.7 60.7a.68 .68 0 0 1 .4 .7 .68 .68 0 0 1-.4 .6l-.3-.2v-.8zM84 64.7h-.6v.6l.6-.1v.7l-.4 .1-.2-.2M84.4 66l.5-1.3 .4 1.3M84.5 60.7h.9l-.9 1.3h.9"/>
<path d="M84.6 63.9v.1M84.6 66.9l.2-.1h.3a.77 .77 0 0 1-.1 1.1l-.4-.2zM84.6 65.6h.6M85.8 61.4h.5l.2-.1v-.4l-.2-.2h-.5v1.3M85.8 62.8h-.6v.6l.4-.2 .3 .3-.2 .5-.5-.1M85.8 67.9h.1M86.1 61.4l.4 .6M86.2 64l.5-1.2 .4 1.2M86.3 66.8h.8l-.4 .4 .3 .1v.6h-.7M86.3 63.6h.6M86.5 65.1h.4M86.7 64.7v1.1l.2 .2"/>
<path d="M87.1 61.3h.6v-.4l-.2-.2h-.4v1.3l.6-.1 .1-.3-.3-.3M87.3 65.1v.9M87.7 65.1l-.4 .3M88 67.2l-.3-.1-.2 .2 .1 .2 .4 .1v.3h-.5M88.1 64.7v.1M88.1 65.1v.9M88.4 62.8v1.2M88.4 63.4h.7M88.5 60.7a.68 .68 0 0 1 .4 .7 .68 .68 0 0 1-.4 .6l-.2-.2v-.8zM88.7 65.2a.36 .36 0 0 1 .6 .2l-.1 .5h-.5M88.7 65.1v1.3M89.1 62.8v1.2"/>
<path d="M89.4 60.9l.5-.2 .2 .3-.7 1h.7M89.4 67.1h.4M89.5 66.8v1l.3 .1M89.6 63.4l.3-.3 .4 .3-.2 .6-.4-.1zM90.2 66.8h.1M90.2 67.1v.8M90.8 62.8v1l.2 .2M90.8 67.3l.2-.2 .3 .1v.7M90.8 67.1v.8M91.2 60.7h-.6l-.1 .6h.6l.2 .5-.2 .2h-.4l-.2-.2M91.3 67.3l.2-.2 .4 .2v.6M91.9 60.8l.3-.1 .2 .3v.8l-.2 .2a.71 .71 0 0 1-.3-1.2z"/>
<path d="M92 62.8v1.2h-.5v-.8h.5M92.4 67.5l.6-.1-.2-.3-.4 .1v.7h.5M93 61.3h.4M93.5 63.3l.2-.2 .3 .1v.8M93.5 63.1v.9M93.5 67.5h.9M93.6 60.7h-.6v1.3M94 63.4l.2-.3 .3 .1v.8M94 61.3h.4M94.6 60.7h-.6v1.3M94.9 67.1h.4M95 61.1l.4-.4v1.3"/>
<path d="M95 66.8v1l.3 .1M95 62h.7M95.1 63.2l.4-.1 .2 .3v.6h-.6v-.5h.6M95.7 67.3l.2-.2 .4 .2v.6h-.6zM96.1 63.1l.7 .9M96.3 61.3h.3M96.8 60.7h-.5v1.3h.5M96.8 63.1l-.7 .9M96.8 67.5h1M98.2 67.1h.5M98.4 66.8v1.1h.3M99.1 67.1v.8"/>
<path d="M99.4 67.1l-.3 .2M99.9 66.8h.1M99.9 67.1v.8M100.5 67.2l.3-.1 .2 .2v.6h-.5M100.5 67.1v1.3M135.1 62.8l.4 1.2 .4-1.2M135.2 60.7h.7l-.4 .6h.3l.1 .5-.2 .2h-.4l-.1-.2M135.2 67.5h1M135.4 65.2l-.2-.1v-.3h.6l.1 .3-.1 .1h-.4l-.2 .3v.2l.2 .3h.3l.2-.3v-.2l-.2-.3M135.8 67v.9M136.4 61.8v.2M136.6 65.2l-.2-.1v-.3h.6l-.1 .4h-.3l-.2 .3v.2l.2 .3 .4-.2v-.4l-.1-.2"/>
<path d="M136.8 67.5h.9M136.9 63.1v1l-.3 .3-.3-.1M136.9 63.2l-.4-.1-.2 .2v.6l.6 .1M136.9 61.1l.4-.4v1.3M136.9 62h.7M137.6 65.2l.4-.1 .1 .2v.7M137.6 65.1v.9M137.8 63.2l-.3-.1-.1 .3 .5 .3-.1 .3h-.4M138 62l.4-1.3 .4 1.3M138.1 65.3l.2-.2 .3 .2v.7M138.1 61.7h.6M138.2 66.8h.6l.2 .1-.1 .4-.7 .6h.8"/>
<path d="M138.4 63.5h1M139.2 64.9l.5-.2a.86 .86 0 0 1 0 1.3l-.3-.1a.74 .74 0 0 1-.2-1zM139.6 66.8h.1a.62 .62 0 0 1 .5 .5 .62 .62 0 0 1-.5 .6 .84 .84 0 0 1-.1-1.1zM139.7 63.1h.5M139.9 62.8v1l.1 .2h.2M140.2 61.3h.5v.7M140.2 61.2v.8M140.5 65.2l.4-.1 .2 .2v.7M140.5 66.8l.4 1.1 .4-1.1M140.5 64.7v1.3M140.7 61.3l.2-.1 .4 .1v.7M140.7 63.3l.1-.2 .3 .1 .1 .8"/>
<path d="M140.7 62.8v1.2M141.7 65.2l.3-.1 .2 .2v.7M141.7 65.1v.9M141.9 61.3l.3-.1 .2 .1v.7M142.2 65.3l.2-.2 .3 .2v.7M142.4 61.5h-.5l-.1 .2 .1 .3 .5-.1M142.4 66.8l.5 1.1 .4-1.1M142.6 62.9l.6-.1 .2 .1-.1 .4-.7 .7h.8M142.8 61.2l.7 .8M143.5 61.2l-.7 .8M143.9 63.9v.1M144.2 65.2h.5v.8"/>
<path d="M144.2 67.1v1l-.2 .3-.3-.1M144.2 67.2l-.3-.1-.3 .2 .1 .6h.5M144.2 65.1v.9M144.7 65.3l.2-.2 .4 .2v.7M145.1 62.8h-.6l-.1 .6 .2-.2h.3l.2 .2v.5h-.7M145.2 67.2l-.3-.1-.2 .2 .6 .5-.2 .1h-.4M145.5 62.8l.3 1.2 .5-1.2M145.8 65.2l.5-.1 .1 .2v.7M146.4 65.4l-.6 .2v.3h.6M146.8 67.3l.1-.2 .4 .2v.6M146.8 67.1v.8M146.8 65.1l.7 .9"/>
<path d="M147.3 67.3l.1-.2 .4 .1v.7M147.5 65.1l-.7 .9M147.6 63.3l.2-.2 .3 .1 .1 .8M147.6 63.1v.9M148.2 63.4l.2-.3 .2 .1 .1 .8M148.4 67.2l.3-.1 .3 .2v.6M149 67.4l-.6 .1v.4h.6M149.3 63.2l.3-.1 .2 .3v.6h-.5v-.5h.5M149.4 67.1l.7 .8M150.1 67.1l-.7 .8M150.2 63.1l.7 .9M150.9 63.1l-.7 .9"/>
<path d="M54.9 81.1l.4-1.1 .4 1.1M54.9 87.9l.4 1.2 .4-1.2M55.1 90.2l.3-.3v1.2M55.1 92l.4-.2 .2 .4-.7 .9h.7M55.1 93.9l.4-.1 .2 .4-.7 .8h.7M55.1 80.8h.6M55.1 91.1h.6M55.2 83.9v1.2h.1M55.5 82.4l-.3-.1-.1 .3 .5 .4-.2 .2-.3-.1M55.7 84.5l.1-.1h.5v.7h-.5zM56.1 82.8l.6-.1-.1-.3h-.5v.7h.5M56.2 80.4l.1 .7h.4"/>
<path d="M56.2 88.3h.5v.8M56.4 90.4l-.1-.1v-.3h.5v.4h-.4l-.1 .1v.5l.1 .1h.3l.2-.2v-.3l-.2-.2M56.5 91.8l-.2 .9h.7M56.7 88.6l-.5 .1-.1 .2 .2 .2 .4-.1M56.7 80.4v.7M56.8 84.4h.6v.1v.6h-.6v-.4l.6-.1M56.8 93.8h-.5v.6l.4-.1 .2 .2-.1 .5-.5-.1M56.8 92.2v.9M57.1 82.8l.6-.1-.2-.4-.4 .2v.5l.2 .2 .3-.1M57.1 80.4h.5M57.3 89.9l.4 1.2 .4-1.2M57.3 91.8l.4 1.3 .4-1.3"/>
<path d="M57.3 88.3v.8M57.5 93.9l.3-.1a.84 .84 0 0 1 .1 1.2h-.3l-.2-.1zM57.6 88.3l-.3 .2M57.9 80.5h.6v.6h-.6zM58 87.9v.1M58 88.3v.8M58.5 95l.4-1.2 .4 1.2M58.5 83.9v1.2h-.5l-.1-.7h.6M58.5 94.7h.6M59 88.3h-.3l-.2 .2 .1 .2h.4l.1 .2-.1 .2-.5-.1M59.1 80.5l.5-.1v.7M59.1 80.4v.7"/>
<path d="M59.1 84.7h1M59.5 90.4l.3-.1 .2 .2v.6M59.5 92.4l.1-.2 .4 .2v.7M59.5 88.3h.4M59.5 90.3v.8M59.5 92.2v.9M59.6 82.4h-.5v.3l.4 .1 .1 .2-.1 .2-.4-.1M59.6 80.6l.1-.2h.4l.1 .7M59.6 87.9v1l.3 .2M59.7 94.9v.1M60 90.5l.2-.2 .3 .1v.7M60 92.4l.2-.2 .3 .1v.8"/>
<path d="M60.2 82.4a.36 .36 0 0 1 .5 .2v.5h-.5M60.2 82.3v1.3M60.3 88.4l.2-.1h.3v.7h-.5zM60.7 80.6l.1-.2h.5v.7h-.5l-.1-.1zM61.1 90.4h.5v.7M61.1 92.3h.5v.8M61.2 83.9v1.2h-.5v-.7h.5M61.3 81.9v.2M61.3 82.3v.9M61.4 88.3v.8M61.6 90.5l-.5 .2v.4h.5M61.6 92.6l-.5 .1v.3h.5"/>
<path d="M61.7 80.4h.5M61.8 84.4v.7l.5-.1M61.8 88.3l-.4 .2M61.8 81.9v1.3M62 82.7l.4 .5M62.1 90.3l.7 .8M62.1 92.2l.7 .9M62.3 84.4v.7M62.4 82.3l-.6 .5M62.6 80.4v.7M62.8 82.8l.6-.1v-.3l-.5-.1-.1 .2v.5l.1 .2 .5-.1M62.8 90.3l-.7 .8"/>
<path d="M62.8 92.2l-.7 .9M62.9 84.4h.5v.7M62.9 84.4v.7M63 80.4l.4 .7 .2-.7M63.4 84.5l.1-.1h.4l.1 .7M64 80.7l.6-.1v-.2h-.5l-.1 .2 .1 .5h.5M64 90.3l.3 .8 .2-.6 .2 .6 .3-.8M64.3 82.4l-.3-.1-.1 .3 .5 .4-.2 .2-.3-.1M64.5 85.1l.6-.1-.1-.6h-.5v1.1M64.7 92.3l-.4-.1-.2 .2v.6h.6M65.2 91.8v1.2l.2 .1M65.5 90.4h.5v.6l-.2 .1-.4-.2z"/>
<path d="M65.7 85.1l-.1 .2M65.8 82.3l1 .4-1 .3M65.8 92.3l.4-.1 .2 .2v.7M66 80.3l.4-.3v1.1M66 81.1h.8M66.4 92.6l-.6 .1v.3h.6M66.6 90.3v.8M66.9 90.3l-.3 .1v.1M67 92.4l.2-.2 .3 .2v.7M67 92.2v.9M67.1 84.7l.6-.1-.1-.2h-.4l-.1 .1 .1 .6h.4M67.2 80h.6l.1 .2-.7 .9h.7"/>
<path d="M67.3 89.9v1.2M67.4 90.6l.4 .5M67.5 92.4l.2-.2 .3 .2v.7M67.8 90.3l-.5 .4M67.9 81.9l-.4 .1-.2 .2v.8l.2 .2 .4-.1v-.7h-.5l-.1 .3M68 84.4h.5M68.2 83.9v1.1l.1 .1h.2M68.4 89.9v.1M68.4 90.3v.8M68.6 92.3l.4-.1 .2 .3-.1 .5h-.5M68.6 92.2v1.3M68.8 81.9a.68 .68 0 0 1 .4 .6 .68 .68 0 0 1-.4 .7l-.3-.3v-.7z"/>
<path d="M68.9 90.4l.4-.1 .2 .2v.6M68.9 90.3v.8M69.5 84.4h-.6v.6l.6 .1M69.5 81.9l.5 1.3 .4-1.3M69.7 91.8v.2M69.7 92.2v.9M70 85v.1M70.3 92.4l.2-.2 .3 .1v.8M70.3 92.2v.9M70.6 90.3v1l-.2 .2h-.3M70.6 90.4a.36 .36 0 0 0-.6 .1l.1 .6h.5M70.8 80.4h-.4v.3h.3l.2 .3-.1 .1h-.4"/>
<path d="M71.2 91.1l-.1 .2M71.4 80.4l.1 .7h.4M71.9 92.2v1.1l-.2 .2-.3-.1M71.9 92.3l-.3-.1-.2 .2v.6h.5M71.9 80.4v.7M72.3 82.4l-.4-.1-.2 .3v.5h.6M72.3 81.9v1.3M72.5 81.1h.6l-.1-.7h-.5v1.2M72.9 82.3v.7l.1 .2 .4-.2M73.4 82.3v.9M73.7 81.1h.4l.2-.1v-.4l-.2-.2h-.4v1.2M73.9 82.8l.6-.1v-.3l-.5-.1-.1 .2v.5l.1 .2 .5-.1"/>
<path d="M75.3 80.4l.3 .7M75.8 82.3h.4M75.9 80.4l-.4 1.1-.2 .1M76 81.9v1.2l.2 .1M76.7 82.4h.5v.7l-.4 .1-.2-.3zM77.8 80.4h-.5v.2v.5h.5M78.4 80.4h.5v.7h-.5v-.4l.5-.1M79.5 80.5l.5-.1v.7M79.5 80.4v.7"/>
</g>
<g fill="#00a200">
<circle cx="110.2" cy="75.7" r=".47"/>
<circle cx="99.1" cy="75.7" r=".47"/>
<circle cx="107.7" cy="110.3" r=".47"/>
<circle cx="99.1" cy="93" r=".47"/>
<circle cx="149.6" cy="75.7" r=".47"/>
<circle cx="149.6" cy="93" r=".47"/>
<circle cx="139.8" cy="93" r=".47"/>
<circle cx="139.8" cy="75.7" r=".47"/>
<circle cx="125" cy="75.7" r=".47"/>
<circle cx="207.6" cy="93" r=".47"/>
<circle cx="196.5" cy="93" r=".47"/>
<circle cx="179.3" cy="75.7" r=".47"/>
<circle cx="207.6" cy="75.7" r=".47"/>
<circle cx="219.9" cy="75.7" r=".47"/>
<circle cx="196.5" cy="75.7" r=".47"/>
<circle cx="219.9" cy="93" r=".47"/>
<circle cx="112.6" cy="127.5" r=".47"/>
<circle cx="122.5" cy="110.3" r=".47"/>
<circle cx="132.4" cy="93" r=".47"/>
<circle cx="112.6" cy="110.3" r=".47"/>
<circle cx="110.2" cy="93" r=".47"/>
<circle cx="122.5" cy="127.5" r=".47"/>
<circle cx="132.4" cy="127.5" r=".47"/>
</g>
<g fill="none" stroke="#970091" stroke-width=".21">
<path d="M103.8 86.1h-.6v.6h.6l.1 .5-.2 .2-.5-.1M104.7 86.1a.71 .71 0 0 1 .4 .7 .71 .71 0 0 1-.3 .6l-.4-.2v-.8zM105.4 86.1l.5 1.3 .4-1.3M119.4 91.1h-.6l-.1 .5 .5-.1 .3 .2v.4l-.2 .1h-.6M120 91.6l.5-.1v.7M120 91.5v.7M120.4 88.7l.6-.1 .1 .5-.8 .7h.8M120.5 91.6l.1-.1h.4l.1 .7M121.4 88.6l.5 1.2 .4-1.2M121.4 92.2l.5-1.1 .4 1.1M121.6 91.9h.6M172.2 86.3l.2-.2h.4l.1 .2v.4l-.7 .7h.7"/>
<path d="M174.1 86.1h-.6l-.1 .6h.7v.6h-.7M174.5 86.1l.4 1.3 .4-1.3M189.5 86.3l.2-.2h.3l.2 .2v.4l-.8 .7h.8M191.3 86.1h-.5l-.1 .6h.6v.6h-.6M191.7 86.1l.4 1.3 .5-1.3M200.6 86.3l.2-.2h.3l.2 .2v.4l-.8 .7h.8M202.5 86.1h-.6l-.1 .6h.7v.6h-.7M202.8 86.1l.4 1.3 .5-1.3M213.6 86.1h-.6v.6h.6l.1 .5-.3 .2-.4-.1M214.4 86.1a.68 .68 0 0 1 .4 .7 .68 .68 0 0 1-.4 .6l-.2-.2v-.8zM215.2 86.1l.4 1.3 .4-1.3M127.2 119.4h-.6l-.1 .6a.45 .45 0 0 1 .6 0 .45 .45 0 0 1 .1 .6h-.7"/>
<path d="M127.9 119.5a.6 .6 0 0 1 .7 .5 .6 .6 0 0 1-.5 .7l-.4-.5zM128.8 119.4l.4 1.3 .5-1.3"/>
</g>
<g fill="none" stroke="#007170" stroke-width=".21">
<path d="M83.8 71.6l.1-.2h.4a.86 .86 0 0 1-.1 1.2l-.4-.3zM84.9 71.4h.8l-.8 1.2h.8M86.1 72h.6l.2-.4-.2-.2h-.6v1.2M86.5 72l.4 .6M87.4 72h.4l.2-.2-.1-.4h-.5v1.2l.6-.1 .1-.3-.3-.2M88.6 71.6l.2-.2h.3a.77 .77 0 0 1-.2 1.2l-.3-.3zM89.6 69.5h.4M89.7 71.5l.6-.1 .2 .2-.1 .3-.7 .7h.8M90.2 68.9h-.6v1.2M90.6 69.3l.4-.4v1.2M90.6 70.1h.8M91.6 71.4h-.6l-.1 .6 .2-.2h.3l.2 .3v.4h-.7"/>
<path d="M92.2 71.4h.2a.62 .62 0 0 1 .5 .6 .62 .62 0 0 1-.5 .6 .84 .84 0 0 1-.2-1.2zM93.3 72h.5M93.9 71.4h-.6v1.2M94.4 72h.4M94.9 71.4h-.5v1.2M95.4 71.7l.3-.3v1.2M95.4 72.6h.6M96.6 72h.4M97.2 71.4h-.6v1.2h.6M122 79.6l.5 .4M122.8 79.6l-.4 .4M127.3 78.9l.2 .3v.4h-.6v-.6l.6-.1a.58 .58 0 0 1 .6 .6"/>
<path d="M128.7 72h.6l.1-.5-.7-.1v1.2M130.3 71.4v.9l-.1 .2-.4 .1M130.7 72.6l.4-1.2 .4 1.2M130.8 72.3h.6M131.6 69.9h.3l.4 .3M131.7 68.9h.2a.86 .86 0 0 1 0 1.2l-.5-.1a.79 .79 0 0 1 .3-1.1zM131.9 71.4h.7l-.4 .4 .4 .3-.1 .4h-.6M133.3 68.9l-.4 .1-.2 .2v.9h.6v-.6l-.4-.1-.2 .2M133.4 71.3l-.4 .9h.8M133.6 71.7v.9M134.6 71.3l-.4 .9h.8M134.8 71.7v.9"/>
<path d="M135.4 71.7l.4-.3v1.2M135.4 72.6h.7M155.8 72h.6l.2-.4-.2-.2h-.6v1.2M157.4 71.4v.9l-.1 .2-.4 .1M157.9 72.6l.4-1.2 .4 1.2M157.9 72.3h.6M158.5 69.1l.3-.2h.2l.3 .2v.9l-.3 .1-.5-.1zM158.8 69.9l.6 .3M159 71.4h.7l-.4 .4 .4 .3-.1 .4h-.6M159.7 68.9h.9l-.5 1.2M160.5 71.3l-.3 .9h.8M160.7 71.7v.9"/>
<path d="M161.7 71.3l-.4 .9h.8M161.9 71.7v.9M162.5 71.7l.4-.3v1.2M162.5 72.6h.8M182.5 70.5h.2l.1-.4v1.3M182.5 71.4h.7M183.7 70.2h.7v.4l-.8 .8h.8M184.9 70.2l.4-.1a.78 .78 0 0 1-.2 1.3l-.2-.5zM186 70.8h.6l.2-.2-.1-.4-.7-.1v1.3M186.4 70.8l.4 .6M187.6 68.3h.4M188.1 70.8l-.2-.2-.3 .2 .1 .4h.4"/>
<path d="M188.1 70.6l.1 .6h.1v-.5a.58 .58 0 0 0-.8-.2 .58 .58 0 0 0-.1 .9 .58 .58 0 0 0 .9 0M188.2 67.7h-.6v1.2M188.7 68.3h.4l.3-.3-.1-.2-.6-.1v1.2h.6l.1-.5-.3-.1M188.8 70.5l.4-.4v1.3M188.8 71.4h.7M189.9 68l.3-.3v1.2M189.9 68.9h.6M190.1 70.2l.4-.1 .2 .3v.8l-.2 .2-.4-.2zM191.3 70.2l.3-.1a.78 .78 0 0 1-.1 1.3l-.3-.2zM192.4 71.4v-1.3l.4 .9 .4-.9v1.3M193.8 70.1v1.3M193.8 70.7h.7"/>
<path d="M194.5 70.1v1.3M195 70.6h.6l-.6 .8h.6M83.2 83.7v-1.2l.4 .8 .4-.8v1.2M84.7 82.5h.5a1.05 1.05 0 0 1 0 1.2h-.5a1.05 1.05 0 0 1 0-1.2zM85.7 82.5l.4 1.2 .5-1.2M87 83.3h.9M88.5 82.6l.4-.1 .2 .2v.7l-.2 .3-.4-.1zM89.5 82.5h.9l-.5 1.2M90.8 82.5h.5l.2 .3 .1 .4-.3 .5h-.5zM92 82.6l.6-.1 .1 .2v.3l-.7 .7h.7M93.2 82.6l.6-.1v.5l-.7 .7h.7M93.3 85.5h.6l.2-.1-.1-.4h-.7v1.1"/>
<path d="M93.7 85.5l.4 .6M94.4 82.6l.5-.1 .1 .2v.7l-.1 .3-.5-.1zM94.4 85l.5 1.1 .3-1.1M95.6 85.3l.4-.3v1.1M95.6 86.1h.7M95.6 82.5v1.2M95.8 83l.5 .7M96.3 82.5l-.7 .7M98.9 97.3l-.3-.1-.3 .4v.6l.1 .2h.6v-.4h-.2M100.2 97.2v1.3l-.7-1.3v1.3M100.8 97.2h.3l.4 .4v.6l-.4 .3h-.3zM102 84h.1l.2-.3v1.3"/>
<path d="M102 85h.7M103.2 83.9l.4-.2 .2 .2v.8l-.2 .3a.72 .72 0 0 1-.4-1.1zM103.8 81.3h-.6l-.1 .3v.6l.1 .2 .4 .1 .2-.2M104.6 83.7l.4 .2v.8l-.2 .3a.75 .75 0 0 1-.2-1.3zM104.6 81.1l-.3 1h.7M104.9 81.7v.8M105.5 84.2l.5-.1 .1 .2v.7M105.5 84.1v.9M105.8 81.1l-.4 1h.8M106 81.7v.8M111.6 86.7h.5l.2-.2-.2-.4h-.5v1.2l.7-.1v-.4l-.2-.1M112.6 87.3l.5-1.2 .4 1.2"/>
<path d="M112.8 87h.6M113.7 86.1h.7M114.1 86.1v1.2M114.7 86.1h.7M115 86.1v1.2M115.7 86.5l.4-.4v1.2M115.7 87.3h.8M116.9 86.2l.6-.1 .1 .2v.4l-.7 .6h.7M118 86.1l.4 1.2 .3-1.2M118.9 87.5h.9M119.2 83.6a.64 .64 0 0 1 .6 .6 .64 .64 0 0 1-.6 .7zM120.1 86.3l.2-.2h.4l.2 .2v.9l-.3 .1-.5-.1z"/>
<path d="M120.3 84l.4-.4v1.3M120.3 84.9h.7M121.4 83.8l.2-.2h.4l.2 .3-.1 .3-.7 .7h.8M121.6 81.4v-.8l.4 .5 .2-.5h.5v.8M121.6 80h1.2M122.1 86.1v1.2l-.7-1.2v1.2M127.3 80.1a.42 .42 0 0 1 .2 .7l-.6-.1a.36 .36 0 0 1 .1-.6h.5a.58 .58 0 0 1 .6 .6M127.3 97.6l.2 .1a.42 .42 0 0 1-.1 .5 .42 .42 0 0 1-.5 0l-.1-.4a.72 .72 0 0 1 .7-.2 .72 .72 0 0 1 .6 .6M127.5 82l-.1-.6-.5-.1-.1 .7h1.3M128.1 99.3l-1.3-.5v.7M128.1 81.3l-.6 .4M128.1 99.9l-.6 .5"/>
<path d="M129.2 99l.3-.2h.8l.2 .2a.68 .68 0 0 1-.6 .4 .68 .68 0 0 1-.7-.4zM129.2 98.2h1.3M129.7 97.7l.5 .5M130.5 99.9v.7M130.5 97.7l-.5 .4M142.6 85.3l.4-.3v1.1M142.6 83.1h.6l.2-.4-.2-.2h-.6v1.2M142.6 86.1h.7M143 83.1l.4 .6M143.9 85h.5l.1 .7-.2 .4h-.3l-.2-.1zM144.1 83l-.3-.2 .2-.3h.4l.2 .2-.3 .3-.4 .1-.1 .3 .2 .3h.4l.2-.3-.3-.4M145.2 85h.3a.94 .94 0 0 1 0 1.1h-.3a.78 .78 0 0 1 0-1.1z"/>
<path d="M145.2 82.5h.3a.64 .64 0 0 1 .3 .7 .64 .64 0 0 1-.6 .5v-.1a.94 .94 0 0 1 0-1.1zM146.2 85v1.1M146.3 85.5l.5 .6M146.8 85l-.6 .6M152.4 85.9h.2l.2-.4v1.3M152.4 86.8h.8M152.5 83.1l.7 .2v.7l-.3 .3h-.4zM153.9 86.1l-.3-.2 .1-.3h.6v.4l-.4 .1-.3 .2v.3l.3 .2 .4-.1v-.5l-.2-.1M154.4 83.6a.35 .35 0 0 1-.4 .3 .35 .35 0 0 1-.3-.3v-.3a.35 .35 0 0 1 .3-.2 .35 .35 0 0 1 .4 .2l-.2 .9-.4 .1M154.7 85.5l.4 1.3 .4-1.3M172.2 84l.4-.3v1.3M172.2 85h.7"/>
<path d="M172.8 81.3l-.2-.1a.65 .65 0 0 0-.5 .7 .65 .65 0 0 0 .5 .6l.2-.2M173.5 83.8a.61 .61 0 0 1 .7 .4 .61 .61 0 0 1-.4 .8 .71 .71 0 0 1-.3-1.2zM173.6 81.1l-.3 1h.8M173.9 81.7v.8M174.6 84.1v.7l.2 .2 .3-.2M175 81.2a.55 .55 0 0 0-.5 .5v.5l.2 .3h.3l.2-.3v-.3l-.2-.2h-.4l-.1 .2M175.1 84.1v.9M189.4 84h.2l.2-.3v1.3M189.4 85h.8M190.1 81.3l-.2-.1a.65 .65 0 0 0-.6 .7 .65 .65 0 0 0 .6 .6l.2-.2M190.8 83.8l.2-.1 .3 .2v.8l-.3 .3a.71 .71 0 0 1-.2-1.2zM190.9 81.1l-.4 1h.8"/>
<path d="M191.1 81.7v.8M191.7 81.2h.8l-.5 1.3M191.9 84.1v.8l.3 .1 .2-.2M192.4 84.1v.9M200.5 84l.5-.3v1.3M200.5 85h.8M201.2 81.3l-.2-.1a.65 .65 0 0 0-.6 .7 .65 .65 0 0 0 .6 .6l.2-.2M201.9 83.8l.2-.1a.68 .68 0 0 1 .4 .6 .68 .68 0 0 1-.4 .7 .81 .81 0 0 1-.2-1.2zM202 81.1l-.3 1h.8M202.2 81.7v.8M203 84.1v.8l.3 .1 .2-.2M203.1 81.7l-.3-.1 .1-.3h.6l.1 .3-.2 .1h-.3l-.3 .3v.2l.3 .3h.2l.3-.3v-.2l-.3-.3"/>
<path d="M203.5 84.1v.9M211.7 84l.3-.3v1.3M211.7 85h.7M213.1 83.7l.5 .2v.8l-.3 .3a.75 .75 0 0 1-.2-1.3zM213.6 81.3l-.5-.1-.3 .4v.6l.2 .2 .3 .1 .3-.2M214.3 83.7a.68 .68 0 0 1 .5 .6 .68 .68 0 0 1-.5 .7l-.2-.6 .1-.5zM214.3 81.1l-.3 1h.8M214.6 81.7v.8M215.3 84.2l.4-.1 .2 .2v.7M215.3 84.1v.9M215.9 81.7l-.2 .3-.4-.1v-.6h.6v.9l-.2 .2-.4 .1M219.7 97.3l-.3-.1-.3 .4v.6l.1 .2h.6v-.4h-.2"/>
<path d="M221 97.2v1.3l-.7-1.3v1.3M221.6 97.2h.3l.4 .4v.6l-.4 .3h-.3zM98.8 107.1h.8l-.4 .5 .4 .2-.1 .5-.7-.1M98.8 105.3h.6l.1-.5-.7-.1v1.2M99.1 105.3l.4 .6M99.9 104.7h.9l-.5 1.2M100.2 107.2l.3-.1a.84 .84 0 0 1 .1 1.2h-.3l-.2-.1zM101.1 104.7h.9l-.6 1.2M101.3 107.1v1.2M101.4 107.9l.4 .4M101.8 107.6l-.5 .4M102 119.2h.1l.2-.4v1.3"/>
<path d="M103.1 116.4a.64 .64 0 0 1 .7 .6 .64 .64 0 0 1-.7 .6zM103.4 119.3h-.2v-.2l.2-.3h.3l.1 .4-.4 .1-.2 .3v.2l.2 .3 .4-.2v-.4l-.1-.2M104.3 118.8l.3 1.3 .4-1.3M104.4 116.9l-.1-.1v-.3h.6v.2l-.1 .2h-.4l-.1 .1v.5l.1 .1h.3l.2-.2v-.3l-.2-.2M115.4 116.4h.6l.1-.5-.7-.1v1.2M115.6 118.6l.3-.4v1.2M115.6 119.4h.7M115.7 116.4l.4 .6M116.5 115.8h.9l-.5 1.2M116.9 118.3l.3-.1 .3 .3v.7l-.2 .2-.4-.1zM118 116.3l-.2-.1v-.3l.6-.1v.4l-.6 .2 .1 .6h.5l.1-.5-.3-.2M118 118.2v1.2"/>
<path d="M118.1 119l.4 .4M118.5 118.7l-.5 .4M126.5 117.4l.5-.4v1.2M126.5 118.2h.8M127.3 114.7l-.2-.2a.64 .64 0 0 0-.6 .6 .64 .64 0 0 0 .6 .7l.2-.2M127.5 100.7v-.5l-.3-.3-.3 .1-.1 .7h1.3M127.9 117a.6 .6 0 0 1 .7 .6 .6 .6 0 0 1-.5 .6l-.4-.5zM128.1 114.5l-.3 .9h.8M128.4 114.9v.9M129.1 117h.1a.68 .68 0 0 1 .5 .6 .68 .68 0 0 1-.5 .6l-.3-.5zM129.7 114.5h-.6l-.1 .6 .6-.1 .1 .6-.3 .2-.4-.2M130.2 117.6l.1-.2 .4 .2v.6"/>
<path d="M130.2 117.4v.8M130.5 100.3h-1.3l.4 .2v.1M136.4 110.9h.6l.1 .5-.7 .7h.7M136.6 108.4l.3-.1a.73 .73 0 0 1 0 1.3h-.2a.86 .86 0 0 1-.1-1.2zM136.7 109.3h.2l.4 .4M138.4 110.9v1.2l-.7-1.2v1.2M138.4 108.3h-.6l-.1 .6h.7v.6h-.7M138.8 110.9h.9l-.6 1.2M140.2 110.9h.4l.2 .1v.8a.35 .35 0 0 1-.5 .3 .35 .35 0 0 1-.2-.5zM141.3 110.9h.5a.86 .86 0 0 1-.1 1.2l-.4-.1zM142.4 110.9h.6l.1 .3-.7 .9h.7M102 120.1h.7"/>
<path d="M132.2 130.6h-.5l-.2 .2v.7a.55 .55 0 0 0 .8 .2v-.4h-.3M133.5 130.6v1.2l-.7-1.2v1.2M134.1 130.6h.5a.66 .66 0 0 1 .2 .8 .66 .66 0 0 1-.7 .4z"/>
</g>
</svg>
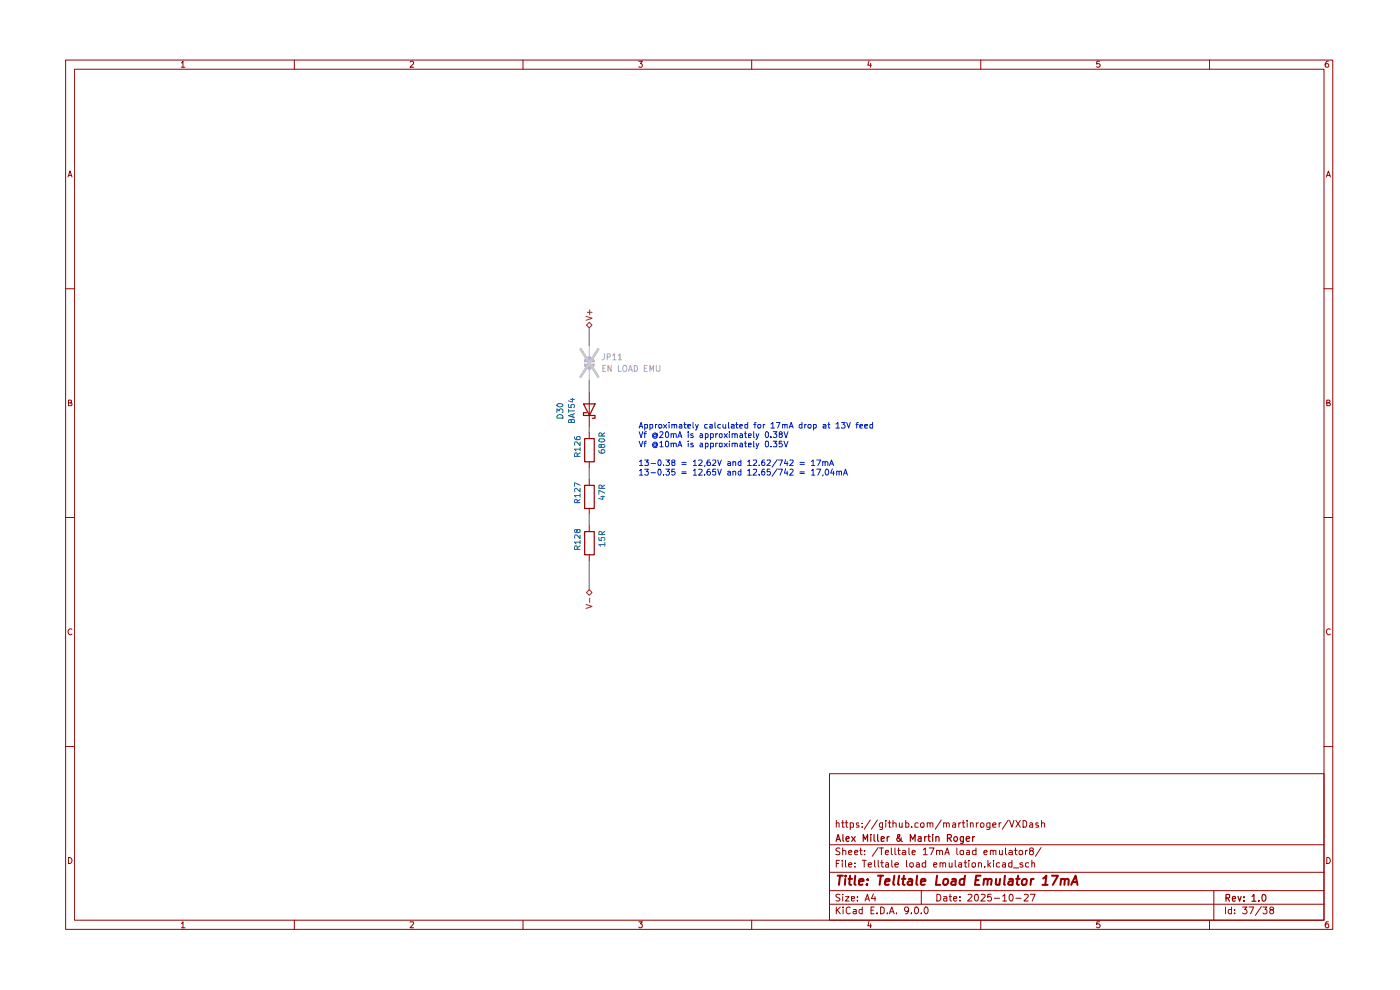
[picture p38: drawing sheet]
<svg xmlns="http://www.w3.org/2000/svg" width="297mm" height="210mm" viewBox="0 0 297 210" stroke-linecap="round" stroke-linejoin="round" font-family="sans-serif">
<g fill="none" stroke="#980000" stroke-width=".21">
<path d="M13.9 12.7h268.8v184.4h-268.8zM15.8 14.7h265.1v180.5h-265.1zM38.5 13.3h.1l.2-.3v1.3M38.5 14.3h.7M62.4 12.7v2M87 13.2l.5-.2 .3 .2-.1 .4-.7 .7h.8M111 12.7v2M135.5 13h.8l-.5 .5 .4 .1v.6h-.7M159.5 12.7v2M184.4 12.9l-.3 .9h.8M184.7 13.4v.9M208.1 12.7v2"/>
<path d="M233.3 13h-.6l-.1 .6h.7v.6h-.7M256.6 12.7v2M281.8 13a.71 .71 0 0 0-.7 .5 .71 .71 0 0 0 .3 .8l.4-.1v-.6l-.4-.1-.3 .3M14.4 37.5l.5-1.2 .4 1.2M14.5 37.2h.7M281.4 37.5l.4-1.2 .4 1.2M281.5 37.2h.6M13.9 61.3h1.9M280.9 61.3h1.8M14.5 85.5h.4l.3-.3-.2-.3h-.5v1.2h.6l.2-.5-.4-.1M281.5 85.5h.4l.2-.3-.1-.3h-.5v1.2h.6l.1-.5-.3-.1M13.9 109.8h1.9"/>
<path d="M280.9 109.8h1.8M15.3 133.5a.59 .59 0 0 0-.9 .5 .59 .59 0 0 0 .8 .6l.1-.1M282.2 133.5a.59 .59 0 0 0-.8 .5 .59 .59 0 0 0 .7 .6l.1-.1M13.9 158.4h1.9M280.9 158.4h1.8M176 164.1h104.9v31.1h-104.9zM176 179.2h104.9M177.4 174.7l.2-.2 .4 .1v.9M177.4 174v1.5M178.2 180l-.6-.1-.3 .2 .1 .4 .8 .4-.1 .3h-.8M178.5 174.5h.6M178.8 174v1.5h.3"/>
<path d="M178.8 179.9v1.4M179.4 174.5h.5M179.5 174v1.3l.1 .2h.3M180.4 174.6l.4-.1 .3 .2v.7l-.7 .1M180.4 174.5v1.5M182.2 174.6l-.4-.1-.2 .2 .2 .3h.4v.5h-.6M182.6 179.9v1.2l.3 .2M182.9 175.4v.1M182.9 174.6v.1M184.6 173.9l-1.3 2M186.1 173.9l-1.2 2M186.3 179.8l-1.3 1.8"/>
<path d="M186.6 179.9h.8M187 179.9v1.4M187.2 174.5v1.2a.36 .36 0 0 1-.6 .2M187.2 174.6l-.4-.1-.2 .3v.6l.6 .1M187.9 174v.2M187.9 174.5v1M188.4 174.5h.6M188.7 174v1.5h.3M189.1 179.9v1.2l.3 .2M189.4 174.7l.3-.2 .4 .2v.8M189.4 174v1.5M189.9 179.9v1.2l.2 .2"/>
<path d="M190.6 179.9v1.2l.4 .2M190.8 174.5l.1 1 .5-.1M191.4 174.5v1M192.1 174v1.5l.6-.1 .1-.6a.45 .45 0 0 0-.7-.2M192.8 179.9v1.2l.2 .2M193.4 175.4v.1M194.8 174.6l-.5-.1-.2 .2v.7l.7 .1M195.3 174.8a.45 .45 0 0 1 .7-.2v.9l-.6-.1zM196.7 174.7l.2-.2 .4 .2v.8M196.7 174.5v1M197.1 179.9h1.1l-.7 1.4M197.3 174.7l.2-.2 .4 .1v.9"/>
<path d="M199.7 173.9l-1.3 2M200.2 174.7l.2-.2 .4 .2v.8M200.2 174.5v1M200.8 174.7l.2-.2 .4 .2v.8M202.1 174.6l.4-.1 .2 .2v.8h-.6v-.4l.6-.2M203 179.9v1.2l.2 .2M203.4 174.5v1M203.8 174.5l-.4 .3M204.1 174.5h.6M204.3 174v1.3l.1 .2h.3M205.2 174v.2M205.2 174.5v1"/>
<path d="M205.9 174.7l.1-.2 .5 .2v.8M205.9 174.5v1M207 179.9v1.4M207.1 174.5v1M207.6 174.5l-.5 .3M208.2 174.5h.3l.2 .3-.1 .7h-.5l-.1-.3v-.4zM210 174.5v1.2l-.2 .3-.5-.1M210 174.6l-.4-.1-.3 .2v.7l.7 .1M210.6 175l.7-.1v-.3l-.4-.1-.3 .2 .1 .8h.6M212 174.5v1M212.4 174.5l-.4 .3M213.3 179.9v1.2l.3 .2"/>
<path d="M213.9 173.9l-1.3 2M214.2 174l.5 1.5 .4-1.5M215.4 179.9v1.2l.4 .2M215.5 174l.9 1.5M216.4 174l-.9 1.5M217 174h.4l.4 .4v.7l-.3 .4h-.5zM218.5 174.6l.4-.1 .2 .2v.8h-.6l-.1-.4 .7-.2M220.3 174.6h-.6v.4h.6v.2v.3h-.6M220.8 179.8l-1.1 1.8M220.9 174.7l.3-.2 .4 .2v.8M220.9 174v1.5M14.5 181.9a.65 .65 0 0 1 .8 .6 .65 .65 0 0 1-.8 .7z"/>
<path d="M38.5 195.9l.3-.4v1.3M38.5 196.8h.7M62.4 195.2v1.9M87 195.6l.7-.1 .1 .3-.8 1h.8M111 195.2v1.9M135.5 195.5h.8l-.5 .5 .5 .2-.1 .5-.5 .1-.2-.2M159.5 195.2v1.9M176 191.8h104.9M176 188.9h104.9M176 185h104.9M177.4 192.4v1.4M177.4 183.2h.5"/>
<path d="M177.6 193l.7 .8M178.1 182.5h-.7v1.4M178.2 189.8h-.8l-.1 .3 .8 .4 .1 .4-.3 .2-.6-.1M178.3 192.4l-.9 .8M178.7 182.5v.2M178.7 183v.9M178.8 189.7v.1M178.8 180.5l.4-.1 .2 .1v.8M178.8 190.2v.9M178.9 192.4v.2M178.9 192.9v.9M179.4 190.2h.7l-.7 .9h.7"/>
<path d="M179.4 182.5v1.3l.1 .1M180 183.4l.7-.1-.2-.3-.5 .2v.6l.3 .1 .3-.1M180 180.8l.7-.1-.2-.3-.5 .1v.6l.3 .2 .3-.1M180.4 192.6l-.4-.2-.5 .3 .1 1 .4 .1 .4-.1M180.6 190.6l.7-.1-.1-.3h-.6v.8h.6M181.1 192.9h.5v.9M181.3 180.8l.7-.1-.2-.3h-.3l-.2 .1v.6l.2 .2 .4-.1M181.4 183.8v.1M181.4 183.1v.1M181.6 193.2l-.5 .1-.1 .2 .1 .3h.5M181.9 191v.1M181.9 190.2v.2"/>
<path d="M182.4 180.4h.5M182.9 192.9h-.5l-.2 .7a.45 .45 0 0 0 .7 .2M182.9 192.4v1.4M182.9 182.5h.9M183.3 182.5v1.4M183.4 181.2v.1M183.4 180.5h.1M183.5 191.1l.5-1.4 .4 1.4M183.7 190.7h.7M184.2 183.4l.7-.1v-.2l-.5-.1-.2 .2v.6l.2 .1 .5-.1M184.4 195.4l-.3 1h.8M184.7 196v.8"/>
<path d="M184.8 193.1h.5M185.3 189.6l-.4 1h.9M185.5 192.4h-.7v1.4h.7M185.5 182.5v1.3l.2 .1M185.6 190.2v.9M186 193.7v.1M186.3 182.5v1.3l.2 .1M186.8 192.4h.4l.4 .3v.8l-.4 .3h-.4zM186.8 183h.6M187.1 182.5v1.3l.3 .1M187.8 180.8l.7-.1-.2-.3h-.3l-.2 .1v.6l.2 .2 .4-.1M187.9 183.1l.4-.1 .2 .2v.7"/>
<path d="M188.3 193.7v.1M188.5 183.3l-.6 .1-.1 .2 .2 .3 .5-.1M188.7 193.8l.5-1.4 .5 1.4M188.8 193.4h.7M189.2 182.5v1.3l.2 .1M189.9 183.4l.7-.1-.1-.2-.4-.1-.2 .2v.6h.6M190.2 193.7v.1M190.5 180.4h.5M191.5 180.5l.4-.1 .2 .1v.8M192.1 180.7l-.6 .1-.1 .2 .2 .3 .5-.1M192.3 182.5v1.3l.2 .1M192.7 193l-.2 .3h-.4l-.2-.3v-.3l.2-.3h.4l.2 .3v.8l-.2 .3h-.4"/>
<path d="M193.1 183.1h.1a.36 .36 0 0 1 .6 .2v.4a.41 .41 0 0 1-.4 .2 .41 .41 0 0 1-.4-.2zM193.3 193.7v.1M193.5 180.8l.7-.1-.2-.3h-.3l-.2 .1v.6l.2 .2 .4-.1M194.1 192.6l.2-.2a.75 .75 0 0 1 .6 .7 .75 .75 0 0 1-.6 .7l-.2-.1-.1-.4zM194.4 183.1l.5-.1 .1 .2v.7M195 183.3l-.6 .1-.1 .2 .2 .3 .5-.1M195.4 193.7v.1M195.4 188.9v2.9M195.9 180.3l.4-.4v1.4M195.9 181.3h.8M196.4 192.4h.1a.8 .8 0 0 1 .4 .8 .8 .8 0 0 1-.5 .6 .89 .89 0 0 1 0-1.4zM196.4 183.1l-.4-.1-.4 .3 .1 .5h.7"/>
<path d="M196.4 182.5v1.4M198.1 183.4l.6-.1-.1-.3h-.4l-.1 .2v.6l.1 .1 .5-.1M198.7 180.5l.4-.1 .2 .1v.8M198.7 180.4v.9M198.7 189.7a.73 .73 0 0 1 .9 .7 .73 .73 0 0 1-.9 .7zM199.3 180.5l.2-.1 .4 .1v.8M199.4 183.1l.4-.1 .2 .2v.7M199.4 183v.9M200 183.2l.2-.2 .4 .2v.7M200.2 190.2h.6l.1 .9M200.4 181.3l.6-1.4 .4 1.4M200.5 180.9h.8"/>
<path d="M200.9 190.5l-.7 .1v.4h.7M201.4 183v.8h.6M201.4 190.2h.5M201.5 189.7v1.3l.4 .1M202 183v.9M202.3 190.6l.7-.1-.1-.3h-.5l-.1 .2v.6l.2 .1 .4-.1M202.6 182.5v1.3l.3 .1M203.4 183.1h.6v.8M203.7 191v.1M203.7 190.2v.2M203.7 180.5h.7v.7h-.7zM204 183.3l-.6 .1-.1 .2 .3 .3 .4-.1"/>
<path d="M204.5 183h.6M204.8 182.5v1.3l.3 .1M205.1 180.5l.4-.1 .2 .1v.8M205.4 189.8l.5-.1 .3 .4-.9 1h.9M205.5 182.5v.2M205.5 183v.9M205.7 180.7l-.6 .1-.1 .2 .2 .3 .5-.1M206.3 183.1h.6v.7h-.6zM206.9 189.8h.5a1.01 1.01 0 0 1-.2 1.3 .87 .87 0 0 1-.3-1.3zM207 180.5l-.4-.1-.3 .2 .1 .6h.6M207.6 183.1l.4-.1 .2 .2v.7M207.6 183v.9"/>
<path d="M208.1 195.2v1.9M208.1 189.8h.8l.1 .3-.9 1h.9M208.7 180.8l.7-.1-.2-.3-.5 .1v.6l.3 .2 .3-.1M208.9 183.8v.1M209.6 182.5v1.4M209.8 183.4l.4 .5M210.1 180.5l.4-.1 .2 .1v.8M210.1 180.4v.9M210.2 183l-.6 .5M210.3 189.7h-.7l-.1 .7 .6-.2 .2 .3v.4l-.2 .2-.6-.1M210.7 180.5l.2-.1 .4 .1v.8M210.8 182.5v.2"/>
<path d="M210.8 183v.9M210.9 190.5h1.1M212 183.1l-.3-.1-.3 .3v.5h.6M212 180.4v.8h.6M212.6 180.4v.9M212.7 190.1l.4-.4v1.4M212.7 183.1l.4-.1 .2 .2v.7M212.7 191.1h.9M213.3 183.3l-.6 .1-.1 .2 .2 .3 .5-.1M214.1 180.5l.4-.1 .3 .1v.8M214.2 189.8l.2-.1a.76 .76 0 0 1 .5 .7 .76 .76 0 0 1-.5 .7 1.01 1.01 0 0 1-.2-1.3zM214.7 183.1h-.7v.7h.7"/>
<path d="M214.7 182.5v1.4M214.8 180.7l-.7 .1-.1 .2 .2 .3 .6-.1M215 184.1h1.1M215.2 180.4h.6M215.5 190.5h1.1M216.3 180.5h.6l.1 .6-.2 .1a.36 .36 0 0 1-.6-.1zM217 183.1l-.4-.1-.2 .3v.1l.6 .1v.3l-.2 .1-.4-.1M217.3 189.8h.8v.3l-.9 1h.9M217.5 180.4v.9M218 180.4l-.5 .2M218.2 183.1l-.4-.1-.3 .3 .1 .5h.6M218.6 189.7h1l-.6 1.4"/>
<path d="M218.6 180.5l-.2-.3 .2-.3h.4l.2 .2-.1 .4h-.5a.46 .46 0 0 0-.2 .4 .46 .46 0 0 0 .2 .4l.6-.1a.52 .52 0 0 0-.2-.7M218.9 183.1l.4-.1 .2 .2v.7M218.9 182.5v1.4M233.3 195.5h-.6l-.1 .6 .2-.1h.3l.3 .2v.3l-.3 .3h-.3l-.2-.2M256.6 195.2v1.9M257.5 188.9v6.3M260 192.4v1.4M261.2 192.9h-.5l-.1 .3v.4l.2 .2h.4M261.2 192.4v1.4M261.9 193.7v.1M261.9 192.9v.2M263.6 192.4h.9l-.5 .5 .5 .2v.5l-.3 .2h-.4l-.2-.1"/>
<path d="M265 192.4h1l-.7 1.4M267.6 192.3l-1.3 1.9M267.9 192.4h.9l-.5 .5 .5 .2v.6l-.3 .1h-.4l-.2-.1M269.6 193l-.2-.3 .2-.3 .6 .3-.1 .2-.2 .1a.47 .47 0 0 0-.5 .6l.2 .2a.45 .45 0 0 0 .5-.1 .45 .45 0 0 0 0-.5l-.2-.2M281.5 181.9a.65 .65 0 0 1 .7 .6 .65 .65 0 0 1-.7 .7zM281.8 195.5h-.4l-.3 .5v.5l.3 .3 .4-.1v-.7h-.4l-.3 .2"/>
</g>
<g fill="none" stroke="#980000" stroke-width=".25">
<path d="M177.4 178.5l.4-1.5 .5 1.5M177.5 178h.6M178.8 177v1.2l.2 .3M179.5 178l.7-.2-.2-.3h-.4l-.1 .7 .2 .3 .4-.1M180.7 177.5l.7 1M181.4 177.5l-.7 1M183.1 178.5v-1.5l.5 1 .5-1v1.5M184.7 177v.1M184.7 177.5v1M185.4 177v1.2l.3 .3M186.2 177v1.2l.2 .3M186.9 178l.7-.2-.1-.3h-.6v.9h.6"/>
<path d="M188.2 177.5v1M188.6 177.5l-.4 .3M191.2 177.7v.3l-.5 .5a.43 .43 0 0 1-.4-.2 .43 .43 0 0 1 0-.5l.6-.5-.1-.3h-.3a.55 .55 0 0 0 .2 .8l.7 .7M193.1 178.5v-1.5l.5 1 .5-1v1.5M194.8 177.5h.6v1M195.4 177.8l-.4 .1-.3 .2 .3 .4 .4-.1M196.2 177.5v1M196.5 177.5h-.2l-.1 .3M196.8 177.5h.6M197 177v1.2l.4 .3M197.9 177v.1M197.9 177.5v1"/>
<path d="M198.5 177.6l.1-.1a.36 .36 0 0 1 .6 .2v.8M198.5 177.5v1M201 177.8l.7-.1 .1-.2v-.4l-.8-.1v1.5M201.3 177.8l.5 .7M204.4 177.5v1.1l-.2 .3h-.4M204.4 177.5h-.4l-.3 .3 .1 .6h.6M205 178l.7-.2-.1-.3h-.4l-.2 .2 .1 .7h.5M206.3 177.5v1M206.8 177.5l-.5 .3M260.1 190.5l.7-.1 .1-.6-.8-.1v1.5M260.4 190.5l.5 .7M261.4 190.7l.7-.1-.1-.4h-.5l-.1 .7 .2 .3 .4-.1"/>
<path d="M262.6 190.2l.4 1 .3-1M263.9 191v.2M263.9 190.2v.2M265.6 190.2l.4-.5v1.5M265.6 191.2h.8M267 191v.2M267.8 189.8l.2-.1a.75 .75 0 0 1 .6 .8 .75 .75 0 0 1-.6 .7l-.2-.2-.1-.4z"/>
<circle cx="202.7" cy="178" r=".48"/>
</g>
<g fill="none" stroke="#980000" stroke-width=".42">
<path d="M177.7 185.8h1.1M178.2 185.8l-.2 1.9M179.3 186.4l-.1 1.3M179.4 185.8v.1M180 186.4h.8M180.3 185.8l-.1 1.6 .4 .3M181.4 185.8l-.1 1.6 .2 .3M182.2 187l1-.1-.1-.4a.6 .6 0 0 0-.8 .2v.9h.7M184 187.5l-.1 .2-.1-.1 .2-.1-.1 .2M184.1 186.5v.2M186.3 185.8h1.1M186.9 185.8l-.3 1.9"/>
<path d="M187.8 187l.9-.1v-.4h-.7l-.3 .9 .3 .3 .5-.1M189.7 185.8l-.2 1.6 .2 .3M190.7 185.8l-.2 1.6 .2 .3M191.3 186.4h.8M191.8 185.8l-.3 1.6 .4 .3M192.8 186.5h.7v1.2M193.5 186.9h-.6l-.4 .3 .1 .4 .2 .1 .7-.1M194.6 185.8l-.2 1.6 .2 .3M195.4 187l.9-.1v-.4a.6 .6 0 0 0-.9 .2v.9h.8M198.8 185.8l-.3 1.9h1M200.2 186.6l.6-.2 .4 .4-.1 .6-.4 .3-.5-.1-.1-.2zM202 186.5h.8l-.1 1.2"/>
<path d="M202.8 186.9l-.9 .1-.1 .4 .2 .3 .7-.1M204.5 186.5a.65 .65 0 0 0-.9 .3v.7a.64 .64 0 0 0 .9 .1M204.7 185.8l-.2 1.9M207 186.7h.6M208 185.8h-.9l-.3 1.9h1M208.7 186.6l.3-.2 .5 .1v1.2M208.8 186.4l-.2 1.3M209.5 186.7a.47 .47 0 0 1 .5-.3 .47 .47 0 0 1 .4 .3l-.2 1M211.3 186.4v1.2l.4 .1 .3-.2M212.2 186.4l-.2 1.3M213.2 185.8l-.2 1.6 .2 .3M214.1 186.5h.8l-.1 1.2"/>
<path d="M214.9 186.9l-.9 .1-.1 .4 .2 .3 .7-.1M215.6 186.4h.7M216 185.8l-.3 1.6 .4 .3M216.8 186.8l.4-.4 .6 .2v.8l-.2 .2-.5 .1-.3-.2zM218.8 186.4l-.2 1.3M219.3 186.4l-.6 .4M221.1 187.7h1.1M221.3 186.3l.7-.5-.3 1.9M223.2 185.8h1.2l-1.1 1.9M225.1 186.6l.3-.2 .5 .1-.1 1.2M225.1 186.4l-.1 1.3M225.9 186.7a.47 .47 0 0 1 .4-.3 .47 .47 0 0 1 .4 .3l-.1 1"/>
<path d="M227.2 187.7l1-1.9 .4 1.9M227.5 187.1h.9"/>
</g>
<path d="M123.2 74.1l3.7 5.8M126.9 74.1l-3.7 5.8" fill="none" stroke="#c9c9c9" stroke-width=".42"/>
<path d="M124.4 69l.6-.6 .6 .6-.6 .5z" fill="#fff"/>
<path d="M124.3 67.1l1.3 .4-1.3 .4M124.4 69l.6-.6 .6 .6-.6 .5zM124.6 66.2h1M125.1 65.7v1.1" fill="none" stroke="#805e00" stroke-width=".21"/>
<path d="M124 77.3h2a1.02 1.02 0 0 1-1 1 1.02 1.02 0 0 1-1-1z" fill="none" stroke="#aaa" stroke-width=".21"/>
<path d="M124 77.3h2a1.02 1.02 0 0 1-1 1 1.02 1.02 0 0 1-1-1z" fill="#aaa"/>
<path d="M124 77.3a1.02 1.02 0 0 0 1 1 1.02 1.02 0 0 0 1-1M124 76.7a1.02 1.02 0 0 1 1-1 1.02 1.02 0 0 1 1 1" fill="none" stroke="#aaa" stroke-width=".21"/>
<path d="M124.3 76a1.02 1.02 0 0 1 1.1-.2 1.02 1.02 0 0 1 .6 .9h-2z" fill="#aaa"/>
<path d="M124.3 76a1.02 1.02 0 0 1 1.1-.2 1.02 1.02 0 0 1 .6 .9h-2zM125 73.3v2.4M125 78.2v2.4" fill="none" stroke="#aaa" stroke-width=".21"/>
<path d="M123.2 74.1l3.7 5.8M126.9 74.1l-3.7 5.8" fill="none" stroke="#c9c9c9" stroke-width=".42"/>
<path d="M124.4 125.7l.6-.6 .6 .6-.6 .6z" fill="#fff"/>
<path d="M124.3 128.2l1.3 .4-1.3 .5M124.4 125.7l.6-.6 .6 .6-.6 .6zM125.1 126.9v.9" fill="none" stroke="#805e00" stroke-width=".21"/>
<path d="M123.8 85.7h2.4l-1.2 2.4zM124 93h2.1v5h-2.1zM124.5 87.5h-.7v.6h2.4v.6h-.6M124 102.9h2.1v5h-2.1zM124 112.8h2.1v4.9h-2.1z" fill="none" stroke="#980000" stroke-width=".25"/>
<path d="M125 83.2v7.3M125 91.7v1.3M125 97.9v1.3M125 101.6v1.3M125 107.8v1.2M125 111.5v1.2M125 117.6v1.3" fill="none" stroke="#980000" stroke-width=".21"/>
<path d="M125 69.5v3.8M125 80.6v2.6M125 90.5v1.2M125 99.2v2.4M125 109v2.5M125 118.9v6.2" fill="none" stroke="#00a200" stroke-width=".21"/>
<g fill="none" stroke="#001dcd" stroke-width=".21">
<path d="M135.6 90.8l.4-1.2 .4 1.2M135.6 91.6l.4 1.2 .4-1.2M135.6 93.6l.4 1.2 .4-1.2M135.7 97.9l.3-.3v1.2M135.7 99.9l.3-.4v1.3M135.7 90.5h.6M135.7 98.8h.7M136.6 92h.5M136.6 94h.5M136.8 90.8l.6-.1-.1-.7h-.5v1.2M136.8 97.6h.7l-.4 .4 .4 .1v.6h-.7M136.8 99.5h.7l-.4 .5 .4 .1v.5l-.1 .2h-.5l-.1-.2"/>
<path d="M137.1 91.6l-.3 .1v1.1M137.1 93.6h-.2l-.1 .2v1M137.9 90.8l.6-.1-.1-.7h-.5v1.2M138.1 98.3h1M139.1 90v.8M139.2 92.2l-.3-.1-.3 .2 .2 .4 .4-.1M139.2 92.1v.6l.3-.2a.58 .58 0 0 0-.7-.6 .58 .58 0 0 0-.4 .7 .58 .58 0 0 0 .8 .3l.2-.1M139.2 94.2l-.3-.1-.3 .3 .3 .3 .3-.2M139.2 94.1l.1 .5a.49 .49 0 0 0 0-.7 .49 .49 0 0 0-.7 .1 .67 .67 0 0 0 .1 .9h.5l.2-.1M139.4 90h-.3v.2M139.7 99.6l.3-.1a.78 .78 0 0 1-.2 1.3l-.2-.5zM139.7 97.6h.4a.86 .86 0 0 1-.1 1.2h-.2a.86 .86 0 0 1-.1-1.2z"/>
<path d="M139.8 90h.4l.2 .2v.4l-.2 .2h-.4zM140 91.7l.4-.1 .3 .3-.8 .9h.8M140 93.9l.3-.3v1.2M140 94.8h.7M140.8 98.7v.1M140.8 90l.6 .8M141.2 93.8l.1-.2 .5 .1 .1 .7-.2 .4h-.4l-.1-.3zM141.3 97.6h.7l-.4 .4 .4 .2-.1 .5h-.6M141.3 99.5h.7l-.4 .5h.3l.1 .2-.1 .5-.5 .1-.1-.2M141.4 91.6a.68 .68 0 0 1 .5 .6 .68 .68 0 0 1-.5 .6l-.2-.2v-.8zM141.4 90l-.6 .8M141.9 89.6v.1"/>
<path d="M141.9 90v.8M142.4 92.1h.5v.7M142.4 94.1l.5-.1v.8M142.4 92v.8M142.4 94v.8M142.5 90.1l.5-.1v.8M142.5 90v.8M142.7 98.1l-.2-.4 .5-.1 .2 .2-.2 .3-.5 .1v.5l.2 .1 .4-.1 .1-.2-.2-.4M142.9 92.2l.1-.2 .5 .2v.6M142.9 94.2l.1-.2h.4l.1 .8M143 90.2v-.2h.5v.8M143.1 99.5h-.6v.6l.5-.1 .2 .2v.3l-.2 .3-.5-.2"/>
<path d="M143.8 92.8l.4-1.2 .4 1.2M143.8 94.8l.4-1.2 .4 1.2M144 92.5h.6M144 94.4h.6M144.1 90h.5v.2v.6h-.5v-.4l.5-.1M144.6 98.1h1M144.6 98.5h1M145.1 90h.5M145.2 89.6v1l.1 .2h.3M145.9 90.4l.6-.1-.1-.3h-.5v.8h.5M146 91.6v.1M146 93.6v.1"/>
<path d="M146 92v.8M146 94v.8M147 89.6v1l.2 .2M147 92.1l-.3-.1-.2 .2 .4 .2 .2 .3-.2 .1-.4-.1M147 94h-.4l-.1 .2 .6 .3-.1 .3h-.5M147.1 97.9l.3-.3v1.2M147.1 99.9l.3-.4v1.3M147.1 98.8h.7M147.5 90l.4 .8M148.1 90l-.4 1.2h-.2M148.2 97.7l.6-.1 .2 .1-.1 .4-.7 .7h.8M148.2 99.6l.5-.1 .3 .3-.8 1h.8"/>
<path d="M148.5 92.1l.4-.1 .2 .2v.6M148.5 94h.5l.1 .2v.6h-.6v-.4l.6-.1M149.1 92.3h-.5l-.1 .2 .1 .3 .5-.1M149.6 98.7l-.2 .2M149.6 92.1a.36 .36 0 0 1 .6 .1v.5h-.6M149.6 94.8h.6v-.8h-.6v1.2M149.6 92v1.3M150.1 90h-.5l-.1 .2 .1 .6h.5M150.6 90h.5v.8h-.5v-.4l.5-.1M150.6 97.6h-.4l-.1 .2v.9a.42 .42 0 0 0 .5-.1 .42 .42 0 0 0 .1-.5l-.5-.1-.2 .2M150.6 99.5l-.4 .1a.92 .92 0 0 0 0 1.2h.3l.2-.3v-.3l-.1-.2h-.4l-.2 .2M150.7 92.1h.6v.6l-.2 .1-.4-.1"/>
<path d="M150.7 94.8l.6-.1v-.7h-.6v1.2M150.7 92v1.3M151.2 97.7l.6-.1v.5l-.7 .7h.7M151.7 89.6v1l.1 .2M151.8 99.5h-.5l-.1 .6 .6-.1v.6l-.1 .2h-.4l-.1-.2M151.8 92v.8M151.8 94v.8M152.3 92l-.5 .2M152.3 94l-.5 .2M152.3 97.6l.3 1.2 .4-1.2M152.3 99.5l.3 1.3 .4-1.3M152.6 92.1h.6v.6l-.2 .1-.4-.1z"/>
<path d="M152.6 94.1h.6l-.1 .7-.5-.1zM152.9 90h-.5l-.1 .2v.4l.1 .2h.5M153.4 90l.1 .8 .5-.1M153.6 92l.7 .8M153.6 94l.7 .8M154 90v.8M154.3 92l-.7 .8M154.3 94l-.7 .8M154.4 98l.3-.1 .3 .2v.7M154.6 89.6v1.2h.1M154.7 91.6v.1M154.7 93.6v.1"/>
<path d="M154.7 92v.8M154.7 94v.8M155 98.2l-.6 .1v.4h.6M155.1 90h.6v.2v.6h-.6v-.4l.6-.1M155.3 92.1l.4-.1 .2 .2v.6M155.3 94.1l.5-.1 .1 .8M155.3 92v.8M155.3 94v.8M155.5 98.1l.2-.2 .4 .2v.7M155.5 97.9v.9M155.5 99.9v.9M155.9 92.2l.2-.2 .3 .2v.6"/>
<path d="M155.9 94.2v-.2h.4l.1 .8M156.1 90h.5M156.2 89.6v1l.1 .2h.3M156.9 90.4l.6-.1-.1-.3h-.4l-.1 .2 .1 .6h.4M157 92.1l.3-.1 .2 .2v.6M157 94h.4l.1 .2v.6h-.5v-.4l.5-.1M157.2 98h-.5l-.1 .5a.36 .36 0 0 0 .6 .2M157.2 97.6v1.2M157.2 99.5v1.3M157.5 92.3h-.4l-.2 .2 .2 .3 .4-.1M157.9 92h.5M157.9 94h.5"/>
<path d="M158.1 91.6v1.1l.3 .1M158.1 93.6v1l.3 .2M158.6 89.6v1.2h-.5l-.1-.7 .6-.1M158.6 97.9l.4-.3v1.2M158.6 99.9l.4-.4v1.3M158.6 98.8h.8M158.8 92.4l.6-.1-.1-.2h-.5v.6h.5M158.8 94.4l.6-.1-.1-.3h-.5v.8h.5M159.8 97.7l.6-.1 .1 .5-.8 .7h.8M159.8 99.6h.7v.4l-.8 .8h.8M159.9 91.6v1.1l.2 .1M159.9 93.6v1.2h.2"/>
<path d="M159.9 90h.5M160.4 89.6h-.3v1.2M160.4 92l.2 .8M160.4 94l.2 .8M160.7 90.2l.2-.2h.3l.2 .2v.4l-.2 .2h-.3l-.2-.2zM161 92l-.6 1.3M161 94l-.4 1.1-.2 .1M161.1 98.7v.1M161.9 90v.8M162.2 97.6l-.4 .1-.2 .8a.35 .35 0 0 0 .3 .3 .35 .35 0 0 0 .4-.3v-.3a.35 .35 0 0 0-.4-.2 .35 .35 0 0 0-.3 .2M162.2 99.5l-.4 .1-.2 .4 .1 .7h.5v-.7h-.5l-.1 .2M162.3 90h-.3l-.1 .2"/>
<path d="M162.4 93.7l.5-.1 .1 .2v.7l-.1 .3-.5-.1zM162.6 91.6l.4 .2v.8l-.2 .2a.75 .75 0 0 1-.2-1.2zM162.8 97.7l.6-.1v.3l-.7 .9h.7M163.4 99.5h-.6v.6l.6-.1v.7l-.5 .1-.1-.2M163.5 90l.5-.4v1.2M163.5 92.7v.1M163.5 94.7v.1M163.5 90.8h.8M164 91.6h.8l-.4 .5h.3v.6l-.5 .1-.2-.1M164 93.6h.8l-.4 .4 .4 .3-.1 .5-.7-.1M164.7 89.6h.8l-.5 1.2M164.9 97.5l-1.1 1.6"/>
<path d="M164.9 99.4l-1.1 1.6M165.1 97.6h.9l-.5 1.2M165.1 99.5h.9l-.5 1.3M165.5 92.1l-.2-.1v-.3l.4-.1 .3 .3-.7 .3v.5l.2 .1h.2l.3-.2v-.3l-.3-.2M165.9 93.6h-.6v.6l.4-.2 .3 .3-.2 .5-.5-.1M166 90.1l.4-.1 .1 .8M166 90v.8M166.3 91.6l.4 1.2 .5-1.2M166.3 93.6l.4 1.2 .5-1.2M166.5 90.2l.1-.2h.4v.8M166.7 97.5l-.3 .8h.8M166.7 99.4l-.3 1h.8"/>
<path d="M167 97.9v.9M167 99.9v.9M167.4 90.8l.4-1.2 .5 1.2M167.6 97.7l.6-.1 .1 .3-.8 .9h.8M167.6 99.6l.4-.1 .3 .4-.8 .9h.8M167.6 90.5h.6M169.7 98.1h.9M169.7 98.5h.9M170.1 89.6v1.2h-.4l-.2-.2v-.4l.2-.2h.4M170.7 90v.8M171.1 90h-.3l-.1 .2M171.4 90.2l.2-.2h.4v.8h-.4l-.2-.2z"/>
<path d="M172.2 97.9l.3-.3v1.2M172.2 99.9l.3-.4v1.3M172.2 98.8h.6M172.6 90.8h.5v-.8h-.5v1.2M173.3 97.6h.8l-.6 1.2M173.3 99.5h.8l-.6 1.3M174.5 98.1l.2-.2 .3 .1v.8M174.5 97.9v.9M174.6 90h.5l.1 .2v.6h-.6v-.4l.6-.1M175 98.1l.2-.2 .4 .2v.7M175.2 99.6a.61 .61 0 0 1 .7 .4 .61 .61 0 0 1-.3 .7 .6 .6 0 0 1-.6-.4 .6 .6 0 0 1 .2-.7zM175.6 90h.5"/>
<path d="M175.8 89.6v1.2h.3M176 98.8l.4-1.2 .4 1.2M176.1 98.4h.6M176.6 99.4l-.4 1h.8M176.8 99.9v.9M177.3 90l.5-.4v1.2M177.3 90.8h.8M177.5 99.9v.9M178.5 89.6h.8l-.4 .4 .4 .3v.3l-.2 .2-.6-.1M179.6 89.6l.4 1.2 .4-1.2M181.6 90h.5M182.1 89.6h-.3l-.1 .2v1"/>
<path d="M182.4 90.4l.6-.1-.1-.3h-.4l-.1 .2 .1 .6h.4M183.4 90.4l.6-.1v-.3h-.5l-.1 .2 .1 .6h.5M185.1 89.6v1.2h-.5v-.8h.5M135.7 100.8h.7M138.1 100.3h1M140.8 100.6v.2M144.6 100.1h1M144.6 100.5h1M147.1 100.8h.7M149.5 100.6v.2M154.4 100l.3-.1 .3 .2v.7M155 100.2l-.6 .2v.3h.6"/>
<path d="M155.5 100l.4-.1 .2 .2v.7M157.2 100a.36 .36 0 0 0-.6 .2l.1 .5h.5M158.6 100.8h.8M161.1 100.6v.2M169.7 100.1h.9M169.7 100.5h.9M172.2 100.8h.6M174.6 100.7l-.1 .3M177.5 100l.3-.1 .2 .2v.7M178 100.1l.2-.2 .3 .1v.8M178.9 100.8l.5-1.3 .4 1.3M179 100.4h.6"/>
</g>
<g fill="none" stroke="#a2a2a2" stroke-width=".21">
<path d="M127.9 78.1h.4M128.2 75.1v.9l-.1 .2-.4 .1M128.5 77.5h-.6v1.3h.6M128.8 75.7l.6-.1v-.5h-.6v1.2M129.7 77.5v1.3l-.7-1.3v1.3M130 75.4l.3-.3v1.2M130 76.3h.7M131.2 77.5v1.3h.6M131.2 75.4l.3-.3v1.2M131.2 76.3h.7M132.2 77.7l.5-.2a.86 .86 0 0 1 0 1.3 .46 .46 0 0 1-.6-.4zM133.3 78.8l.4-1.3 .4 1.3"/>
<path d="M133.5 78.4h.6M134.6 77.5a.64 .64 0 0 1 .7 .6 .64 .64 0 0 1-.7 .7zM136.7 78.1h.4M137.3 77.5h-.6v1.3h.6M137.9 78.8v-1.3l.3 .9 .4-.9v1.3M139.2 77.5v1l.3 .3 .4-.1 .1-.2v-1"/>
</g>
<g fill="none" stroke="#007170" stroke-width=".21">
<path d="M118.1 87.5v-.8l.6 .5 .1-.5h.4l.2 .3v.3l-.2 .2M118.1 85.9l.3-.3h.8l.2 .3a.68 .68 0 0 1-.6 .4 .68 .68 0 0 1-.7-.4zM118.2 88.2a.67 .67 0 0 1 .8-.2 .67 .67 0 0 1 .4 .7h-1.3zM120.6 85.8v.6l.6 .1v-.7h.5l.2 .2v.3l-.2 .2M120.6 86.8v.7M120.6 87.2h1.3M121 84.7h.9M121.2 89.3l.2-.4 .5 .3v.4h-1.3l.2-.6 .4 .1v.5M121.4 84.5v.8l-.8-.3M121.5 87.9v.5M121.9 87.8l-1.3 .4 1.3 .4M121.9 92.7l.2 .6h.9l.1-.6h-.7l-.1 .3 .2 .3"/>
<path d="M122.5 96.8v-.6l-.2-.2-.3 .1-.1 .7h1.2M123.1 95.3h-1.2l.3 .3M123.1 93.8v.7l-.7-.7h-.4v.6M123.1 94.9v.7M123.1 96l-.6 .5M127 95.5l.1 .5a.92 .92 0 0 0 1.2-.1v-.3l-.2-.2h-.4l-.2 .1v.5l.2 .1M127.1 93.2l1-.1 .2 .2a.75 .75 0 0 1-1.3 .2zM127.5 94.4l.2-.1h.4l.2 .1-.1 .5h-.4l-.3-.2v-.4h-.4v.6h.4v-.2M127.7 92.5v-.4l-.2-.3-.4 .1-.1 .6h1.3M128.3 91.8l-.6 .4M122.4 112.6l.2-.3h.3l.2 .1v.5h-.6l-.4-.6a.35 .35 0 0 0-.2 .3 .35 .35 0 0 0 .2 .4l.3-.3M122.5 106.6v-.6h-.5l-.1 .6h1.2"/>
<path d="M122.5 116.5v-.6l-.2-.1-.3 .1-.1 .6h1.2M123.1 105.1h-1.2l.3 .3M123.1 103.6v.7l-.9-.7-.3 .2 .1 .5M123.1 102.9l-1.2-.5v.8M123.1 115h-1.2l.3 .4M123.1 113.5v.8l-.7-.8h-.4v.7M123.1 106l-.6 .4M123.1 104.8v.6M123.1 114.7v.7M123.1 115.8l-.6 .4M127 114v.6l.6 .1-.1-.6 .6-.1 .2 .2v.3l-.2 .2M127.5 105.4h.8"/>
<path d="M127.7 103.6v-.5l-.2-.2h-.4l-.1 .7h1.3M127.7 113.4l-.1-.6h-.5l-.1 .6h1.3M127.9 105.2v.8l-.9-.3M128.3 104.6l-1.3-.6v.9M128.3 115.5h-1.3l.4 .4M128.3 102.9l-.6 .3M128.3 115.1v.8M128.3 112.7l-.6 .5"/>
</g>
<path d="M123.2 74.1l3.7 5.8M126.9 74.1l-3.7 5.8" fill="none" stroke="#c9c9c9" stroke-width=".42"/>
</svg>
